VERSION 5.8 ;
BUSBITCHARS "[]" ;
DIVIDERCHAR "/" ;
UNITS
    DATABASE MICRONS 1000 ;
END UNITS

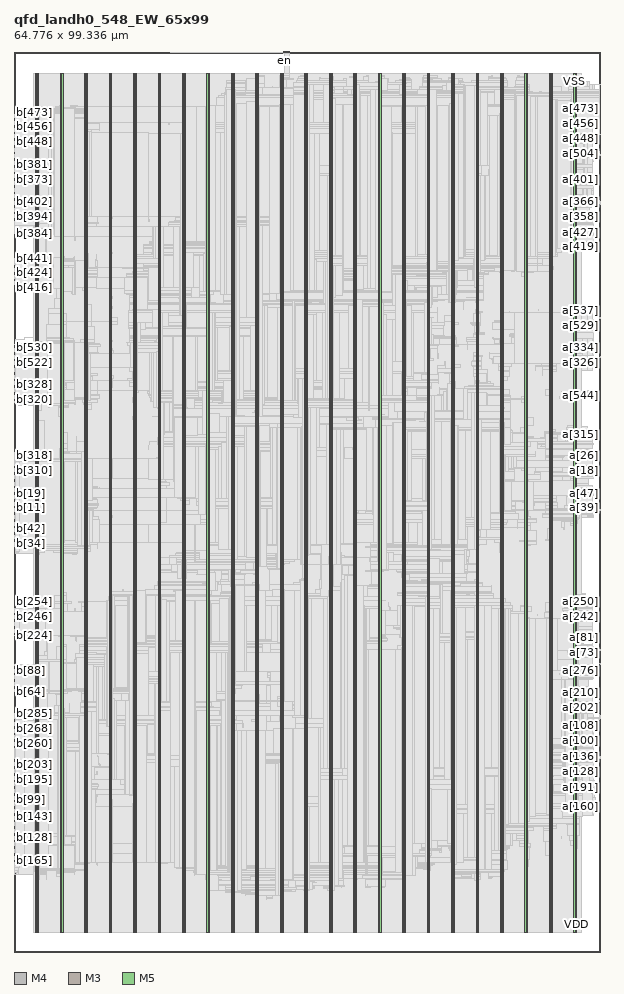
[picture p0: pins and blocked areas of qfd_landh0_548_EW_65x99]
MACRO qfd_landh0_548_EW_65x99
  FOREIGN qfd_landh0_548_EW_65x99 0 0 ;
  CLASS BLOCK ;
  SIZE 64.776 BY 99.336 ;
  PIN a[0]
    DIRECTION INPUT ;
    USE SIGNAL ;
    PORT
      LAYER M4 ;
        RECT  64.692 51.408 64.776 51.432 ;
    END
  END a[0]
  PIN a[100]
    DIRECTION INPUT ;
    USE SIGNAL ;
    PORT
      LAYER M4 ;
        RECT  64.692 23.376 64.776 23.4 ;
    END
  END a[100]
  PIN a[101]
    DIRECTION INPUT ;
    USE SIGNAL ;
    PORT
      LAYER M4 ;
        RECT  64.692 23.472 64.776 23.496 ;
    END
  END a[101]
  PIN a[102]
    DIRECTION INPUT ;
    USE SIGNAL ;
    PORT
      LAYER M4 ;
        RECT  64.692 23.568 64.776 23.592 ;
    END
  END a[102]
  PIN a[103]
    DIRECTION INPUT ;
    USE SIGNAL ;
    PORT
      LAYER M4 ;
        RECT  64.692 23.664 64.776 23.688 ;
    END
  END a[103]
  PIN a[104]
    DIRECTION INPUT ;
    USE SIGNAL ;
    PORT
      LAYER M4 ;
        RECT  64.692 23.76 64.776 23.784 ;
    END
  END a[104]
  PIN a[105]
    DIRECTION INPUT ;
    USE SIGNAL ;
    PORT
      LAYER M4 ;
        RECT  64.692 23.856 64.776 23.88 ;
    END
  END a[105]
  PIN a[106]
    DIRECTION INPUT ;
    USE SIGNAL ;
    PORT
      LAYER M4 ;
        RECT  64.692 23.952 64.776 23.976 ;
    END
  END a[106]
  PIN a[107]
    DIRECTION INPUT ;
    USE SIGNAL ;
    PORT
      LAYER M4 ;
        RECT  64.692 24.048 64.776 24.072 ;
    END
  END a[107]
  PIN a[108]
    DIRECTION INPUT ;
    USE SIGNAL ;
    PORT
      LAYER M4 ;
        RECT  64.692 24.144 64.776 24.168 ;
    END
  END a[108]
  PIN a[109]
    DIRECTION INPUT ;
    USE SIGNAL ;
    PORT
      LAYER M4 ;
        RECT  64.692 24.24 64.776 24.264 ;
    END
  END a[109]
  PIN a[10]
    DIRECTION INPUT ;
    USE SIGNAL ;
    PORT
      LAYER M4 ;
        RECT  64.692 52.368 64.776 52.392 ;
    END
  END a[10]
  PIN a[110]
    DIRECTION INPUT ;
    USE SIGNAL ;
    PORT
      LAYER M4 ;
        RECT  64.692 24.336 64.776 24.36 ;
    END
  END a[110]
  PIN a[111]
    DIRECTION INPUT ;
    USE SIGNAL ;
    PORT
      LAYER M4 ;
        RECT  64.692 24.432 64.776 24.456 ;
    END
  END a[111]
  PIN a[112]
    DIRECTION INPUT ;
    USE SIGNAL ;
    PORT
      LAYER M4 ;
        RECT  64.692 24.528 64.776 24.552 ;
    END
  END a[112]
  PIN a[113]
    DIRECTION INPUT ;
    USE SIGNAL ;
    PORT
      LAYER M4 ;
        RECT  64.692 24.624 64.776 24.648 ;
    END
  END a[113]
  PIN a[114]
    DIRECTION INPUT ;
    USE SIGNAL ;
    PORT
      LAYER M4 ;
        RECT  64.692 24.72 64.776 24.744 ;
    END
  END a[114]
  PIN a[115]
    DIRECTION INPUT ;
    USE SIGNAL ;
    PORT
      LAYER M4 ;
        RECT  64.692 24.816 64.776 24.84 ;
    END
  END a[115]
  PIN a[116]
    DIRECTION INPUT ;
    USE SIGNAL ;
    PORT
      LAYER M4 ;
        RECT  64.692 24.912 64.776 24.936 ;
    END
  END a[116]
  PIN a[117]
    DIRECTION INPUT ;
    USE SIGNAL ;
    PORT
      LAYER M4 ;
        RECT  64.692 25.008 64.776 25.032 ;
    END
  END a[117]
  PIN a[118]
    DIRECTION INPUT ;
    USE SIGNAL ;
    PORT
      LAYER M4 ;
        RECT  64.692 25.104 64.776 25.128 ;
    END
  END a[118]
  PIN a[119]
    DIRECTION INPUT ;
    USE SIGNAL ;
    PORT
      LAYER M4 ;
        RECT  64.692 25.2 64.776 25.224 ;
    END
  END a[119]
  PIN a[11]
    DIRECTION INPUT ;
    USE SIGNAL ;
    PORT
      LAYER M4 ;
        RECT  64.692 52.464 64.776 52.488 ;
    END
  END a[11]
  PIN a[120]
    DIRECTION INPUT ;
    USE SIGNAL ;
    PORT
      LAYER M4 ;
        RECT  64.692 25.296 64.776 25.32 ;
    END
  END a[120]
  PIN a[121]
    DIRECTION INPUT ;
    USE SIGNAL ;
    PORT
      LAYER M4 ;
        RECT  64.692 25.392 64.776 25.416 ;
    END
  END a[121]
  PIN a[122]
    DIRECTION INPUT ;
    USE SIGNAL ;
    PORT
      LAYER M4 ;
        RECT  64.692 25.488 64.776 25.512 ;
    END
  END a[122]
  PIN a[123]
    DIRECTION INPUT ;
    USE SIGNAL ;
    PORT
      LAYER M4 ;
        RECT  64.692 25.584 64.776 25.608 ;
    END
  END a[123]
  PIN a[124]
    DIRECTION INPUT ;
    USE SIGNAL ;
    PORT
      LAYER M4 ;
        RECT  64.692 25.68 64.776 25.704 ;
    END
  END a[124]
  PIN a[125]
    DIRECTION INPUT ;
    USE SIGNAL ;
    PORT
      LAYER M4 ;
        RECT  64.692 25.776 64.776 25.8 ;
    END
  END a[125]
  PIN a[126]
    DIRECTION INPUT ;
    USE SIGNAL ;
    PORT
      LAYER M4 ;
        RECT  64.692 25.872 64.776 25.896 ;
    END
  END a[126]
  PIN a[127]
    DIRECTION INPUT ;
    USE SIGNAL ;
    PORT
      LAYER M4 ;
        RECT  64.692 25.968 64.776 25.992 ;
    END
  END a[127]
  PIN a[128]
    DIRECTION INPUT ;
    USE SIGNAL ;
    PORT
      LAYER M4 ;
        RECT  64.692 19.92 64.776 19.944 ;
    END
  END a[128]
  PIN a[129]
    DIRECTION INPUT ;
    USE SIGNAL ;
    PORT
      LAYER M4 ;
        RECT  64.692 20.016 64.776 20.04 ;
    END
  END a[129]
  PIN a[12]
    DIRECTION INPUT ;
    USE SIGNAL ;
    PORT
      LAYER M4 ;
        RECT  64.692 52.56 64.776 52.584 ;
    END
  END a[12]
  PIN a[130]
    DIRECTION INPUT ;
    USE SIGNAL ;
    PORT
      LAYER M4 ;
        RECT  64.692 20.112 64.776 20.136 ;
    END
  END a[130]
  PIN a[131]
    DIRECTION INPUT ;
    USE SIGNAL ;
    PORT
      LAYER M4 ;
        RECT  64.692 20.208 64.776 20.232 ;
    END
  END a[131]
  PIN a[132]
    DIRECTION INPUT ;
    USE SIGNAL ;
    PORT
      LAYER M4 ;
        RECT  64.692 20.304 64.776 20.328 ;
    END
  END a[132]
  PIN a[133]
    DIRECTION INPUT ;
    USE SIGNAL ;
    PORT
      LAYER M4 ;
        RECT  64.692 20.4 64.776 20.424 ;
    END
  END a[133]
  PIN a[134]
    DIRECTION INPUT ;
    USE SIGNAL ;
    PORT
      LAYER M4 ;
        RECT  64.692 20.496 64.776 20.52 ;
    END
  END a[134]
  PIN a[135]
    DIRECTION INPUT ;
    USE SIGNAL ;
    PORT
      LAYER M4 ;
        RECT  64.692 20.592 64.776 20.616 ;
    END
  END a[135]
  PIN a[136]
    DIRECTION INPUT ;
    USE SIGNAL ;
    PORT
      LAYER M4 ;
        RECT  64.692 20.688 64.776 20.712 ;
    END
  END a[136]
  PIN a[137]
    DIRECTION INPUT ;
    USE SIGNAL ;
    PORT
      LAYER M4 ;
        RECT  64.692 20.784 64.776 20.808 ;
    END
  END a[137]
  PIN a[138]
    DIRECTION INPUT ;
    USE SIGNAL ;
    PORT
      LAYER M4 ;
        RECT  64.692 20.88 64.776 20.904 ;
    END
  END a[138]
  PIN a[139]
    DIRECTION INPUT ;
    USE SIGNAL ;
    PORT
      LAYER M4 ;
        RECT  64.692 20.976 64.776 21 ;
    END
  END a[139]
  PIN a[13]
    DIRECTION INPUT ;
    USE SIGNAL ;
    PORT
      LAYER M4 ;
        RECT  64.692 52.656 64.776 52.68 ;
    END
  END a[13]
  PIN a[140]
    DIRECTION INPUT ;
    USE SIGNAL ;
    PORT
      LAYER M4 ;
        RECT  64.692 21.072 64.776 21.096 ;
    END
  END a[140]
  PIN a[141]
    DIRECTION INPUT ;
    USE SIGNAL ;
    PORT
      LAYER M4 ;
        RECT  64.692 21.168 64.776 21.192 ;
    END
  END a[141]
  PIN a[142]
    DIRECTION INPUT ;
    USE SIGNAL ;
    PORT
      LAYER M4 ;
        RECT  64.692 21.264 64.776 21.288 ;
    END
  END a[142]
  PIN a[143]
    DIRECTION INPUT ;
    USE SIGNAL ;
    PORT
      LAYER M4 ;
        RECT  64.692 21.36 64.776 21.384 ;
    END
  END a[143]
  PIN a[144]
    DIRECTION INPUT ;
    USE SIGNAL ;
    PORT
      LAYER M4 ;
        RECT  64.692 21.456 64.776 21.48 ;
    END
  END a[144]
  PIN a[145]
    DIRECTION INPUT ;
    USE SIGNAL ;
    PORT
      LAYER M4 ;
        RECT  64.692 21.552 64.776 21.576 ;
    END
  END a[145]
  PIN a[146]
    DIRECTION INPUT ;
    USE SIGNAL ;
    PORT
      LAYER M4 ;
        RECT  64.692 21.648 64.776 21.672 ;
    END
  END a[146]
  PIN a[147]
    DIRECTION INPUT ;
    USE SIGNAL ;
    PORT
      LAYER M4 ;
        RECT  64.692 21.744 64.776 21.768 ;
    END
  END a[147]
  PIN a[148]
    DIRECTION INPUT ;
    USE SIGNAL ;
    PORT
      LAYER M4 ;
        RECT  64.692 21.84 64.776 21.864 ;
    END
  END a[148]
  PIN a[149]
    DIRECTION INPUT ;
    USE SIGNAL ;
    PORT
      LAYER M4 ;
        RECT  64.692 21.936 64.776 21.96 ;
    END
  END a[149]
  PIN a[14]
    DIRECTION INPUT ;
    USE SIGNAL ;
    PORT
      LAYER M4 ;
        RECT  64.692 52.752 64.776 52.776 ;
    END
  END a[14]
  PIN a[150]
    DIRECTION INPUT ;
    USE SIGNAL ;
    PORT
      LAYER M4 ;
        RECT  64.692 22.032 64.776 22.056 ;
    END
  END a[150]
  PIN a[151]
    DIRECTION INPUT ;
    USE SIGNAL ;
    PORT
      LAYER M4 ;
        RECT  64.692 22.128 64.776 22.152 ;
    END
  END a[151]
  PIN a[152]
    DIRECTION INPUT ;
    USE SIGNAL ;
    PORT
      LAYER M4 ;
        RECT  64.692 22.224 64.776 22.248 ;
    END
  END a[152]
  PIN a[153]
    DIRECTION INPUT ;
    USE SIGNAL ;
    PORT
      LAYER M4 ;
        RECT  64.692 22.32 64.776 22.344 ;
    END
  END a[153]
  PIN a[154]
    DIRECTION INPUT ;
    USE SIGNAL ;
    PORT
      LAYER M4 ;
        RECT  64.692 22.416 64.776 22.44 ;
    END
  END a[154]
  PIN a[155]
    DIRECTION INPUT ;
    USE SIGNAL ;
    PORT
      LAYER M4 ;
        RECT  64.692 22.512 64.776 22.536 ;
    END
  END a[155]
  PIN a[156]
    DIRECTION INPUT ;
    USE SIGNAL ;
    PORT
      LAYER M4 ;
        RECT  64.692 22.608 64.776 22.632 ;
    END
  END a[156]
  PIN a[157]
    DIRECTION INPUT ;
    USE SIGNAL ;
    PORT
      LAYER M4 ;
        RECT  64.692 22.704 64.776 22.728 ;
    END
  END a[157]
  PIN a[158]
    DIRECTION INPUT ;
    USE SIGNAL ;
    PORT
      LAYER M4 ;
        RECT  64.692 22.8 64.776 22.824 ;
    END
  END a[158]
  PIN a[159]
    DIRECTION INPUT ;
    USE SIGNAL ;
    PORT
      LAYER M4 ;
        RECT  64.692 22.896 64.776 22.92 ;
    END
  END a[159]
  PIN a[15]
    DIRECTION INPUT ;
    USE SIGNAL ;
    PORT
      LAYER M4 ;
        RECT  64.692 52.848 64.776 52.872 ;
    END
  END a[15]
  PIN a[160]
    DIRECTION INPUT ;
    USE SIGNAL ;
    PORT
      LAYER M4 ;
        RECT  64.692 16.08 64.776 16.104 ;
    END
  END a[160]
  PIN a[161]
    DIRECTION INPUT ;
    USE SIGNAL ;
    PORT
      LAYER M4 ;
        RECT  64.692 16.176 64.776 16.2 ;
    END
  END a[161]
  PIN a[162]
    DIRECTION INPUT ;
    USE SIGNAL ;
    PORT
      LAYER M4 ;
        RECT  64.692 16.272 64.776 16.296 ;
    END
  END a[162]
  PIN a[163]
    DIRECTION INPUT ;
    USE SIGNAL ;
    PORT
      LAYER M4 ;
        RECT  64.692 16.368 64.776 16.392 ;
    END
  END a[163]
  PIN a[164]
    DIRECTION INPUT ;
    USE SIGNAL ;
    PORT
      LAYER M4 ;
        RECT  64.692 16.464 64.776 16.488 ;
    END
  END a[164]
  PIN a[165]
    DIRECTION INPUT ;
    USE SIGNAL ;
    PORT
      LAYER M4 ;
        RECT  64.692 16.56 64.776 16.584 ;
    END
  END a[165]
  PIN a[166]
    DIRECTION INPUT ;
    USE SIGNAL ;
    PORT
      LAYER M4 ;
        RECT  64.692 16.656 64.776 16.68 ;
    END
  END a[166]
  PIN a[167]
    DIRECTION INPUT ;
    USE SIGNAL ;
    PORT
      LAYER M4 ;
        RECT  64.692 16.752 64.776 16.776 ;
    END
  END a[167]
  PIN a[168]
    DIRECTION INPUT ;
    USE SIGNAL ;
    PORT
      LAYER M4 ;
        RECT  64.692 16.848 64.776 16.872 ;
    END
  END a[168]
  PIN a[169]
    DIRECTION INPUT ;
    USE SIGNAL ;
    PORT
      LAYER M4 ;
        RECT  64.692 16.944 64.776 16.968 ;
    END
  END a[169]
  PIN a[16]
    DIRECTION INPUT ;
    USE SIGNAL ;
    PORT
      LAYER M4 ;
        RECT  64.692 52.944 64.776 52.968 ;
    END
  END a[16]
  PIN a[170]
    DIRECTION INPUT ;
    USE SIGNAL ;
    PORT
      LAYER M4 ;
        RECT  64.692 17.04 64.776 17.064 ;
    END
  END a[170]
  PIN a[171]
    DIRECTION INPUT ;
    USE SIGNAL ;
    PORT
      LAYER M4 ;
        RECT  64.692 17.136 64.776 17.16 ;
    END
  END a[171]
  PIN a[172]
    DIRECTION INPUT ;
    USE SIGNAL ;
    PORT
      LAYER M4 ;
        RECT  64.692 17.232 64.776 17.256 ;
    END
  END a[172]
  PIN a[173]
    DIRECTION INPUT ;
    USE SIGNAL ;
    PORT
      LAYER M4 ;
        RECT  64.692 17.328 64.776 17.352 ;
    END
  END a[173]
  PIN a[174]
    DIRECTION INPUT ;
    USE SIGNAL ;
    PORT
      LAYER M4 ;
        RECT  64.692 17.424 64.776 17.448 ;
    END
  END a[174]
  PIN a[175]
    DIRECTION INPUT ;
    USE SIGNAL ;
    PORT
      LAYER M4 ;
        RECT  64.692 17.52 64.776 17.544 ;
    END
  END a[175]
  PIN a[176]
    DIRECTION INPUT ;
    USE SIGNAL ;
    PORT
      LAYER M4 ;
        RECT  64.692 17.616 64.776 17.64 ;
    END
  END a[176]
  PIN a[177]
    DIRECTION INPUT ;
    USE SIGNAL ;
    PORT
      LAYER M4 ;
        RECT  64.692 17.712 64.776 17.736 ;
    END
  END a[177]
  PIN a[178]
    DIRECTION INPUT ;
    USE SIGNAL ;
    PORT
      LAYER M4 ;
        RECT  64.692 17.808 64.776 17.832 ;
    END
  END a[178]
  PIN a[179]
    DIRECTION INPUT ;
    USE SIGNAL ;
    PORT
      LAYER M4 ;
        RECT  64.692 17.904 64.776 17.928 ;
    END
  END a[179]
  PIN a[17]
    DIRECTION INPUT ;
    USE SIGNAL ;
    PORT
      LAYER M4 ;
        RECT  64.692 53.04 64.776 53.064 ;
    END
  END a[17]
  PIN a[180]
    DIRECTION INPUT ;
    USE SIGNAL ;
    PORT
      LAYER M4 ;
        RECT  64.692 18 64.776 18.024 ;
    END
  END a[180]
  PIN a[181]
    DIRECTION INPUT ;
    USE SIGNAL ;
    PORT
      LAYER M4 ;
        RECT  64.692 18.096 64.776 18.12 ;
    END
  END a[181]
  PIN a[182]
    DIRECTION INPUT ;
    USE SIGNAL ;
    PORT
      LAYER M4 ;
        RECT  64.692 18.192 64.776 18.216 ;
    END
  END a[182]
  PIN a[183]
    DIRECTION INPUT ;
    USE SIGNAL ;
    PORT
      LAYER M4 ;
        RECT  64.692 18.288 64.776 18.312 ;
    END
  END a[183]
  PIN a[184]
    DIRECTION INPUT ;
    USE SIGNAL ;
    PORT
      LAYER M4 ;
        RECT  64.692 18.384 64.776 18.408 ;
    END
  END a[184]
  PIN a[185]
    DIRECTION INPUT ;
    USE SIGNAL ;
    PORT
      LAYER M4 ;
        RECT  64.692 18.48 64.776 18.504 ;
    END
  END a[185]
  PIN a[186]
    DIRECTION INPUT ;
    USE SIGNAL ;
    PORT
      LAYER M4 ;
        RECT  64.692 18.576 64.776 18.6 ;
    END
  END a[186]
  PIN a[187]
    DIRECTION INPUT ;
    USE SIGNAL ;
    PORT
      LAYER M4 ;
        RECT  64.692 18.672 64.776 18.696 ;
    END
  END a[187]
  PIN a[188]
    DIRECTION INPUT ;
    USE SIGNAL ;
    PORT
      LAYER M4 ;
        RECT  64.692 18.768 64.776 18.792 ;
    END
  END a[188]
  PIN a[189]
    DIRECTION INPUT ;
    USE SIGNAL ;
    PORT
      LAYER M4 ;
        RECT  64.692 18.864 64.776 18.888 ;
    END
  END a[189]
  PIN a[18]
    DIRECTION INPUT ;
    USE SIGNAL ;
    PORT
      LAYER M4 ;
        RECT  64.692 53.136 64.776 53.16 ;
    END
  END a[18]
  PIN a[190]
    DIRECTION INPUT ;
    USE SIGNAL ;
    PORT
      LAYER M4 ;
        RECT  64.692 18.96 64.776 18.984 ;
    END
  END a[190]
  PIN a[191]
    DIRECTION INPUT ;
    USE SIGNAL ;
    PORT
      LAYER M4 ;
        RECT  64.692 19.056 64.776 19.08 ;
    END
  END a[191]
  PIN a[192]
    DIRECTION INPUT ;
    USE SIGNAL ;
    PORT
      LAYER M4 ;
        RECT  64.692 26.064 64.776 26.088 ;
    END
  END a[192]
  PIN a[193]
    DIRECTION INPUT ;
    USE SIGNAL ;
    PORT
      LAYER M4 ;
        RECT  64.692 26.16 64.776 26.184 ;
    END
  END a[193]
  PIN a[194]
    DIRECTION INPUT ;
    USE SIGNAL ;
    PORT
      LAYER M4 ;
        RECT  64.692 26.256 64.776 26.28 ;
    END
  END a[194]
  PIN a[195]
    DIRECTION INPUT ;
    USE SIGNAL ;
    PORT
      LAYER M4 ;
        RECT  64.692 26.352 64.776 26.376 ;
    END
  END a[195]
  PIN a[196]
    DIRECTION INPUT ;
    USE SIGNAL ;
    PORT
      LAYER M4 ;
        RECT  64.692 26.448 64.776 26.472 ;
    END
  END a[196]
  PIN a[197]
    DIRECTION INPUT ;
    USE SIGNAL ;
    PORT
      LAYER M4 ;
        RECT  64.692 26.544 64.776 26.568 ;
    END
  END a[197]
  PIN a[198]
    DIRECTION INPUT ;
    USE SIGNAL ;
    PORT
      LAYER M4 ;
        RECT  64.692 26.64 64.776 26.664 ;
    END
  END a[198]
  PIN a[199]
    DIRECTION INPUT ;
    USE SIGNAL ;
    PORT
      LAYER M4 ;
        RECT  64.692 26.736 64.776 26.76 ;
    END
  END a[199]
  PIN a[19]
    DIRECTION INPUT ;
    USE SIGNAL ;
    PORT
      LAYER M4 ;
        RECT  64.692 53.232 64.776 53.256 ;
    END
  END a[19]
  PIN a[1]
    DIRECTION INPUT ;
    USE SIGNAL ;
    PORT
      LAYER M4 ;
        RECT  64.692 51.504 64.776 51.528 ;
    END
  END a[1]
  PIN a[200]
    DIRECTION INPUT ;
    USE SIGNAL ;
    PORT
      LAYER M4 ;
        RECT  64.692 26.832 64.776 26.856 ;
    END
  END a[200]
  PIN a[201]
    DIRECTION INPUT ;
    USE SIGNAL ;
    PORT
      LAYER M4 ;
        RECT  64.692 26.928 64.776 26.952 ;
    END
  END a[201]
  PIN a[202]
    DIRECTION INPUT ;
    USE SIGNAL ;
    PORT
      LAYER M4 ;
        RECT  64.692 27.024 64.776 27.048 ;
    END
  END a[202]
  PIN a[203]
    DIRECTION INPUT ;
    USE SIGNAL ;
    PORT
      LAYER M4 ;
        RECT  64.692 27.12 64.776 27.144 ;
    END
  END a[203]
  PIN a[204]
    DIRECTION INPUT ;
    USE SIGNAL ;
    PORT
      LAYER M4 ;
        RECT  64.692 27.216 64.776 27.24 ;
    END
  END a[204]
  PIN a[205]
    DIRECTION INPUT ;
    USE SIGNAL ;
    PORT
      LAYER M4 ;
        RECT  64.692 27.312 64.776 27.336 ;
    END
  END a[205]
  PIN a[206]
    DIRECTION INPUT ;
    USE SIGNAL ;
    PORT
      LAYER M4 ;
        RECT  64.692 27.408 64.776 27.432 ;
    END
  END a[206]
  PIN a[207]
    DIRECTION INPUT ;
    USE SIGNAL ;
    PORT
      LAYER M4 ;
        RECT  64.692 27.504 64.776 27.528 ;
    END
  END a[207]
  PIN a[208]
    DIRECTION INPUT ;
    USE SIGNAL ;
    PORT
      LAYER M4 ;
        RECT  64.692 27.6 64.776 27.624 ;
    END
  END a[208]
  PIN a[209]
    DIRECTION INPUT ;
    USE SIGNAL ;
    PORT
      LAYER M4 ;
        RECT  64.692 27.696 64.776 27.72 ;
    END
  END a[209]
  PIN a[20]
    DIRECTION INPUT ;
    USE SIGNAL ;
    PORT
      LAYER M4 ;
        RECT  64.692 53.328 64.776 53.352 ;
    END
  END a[20]
  PIN a[210]
    DIRECTION INPUT ;
    USE SIGNAL ;
    PORT
      LAYER M4 ;
        RECT  64.692 27.792 64.776 27.816 ;
    END
  END a[210]
  PIN a[211]
    DIRECTION INPUT ;
    USE SIGNAL ;
    PORT
      LAYER M4 ;
        RECT  64.692 27.888 64.776 27.912 ;
    END
  END a[211]
  PIN a[212]
    DIRECTION INPUT ;
    USE SIGNAL ;
    PORT
      LAYER M4 ;
        RECT  64.692 27.984 64.776 28.008 ;
    END
  END a[212]
  PIN a[213]
    DIRECTION INPUT ;
    USE SIGNAL ;
    PORT
      LAYER M4 ;
        RECT  64.692 28.08 64.776 28.104 ;
    END
  END a[213]
  PIN a[214]
    DIRECTION INPUT ;
    USE SIGNAL ;
    PORT
      LAYER M4 ;
        RECT  64.692 28.176 64.776 28.2 ;
    END
  END a[214]
  PIN a[215]
    DIRECTION INPUT ;
    USE SIGNAL ;
    PORT
      LAYER M4 ;
        RECT  64.692 28.272 64.776 28.296 ;
    END
  END a[215]
  PIN a[216]
    DIRECTION INPUT ;
    USE SIGNAL ;
    PORT
      LAYER M4 ;
        RECT  64.692 28.368 64.776 28.392 ;
    END
  END a[216]
  PIN a[217]
    DIRECTION INPUT ;
    USE SIGNAL ;
    PORT
      LAYER M4 ;
        RECT  64.692 28.464 64.776 28.488 ;
    END
  END a[217]
  PIN a[218]
    DIRECTION INPUT ;
    USE SIGNAL ;
    PORT
      LAYER M4 ;
        RECT  64.692 28.56 64.776 28.584 ;
    END
  END a[218]
  PIN a[219]
    DIRECTION INPUT ;
    USE SIGNAL ;
    PORT
      LAYER M4 ;
        RECT  64.692 28.656 64.776 28.68 ;
    END
  END a[219]
  PIN a[21]
    DIRECTION INPUT ;
    USE SIGNAL ;
    PORT
      LAYER M4 ;
        RECT  64.692 53.424 64.776 53.448 ;
    END
  END a[21]
  PIN a[220]
    DIRECTION INPUT ;
    USE SIGNAL ;
    PORT
      LAYER M4 ;
        RECT  64.692 28.752 64.776 28.776 ;
    END
  END a[220]
  PIN a[221]
    DIRECTION INPUT ;
    USE SIGNAL ;
    PORT
      LAYER M4 ;
        RECT  64.692 28.848 64.776 28.872 ;
    END
  END a[221]
  PIN a[222]
    DIRECTION INPUT ;
    USE SIGNAL ;
    PORT
      LAYER M4 ;
        RECT  64.692 28.944 64.776 28.968 ;
    END
  END a[222]
  PIN a[223]
    DIRECTION INPUT ;
    USE SIGNAL ;
    PORT
      LAYER M4 ;
        RECT  64.692 29.04 64.776 29.064 ;
    END
  END a[223]
  PIN a[224]
    DIRECTION INPUT ;
    USE SIGNAL ;
    PORT
      LAYER M4 ;
        RECT  64.692 35.28 64.776 35.304 ;
    END
  END a[224]
  PIN a[225]
    DIRECTION INPUT ;
    USE SIGNAL ;
    PORT
      LAYER M4 ;
        RECT  64.692 35.376 64.776 35.4 ;
    END
  END a[225]
  PIN a[226]
    DIRECTION INPUT ;
    USE SIGNAL ;
    PORT
      LAYER M4 ;
        RECT  64.692 35.472 64.776 35.496 ;
    END
  END a[226]
  PIN a[227]
    DIRECTION INPUT ;
    USE SIGNAL ;
    PORT
      LAYER M4 ;
        RECT  64.692 35.568 64.776 35.592 ;
    END
  END a[227]
  PIN a[228]
    DIRECTION INPUT ;
    USE SIGNAL ;
    PORT
      LAYER M4 ;
        RECT  64.692 35.664 64.776 35.688 ;
    END
  END a[228]
  PIN a[229]
    DIRECTION INPUT ;
    USE SIGNAL ;
    PORT
      LAYER M4 ;
        RECT  64.692 35.76 64.776 35.784 ;
    END
  END a[229]
  PIN a[22]
    DIRECTION INPUT ;
    USE SIGNAL ;
    PORT
      LAYER M4 ;
        RECT  64.692 53.52 64.776 53.544 ;
    END
  END a[22]
  PIN a[230]
    DIRECTION INPUT ;
    USE SIGNAL ;
    PORT
      LAYER M4 ;
        RECT  64.692 35.856 64.776 35.88 ;
    END
  END a[230]
  PIN a[231]
    DIRECTION INPUT ;
    USE SIGNAL ;
    PORT
      LAYER M4 ;
        RECT  64.692 35.952 64.776 35.976 ;
    END
  END a[231]
  PIN a[232]
    DIRECTION INPUT ;
    USE SIGNAL ;
    PORT
      LAYER M4 ;
        RECT  64.692 36.048 64.776 36.072 ;
    END
  END a[232]
  PIN a[233]
    DIRECTION INPUT ;
    USE SIGNAL ;
    PORT
      LAYER M4 ;
        RECT  64.692 36.144 64.776 36.168 ;
    END
  END a[233]
  PIN a[234]
    DIRECTION INPUT ;
    USE SIGNAL ;
    PORT
      LAYER M4 ;
        RECT  64.692 36.24 64.776 36.264 ;
    END
  END a[234]
  PIN a[235]
    DIRECTION INPUT ;
    USE SIGNAL ;
    PORT
      LAYER M4 ;
        RECT  64.692 36.336 64.776 36.36 ;
    END
  END a[235]
  PIN a[236]
    DIRECTION INPUT ;
    USE SIGNAL ;
    PORT
      LAYER M4 ;
        RECT  64.692 36.432 64.776 36.456 ;
    END
  END a[236]
  PIN a[237]
    DIRECTION INPUT ;
    USE SIGNAL ;
    PORT
      LAYER M4 ;
        RECT  64.692 36.528 64.776 36.552 ;
    END
  END a[237]
  PIN a[238]
    DIRECTION INPUT ;
    USE SIGNAL ;
    PORT
      LAYER M4 ;
        RECT  64.692 36.624 64.776 36.648 ;
    END
  END a[238]
  PIN a[239]
    DIRECTION INPUT ;
    USE SIGNAL ;
    PORT
      LAYER M4 ;
        RECT  64.692 36.72 64.776 36.744 ;
    END
  END a[239]
  PIN a[23]
    DIRECTION INPUT ;
    USE SIGNAL ;
    PORT
      LAYER M4 ;
        RECT  64.692 53.616 64.776 53.64 ;
    END
  END a[23]
  PIN a[240]
    DIRECTION INPUT ;
    USE SIGNAL ;
    PORT
      LAYER M4 ;
        RECT  64.692 36.816 64.776 36.84 ;
    END
  END a[240]
  PIN a[241]
    DIRECTION INPUT ;
    USE SIGNAL ;
    PORT
      LAYER M4 ;
        RECT  64.692 36.912 64.776 36.936 ;
    END
  END a[241]
  PIN a[242]
    DIRECTION INPUT ;
    USE SIGNAL ;
    PORT
      LAYER M4 ;
        RECT  64.692 37.008 64.776 37.032 ;
    END
  END a[242]
  PIN a[243]
    DIRECTION INPUT ;
    USE SIGNAL ;
    PORT
      LAYER M4 ;
        RECT  64.692 37.104 64.776 37.128 ;
    END
  END a[243]
  PIN a[244]
    DIRECTION INPUT ;
    USE SIGNAL ;
    PORT
      LAYER M4 ;
        RECT  64.692 37.2 64.776 37.224 ;
    END
  END a[244]
  PIN a[245]
    DIRECTION INPUT ;
    USE SIGNAL ;
    PORT
      LAYER M4 ;
        RECT  64.692 37.296 64.776 37.32 ;
    END
  END a[245]
  PIN a[246]
    DIRECTION INPUT ;
    USE SIGNAL ;
    PORT
      LAYER M4 ;
        RECT  64.692 37.392 64.776 37.416 ;
    END
  END a[246]
  PIN a[247]
    DIRECTION INPUT ;
    USE SIGNAL ;
    PORT
      LAYER M4 ;
        RECT  64.692 37.488 64.776 37.512 ;
    END
  END a[247]
  PIN a[248]
    DIRECTION INPUT ;
    USE SIGNAL ;
    PORT
      LAYER M4 ;
        RECT  64.692 37.584 64.776 37.608 ;
    END
  END a[248]
  PIN a[249]
    DIRECTION INPUT ;
    USE SIGNAL ;
    PORT
      LAYER M4 ;
        RECT  64.692 37.68 64.776 37.704 ;
    END
  END a[249]
  PIN a[24]
    DIRECTION INPUT ;
    USE SIGNAL ;
    PORT
      LAYER M4 ;
        RECT  64.692 53.712 64.776 53.736 ;
    END
  END a[24]
  PIN a[250]
    DIRECTION INPUT ;
    USE SIGNAL ;
    PORT
      LAYER M4 ;
        RECT  64.692 37.776 64.776 37.8 ;
    END
  END a[250]
  PIN a[251]
    DIRECTION INPUT ;
    USE SIGNAL ;
    PORT
      LAYER M4 ;
        RECT  64.692 37.872 64.776 37.896 ;
    END
  END a[251]
  PIN a[252]
    DIRECTION INPUT ;
    USE SIGNAL ;
    PORT
      LAYER M4 ;
        RECT  64.692 37.968 64.776 37.992 ;
    END
  END a[252]
  PIN a[253]
    DIRECTION INPUT ;
    USE SIGNAL ;
    PORT
      LAYER M4 ;
        RECT  64.692 38.064 64.776 38.088 ;
    END
  END a[253]
  PIN a[254]
    DIRECTION INPUT ;
    USE SIGNAL ;
    PORT
      LAYER M4 ;
        RECT  64.692 38.16 64.776 38.184 ;
    END
  END a[254]
  PIN a[255]
    DIRECTION INPUT ;
    USE SIGNAL ;
    PORT
      LAYER M4 ;
        RECT  64.692 38.256 64.776 38.28 ;
    END
  END a[255]
  PIN a[256]
    DIRECTION INPUT ;
    USE SIGNAL ;
    PORT
      LAYER M4 ;
        RECT  64.692 29.136 64.776 29.16 ;
    END
  END a[256]
  PIN a[257]
    DIRECTION INPUT ;
    USE SIGNAL ;
    PORT
      LAYER M4 ;
        RECT  64.692 29.232 64.776 29.256 ;
    END
  END a[257]
  PIN a[258]
    DIRECTION INPUT ;
    USE SIGNAL ;
    PORT
      LAYER M4 ;
        RECT  64.692 29.328 64.776 29.352 ;
    END
  END a[258]
  PIN a[259]
    DIRECTION INPUT ;
    USE SIGNAL ;
    PORT
      LAYER M4 ;
        RECT  64.692 29.424 64.776 29.448 ;
    END
  END a[259]
  PIN a[25]
    DIRECTION INPUT ;
    USE SIGNAL ;
    PORT
      LAYER M4 ;
        RECT  64.692 53.808 64.776 53.832 ;
    END
  END a[25]
  PIN a[260]
    DIRECTION INPUT ;
    USE SIGNAL ;
    PORT
      LAYER M4 ;
        RECT  64.692 29.52 64.776 29.544 ;
    END
  END a[260]
  PIN a[261]
    DIRECTION INPUT ;
    USE SIGNAL ;
    PORT
      LAYER M4 ;
        RECT  64.692 29.616 64.776 29.64 ;
    END
  END a[261]
  PIN a[262]
    DIRECTION INPUT ;
    USE SIGNAL ;
    PORT
      LAYER M4 ;
        RECT  64.692 29.712 64.776 29.736 ;
    END
  END a[262]
  PIN a[263]
    DIRECTION INPUT ;
    USE SIGNAL ;
    PORT
      LAYER M4 ;
        RECT  64.692 29.808 64.776 29.832 ;
    END
  END a[263]
  PIN a[264]
    DIRECTION INPUT ;
    USE SIGNAL ;
    PORT
      LAYER M4 ;
        RECT  64.692 29.904 64.776 29.928 ;
    END
  END a[264]
  PIN a[265]
    DIRECTION INPUT ;
    USE SIGNAL ;
    PORT
      LAYER M4 ;
        RECT  64.692 30 64.776 30.024 ;
    END
  END a[265]
  PIN a[266]
    DIRECTION INPUT ;
    USE SIGNAL ;
    PORT
      LAYER M4 ;
        RECT  64.692 30.096 64.776 30.12 ;
    END
  END a[266]
  PIN a[267]
    DIRECTION INPUT ;
    USE SIGNAL ;
    PORT
      LAYER M4 ;
        RECT  64.692 30.192 64.776 30.216 ;
    END
  END a[267]
  PIN a[268]
    DIRECTION INPUT ;
    USE SIGNAL ;
    PORT
      LAYER M4 ;
        RECT  64.692 30.288 64.776 30.312 ;
    END
  END a[268]
  PIN a[269]
    DIRECTION INPUT ;
    USE SIGNAL ;
    PORT
      LAYER M4 ;
        RECT  64.692 30.384 64.776 30.408 ;
    END
  END a[269]
  PIN a[26]
    DIRECTION INPUT ;
    USE SIGNAL ;
    PORT
      LAYER M4 ;
        RECT  64.692 53.904 64.776 53.928 ;
    END
  END a[26]
  PIN a[270]
    DIRECTION INPUT ;
    USE SIGNAL ;
    PORT
      LAYER M4 ;
        RECT  64.692 30.48 64.776 30.504 ;
    END
  END a[270]
  PIN a[271]
    DIRECTION INPUT ;
    USE SIGNAL ;
    PORT
      LAYER M4 ;
        RECT  64.692 30.576 64.776 30.6 ;
    END
  END a[271]
  PIN a[272]
    DIRECTION INPUT ;
    USE SIGNAL ;
    PORT
      LAYER M4 ;
        RECT  64.692 30.672 64.776 30.696 ;
    END
  END a[272]
  PIN a[273]
    DIRECTION INPUT ;
    USE SIGNAL ;
    PORT
      LAYER M4 ;
        RECT  64.692 30.768 64.776 30.792 ;
    END
  END a[273]
  PIN a[274]
    DIRECTION INPUT ;
    USE SIGNAL ;
    PORT
      LAYER M4 ;
        RECT  64.692 30.864 64.776 30.888 ;
    END
  END a[274]
  PIN a[275]
    DIRECTION INPUT ;
    USE SIGNAL ;
    PORT
      LAYER M4 ;
        RECT  64.692 30.96 64.776 30.984 ;
    END
  END a[275]
  PIN a[276]
    DIRECTION INPUT ;
    USE SIGNAL ;
    PORT
      LAYER M4 ;
        RECT  64.692 31.056 64.776 31.08 ;
    END
  END a[276]
  PIN a[277]
    DIRECTION INPUT ;
    USE SIGNAL ;
    PORT
      LAYER M4 ;
        RECT  64.692 31.152 64.776 31.176 ;
    END
  END a[277]
  PIN a[278]
    DIRECTION INPUT ;
    USE SIGNAL ;
    PORT
      LAYER M4 ;
        RECT  64.692 31.248 64.776 31.272 ;
    END
  END a[278]
  PIN a[279]
    DIRECTION INPUT ;
    USE SIGNAL ;
    PORT
      LAYER M4 ;
        RECT  64.692 31.344 64.776 31.368 ;
    END
  END a[279]
  PIN a[27]
    DIRECTION INPUT ;
    USE SIGNAL ;
    PORT
      LAYER M4 ;
        RECT  64.692 54 64.776 54.024 ;
    END
  END a[27]
  PIN a[280]
    DIRECTION INPUT ;
    USE SIGNAL ;
    PORT
      LAYER M4 ;
        RECT  64.692 31.44 64.776 31.464 ;
    END
  END a[280]
  PIN a[281]
    DIRECTION INPUT ;
    USE SIGNAL ;
    PORT
      LAYER M4 ;
        RECT  64.692 31.536 64.776 31.56 ;
    END
  END a[281]
  PIN a[282]
    DIRECTION INPUT ;
    USE SIGNAL ;
    PORT
      LAYER M4 ;
        RECT  64.692 31.632 64.776 31.656 ;
    END
  END a[282]
  PIN a[283]
    DIRECTION INPUT ;
    USE SIGNAL ;
    PORT
      LAYER M4 ;
        RECT  64.692 31.728 64.776 31.752 ;
    END
  END a[283]
  PIN a[284]
    DIRECTION INPUT ;
    USE SIGNAL ;
    PORT
      LAYER M4 ;
        RECT  64.692 31.824 64.776 31.848 ;
    END
  END a[284]
  PIN a[285]
    DIRECTION INPUT ;
    USE SIGNAL ;
    PORT
      LAYER M4 ;
        RECT  64.692 31.92 64.776 31.944 ;
    END
  END a[285]
  PIN a[286]
    DIRECTION INPUT ;
    USE SIGNAL ;
    PORT
      LAYER M4 ;
        RECT  64.692 32.016 64.776 32.04 ;
    END
  END a[286]
  PIN a[287]
    DIRECTION INPUT ;
    USE SIGNAL ;
    PORT
      LAYER M4 ;
        RECT  64.692 32.112 64.776 32.136 ;
    END
  END a[287]
  PIN a[288]
    DIRECTION INPUT ;
    USE SIGNAL ;
    PORT
      LAYER M4 ;
        RECT  64.692 54.48 64.776 54.504 ;
    END
  END a[288]
  PIN a[289]
    DIRECTION INPUT ;
    USE SIGNAL ;
    PORT
      LAYER M4 ;
        RECT  64.692 54.576 64.776 54.6 ;
    END
  END a[289]
  PIN a[28]
    DIRECTION INPUT ;
    USE SIGNAL ;
    PORT
      LAYER M4 ;
        RECT  64.692 54.096 64.776 54.12 ;
    END
  END a[28]
  PIN a[290]
    DIRECTION INPUT ;
    USE SIGNAL ;
    PORT
      LAYER M4 ;
        RECT  64.692 54.672 64.776 54.696 ;
    END
  END a[290]
  PIN a[291]
    DIRECTION INPUT ;
    USE SIGNAL ;
    PORT
      LAYER M4 ;
        RECT  64.692 54.768 64.776 54.792 ;
    END
  END a[291]
  PIN a[292]
    DIRECTION INPUT ;
    USE SIGNAL ;
    PORT
      LAYER M4 ;
        RECT  64.692 54.864 64.776 54.888 ;
    END
  END a[292]
  PIN a[293]
    DIRECTION INPUT ;
    USE SIGNAL ;
    PORT
      LAYER M4 ;
        RECT  64.692 54.96 64.776 54.984 ;
    END
  END a[293]
  PIN a[294]
    DIRECTION INPUT ;
    USE SIGNAL ;
    PORT
      LAYER M4 ;
        RECT  64.692 55.056 64.776 55.08 ;
    END
  END a[294]
  PIN a[295]
    DIRECTION INPUT ;
    USE SIGNAL ;
    PORT
      LAYER M4 ;
        RECT  64.692 55.152 64.776 55.176 ;
    END
  END a[295]
  PIN a[296]
    DIRECTION INPUT ;
    USE SIGNAL ;
    PORT
      LAYER M4 ;
        RECT  64.692 55.248 64.776 55.272 ;
    END
  END a[296]
  PIN a[297]
    DIRECTION INPUT ;
    USE SIGNAL ;
    PORT
      LAYER M4 ;
        RECT  64.692 55.344 64.776 55.368 ;
    END
  END a[297]
  PIN a[298]
    DIRECTION INPUT ;
    USE SIGNAL ;
    PORT
      LAYER M4 ;
        RECT  64.692 55.44 64.776 55.464 ;
    END
  END a[298]
  PIN a[299]
    DIRECTION INPUT ;
    USE SIGNAL ;
    PORT
      LAYER M4 ;
        RECT  64.692 55.536 64.776 55.56 ;
    END
  END a[299]
  PIN a[29]
    DIRECTION INPUT ;
    USE SIGNAL ;
    PORT
      LAYER M4 ;
        RECT  64.692 54.192 64.776 54.216 ;
    END
  END a[29]
  PIN a[2]
    DIRECTION INPUT ;
    USE SIGNAL ;
    PORT
      LAYER M4 ;
        RECT  64.692 51.6 64.776 51.624 ;
    END
  END a[2]
  PIN a[300]
    DIRECTION INPUT ;
    USE SIGNAL ;
    PORT
      LAYER M4 ;
        RECT  64.692 55.632 64.776 55.656 ;
    END
  END a[300]
  PIN a[301]
    DIRECTION INPUT ;
    USE SIGNAL ;
    PORT
      LAYER M4 ;
        RECT  64.692 55.728 64.776 55.752 ;
    END
  END a[301]
  PIN a[302]
    DIRECTION INPUT ;
    USE SIGNAL ;
    PORT
      LAYER M4 ;
        RECT  64.692 55.824 64.776 55.848 ;
    END
  END a[302]
  PIN a[303]
    DIRECTION INPUT ;
    USE SIGNAL ;
    PORT
      LAYER M4 ;
        RECT  64.692 55.92 64.776 55.944 ;
    END
  END a[303]
  PIN a[304]
    DIRECTION INPUT ;
    USE SIGNAL ;
    PORT
      LAYER M4 ;
        RECT  64.692 56.016 64.776 56.04 ;
    END
  END a[304]
  PIN a[305]
    DIRECTION INPUT ;
    USE SIGNAL ;
    PORT
      LAYER M4 ;
        RECT  64.692 56.112 64.776 56.136 ;
    END
  END a[305]
  PIN a[306]
    DIRECTION INPUT ;
    USE SIGNAL ;
    PORT
      LAYER M4 ;
        RECT  64.692 56.208 64.776 56.232 ;
    END
  END a[306]
  PIN a[307]
    DIRECTION INPUT ;
    USE SIGNAL ;
    PORT
      LAYER M4 ;
        RECT  64.692 56.304 64.776 56.328 ;
    END
  END a[307]
  PIN a[308]
    DIRECTION INPUT ;
    USE SIGNAL ;
    PORT
      LAYER M4 ;
        RECT  64.692 56.4 64.776 56.424 ;
    END
  END a[308]
  PIN a[309]
    DIRECTION INPUT ;
    USE SIGNAL ;
    PORT
      LAYER M4 ;
        RECT  64.692 56.496 64.776 56.52 ;
    END
  END a[309]
  PIN a[30]
    DIRECTION INPUT ;
    USE SIGNAL ;
    PORT
      LAYER M4 ;
        RECT  64.692 54.288 64.776 54.312 ;
    END
  END a[30]
  PIN a[310]
    DIRECTION INPUT ;
    USE SIGNAL ;
    PORT
      LAYER M4 ;
        RECT  64.692 56.592 64.776 56.616 ;
    END
  END a[310]
  PIN a[311]
    DIRECTION INPUT ;
    USE SIGNAL ;
    PORT
      LAYER M4 ;
        RECT  64.692 56.688 64.776 56.712 ;
    END
  END a[311]
  PIN a[312]
    DIRECTION INPUT ;
    USE SIGNAL ;
    PORT
      LAYER M4 ;
        RECT  64.692 56.784 64.776 56.808 ;
    END
  END a[312]
  PIN a[313]
    DIRECTION INPUT ;
    USE SIGNAL ;
    PORT
      LAYER M4 ;
        RECT  64.692 56.88 64.776 56.904 ;
    END
  END a[313]
  PIN a[314]
    DIRECTION INPUT ;
    USE SIGNAL ;
    PORT
      LAYER M4 ;
        RECT  64.692 56.976 64.776 57 ;
    END
  END a[314]
  PIN a[315]
    DIRECTION INPUT ;
    USE SIGNAL ;
    PORT
      LAYER M4 ;
        RECT  64.692 57.072 64.776 57.096 ;
    END
  END a[315]
  PIN a[316]
    DIRECTION INPUT ;
    USE SIGNAL ;
    PORT
      LAYER M4 ;
        RECT  64.692 57.168 64.776 57.192 ;
    END
  END a[316]
  PIN a[317]
    DIRECTION INPUT ;
    USE SIGNAL ;
    PORT
      LAYER M4 ;
        RECT  64.692 57.264 64.776 57.288 ;
    END
  END a[317]
  PIN a[318]
    DIRECTION INPUT ;
    USE SIGNAL ;
    PORT
      LAYER M4 ;
        RECT  64.692 57.36 64.776 57.384 ;
    END
  END a[318]
  PIN a[319]
    DIRECTION INPUT ;
    USE SIGNAL ;
    PORT
      LAYER M4 ;
        RECT  64.692 57.456 64.776 57.48 ;
    END
  END a[319]
  PIN a[31]
    DIRECTION INPUT ;
    USE SIGNAL ;
    PORT
      LAYER M4 ;
        RECT  64.692 54.384 64.776 54.408 ;
    END
  END a[31]
  PIN a[320]
    DIRECTION INPUT ;
    USE SIGNAL ;
    PORT
      LAYER M4 ;
        RECT  64.692 64.464 64.776 64.488 ;
    END
  END a[320]
  PIN a[321]
    DIRECTION INPUT ;
    USE SIGNAL ;
    PORT
      LAYER M4 ;
        RECT  64.692 64.56 64.776 64.584 ;
    END
  END a[321]
  PIN a[322]
    DIRECTION INPUT ;
    USE SIGNAL ;
    PORT
      LAYER M4 ;
        RECT  64.692 64.656 64.776 64.68 ;
    END
  END a[322]
  PIN a[323]
    DIRECTION INPUT ;
    USE SIGNAL ;
    PORT
      LAYER M4 ;
        RECT  64.692 64.752 64.776 64.776 ;
    END
  END a[323]
  PIN a[324]
    DIRECTION INPUT ;
    USE SIGNAL ;
    PORT
      LAYER M4 ;
        RECT  64.692 64.848 64.776 64.872 ;
    END
  END a[324]
  PIN a[325]
    DIRECTION INPUT ;
    USE SIGNAL ;
    PORT
      LAYER M4 ;
        RECT  64.692 64.944 64.776 64.968 ;
    END
  END a[325]
  PIN a[326]
    DIRECTION INPUT ;
    USE SIGNAL ;
    PORT
      LAYER M4 ;
        RECT  64.692 65.04 64.776 65.064 ;
    END
  END a[326]
  PIN a[327]
    DIRECTION INPUT ;
    USE SIGNAL ;
    PORT
      LAYER M4 ;
        RECT  64.692 65.136 64.776 65.16 ;
    END
  END a[327]
  PIN a[328]
    DIRECTION INPUT ;
    USE SIGNAL ;
    PORT
      LAYER M4 ;
        RECT  64.692 65.232 64.776 65.256 ;
    END
  END a[328]
  PIN a[329]
    DIRECTION INPUT ;
    USE SIGNAL ;
    PORT
      LAYER M4 ;
        RECT  64.692 65.328 64.776 65.352 ;
    END
  END a[329]
  PIN a[32]
    DIRECTION INPUT ;
    USE SIGNAL ;
    PORT
      LAYER M4 ;
        RECT  64.692 48.336 64.776 48.36 ;
    END
  END a[32]
  PIN a[330]
    DIRECTION INPUT ;
    USE SIGNAL ;
    PORT
      LAYER M4 ;
        RECT  64.692 65.424 64.776 65.448 ;
    END
  END a[330]
  PIN a[331]
    DIRECTION INPUT ;
    USE SIGNAL ;
    PORT
      LAYER M4 ;
        RECT  64.692 65.52 64.776 65.544 ;
    END
  END a[331]
  PIN a[332]
    DIRECTION INPUT ;
    USE SIGNAL ;
    PORT
      LAYER M4 ;
        RECT  64.692 65.616 64.776 65.64 ;
    END
  END a[332]
  PIN a[333]
    DIRECTION INPUT ;
    USE SIGNAL ;
    PORT
      LAYER M4 ;
        RECT  64.692 65.712 64.776 65.736 ;
    END
  END a[333]
  PIN a[334]
    DIRECTION INPUT ;
    USE SIGNAL ;
    PORT
      LAYER M4 ;
        RECT  64.692 65.808 64.776 65.832 ;
    END
  END a[334]
  PIN a[335]
    DIRECTION INPUT ;
    USE SIGNAL ;
    PORT
      LAYER M4 ;
        RECT  64.692 65.904 64.776 65.928 ;
    END
  END a[335]
  PIN a[336]
    DIRECTION INPUT ;
    USE SIGNAL ;
    PORT
      LAYER M4 ;
        RECT  64.692 66 64.776 66.024 ;
    END
  END a[336]
  PIN a[337]
    DIRECTION INPUT ;
    USE SIGNAL ;
    PORT
      LAYER M4 ;
        RECT  64.692 66.096 64.776 66.12 ;
    END
  END a[337]
  PIN a[338]
    DIRECTION INPUT ;
    USE SIGNAL ;
    PORT
      LAYER M4 ;
        RECT  64.692 66.192 64.776 66.216 ;
    END
  END a[338]
  PIN a[339]
    DIRECTION INPUT ;
    USE SIGNAL ;
    PORT
      LAYER M4 ;
        RECT  64.692 66.288 64.776 66.312 ;
    END
  END a[339]
  PIN a[33]
    DIRECTION INPUT ;
    USE SIGNAL ;
    PORT
      LAYER M4 ;
        RECT  64.692 48.432 64.776 48.456 ;
    END
  END a[33]
  PIN a[340]
    DIRECTION INPUT ;
    USE SIGNAL ;
    PORT
      LAYER M4 ;
        RECT  64.692 66.384 64.776 66.408 ;
    END
  END a[340]
  PIN a[341]
    DIRECTION INPUT ;
    USE SIGNAL ;
    PORT
      LAYER M4 ;
        RECT  64.692 66.48 64.776 66.504 ;
    END
  END a[341]
  PIN a[342]
    DIRECTION INPUT ;
    USE SIGNAL ;
    PORT
      LAYER M4 ;
        RECT  64.692 66.576 64.776 66.6 ;
    END
  END a[342]
  PIN a[343]
    DIRECTION INPUT ;
    USE SIGNAL ;
    PORT
      LAYER M4 ;
        RECT  64.692 66.672 64.776 66.696 ;
    END
  END a[343]
  PIN a[344]
    DIRECTION INPUT ;
    USE SIGNAL ;
    PORT
      LAYER M4 ;
        RECT  64.692 66.768 64.776 66.792 ;
    END
  END a[344]
  PIN a[345]
    DIRECTION INPUT ;
    USE SIGNAL ;
    PORT
      LAYER M4 ;
        RECT  64.692 66.864 64.776 66.888 ;
    END
  END a[345]
  PIN a[346]
    DIRECTION INPUT ;
    USE SIGNAL ;
    PORT
      LAYER M4 ;
        RECT  64.692 66.96 64.776 66.984 ;
    END
  END a[346]
  PIN a[347]
    DIRECTION INPUT ;
    USE SIGNAL ;
    PORT
      LAYER M4 ;
        RECT  64.692 67.056 64.776 67.08 ;
    END
  END a[347]
  PIN a[348]
    DIRECTION INPUT ;
    USE SIGNAL ;
    PORT
      LAYER M4 ;
        RECT  64.692 67.152 64.776 67.176 ;
    END
  END a[348]
  PIN a[349]
    DIRECTION INPUT ;
    USE SIGNAL ;
    PORT
      LAYER M4 ;
        RECT  64.692 67.248 64.776 67.272 ;
    END
  END a[349]
  PIN a[34]
    DIRECTION INPUT ;
    USE SIGNAL ;
    PORT
      LAYER M4 ;
        RECT  64.692 48.528 64.776 48.552 ;
    END
  END a[34]
  PIN a[350]
    DIRECTION INPUT ;
    USE SIGNAL ;
    PORT
      LAYER M4 ;
        RECT  64.692 67.344 64.776 67.368 ;
    END
  END a[350]
  PIN a[351]
    DIRECTION INPUT ;
    USE SIGNAL ;
    PORT
      LAYER M4 ;
        RECT  64.692 67.44 64.776 67.464 ;
    END
  END a[351]
  PIN a[352]
    DIRECTION INPUT ;
    USE SIGNAL ;
    PORT
      LAYER M4 ;
        RECT  64.692 80.592 64.776 80.616 ;
    END
  END a[352]
  PIN a[353]
    DIRECTION INPUT ;
    USE SIGNAL ;
    PORT
      LAYER M4 ;
        RECT  64.692 80.688 64.776 80.712 ;
    END
  END a[353]
  PIN a[354]
    DIRECTION INPUT ;
    USE SIGNAL ;
    PORT
      LAYER M4 ;
        RECT  64.692 80.784 64.776 80.808 ;
    END
  END a[354]
  PIN a[355]
    DIRECTION INPUT ;
    USE SIGNAL ;
    PORT
      LAYER M4 ;
        RECT  64.692 80.88 64.776 80.904 ;
    END
  END a[355]
  PIN a[356]
    DIRECTION INPUT ;
    USE SIGNAL ;
    PORT
      LAYER M4 ;
        RECT  64.692 80.976 64.776 81 ;
    END
  END a[356]
  PIN a[357]
    DIRECTION INPUT ;
    USE SIGNAL ;
    PORT
      LAYER M4 ;
        RECT  64.692 81.072 64.776 81.096 ;
    END
  END a[357]
  PIN a[358]
    DIRECTION INPUT ;
    USE SIGNAL ;
    PORT
      LAYER M4 ;
        RECT  64.692 81.168 64.776 81.192 ;
    END
  END a[358]
  PIN a[359]
    DIRECTION INPUT ;
    USE SIGNAL ;
    PORT
      LAYER M4 ;
        RECT  64.692 81.264 64.776 81.288 ;
    END
  END a[359]
  PIN a[35]
    DIRECTION INPUT ;
    USE SIGNAL ;
    PORT
      LAYER M4 ;
        RECT  64.692 48.624 64.776 48.648 ;
    END
  END a[35]
  PIN a[360]
    DIRECTION INPUT ;
    USE SIGNAL ;
    PORT
      LAYER M4 ;
        RECT  64.692 81.36 64.776 81.384 ;
    END
  END a[360]
  PIN a[361]
    DIRECTION INPUT ;
    USE SIGNAL ;
    PORT
      LAYER M4 ;
        RECT  64.692 81.456 64.776 81.48 ;
    END
  END a[361]
  PIN a[362]
    DIRECTION INPUT ;
    USE SIGNAL ;
    PORT
      LAYER M4 ;
        RECT  64.692 81.552 64.776 81.576 ;
    END
  END a[362]
  PIN a[363]
    DIRECTION INPUT ;
    USE SIGNAL ;
    PORT
      LAYER M4 ;
        RECT  64.692 81.648 64.776 81.672 ;
    END
  END a[363]
  PIN a[364]
    DIRECTION INPUT ;
    USE SIGNAL ;
    PORT
      LAYER M4 ;
        RECT  64.692 81.744 64.776 81.768 ;
    END
  END a[364]
  PIN a[365]
    DIRECTION INPUT ;
    USE SIGNAL ;
    PORT
      LAYER M4 ;
        RECT  64.692 81.84 64.776 81.864 ;
    END
  END a[365]
  PIN a[366]
    DIRECTION INPUT ;
    USE SIGNAL ;
    PORT
      LAYER M4 ;
        RECT  64.692 81.936 64.776 81.96 ;
    END
  END a[366]
  PIN a[367]
    DIRECTION INPUT ;
    USE SIGNAL ;
    PORT
      LAYER M4 ;
        RECT  64.692 82.032 64.776 82.056 ;
    END
  END a[367]
  PIN a[368]
    DIRECTION INPUT ;
    USE SIGNAL ;
    PORT
      LAYER M4 ;
        RECT  64.692 82.128 64.776 82.152 ;
    END
  END a[368]
  PIN a[369]
    DIRECTION INPUT ;
    USE SIGNAL ;
    PORT
      LAYER M4 ;
        RECT  64.692 82.224 64.776 82.248 ;
    END
  END a[369]
  PIN a[36]
    DIRECTION INPUT ;
    USE SIGNAL ;
    PORT
      LAYER M4 ;
        RECT  64.692 48.72 64.776 48.744 ;
    END
  END a[36]
  PIN a[370]
    DIRECTION INPUT ;
    USE SIGNAL ;
    PORT
      LAYER M4 ;
        RECT  64.692 82.32 64.776 82.344 ;
    END
  END a[370]
  PIN a[371]
    DIRECTION INPUT ;
    USE SIGNAL ;
    PORT
      LAYER M4 ;
        RECT  64.692 82.416 64.776 82.44 ;
    END
  END a[371]
  PIN a[372]
    DIRECTION INPUT ;
    USE SIGNAL ;
    PORT
      LAYER M4 ;
        RECT  64.692 82.512 64.776 82.536 ;
    END
  END a[372]
  PIN a[373]
    DIRECTION INPUT ;
    USE SIGNAL ;
    PORT
      LAYER M4 ;
        RECT  64.692 82.608 64.776 82.632 ;
    END
  END a[373]
  PIN a[374]
    DIRECTION INPUT ;
    USE SIGNAL ;
    PORT
      LAYER M4 ;
        RECT  64.692 82.704 64.776 82.728 ;
    END
  END a[374]
  PIN a[375]
    DIRECTION INPUT ;
    USE SIGNAL ;
    PORT
      LAYER M4 ;
        RECT  64.692 82.8 64.776 82.824 ;
    END
  END a[375]
  PIN a[376]
    DIRECTION INPUT ;
    USE SIGNAL ;
    PORT
      LAYER M4 ;
        RECT  64.692 82.896 64.776 82.92 ;
    END
  END a[376]
  PIN a[377]
    DIRECTION INPUT ;
    USE SIGNAL ;
    PORT
      LAYER M4 ;
        RECT  64.692 82.992 64.776 83.016 ;
    END
  END a[377]
  PIN a[378]
    DIRECTION INPUT ;
    USE SIGNAL ;
    PORT
      LAYER M4 ;
        RECT  64.692 83.088 64.776 83.112 ;
    END
  END a[378]
  PIN a[379]
    DIRECTION INPUT ;
    USE SIGNAL ;
    PORT
      LAYER M4 ;
        RECT  64.692 83.184 64.776 83.208 ;
    END
  END a[379]
  PIN a[37]
    DIRECTION INPUT ;
    USE SIGNAL ;
    PORT
      LAYER M4 ;
        RECT  64.692 48.816 64.776 48.84 ;
    END
  END a[37]
  PIN a[380]
    DIRECTION INPUT ;
    USE SIGNAL ;
    PORT
      LAYER M4 ;
        RECT  64.692 83.28 64.776 83.304 ;
    END
  END a[380]
  PIN a[381]
    DIRECTION INPUT ;
    USE SIGNAL ;
    PORT
      LAYER M4 ;
        RECT  64.692 83.376 64.776 83.4 ;
    END
  END a[381]
  PIN a[382]
    DIRECTION INPUT ;
    USE SIGNAL ;
    PORT
      LAYER M4 ;
        RECT  64.692 83.472 64.776 83.496 ;
    END
  END a[382]
  PIN a[383]
    DIRECTION INPUT ;
    USE SIGNAL ;
    PORT
      LAYER M4 ;
        RECT  64.692 83.568 64.776 83.592 ;
    END
  END a[383]
  PIN a[384]
    DIRECTION INPUT ;
    USE SIGNAL ;
    PORT
      LAYER M4 ;
        RECT  64.692 83.664 64.776 83.688 ;
    END
  END a[384]
  PIN a[385]
    DIRECTION INPUT ;
    USE SIGNAL ;
    PORT
      LAYER M4 ;
        RECT  64.692 83.76 64.776 83.784 ;
    END
  END a[385]
  PIN a[386]
    DIRECTION INPUT ;
    USE SIGNAL ;
    PORT
      LAYER M4 ;
        RECT  64.692 83.856 64.776 83.88 ;
    END
  END a[386]
  PIN a[387]
    DIRECTION INPUT ;
    USE SIGNAL ;
    PORT
      LAYER M4 ;
        RECT  64.692 83.952 64.776 83.976 ;
    END
  END a[387]
  PIN a[388]
    DIRECTION INPUT ;
    USE SIGNAL ;
    PORT
      LAYER M4 ;
        RECT  64.692 84.048 64.776 84.072 ;
    END
  END a[388]
  PIN a[389]
    DIRECTION INPUT ;
    USE SIGNAL ;
    PORT
      LAYER M4 ;
        RECT  64.692 84.144 64.776 84.168 ;
    END
  END a[389]
  PIN a[38]
    DIRECTION INPUT ;
    USE SIGNAL ;
    PORT
      LAYER M4 ;
        RECT  64.692 48.912 64.776 48.936 ;
    END
  END a[38]
  PIN a[390]
    DIRECTION INPUT ;
    USE SIGNAL ;
    PORT
      LAYER M4 ;
        RECT  64.692 84.24 64.776 84.264 ;
    END
  END a[390]
  PIN a[391]
    DIRECTION INPUT ;
    USE SIGNAL ;
    PORT
      LAYER M4 ;
        RECT  64.692 84.336 64.776 84.36 ;
    END
  END a[391]
  PIN a[392]
    DIRECTION INPUT ;
    USE SIGNAL ;
    PORT
      LAYER M4 ;
        RECT  64.692 84.432 64.776 84.456 ;
    END
  END a[392]
  PIN a[393]
    DIRECTION INPUT ;
    USE SIGNAL ;
    PORT
      LAYER M4 ;
        RECT  64.692 84.528 64.776 84.552 ;
    END
  END a[393]
  PIN a[394]
    DIRECTION INPUT ;
    USE SIGNAL ;
    PORT
      LAYER M4 ;
        RECT  64.692 84.624 64.776 84.648 ;
    END
  END a[394]
  PIN a[395]
    DIRECTION INPUT ;
    USE SIGNAL ;
    PORT
      LAYER M4 ;
        RECT  64.692 84.72 64.776 84.744 ;
    END
  END a[395]
  PIN a[396]
    DIRECTION INPUT ;
    USE SIGNAL ;
    PORT
      LAYER M4 ;
        RECT  64.692 84.816 64.776 84.84 ;
    END
  END a[396]
  PIN a[397]
    DIRECTION INPUT ;
    USE SIGNAL ;
    PORT
      LAYER M4 ;
        RECT  64.692 84.912 64.776 84.936 ;
    END
  END a[397]
  PIN a[398]
    DIRECTION INPUT ;
    USE SIGNAL ;
    PORT
      LAYER M4 ;
        RECT  64.692 85.008 64.776 85.032 ;
    END
  END a[398]
  PIN a[399]
    DIRECTION INPUT ;
    USE SIGNAL ;
    PORT
      LAYER M4 ;
        RECT  64.692 85.104 64.776 85.128 ;
    END
  END a[399]
  PIN a[39]
    DIRECTION INPUT ;
    USE SIGNAL ;
    PORT
      LAYER M4 ;
        RECT  64.692 49.008 64.776 49.032 ;
    END
  END a[39]
  PIN a[3]
    DIRECTION INPUT ;
    USE SIGNAL ;
    PORT
      LAYER M4 ;
        RECT  64.692 51.696 64.776 51.72 ;
    END
  END a[3]
  PIN a[400]
    DIRECTION INPUT ;
    USE SIGNAL ;
    PORT
      LAYER M4 ;
        RECT  64.692 85.2 64.776 85.224 ;
    END
  END a[400]
  PIN a[401]
    DIRECTION INPUT ;
    USE SIGNAL ;
    PORT
      LAYER M4 ;
        RECT  64.692 85.296 64.776 85.32 ;
    END
  END a[401]
  PIN a[402]
    DIRECTION INPUT ;
    USE SIGNAL ;
    PORT
      LAYER M4 ;
        RECT  64.692 85.392 64.776 85.416 ;
    END
  END a[402]
  PIN a[403]
    DIRECTION INPUT ;
    USE SIGNAL ;
    PORT
      LAYER M4 ;
        RECT  64.692 85.488 64.776 85.512 ;
    END
  END a[403]
  PIN a[404]
    DIRECTION INPUT ;
    USE SIGNAL ;
    PORT
      LAYER M4 ;
        RECT  64.692 85.584 64.776 85.608 ;
    END
  END a[404]
  PIN a[405]
    DIRECTION INPUT ;
    USE SIGNAL ;
    PORT
      LAYER M4 ;
        RECT  64.692 85.68 64.776 85.704 ;
    END
  END a[405]
  PIN a[406]
    DIRECTION INPUT ;
    USE SIGNAL ;
    PORT
      LAYER M4 ;
        RECT  64.692 85.776 64.776 85.8 ;
    END
  END a[406]
  PIN a[407]
    DIRECTION INPUT ;
    USE SIGNAL ;
    PORT
      LAYER M4 ;
        RECT  64.692 85.872 64.776 85.896 ;
    END
  END a[407]
  PIN a[408]
    DIRECTION INPUT ;
    USE SIGNAL ;
    PORT
      LAYER M4 ;
        RECT  64.692 85.968 64.776 85.992 ;
    END
  END a[408]
  PIN a[409]
    DIRECTION INPUT ;
    USE SIGNAL ;
    PORT
      LAYER M4 ;
        RECT  64.692 86.064 64.776 86.088 ;
    END
  END a[409]
  PIN a[40]
    DIRECTION INPUT ;
    USE SIGNAL ;
    PORT
      LAYER M4 ;
        RECT  64.692 49.104 64.776 49.128 ;
    END
  END a[40]
  PIN a[410]
    DIRECTION INPUT ;
    USE SIGNAL ;
    PORT
      LAYER M4 ;
        RECT  64.692 86.16 64.776 86.184 ;
    END
  END a[410]
  PIN a[411]
    DIRECTION INPUT ;
    USE SIGNAL ;
    PORT
      LAYER M4 ;
        RECT  64.692 86.256 64.776 86.28 ;
    END
  END a[411]
  PIN a[412]
    DIRECTION INPUT ;
    USE SIGNAL ;
    PORT
      LAYER M4 ;
        RECT  64.692 86.352 64.776 86.376 ;
    END
  END a[412]
  PIN a[413]
    DIRECTION INPUT ;
    USE SIGNAL ;
    PORT
      LAYER M4 ;
        RECT  64.692 86.448 64.776 86.472 ;
    END
  END a[413]
  PIN a[414]
    DIRECTION INPUT ;
    USE SIGNAL ;
    PORT
      LAYER M4 ;
        RECT  64.692 86.544 64.776 86.568 ;
    END
  END a[414]
  PIN a[415]
    DIRECTION INPUT ;
    USE SIGNAL ;
    PORT
      LAYER M4 ;
        RECT  64.692 86.64 64.776 86.664 ;
    END
  END a[415]
  PIN a[416]
    DIRECTION INPUT ;
    USE SIGNAL ;
    PORT
      LAYER M4 ;
        RECT  64.692 77.52 64.776 77.544 ;
    END
  END a[416]
  PIN a[417]
    DIRECTION INPUT ;
    USE SIGNAL ;
    PORT
      LAYER M4 ;
        RECT  64.692 77.616 64.776 77.64 ;
    END
  END a[417]
  PIN a[418]
    DIRECTION INPUT ;
    USE SIGNAL ;
    PORT
      LAYER M4 ;
        RECT  64.692 77.712 64.776 77.736 ;
    END
  END a[418]
  PIN a[419]
    DIRECTION INPUT ;
    USE SIGNAL ;
    PORT
      LAYER M4 ;
        RECT  64.692 77.808 64.776 77.832 ;
    END
  END a[419]
  PIN a[41]
    DIRECTION INPUT ;
    USE SIGNAL ;
    PORT
      LAYER M4 ;
        RECT  64.692 49.2 64.776 49.224 ;
    END
  END a[41]
  PIN a[420]
    DIRECTION INPUT ;
    USE SIGNAL ;
    PORT
      LAYER M4 ;
        RECT  64.692 77.904 64.776 77.928 ;
    END
  END a[420]
  PIN a[421]
    DIRECTION INPUT ;
    USE SIGNAL ;
    PORT
      LAYER M4 ;
        RECT  64.692 78 64.776 78.024 ;
    END
  END a[421]
  PIN a[422]
    DIRECTION INPUT ;
    USE SIGNAL ;
    PORT
      LAYER M4 ;
        RECT  64.692 78.096 64.776 78.12 ;
    END
  END a[422]
  PIN a[423]
    DIRECTION INPUT ;
    USE SIGNAL ;
    PORT
      LAYER M4 ;
        RECT  64.692 78.192 64.776 78.216 ;
    END
  END a[423]
  PIN a[424]
    DIRECTION INPUT ;
    USE SIGNAL ;
    PORT
      LAYER M4 ;
        RECT  64.692 78.288 64.776 78.312 ;
    END
  END a[424]
  PIN a[425]
    DIRECTION INPUT ;
    USE SIGNAL ;
    PORT
      LAYER M4 ;
        RECT  64.692 78.384 64.776 78.408 ;
    END
  END a[425]
  PIN a[426]
    DIRECTION INPUT ;
    USE SIGNAL ;
    PORT
      LAYER M4 ;
        RECT  64.692 78.48 64.776 78.504 ;
    END
  END a[426]
  PIN a[427]
    DIRECTION INPUT ;
    USE SIGNAL ;
    PORT
      LAYER M4 ;
        RECT  64.692 78.576 64.776 78.6 ;
    END
  END a[427]
  PIN a[428]
    DIRECTION INPUT ;
    USE SIGNAL ;
    PORT
      LAYER M4 ;
        RECT  64.692 78.672 64.776 78.696 ;
    END
  END a[428]
  PIN a[429]
    DIRECTION INPUT ;
    USE SIGNAL ;
    PORT
      LAYER M4 ;
        RECT  64.692 78.768 64.776 78.792 ;
    END
  END a[429]
  PIN a[42]
    DIRECTION INPUT ;
    USE SIGNAL ;
    PORT
      LAYER M4 ;
        RECT  64.692 49.296 64.776 49.32 ;
    END
  END a[42]
  PIN a[430]
    DIRECTION INPUT ;
    USE SIGNAL ;
    PORT
      LAYER M4 ;
        RECT  64.692 78.864 64.776 78.888 ;
    END
  END a[430]
  PIN a[431]
    DIRECTION INPUT ;
    USE SIGNAL ;
    PORT
      LAYER M4 ;
        RECT  64.692 78.96 64.776 78.984 ;
    END
  END a[431]
  PIN a[432]
    DIRECTION INPUT ;
    USE SIGNAL ;
    PORT
      LAYER M4 ;
        RECT  64.692 79.056 64.776 79.08 ;
    END
  END a[432]
  PIN a[433]
    DIRECTION INPUT ;
    USE SIGNAL ;
    PORT
      LAYER M4 ;
        RECT  64.692 79.152 64.776 79.176 ;
    END
  END a[433]
  PIN a[434]
    DIRECTION INPUT ;
    USE SIGNAL ;
    PORT
      LAYER M4 ;
        RECT  64.692 79.248 64.776 79.272 ;
    END
  END a[434]
  PIN a[435]
    DIRECTION INPUT ;
    USE SIGNAL ;
    PORT
      LAYER M4 ;
        RECT  64.692 79.344 64.776 79.368 ;
    END
  END a[435]
  PIN a[436]
    DIRECTION INPUT ;
    USE SIGNAL ;
    PORT
      LAYER M4 ;
        RECT  64.692 79.44 64.776 79.464 ;
    END
  END a[436]
  PIN a[437]
    DIRECTION INPUT ;
    USE SIGNAL ;
    PORT
      LAYER M4 ;
        RECT  64.692 79.536 64.776 79.56 ;
    END
  END a[437]
  PIN a[438]
    DIRECTION INPUT ;
    USE SIGNAL ;
    PORT
      LAYER M4 ;
        RECT  64.692 79.632 64.776 79.656 ;
    END
  END a[438]
  PIN a[439]
    DIRECTION INPUT ;
    USE SIGNAL ;
    PORT
      LAYER M4 ;
        RECT  64.692 79.728 64.776 79.752 ;
    END
  END a[439]
  PIN a[43]
    DIRECTION INPUT ;
    USE SIGNAL ;
    PORT
      LAYER M4 ;
        RECT  64.692 49.392 64.776 49.416 ;
    END
  END a[43]
  PIN a[440]
    DIRECTION INPUT ;
    USE SIGNAL ;
    PORT
      LAYER M4 ;
        RECT  64.692 79.824 64.776 79.848 ;
    END
  END a[440]
  PIN a[441]
    DIRECTION INPUT ;
    USE SIGNAL ;
    PORT
      LAYER M4 ;
        RECT  64.692 79.92 64.776 79.944 ;
    END
  END a[441]
  PIN a[442]
    DIRECTION INPUT ;
    USE SIGNAL ;
    PORT
      LAYER M4 ;
        RECT  64.692 80.016 64.776 80.04 ;
    END
  END a[442]
  PIN a[443]
    DIRECTION INPUT ;
    USE SIGNAL ;
    PORT
      LAYER M4 ;
        RECT  64.692 80.112 64.776 80.136 ;
    END
  END a[443]
  PIN a[444]
    DIRECTION INPUT ;
    USE SIGNAL ;
    PORT
      LAYER M4 ;
        RECT  64.692 80.208 64.776 80.232 ;
    END
  END a[444]
  PIN a[445]
    DIRECTION INPUT ;
    USE SIGNAL ;
    PORT
      LAYER M4 ;
        RECT  64.692 80.304 64.776 80.328 ;
    END
  END a[445]
  PIN a[446]
    DIRECTION INPUT ;
    USE SIGNAL ;
    PORT
      LAYER M4 ;
        RECT  64.692 80.4 64.776 80.424 ;
    END
  END a[446]
  PIN a[447]
    DIRECTION INPUT ;
    USE SIGNAL ;
    PORT
      LAYER M4 ;
        RECT  64.692 80.496 64.776 80.52 ;
    END
  END a[447]
  PIN a[448]
    DIRECTION INPUT ;
    USE SIGNAL ;
    PORT
      LAYER M4 ;
        RECT  64.692 89.808 64.776 89.832 ;
    END
  END a[448]
  PIN a[449]
    DIRECTION INPUT ;
    USE SIGNAL ;
    PORT
      LAYER M4 ;
        RECT  64.692 89.904 64.776 89.928 ;
    END
  END a[449]
  PIN a[44]
    DIRECTION INPUT ;
    USE SIGNAL ;
    PORT
      LAYER M4 ;
        RECT  64.692 49.488 64.776 49.512 ;
    END
  END a[44]
  PIN a[450]
    DIRECTION INPUT ;
    USE SIGNAL ;
    PORT
      LAYER M4 ;
        RECT  64.692 90 64.776 90.024 ;
    END
  END a[450]
  PIN a[451]
    DIRECTION INPUT ;
    USE SIGNAL ;
    PORT
      LAYER M4 ;
        RECT  64.692 90.096 64.776 90.12 ;
    END
  END a[451]
  PIN a[452]
    DIRECTION INPUT ;
    USE SIGNAL ;
    PORT
      LAYER M4 ;
        RECT  64.692 90.192 64.776 90.216 ;
    END
  END a[452]
  PIN a[453]
    DIRECTION INPUT ;
    USE SIGNAL ;
    PORT
      LAYER M4 ;
        RECT  64.692 90.288 64.776 90.312 ;
    END
  END a[453]
  PIN a[454]
    DIRECTION INPUT ;
    USE SIGNAL ;
    PORT
      LAYER M4 ;
        RECT  64.692 90.384 64.776 90.408 ;
    END
  END a[454]
  PIN a[455]
    DIRECTION INPUT ;
    USE SIGNAL ;
    PORT
      LAYER M4 ;
        RECT  64.692 90.48 64.776 90.504 ;
    END
  END a[455]
  PIN a[456]
    DIRECTION INPUT ;
    USE SIGNAL ;
    PORT
      LAYER M4 ;
        RECT  64.692 90.576 64.776 90.6 ;
    END
  END a[456]
  PIN a[457]
    DIRECTION INPUT ;
    USE SIGNAL ;
    PORT
      LAYER M4 ;
        RECT  64.692 90.672 64.776 90.696 ;
    END
  END a[457]
  PIN a[458]
    DIRECTION INPUT ;
    USE SIGNAL ;
    PORT
      LAYER M4 ;
        RECT  64.692 90.768 64.776 90.792 ;
    END
  END a[458]
  PIN a[459]
    DIRECTION INPUT ;
    USE SIGNAL ;
    PORT
      LAYER M4 ;
        RECT  64.692 90.864 64.776 90.888 ;
    END
  END a[459]
  PIN a[45]
    DIRECTION INPUT ;
    USE SIGNAL ;
    PORT
      LAYER M4 ;
        RECT  64.692 49.584 64.776 49.608 ;
    END
  END a[45]
  PIN a[460]
    DIRECTION INPUT ;
    USE SIGNAL ;
    PORT
      LAYER M4 ;
        RECT  64.692 90.96 64.776 90.984 ;
    END
  END a[460]
  PIN a[461]
    DIRECTION INPUT ;
    USE SIGNAL ;
    PORT
      LAYER M4 ;
        RECT  64.692 91.056 64.776 91.08 ;
    END
  END a[461]
  PIN a[462]
    DIRECTION INPUT ;
    USE SIGNAL ;
    PORT
      LAYER M4 ;
        RECT  64.692 91.152 64.776 91.176 ;
    END
  END a[462]
  PIN a[463]
    DIRECTION INPUT ;
    USE SIGNAL ;
    PORT
      LAYER M4 ;
        RECT  64.692 91.248 64.776 91.272 ;
    END
  END a[463]
  PIN a[464]
    DIRECTION INPUT ;
    USE SIGNAL ;
    PORT
      LAYER M4 ;
        RECT  64.692 91.344 64.776 91.368 ;
    END
  END a[464]
  PIN a[465]
    DIRECTION INPUT ;
    USE SIGNAL ;
    PORT
      LAYER M4 ;
        RECT  64.692 91.44 64.776 91.464 ;
    END
  END a[465]
  PIN a[466]
    DIRECTION INPUT ;
    USE SIGNAL ;
    PORT
      LAYER M4 ;
        RECT  64.692 91.536 64.776 91.56 ;
    END
  END a[466]
  PIN a[467]
    DIRECTION INPUT ;
    USE SIGNAL ;
    PORT
      LAYER M4 ;
        RECT  64.692 91.632 64.776 91.656 ;
    END
  END a[467]
  PIN a[468]
    DIRECTION INPUT ;
    USE SIGNAL ;
    PORT
      LAYER M4 ;
        RECT  64.692 91.728 64.776 91.752 ;
    END
  END a[468]
  PIN a[469]
    DIRECTION INPUT ;
    USE SIGNAL ;
    PORT
      LAYER M4 ;
        RECT  64.692 91.824 64.776 91.848 ;
    END
  END a[469]
  PIN a[46]
    DIRECTION INPUT ;
    USE SIGNAL ;
    PORT
      LAYER M4 ;
        RECT  64.692 49.68 64.776 49.704 ;
    END
  END a[46]
  PIN a[470]
    DIRECTION INPUT ;
    USE SIGNAL ;
    PORT
      LAYER M4 ;
        RECT  64.692 91.92 64.776 91.944 ;
    END
  END a[470]
  PIN a[471]
    DIRECTION INPUT ;
    USE SIGNAL ;
    PORT
      LAYER M4 ;
        RECT  64.692 92.016 64.776 92.04 ;
    END
  END a[471]
  PIN a[472]
    DIRECTION INPUT ;
    USE SIGNAL ;
    PORT
      LAYER M4 ;
        RECT  64.692 92.112 64.776 92.136 ;
    END
  END a[472]
  PIN a[473]
    DIRECTION INPUT ;
    USE SIGNAL ;
    PORT
      LAYER M4 ;
        RECT  64.692 92.208 64.776 92.232 ;
    END
  END a[473]
  PIN a[474]
    DIRECTION INPUT ;
    USE SIGNAL ;
    PORT
      LAYER M4 ;
        RECT  64.692 92.304 64.776 92.328 ;
    END
  END a[474]
  PIN a[475]
    DIRECTION INPUT ;
    USE SIGNAL ;
    PORT
      LAYER M4 ;
        RECT  64.692 92.4 64.776 92.424 ;
    END
  END a[475]
  PIN a[476]
    DIRECTION INPUT ;
    USE SIGNAL ;
    PORT
      LAYER M4 ;
        RECT  64.692 92.496 64.776 92.52 ;
    END
  END a[476]
  PIN a[477]
    DIRECTION INPUT ;
    USE SIGNAL ;
    PORT
      LAYER M4 ;
        RECT  64.692 92.592 64.776 92.616 ;
    END
  END a[477]
  PIN a[478]
    DIRECTION INPUT ;
    USE SIGNAL ;
    PORT
      LAYER M4 ;
        RECT  64.692 92.688 64.776 92.712 ;
    END
  END a[478]
  PIN a[479]
    DIRECTION INPUT ;
    USE SIGNAL ;
    PORT
      LAYER M4 ;
        RECT  64.692 92.784 64.776 92.808 ;
    END
  END a[479]
  PIN a[47]
    DIRECTION INPUT ;
    USE SIGNAL ;
    PORT
      LAYER M4 ;
        RECT  64.692 49.776 64.776 49.8 ;
    END
  END a[47]
  PIN a[480]
    DIRECTION INPUT ;
    USE SIGNAL ;
    PORT
      LAYER M4 ;
        RECT  64.692 86.736 64.776 86.76 ;
    END
  END a[480]
  PIN a[481]
    DIRECTION INPUT ;
    USE SIGNAL ;
    PORT
      LAYER M4 ;
        RECT  64.692 86.832 64.776 86.856 ;
    END
  END a[481]
  PIN a[482]
    DIRECTION INPUT ;
    USE SIGNAL ;
    PORT
      LAYER M4 ;
        RECT  64.692 86.928 64.776 86.952 ;
    END
  END a[482]
  PIN a[483]
    DIRECTION INPUT ;
    USE SIGNAL ;
    PORT
      LAYER M4 ;
        RECT  64.692 87.024 64.776 87.048 ;
    END
  END a[483]
  PIN a[484]
    DIRECTION INPUT ;
    USE SIGNAL ;
    PORT
      LAYER M4 ;
        RECT  64.692 87.12 64.776 87.144 ;
    END
  END a[484]
  PIN a[485]
    DIRECTION INPUT ;
    USE SIGNAL ;
    PORT
      LAYER M4 ;
        RECT  64.692 87.216 64.776 87.24 ;
    END
  END a[485]
  PIN a[486]
    DIRECTION INPUT ;
    USE SIGNAL ;
    PORT
      LAYER M4 ;
        RECT  64.692 87.312 64.776 87.336 ;
    END
  END a[486]
  PIN a[487]
    DIRECTION INPUT ;
    USE SIGNAL ;
    PORT
      LAYER M4 ;
        RECT  64.692 87.408 64.776 87.432 ;
    END
  END a[487]
  PIN a[488]
    DIRECTION INPUT ;
    USE SIGNAL ;
    PORT
      LAYER M4 ;
        RECT  64.692 87.504 64.776 87.528 ;
    END
  END a[488]
  PIN a[489]
    DIRECTION INPUT ;
    USE SIGNAL ;
    PORT
      LAYER M4 ;
        RECT  64.692 87.6 64.776 87.624 ;
    END
  END a[489]
  PIN a[48]
    DIRECTION INPUT ;
    USE SIGNAL ;
    PORT
      LAYER M4 ;
        RECT  64.692 49.872 64.776 49.896 ;
    END
  END a[48]
  PIN a[490]
    DIRECTION INPUT ;
    USE SIGNAL ;
    PORT
      LAYER M4 ;
        RECT  64.692 87.696 64.776 87.72 ;
    END
  END a[490]
  PIN a[491]
    DIRECTION INPUT ;
    USE SIGNAL ;
    PORT
      LAYER M4 ;
        RECT  64.692 87.792 64.776 87.816 ;
    END
  END a[491]
  PIN a[492]
    DIRECTION INPUT ;
    USE SIGNAL ;
    PORT
      LAYER M4 ;
        RECT  64.692 87.888 64.776 87.912 ;
    END
  END a[492]
  PIN a[493]
    DIRECTION INPUT ;
    USE SIGNAL ;
    PORT
      LAYER M4 ;
        RECT  64.692 87.984 64.776 88.008 ;
    END
  END a[493]
  PIN a[494]
    DIRECTION INPUT ;
    USE SIGNAL ;
    PORT
      LAYER M4 ;
        RECT  64.692 88.08 64.776 88.104 ;
    END
  END a[494]
  PIN a[495]
    DIRECTION INPUT ;
    USE SIGNAL ;
    PORT
      LAYER M4 ;
        RECT  64.692 88.176 64.776 88.2 ;
    END
  END a[495]
  PIN a[496]
    DIRECTION INPUT ;
    USE SIGNAL ;
    PORT
      LAYER M4 ;
        RECT  64.692 88.272 64.776 88.296 ;
    END
  END a[496]
  PIN a[497]
    DIRECTION INPUT ;
    USE SIGNAL ;
    PORT
      LAYER M4 ;
        RECT  64.692 88.368 64.776 88.392 ;
    END
  END a[497]
  PIN a[498]
    DIRECTION INPUT ;
    USE SIGNAL ;
    PORT
      LAYER M4 ;
        RECT  64.692 88.464 64.776 88.488 ;
    END
  END a[498]
  PIN a[499]
    DIRECTION INPUT ;
    USE SIGNAL ;
    PORT
      LAYER M4 ;
        RECT  64.692 88.56 64.776 88.584 ;
    END
  END a[499]
  PIN a[49]
    DIRECTION INPUT ;
    USE SIGNAL ;
    PORT
      LAYER M4 ;
        RECT  64.692 49.968 64.776 49.992 ;
    END
  END a[49]
  PIN a[4]
    DIRECTION INPUT ;
    USE SIGNAL ;
    PORT
      LAYER M4 ;
        RECT  64.692 51.792 64.776 51.816 ;
    END
  END a[4]
  PIN a[500]
    DIRECTION INPUT ;
    USE SIGNAL ;
    PORT
      LAYER M4 ;
        RECT  64.692 88.656 64.776 88.68 ;
    END
  END a[500]
  PIN a[501]
    DIRECTION INPUT ;
    USE SIGNAL ;
    PORT
      LAYER M4 ;
        RECT  64.692 88.752 64.776 88.776 ;
    END
  END a[501]
  PIN a[502]
    DIRECTION INPUT ;
    USE SIGNAL ;
    PORT
      LAYER M4 ;
        RECT  64.692 88.848 64.776 88.872 ;
    END
  END a[502]
  PIN a[503]
    DIRECTION INPUT ;
    USE SIGNAL ;
    PORT
      LAYER M4 ;
        RECT  64.692 88.944 64.776 88.968 ;
    END
  END a[503]
  PIN a[504]
    DIRECTION INPUT ;
    USE SIGNAL ;
    PORT
      LAYER M4 ;
        RECT  64.692 89.04 64.776 89.064 ;
    END
  END a[504]
  PIN a[505]
    DIRECTION INPUT ;
    USE SIGNAL ;
    PORT
      LAYER M4 ;
        RECT  64.692 89.136 64.776 89.16 ;
    END
  END a[505]
  PIN a[506]
    DIRECTION INPUT ;
    USE SIGNAL ;
    PORT
      LAYER M4 ;
        RECT  64.692 89.232 64.776 89.256 ;
    END
  END a[506]
  PIN a[507]
    DIRECTION INPUT ;
    USE SIGNAL ;
    PORT
      LAYER M4 ;
        RECT  64.692 89.328 64.776 89.352 ;
    END
  END a[507]
  PIN a[508]
    DIRECTION INPUT ;
    USE SIGNAL ;
    PORT
      LAYER M4 ;
        RECT  64.692 89.424 64.776 89.448 ;
    END
  END a[508]
  PIN a[509]
    DIRECTION INPUT ;
    USE SIGNAL ;
    PORT
      LAYER M4 ;
        RECT  64.692 89.52 64.776 89.544 ;
    END
  END a[509]
  PIN a[50]
    DIRECTION INPUT ;
    USE SIGNAL ;
    PORT
      LAYER M4 ;
        RECT  64.692 50.064 64.776 50.088 ;
    END
  END a[50]
  PIN a[510]
    DIRECTION INPUT ;
    USE SIGNAL ;
    PORT
      LAYER M4 ;
        RECT  64.692 89.616 64.776 89.64 ;
    END
  END a[510]
  PIN a[511]
    DIRECTION INPUT ;
    USE SIGNAL ;
    PORT
      LAYER M4 ;
        RECT  64.692 89.712 64.776 89.736 ;
    END
  END a[511]
  PIN a[512]
    DIRECTION INPUT ;
    USE SIGNAL ;
    PORT
      LAYER M4 ;
        RECT  64.692 67.536 64.776 67.56 ;
    END
  END a[512]
  PIN a[513]
    DIRECTION INPUT ;
    USE SIGNAL ;
    PORT
      LAYER M4 ;
        RECT  64.692 67.632 64.776 67.656 ;
    END
  END a[513]
  PIN a[514]
    DIRECTION INPUT ;
    USE SIGNAL ;
    PORT
      LAYER M4 ;
        RECT  64.692 67.728 64.776 67.752 ;
    END
  END a[514]
  PIN a[515]
    DIRECTION INPUT ;
    USE SIGNAL ;
    PORT
      LAYER M4 ;
        RECT  64.692 67.824 64.776 67.848 ;
    END
  END a[515]
  PIN a[516]
    DIRECTION INPUT ;
    USE SIGNAL ;
    PORT
      LAYER M4 ;
        RECT  64.692 67.92 64.776 67.944 ;
    END
  END a[516]
  PIN a[517]
    DIRECTION INPUT ;
    USE SIGNAL ;
    PORT
      LAYER M4 ;
        RECT  64.692 68.016 64.776 68.04 ;
    END
  END a[517]
  PIN a[518]
    DIRECTION INPUT ;
    USE SIGNAL ;
    PORT
      LAYER M4 ;
        RECT  64.692 68.112 64.776 68.136 ;
    END
  END a[518]
  PIN a[519]
    DIRECTION INPUT ;
    USE SIGNAL ;
    PORT
      LAYER M4 ;
        RECT  64.692 68.208 64.776 68.232 ;
    END
  END a[519]
  PIN a[51]
    DIRECTION INPUT ;
    USE SIGNAL ;
    PORT
      LAYER M4 ;
        RECT  64.692 50.16 64.776 50.184 ;
    END
  END a[51]
  PIN a[520]
    DIRECTION INPUT ;
    USE SIGNAL ;
    PORT
      LAYER M4 ;
        RECT  64.692 68.304 64.776 68.328 ;
    END
  END a[520]
  PIN a[521]
    DIRECTION INPUT ;
    USE SIGNAL ;
    PORT
      LAYER M4 ;
        RECT  64.692 68.4 64.776 68.424 ;
    END
  END a[521]
  PIN a[522]
    DIRECTION INPUT ;
    USE SIGNAL ;
    PORT
      LAYER M4 ;
        RECT  64.692 68.496 64.776 68.52 ;
    END
  END a[522]
  PIN a[523]
    DIRECTION INPUT ;
    USE SIGNAL ;
    PORT
      LAYER M4 ;
        RECT  64.692 68.592 64.776 68.616 ;
    END
  END a[523]
  PIN a[524]
    DIRECTION INPUT ;
    USE SIGNAL ;
    PORT
      LAYER M4 ;
        RECT  64.692 68.688 64.776 68.712 ;
    END
  END a[524]
  PIN a[525]
    DIRECTION INPUT ;
    USE SIGNAL ;
    PORT
      LAYER M4 ;
        RECT  64.692 68.784 64.776 68.808 ;
    END
  END a[525]
  PIN a[526]
    DIRECTION INPUT ;
    USE SIGNAL ;
    PORT
      LAYER M4 ;
        RECT  64.692 68.88 64.776 68.904 ;
    END
  END a[526]
  PIN a[527]
    DIRECTION INPUT ;
    USE SIGNAL ;
    PORT
      LAYER M4 ;
        RECT  64.692 68.976 64.776 69 ;
    END
  END a[527]
  PIN a[528]
    DIRECTION INPUT ;
    USE SIGNAL ;
    PORT
      LAYER M4 ;
        RECT  64.692 69.072 64.776 69.096 ;
    END
  END a[528]
  PIN a[529]
    DIRECTION INPUT ;
    USE SIGNAL ;
    PORT
      LAYER M4 ;
        RECT  64.692 69.168 64.776 69.192 ;
    END
  END a[529]
  PIN a[52]
    DIRECTION INPUT ;
    USE SIGNAL ;
    PORT
      LAYER M4 ;
        RECT  64.692 50.256 64.776 50.28 ;
    END
  END a[52]
  PIN a[530]
    DIRECTION INPUT ;
    USE SIGNAL ;
    PORT
      LAYER M4 ;
        RECT  64.692 69.264 64.776 69.288 ;
    END
  END a[530]
  PIN a[531]
    DIRECTION INPUT ;
    USE SIGNAL ;
    PORT
      LAYER M4 ;
        RECT  64.692 69.36 64.776 69.384 ;
    END
  END a[531]
  PIN a[532]
    DIRECTION INPUT ;
    USE SIGNAL ;
    PORT
      LAYER M4 ;
        RECT  64.692 69.456 64.776 69.48 ;
    END
  END a[532]
  PIN a[533]
    DIRECTION INPUT ;
    USE SIGNAL ;
    PORT
      LAYER M4 ;
        RECT  64.692 69.552 64.776 69.576 ;
    END
  END a[533]
  PIN a[534]
    DIRECTION INPUT ;
    USE SIGNAL ;
    PORT
      LAYER M4 ;
        RECT  64.692 69.648 64.776 69.672 ;
    END
  END a[534]
  PIN a[535]
    DIRECTION INPUT ;
    USE SIGNAL ;
    PORT
      LAYER M4 ;
        RECT  64.692 69.744 64.776 69.768 ;
    END
  END a[535]
  PIN a[536]
    DIRECTION INPUT ;
    USE SIGNAL ;
    PORT
      LAYER M4 ;
        RECT  64.692 69.84 64.776 69.864 ;
    END
  END a[536]
  PIN a[537]
    DIRECTION INPUT ;
    USE SIGNAL ;
    PORT
      LAYER M4 ;
        RECT  64.692 69.936 64.776 69.96 ;
    END
  END a[537]
  PIN a[538]
    DIRECTION INPUT ;
    USE SIGNAL ;
    PORT
      LAYER M4 ;
        RECT  64.692 70.032 64.776 70.056 ;
    END
  END a[538]
  PIN a[539]
    DIRECTION INPUT ;
    USE SIGNAL ;
    PORT
      LAYER M4 ;
        RECT  64.692 70.128 64.776 70.152 ;
    END
  END a[539]
  PIN a[53]
    DIRECTION INPUT ;
    USE SIGNAL ;
    PORT
      LAYER M4 ;
        RECT  64.692 50.352 64.776 50.376 ;
    END
  END a[53]
  PIN a[540]
    DIRECTION INPUT ;
    USE SIGNAL ;
    PORT
      LAYER M4 ;
        RECT  64.692 70.224 64.776 70.248 ;
    END
  END a[540]
  PIN a[541]
    DIRECTION INPUT ;
    USE SIGNAL ;
    PORT
      LAYER M4 ;
        RECT  64.692 70.32 64.776 70.344 ;
    END
  END a[541]
  PIN a[542]
    DIRECTION INPUT ;
    USE SIGNAL ;
    PORT
      LAYER M4 ;
        RECT  64.692 70.416 64.776 70.44 ;
    END
  END a[542]
  PIN a[543]
    DIRECTION INPUT ;
    USE SIGNAL ;
    PORT
      LAYER M4 ;
        RECT  64.692 70.512 64.776 70.536 ;
    END
  END a[543]
  PIN a[544]
    DIRECTION INPUT ;
    USE SIGNAL ;
    PORT
      LAYER M4 ;
        RECT  64.692 61.392 64.776 61.416 ;
    END
  END a[544]
  PIN a[545]
    DIRECTION INPUT ;
    USE SIGNAL ;
    PORT
      LAYER M4 ;
        RECT  64.692 61.488 64.776 61.512 ;
    END
  END a[545]
  PIN a[546]
    DIRECTION INPUT ;
    USE SIGNAL ;
    PORT
      LAYER M4 ;
        RECT  64.692 61.584 64.776 61.608 ;
    END
  END a[546]
  PIN a[547]
    DIRECTION INPUT ;
    USE SIGNAL ;
    PORT
      LAYER M4 ;
        RECT  64.692 61.68 64.776 61.704 ;
    END
  END a[547]
  PIN a[54]
    DIRECTION INPUT ;
    USE SIGNAL ;
    PORT
      LAYER M4 ;
        RECT  64.692 50.448 64.776 50.472 ;
    END
  END a[54]
  PIN a[55]
    DIRECTION INPUT ;
    USE SIGNAL ;
    PORT
      LAYER M4 ;
        RECT  64.692 50.544 64.776 50.568 ;
    END
  END a[55]
  PIN a[56]
    DIRECTION INPUT ;
    USE SIGNAL ;
    PORT
      LAYER M4 ;
        RECT  64.692 50.64 64.776 50.664 ;
    END
  END a[56]
  PIN a[57]
    DIRECTION INPUT ;
    USE SIGNAL ;
    PORT
      LAYER M4 ;
        RECT  64.692 50.736 64.776 50.76 ;
    END
  END a[57]
  PIN a[58]
    DIRECTION INPUT ;
    USE SIGNAL ;
    PORT
      LAYER M4 ;
        RECT  64.692 50.832 64.776 50.856 ;
    END
  END a[58]
  PIN a[59]
    DIRECTION INPUT ;
    USE SIGNAL ;
    PORT
      LAYER M4 ;
        RECT  64.692 50.928 64.776 50.952 ;
    END
  END a[59]
  PIN a[5]
    DIRECTION INPUT ;
    USE SIGNAL ;
    PORT
      LAYER M4 ;
        RECT  64.692 51.888 64.776 51.912 ;
    END
  END a[5]
  PIN a[60]
    DIRECTION INPUT ;
    USE SIGNAL ;
    PORT
      LAYER M4 ;
        RECT  64.692 51.024 64.776 51.048 ;
    END
  END a[60]
  PIN a[61]
    DIRECTION INPUT ;
    USE SIGNAL ;
    PORT
      LAYER M4 ;
        RECT  64.692 51.12 64.776 51.144 ;
    END
  END a[61]
  PIN a[62]
    DIRECTION INPUT ;
    USE SIGNAL ;
    PORT
      LAYER M4 ;
        RECT  64.692 51.216 64.776 51.24 ;
    END
  END a[62]
  PIN a[63]
    DIRECTION INPUT ;
    USE SIGNAL ;
    PORT
      LAYER M4 ;
        RECT  64.692 51.312 64.776 51.336 ;
    END
  END a[63]
  PIN a[64]
    DIRECTION INPUT ;
    USE SIGNAL ;
    PORT
      LAYER M4 ;
        RECT  64.692 32.208 64.776 32.232 ;
    END
  END a[64]
  PIN a[65]
    DIRECTION INPUT ;
    USE SIGNAL ;
    PORT
      LAYER M4 ;
        RECT  64.692 32.304 64.776 32.328 ;
    END
  END a[65]
  PIN a[66]
    DIRECTION INPUT ;
    USE SIGNAL ;
    PORT
      LAYER M4 ;
        RECT  64.692 32.4 64.776 32.424 ;
    END
  END a[66]
  PIN a[67]
    DIRECTION INPUT ;
    USE SIGNAL ;
    PORT
      LAYER M4 ;
        RECT  64.692 32.496 64.776 32.52 ;
    END
  END a[67]
  PIN a[68]
    DIRECTION INPUT ;
    USE SIGNAL ;
    PORT
      LAYER M4 ;
        RECT  64.692 32.592 64.776 32.616 ;
    END
  END a[68]
  PIN a[69]
    DIRECTION INPUT ;
    USE SIGNAL ;
    PORT
      LAYER M4 ;
        RECT  64.692 32.688 64.776 32.712 ;
    END
  END a[69]
  PIN a[6]
    DIRECTION INPUT ;
    USE SIGNAL ;
    PORT
      LAYER M4 ;
        RECT  64.692 51.984 64.776 52.008 ;
    END
  END a[6]
  PIN a[70]
    DIRECTION INPUT ;
    USE SIGNAL ;
    PORT
      LAYER M4 ;
        RECT  64.692 32.784 64.776 32.808 ;
    END
  END a[70]
  PIN a[71]
    DIRECTION INPUT ;
    USE SIGNAL ;
    PORT
      LAYER M4 ;
        RECT  64.692 32.88 64.776 32.904 ;
    END
  END a[71]
  PIN a[72]
    DIRECTION INPUT ;
    USE SIGNAL ;
    PORT
      LAYER M4 ;
        RECT  64.692 32.976 64.776 33 ;
    END
  END a[72]
  PIN a[73]
    DIRECTION INPUT ;
    USE SIGNAL ;
    PORT
      LAYER M4 ;
        RECT  64.692 33.072 64.776 33.096 ;
    END
  END a[73]
  PIN a[74]
    DIRECTION INPUT ;
    USE SIGNAL ;
    PORT
      LAYER M4 ;
        RECT  64.692 33.168 64.776 33.192 ;
    END
  END a[74]
  PIN a[75]
    DIRECTION INPUT ;
    USE SIGNAL ;
    PORT
      LAYER M4 ;
        RECT  64.692 33.264 64.776 33.288 ;
    END
  END a[75]
  PIN a[76]
    DIRECTION INPUT ;
    USE SIGNAL ;
    PORT
      LAYER M4 ;
        RECT  64.692 33.36 64.776 33.384 ;
    END
  END a[76]
  PIN a[77]
    DIRECTION INPUT ;
    USE SIGNAL ;
    PORT
      LAYER M4 ;
        RECT  64.692 33.456 64.776 33.48 ;
    END
  END a[77]
  PIN a[78]
    DIRECTION INPUT ;
    USE SIGNAL ;
    PORT
      LAYER M4 ;
        RECT  64.692 33.552 64.776 33.576 ;
    END
  END a[78]
  PIN a[79]
    DIRECTION INPUT ;
    USE SIGNAL ;
    PORT
      LAYER M4 ;
        RECT  64.692 33.648 64.776 33.672 ;
    END
  END a[79]
  PIN a[7]
    DIRECTION INPUT ;
    USE SIGNAL ;
    PORT
      LAYER M4 ;
        RECT  64.692 52.08 64.776 52.104 ;
    END
  END a[7]
  PIN a[80]
    DIRECTION INPUT ;
    USE SIGNAL ;
    PORT
      LAYER M4 ;
        RECT  64.692 33.744 64.776 33.768 ;
    END
  END a[80]
  PIN a[81]
    DIRECTION INPUT ;
    USE SIGNAL ;
    PORT
      LAYER M4 ;
        RECT  64.692 33.84 64.776 33.864 ;
    END
  END a[81]
  PIN a[82]
    DIRECTION INPUT ;
    USE SIGNAL ;
    PORT
      LAYER M4 ;
        RECT  64.692 33.936 64.776 33.96 ;
    END
  END a[82]
  PIN a[83]
    DIRECTION INPUT ;
    USE SIGNAL ;
    PORT
      LAYER M4 ;
        RECT  64.692 34.032 64.776 34.056 ;
    END
  END a[83]
  PIN a[84]
    DIRECTION INPUT ;
    USE SIGNAL ;
    PORT
      LAYER M4 ;
        RECT  64.692 34.128 64.776 34.152 ;
    END
  END a[84]
  PIN a[85]
    DIRECTION INPUT ;
    USE SIGNAL ;
    PORT
      LAYER M4 ;
        RECT  64.692 34.224 64.776 34.248 ;
    END
  END a[85]
  PIN a[86]
    DIRECTION INPUT ;
    USE SIGNAL ;
    PORT
      LAYER M4 ;
        RECT  64.692 34.32 64.776 34.344 ;
    END
  END a[86]
  PIN a[87]
    DIRECTION INPUT ;
    USE SIGNAL ;
    PORT
      LAYER M4 ;
        RECT  64.692 34.416 64.776 34.44 ;
    END
  END a[87]
  PIN a[88]
    DIRECTION INPUT ;
    USE SIGNAL ;
    PORT
      LAYER M4 ;
        RECT  64.692 34.512 64.776 34.536 ;
    END
  END a[88]
  PIN a[89]
    DIRECTION INPUT ;
    USE SIGNAL ;
    PORT
      LAYER M4 ;
        RECT  64.692 34.608 64.776 34.632 ;
    END
  END a[89]
  PIN a[8]
    DIRECTION INPUT ;
    USE SIGNAL ;
    PORT
      LAYER M4 ;
        RECT  64.692 52.176 64.776 52.2 ;
    END
  END a[8]
  PIN a[90]
    DIRECTION INPUT ;
    USE SIGNAL ;
    PORT
      LAYER M4 ;
        RECT  64.692 34.704 64.776 34.728 ;
    END
  END a[90]
  PIN a[91]
    DIRECTION INPUT ;
    USE SIGNAL ;
    PORT
      LAYER M4 ;
        RECT  64.692 34.8 64.776 34.824 ;
    END
  END a[91]
  PIN a[92]
    DIRECTION INPUT ;
    USE SIGNAL ;
    PORT
      LAYER M4 ;
        RECT  64.692 34.896 64.776 34.92 ;
    END
  END a[92]
  PIN a[93]
    DIRECTION INPUT ;
    USE SIGNAL ;
    PORT
      LAYER M4 ;
        RECT  64.692 34.992 64.776 35.016 ;
    END
  END a[93]
  PIN a[94]
    DIRECTION INPUT ;
    USE SIGNAL ;
    PORT
      LAYER M4 ;
        RECT  64.692 35.088 64.776 35.112 ;
    END
  END a[94]
  PIN a[95]
    DIRECTION INPUT ;
    USE SIGNAL ;
    PORT
      LAYER M4 ;
        RECT  64.692 35.184 64.776 35.208 ;
    END
  END a[95]
  PIN a[96]
    DIRECTION INPUT ;
    USE SIGNAL ;
    PORT
      LAYER M4 ;
        RECT  64.692 22.992 64.776 23.016 ;
    END
  END a[96]
  PIN a[97]
    DIRECTION INPUT ;
    USE SIGNAL ;
    PORT
      LAYER M4 ;
        RECT  64.692 23.088 64.776 23.112 ;
    END
  END a[97]
  PIN a[98]
    DIRECTION INPUT ;
    USE SIGNAL ;
    PORT
      LAYER M4 ;
        RECT  64.692 23.184 64.776 23.208 ;
    END
  END a[98]
  PIN a[99]
    DIRECTION INPUT ;
    USE SIGNAL ;
    PORT
      LAYER M4 ;
        RECT  64.692 23.28 64.776 23.304 ;
    END
  END a[99]
  PIN a[9]
    DIRECTION INPUT ;
    USE SIGNAL ;
    PORT
      LAYER M4 ;
        RECT  64.692 52.272 64.776 52.296 ;
    END
  END a[9]
  PIN b[0]
    DIRECTION OUTPUT ;
    USE SIGNAL ;
    PORT
      LAYER M4 ;
        RECT  0 47.952 0.084 47.976 ;
    END
  END b[0]
  PIN b[100]
    DIRECTION OUTPUT ;
    USE SIGNAL ;
    PORT
      LAYER M4 ;
        RECT  0 16.08 0.084 16.104 ;
    END
  END b[100]
  PIN b[101]
    DIRECTION OUTPUT ;
    USE SIGNAL ;
    PORT
      LAYER M4 ;
        RECT  0 16.176 0.084 16.2 ;
    END
  END b[101]
  PIN b[102]
    DIRECTION OUTPUT ;
    USE SIGNAL ;
    PORT
      LAYER M4 ;
        RECT  0 16.272 0.084 16.296 ;
    END
  END b[102]
  PIN b[103]
    DIRECTION OUTPUT ;
    USE SIGNAL ;
    PORT
      LAYER M4 ;
        RECT  0 16.368 0.084 16.392 ;
    END
  END b[103]
  PIN b[104]
    DIRECTION OUTPUT ;
    USE SIGNAL ;
    PORT
      LAYER M4 ;
        RECT  0 16.464 0.084 16.488 ;
    END
  END b[104]
  PIN b[105]
    DIRECTION OUTPUT ;
    USE SIGNAL ;
    PORT
      LAYER M4 ;
        RECT  0 16.56 0.084 16.584 ;
    END
  END b[105]
  PIN b[106]
    DIRECTION OUTPUT ;
    USE SIGNAL ;
    PORT
      LAYER M4 ;
        RECT  0 16.656 0.084 16.68 ;
    END
  END b[106]
  PIN b[107]
    DIRECTION OUTPUT ;
    USE SIGNAL ;
    PORT
      LAYER M4 ;
        RECT  0 16.752 0.084 16.776 ;
    END
  END b[107]
  PIN b[108]
    DIRECTION OUTPUT ;
    USE SIGNAL ;
    PORT
      LAYER M4 ;
        RECT  0 16.848 0.084 16.872 ;
    END
  END b[108]
  PIN b[109]
    DIRECTION OUTPUT ;
    USE SIGNAL ;
    PORT
      LAYER M4 ;
        RECT  0 16.944 0.084 16.968 ;
    END
  END b[109]
  PIN b[10]
    DIRECTION OUTPUT ;
    USE SIGNAL ;
    PORT
      LAYER M4 ;
        RECT  0 48.912 0.084 48.936 ;
    END
  END b[10]
  PIN b[110]
    DIRECTION OUTPUT ;
    USE SIGNAL ;
    PORT
      LAYER M4 ;
        RECT  0 17.04 0.084 17.064 ;
    END
  END b[110]
  PIN b[111]
    DIRECTION OUTPUT ;
    USE SIGNAL ;
    PORT
      LAYER M4 ;
        RECT  0 17.136 0.084 17.16 ;
    END
  END b[111]
  PIN b[112]
    DIRECTION OUTPUT ;
    USE SIGNAL ;
    PORT
      LAYER M4 ;
        RECT  0 17.232 0.084 17.256 ;
    END
  END b[112]
  PIN b[113]
    DIRECTION OUTPUT ;
    USE SIGNAL ;
    PORT
      LAYER M4 ;
        RECT  0 17.328 0.084 17.352 ;
    END
  END b[113]
  PIN b[114]
    DIRECTION OUTPUT ;
    USE SIGNAL ;
    PORT
      LAYER M4 ;
        RECT  0 17.424 0.084 17.448 ;
    END
  END b[114]
  PIN b[115]
    DIRECTION OUTPUT ;
    USE SIGNAL ;
    PORT
      LAYER M4 ;
        RECT  0 17.52 0.084 17.544 ;
    END
  END b[115]
  PIN b[116]
    DIRECTION OUTPUT ;
    USE SIGNAL ;
    PORT
      LAYER M4 ;
        RECT  0 17.616 0.084 17.64 ;
    END
  END b[116]
  PIN b[117]
    DIRECTION OUTPUT ;
    USE SIGNAL ;
    PORT
      LAYER M4 ;
        RECT  0 17.712 0.084 17.736 ;
    END
  END b[117]
  PIN b[118]
    DIRECTION OUTPUT ;
    USE SIGNAL ;
    PORT
      LAYER M4 ;
        RECT  0 17.808 0.084 17.832 ;
    END
  END b[118]
  PIN b[119]
    DIRECTION OUTPUT ;
    USE SIGNAL ;
    PORT
      LAYER M4 ;
        RECT  0 17.904 0.084 17.928 ;
    END
  END b[119]
  PIN b[11]
    DIRECTION OUTPUT ;
    USE SIGNAL ;
    PORT
      LAYER M4 ;
        RECT  0 49.008 0.084 49.032 ;
    END
  END b[11]
  PIN b[120]
    DIRECTION OUTPUT ;
    USE SIGNAL ;
    PORT
      LAYER M4 ;
        RECT  0 18 0.084 18.024 ;
    END
  END b[120]
  PIN b[121]
    DIRECTION OUTPUT ;
    USE SIGNAL ;
    PORT
      LAYER M4 ;
        RECT  0 18.096 0.084 18.12 ;
    END
  END b[121]
  PIN b[122]
    DIRECTION OUTPUT ;
    USE SIGNAL ;
    PORT
      LAYER M4 ;
        RECT  0 18.192 0.084 18.216 ;
    END
  END b[122]
  PIN b[123]
    DIRECTION OUTPUT ;
    USE SIGNAL ;
    PORT
      LAYER M4 ;
        RECT  0 18.288 0.084 18.312 ;
    END
  END b[123]
  PIN b[124]
    DIRECTION OUTPUT ;
    USE SIGNAL ;
    PORT
      LAYER M4 ;
        RECT  0 18.384 0.084 18.408 ;
    END
  END b[124]
  PIN b[125]
    DIRECTION OUTPUT ;
    USE SIGNAL ;
    PORT
      LAYER M4 ;
        RECT  0 18.48 0.084 18.504 ;
    END
  END b[125]
  PIN b[126]
    DIRECTION OUTPUT ;
    USE SIGNAL ;
    PORT
      LAYER M4 ;
        RECT  0 18.576 0.084 18.6 ;
    END
  END b[126]
  PIN b[127]
    DIRECTION OUTPUT ;
    USE SIGNAL ;
    PORT
      LAYER M4 ;
        RECT  0 18.672 0.084 18.696 ;
    END
  END b[127]
  PIN b[128]
    DIRECTION OUTPUT ;
    USE SIGNAL ;
    PORT
      LAYER M4 ;
        RECT  0 12.624 0.084 12.648 ;
    END
  END b[128]
  PIN b[129]
    DIRECTION OUTPUT ;
    USE SIGNAL ;
    PORT
      LAYER M4 ;
        RECT  0 12.72 0.084 12.744 ;
    END
  END b[129]
  PIN b[12]
    DIRECTION OUTPUT ;
    USE SIGNAL ;
    PORT
      LAYER M4 ;
        RECT  0 49.104 0.084 49.128 ;
    END
  END b[12]
  PIN b[130]
    DIRECTION OUTPUT ;
    USE SIGNAL ;
    PORT
      LAYER M4 ;
        RECT  0 12.816 0.084 12.84 ;
    END
  END b[130]
  PIN b[131]
    DIRECTION OUTPUT ;
    USE SIGNAL ;
    PORT
      LAYER M4 ;
        RECT  0 12.912 0.084 12.936 ;
    END
  END b[131]
  PIN b[132]
    DIRECTION OUTPUT ;
    USE SIGNAL ;
    PORT
      LAYER M4 ;
        RECT  0 13.008 0.084 13.032 ;
    END
  END b[132]
  PIN b[133]
    DIRECTION OUTPUT ;
    USE SIGNAL ;
    PORT
      LAYER M4 ;
        RECT  0 13.104 0.084 13.128 ;
    END
  END b[133]
  PIN b[134]
    DIRECTION OUTPUT ;
    USE SIGNAL ;
    PORT
      LAYER M4 ;
        RECT  0 13.2 0.084 13.224 ;
    END
  END b[134]
  PIN b[135]
    DIRECTION OUTPUT ;
    USE SIGNAL ;
    PORT
      LAYER M4 ;
        RECT  0 13.296 0.084 13.32 ;
    END
  END b[135]
  PIN b[136]
    DIRECTION OUTPUT ;
    USE SIGNAL ;
    PORT
      LAYER M4 ;
        RECT  0 13.392 0.084 13.416 ;
    END
  END b[136]
  PIN b[137]
    DIRECTION OUTPUT ;
    USE SIGNAL ;
    PORT
      LAYER M4 ;
        RECT  0 13.488 0.084 13.512 ;
    END
  END b[137]
  PIN b[138]
    DIRECTION OUTPUT ;
    USE SIGNAL ;
    PORT
      LAYER M4 ;
        RECT  0 13.584 0.084 13.608 ;
    END
  END b[138]
  PIN b[139]
    DIRECTION OUTPUT ;
    USE SIGNAL ;
    PORT
      LAYER M4 ;
        RECT  0 13.68 0.084 13.704 ;
    END
  END b[139]
  PIN b[13]
    DIRECTION OUTPUT ;
    USE SIGNAL ;
    PORT
      LAYER M4 ;
        RECT  0 49.2 0.084 49.224 ;
    END
  END b[13]
  PIN b[140]
    DIRECTION OUTPUT ;
    USE SIGNAL ;
    PORT
      LAYER M4 ;
        RECT  0 13.776 0.084 13.8 ;
    END
  END b[140]
  PIN b[141]
    DIRECTION OUTPUT ;
    USE SIGNAL ;
    PORT
      LAYER M4 ;
        RECT  0 13.872 0.084 13.896 ;
    END
  END b[141]
  PIN b[142]
    DIRECTION OUTPUT ;
    USE SIGNAL ;
    PORT
      LAYER M4 ;
        RECT  0 13.968 0.084 13.992 ;
    END
  END b[142]
  PIN b[143]
    DIRECTION OUTPUT ;
    USE SIGNAL ;
    PORT
      LAYER M4 ;
        RECT  0 14.064 0.084 14.088 ;
    END
  END b[143]
  PIN b[144]
    DIRECTION OUTPUT ;
    USE SIGNAL ;
    PORT
      LAYER M4 ;
        RECT  0 14.16 0.084 14.184 ;
    END
  END b[144]
  PIN b[145]
    DIRECTION OUTPUT ;
    USE SIGNAL ;
    PORT
      LAYER M4 ;
        RECT  0 14.256 0.084 14.28 ;
    END
  END b[145]
  PIN b[146]
    DIRECTION OUTPUT ;
    USE SIGNAL ;
    PORT
      LAYER M4 ;
        RECT  0 14.352 0.084 14.376 ;
    END
  END b[146]
  PIN b[147]
    DIRECTION OUTPUT ;
    USE SIGNAL ;
    PORT
      LAYER M4 ;
        RECT  0 14.448 0.084 14.472 ;
    END
  END b[147]
  PIN b[148]
    DIRECTION OUTPUT ;
    USE SIGNAL ;
    PORT
      LAYER M4 ;
        RECT  0 14.544 0.084 14.568 ;
    END
  END b[148]
  PIN b[149]
    DIRECTION OUTPUT ;
    USE SIGNAL ;
    PORT
      LAYER M4 ;
        RECT  0 14.64 0.084 14.664 ;
    END
  END b[149]
  PIN b[14]
    DIRECTION OUTPUT ;
    USE SIGNAL ;
    PORT
      LAYER M4 ;
        RECT  0 49.296 0.084 49.32 ;
    END
  END b[14]
  PIN b[150]
    DIRECTION OUTPUT ;
    USE SIGNAL ;
    PORT
      LAYER M4 ;
        RECT  0 14.736 0.084 14.76 ;
    END
  END b[150]
  PIN b[151]
    DIRECTION OUTPUT ;
    USE SIGNAL ;
    PORT
      LAYER M4 ;
        RECT  0 14.832 0.084 14.856 ;
    END
  END b[151]
  PIN b[152]
    DIRECTION OUTPUT ;
    USE SIGNAL ;
    PORT
      LAYER M4 ;
        RECT  0 14.928 0.084 14.952 ;
    END
  END b[152]
  PIN b[153]
    DIRECTION OUTPUT ;
    USE SIGNAL ;
    PORT
      LAYER M4 ;
        RECT  0 15.024 0.084 15.048 ;
    END
  END b[153]
  PIN b[154]
    DIRECTION OUTPUT ;
    USE SIGNAL ;
    PORT
      LAYER M4 ;
        RECT  0 15.12 0.084 15.144 ;
    END
  END b[154]
  PIN b[155]
    DIRECTION OUTPUT ;
    USE SIGNAL ;
    PORT
      LAYER M4 ;
        RECT  0 15.216 0.084 15.24 ;
    END
  END b[155]
  PIN b[156]
    DIRECTION OUTPUT ;
    USE SIGNAL ;
    PORT
      LAYER M4 ;
        RECT  0 15.312 0.084 15.336 ;
    END
  END b[156]
  PIN b[157]
    DIRECTION OUTPUT ;
    USE SIGNAL ;
    PORT
      LAYER M4 ;
        RECT  0 15.408 0.084 15.432 ;
    END
  END b[157]
  PIN b[158]
    DIRECTION OUTPUT ;
    USE SIGNAL ;
    PORT
      LAYER M4 ;
        RECT  0 15.504 0.084 15.528 ;
    END
  END b[158]
  PIN b[159]
    DIRECTION OUTPUT ;
    USE SIGNAL ;
    PORT
      LAYER M4 ;
        RECT  0 15.6 0.084 15.624 ;
    END
  END b[159]
  PIN b[15]
    DIRECTION OUTPUT ;
    USE SIGNAL ;
    PORT
      LAYER M4 ;
        RECT  0 49.392 0.084 49.416 ;
    END
  END b[15]
  PIN b[160]
    DIRECTION OUTPUT ;
    USE SIGNAL ;
    PORT
      LAYER M4 ;
        RECT  0 9.552 0.084 9.576 ;
    END
  END b[160]
  PIN b[161]
    DIRECTION OUTPUT ;
    USE SIGNAL ;
    PORT
      LAYER M4 ;
        RECT  0 9.648 0.084 9.672 ;
    END
  END b[161]
  PIN b[162]
    DIRECTION OUTPUT ;
    USE SIGNAL ;
    PORT
      LAYER M4 ;
        RECT  0 9.744 0.084 9.768 ;
    END
  END b[162]
  PIN b[163]
    DIRECTION OUTPUT ;
    USE SIGNAL ;
    PORT
      LAYER M4 ;
        RECT  0 9.84 0.084 9.864 ;
    END
  END b[163]
  PIN b[164]
    DIRECTION OUTPUT ;
    USE SIGNAL ;
    PORT
      LAYER M4 ;
        RECT  0 9.936 0.084 9.96 ;
    END
  END b[164]
  PIN b[165]
    DIRECTION OUTPUT ;
    USE SIGNAL ;
    PORT
      LAYER M4 ;
        RECT  0 10.032 0.084 10.056 ;
    END
  END b[165]
  PIN b[166]
    DIRECTION OUTPUT ;
    USE SIGNAL ;
    PORT
      LAYER M4 ;
        RECT  0 10.128 0.084 10.152 ;
    END
  END b[166]
  PIN b[167]
    DIRECTION OUTPUT ;
    USE SIGNAL ;
    PORT
      LAYER M4 ;
        RECT  0 10.224 0.084 10.248 ;
    END
  END b[167]
  PIN b[168]
    DIRECTION OUTPUT ;
    USE SIGNAL ;
    PORT
      LAYER M4 ;
        RECT  0 10.32 0.084 10.344 ;
    END
  END b[168]
  PIN b[169]
    DIRECTION OUTPUT ;
    USE SIGNAL ;
    PORT
      LAYER M4 ;
        RECT  0 10.416 0.084 10.44 ;
    END
  END b[169]
  PIN b[16]
    DIRECTION OUTPUT ;
    USE SIGNAL ;
    PORT
      LAYER M4 ;
        RECT  0 49.488 0.084 49.512 ;
    END
  END b[16]
  PIN b[170]
    DIRECTION OUTPUT ;
    USE SIGNAL ;
    PORT
      LAYER M4 ;
        RECT  0 10.512 0.084 10.536 ;
    END
  END b[170]
  PIN b[171]
    DIRECTION OUTPUT ;
    USE SIGNAL ;
    PORT
      LAYER M4 ;
        RECT  0 10.608 0.084 10.632 ;
    END
  END b[171]
  PIN b[172]
    DIRECTION OUTPUT ;
    USE SIGNAL ;
    PORT
      LAYER M4 ;
        RECT  0 10.704 0.084 10.728 ;
    END
  END b[172]
  PIN b[173]
    DIRECTION OUTPUT ;
    USE SIGNAL ;
    PORT
      LAYER M4 ;
        RECT  0 10.8 0.084 10.824 ;
    END
  END b[173]
  PIN b[174]
    DIRECTION OUTPUT ;
    USE SIGNAL ;
    PORT
      LAYER M4 ;
        RECT  0 10.896 0.084 10.92 ;
    END
  END b[174]
  PIN b[175]
    DIRECTION OUTPUT ;
    USE SIGNAL ;
    PORT
      LAYER M4 ;
        RECT  0 10.992 0.084 11.016 ;
    END
  END b[175]
  PIN b[176]
    DIRECTION OUTPUT ;
    USE SIGNAL ;
    PORT
      LAYER M4 ;
        RECT  0 11.088 0.084 11.112 ;
    END
  END b[176]
  PIN b[177]
    DIRECTION OUTPUT ;
    USE SIGNAL ;
    PORT
      LAYER M4 ;
        RECT  0 11.184 0.084 11.208 ;
    END
  END b[177]
  PIN b[178]
    DIRECTION OUTPUT ;
    USE SIGNAL ;
    PORT
      LAYER M4 ;
        RECT  0 11.28 0.084 11.304 ;
    END
  END b[178]
  PIN b[179]
    DIRECTION OUTPUT ;
    USE SIGNAL ;
    PORT
      LAYER M4 ;
        RECT  0 11.376 0.084 11.4 ;
    END
  END b[179]
  PIN b[17]
    DIRECTION OUTPUT ;
    USE SIGNAL ;
    PORT
      LAYER M4 ;
        RECT  0 49.584 0.084 49.608 ;
    END
  END b[17]
  PIN b[180]
    DIRECTION OUTPUT ;
    USE SIGNAL ;
    PORT
      LAYER M4 ;
        RECT  0 11.472 0.084 11.496 ;
    END
  END b[180]
  PIN b[181]
    DIRECTION OUTPUT ;
    USE SIGNAL ;
    PORT
      LAYER M4 ;
        RECT  0 11.568 0.084 11.592 ;
    END
  END b[181]
  PIN b[182]
    DIRECTION OUTPUT ;
    USE SIGNAL ;
    PORT
      LAYER M4 ;
        RECT  0 11.664 0.084 11.688 ;
    END
  END b[182]
  PIN b[183]
    DIRECTION OUTPUT ;
    USE SIGNAL ;
    PORT
      LAYER M4 ;
        RECT  0 11.76 0.084 11.784 ;
    END
  END b[183]
  PIN b[184]
    DIRECTION OUTPUT ;
    USE SIGNAL ;
    PORT
      LAYER M4 ;
        RECT  0 11.856 0.084 11.88 ;
    END
  END b[184]
  PIN b[185]
    DIRECTION OUTPUT ;
    USE SIGNAL ;
    PORT
      LAYER M4 ;
        RECT  0 11.952 0.084 11.976 ;
    END
  END b[185]
  PIN b[186]
    DIRECTION OUTPUT ;
    USE SIGNAL ;
    PORT
      LAYER M4 ;
        RECT  0 12.048 0.084 12.072 ;
    END
  END b[186]
  PIN b[187]
    DIRECTION OUTPUT ;
    USE SIGNAL ;
    PORT
      LAYER M4 ;
        RECT  0 12.144 0.084 12.168 ;
    END
  END b[187]
  PIN b[188]
    DIRECTION OUTPUT ;
    USE SIGNAL ;
    PORT
      LAYER M4 ;
        RECT  0 12.24 0.084 12.264 ;
    END
  END b[188]
  PIN b[189]
    DIRECTION OUTPUT ;
    USE SIGNAL ;
    PORT
      LAYER M4 ;
        RECT  0 12.336 0.084 12.36 ;
    END
  END b[189]
  PIN b[18]
    DIRECTION OUTPUT ;
    USE SIGNAL ;
    PORT
      LAYER M4 ;
        RECT  0 49.68 0.084 49.704 ;
    END
  END b[18]
  PIN b[190]
    DIRECTION OUTPUT ;
    USE SIGNAL ;
    PORT
      LAYER M4 ;
        RECT  0 12.432 0.084 12.456 ;
    END
  END b[190]
  PIN b[191]
    DIRECTION OUTPUT ;
    USE SIGNAL ;
    PORT
      LAYER M4 ;
        RECT  0 12.528 0.084 12.552 ;
    END
  END b[191]
  PIN b[192]
    DIRECTION OUTPUT ;
    USE SIGNAL ;
    PORT
      LAYER M4 ;
        RECT  0 18.768 0.084 18.792 ;
    END
  END b[192]
  PIN b[193]
    DIRECTION OUTPUT ;
    USE SIGNAL ;
    PORT
      LAYER M4 ;
        RECT  0 18.864 0.084 18.888 ;
    END
  END b[193]
  PIN b[194]
    DIRECTION OUTPUT ;
    USE SIGNAL ;
    PORT
      LAYER M4 ;
        RECT  0 18.96 0.084 18.984 ;
    END
  END b[194]
  PIN b[195]
    DIRECTION OUTPUT ;
    USE SIGNAL ;
    PORT
      LAYER M4 ;
        RECT  0 19.056 0.084 19.08 ;
    END
  END b[195]
  PIN b[196]
    DIRECTION OUTPUT ;
    USE SIGNAL ;
    PORT
      LAYER M4 ;
        RECT  0 19.152 0.084 19.176 ;
    END
  END b[196]
  PIN b[197]
    DIRECTION OUTPUT ;
    USE SIGNAL ;
    PORT
      LAYER M4 ;
        RECT  0 19.248 0.084 19.272 ;
    END
  END b[197]
  PIN b[198]
    DIRECTION OUTPUT ;
    USE SIGNAL ;
    PORT
      LAYER M4 ;
        RECT  0 19.344 0.084 19.368 ;
    END
  END b[198]
  PIN b[199]
    DIRECTION OUTPUT ;
    USE SIGNAL ;
    PORT
      LAYER M4 ;
        RECT  0 19.44 0.084 19.464 ;
    END
  END b[199]
  PIN b[19]
    DIRECTION OUTPUT ;
    USE SIGNAL ;
    PORT
      LAYER M4 ;
        RECT  0 49.776 0.084 49.8 ;
    END
  END b[19]
  PIN b[1]
    DIRECTION OUTPUT ;
    USE SIGNAL ;
    PORT
      LAYER M4 ;
        RECT  0 48.048 0.084 48.072 ;
    END
  END b[1]
  PIN b[200]
    DIRECTION OUTPUT ;
    USE SIGNAL ;
    PORT
      LAYER M4 ;
        RECT  0 19.536 0.084 19.56 ;
    END
  END b[200]
  PIN b[201]
    DIRECTION OUTPUT ;
    USE SIGNAL ;
    PORT
      LAYER M4 ;
        RECT  0 19.632 0.084 19.656 ;
    END
  END b[201]
  PIN b[202]
    DIRECTION OUTPUT ;
    USE SIGNAL ;
    PORT
      LAYER M4 ;
        RECT  0 19.728 0.084 19.752 ;
    END
  END b[202]
  PIN b[203]
    DIRECTION OUTPUT ;
    USE SIGNAL ;
    PORT
      LAYER M4 ;
        RECT  0 19.824 0.084 19.848 ;
    END
  END b[203]
  PIN b[204]
    DIRECTION OUTPUT ;
    USE SIGNAL ;
    PORT
      LAYER M4 ;
        RECT  0 19.92 0.084 19.944 ;
    END
  END b[204]
  PIN b[205]
    DIRECTION OUTPUT ;
    USE SIGNAL ;
    PORT
      LAYER M4 ;
        RECT  0 20.016 0.084 20.04 ;
    END
  END b[205]
  PIN b[206]
    DIRECTION OUTPUT ;
    USE SIGNAL ;
    PORT
      LAYER M4 ;
        RECT  0 20.112 0.084 20.136 ;
    END
  END b[206]
  PIN b[207]
    DIRECTION OUTPUT ;
    USE SIGNAL ;
    PORT
      LAYER M4 ;
        RECT  0 20.208 0.084 20.232 ;
    END
  END b[207]
  PIN b[208]
    DIRECTION OUTPUT ;
    USE SIGNAL ;
    PORT
      LAYER M4 ;
        RECT  0 20.304 0.084 20.328 ;
    END
  END b[208]
  PIN b[209]
    DIRECTION OUTPUT ;
    USE SIGNAL ;
    PORT
      LAYER M4 ;
        RECT  0 20.4 0.084 20.424 ;
    END
  END b[209]
  PIN b[20]
    DIRECTION OUTPUT ;
    USE SIGNAL ;
    PORT
      LAYER M4 ;
        RECT  0 49.872 0.084 49.896 ;
    END
  END b[20]
  PIN b[210]
    DIRECTION OUTPUT ;
    USE SIGNAL ;
    PORT
      LAYER M4 ;
        RECT  0 20.496 0.084 20.52 ;
    END
  END b[210]
  PIN b[211]
    DIRECTION OUTPUT ;
    USE SIGNAL ;
    PORT
      LAYER M4 ;
        RECT  0 20.592 0.084 20.616 ;
    END
  END b[211]
  PIN b[212]
    DIRECTION OUTPUT ;
    USE SIGNAL ;
    PORT
      LAYER M4 ;
        RECT  0 20.688 0.084 20.712 ;
    END
  END b[212]
  PIN b[213]
    DIRECTION OUTPUT ;
    USE SIGNAL ;
    PORT
      LAYER M4 ;
        RECT  0 20.784 0.084 20.808 ;
    END
  END b[213]
  PIN b[214]
    DIRECTION OUTPUT ;
    USE SIGNAL ;
    PORT
      LAYER M4 ;
        RECT  0 20.88 0.084 20.904 ;
    END
  END b[214]
  PIN b[215]
    DIRECTION OUTPUT ;
    USE SIGNAL ;
    PORT
      LAYER M4 ;
        RECT  0 20.976 0.084 21 ;
    END
  END b[215]
  PIN b[216]
    DIRECTION OUTPUT ;
    USE SIGNAL ;
    PORT
      LAYER M4 ;
        RECT  0 21.072 0.084 21.096 ;
    END
  END b[216]
  PIN b[217]
    DIRECTION OUTPUT ;
    USE SIGNAL ;
    PORT
      LAYER M4 ;
        RECT  0 21.168 0.084 21.192 ;
    END
  END b[217]
  PIN b[218]
    DIRECTION OUTPUT ;
    USE SIGNAL ;
    PORT
      LAYER M4 ;
        RECT  0 21.264 0.084 21.288 ;
    END
  END b[218]
  PIN b[219]
    DIRECTION OUTPUT ;
    USE SIGNAL ;
    PORT
      LAYER M4 ;
        RECT  0 21.36 0.084 21.384 ;
    END
  END b[219]
  PIN b[21]
    DIRECTION OUTPUT ;
    USE SIGNAL ;
    PORT
      LAYER M4 ;
        RECT  0 49.968 0.084 49.992 ;
    END
  END b[21]
  PIN b[220]
    DIRECTION OUTPUT ;
    USE SIGNAL ;
    PORT
      LAYER M4 ;
        RECT  0 21.456 0.084 21.48 ;
    END
  END b[220]
  PIN b[221]
    DIRECTION OUTPUT ;
    USE SIGNAL ;
    PORT
      LAYER M4 ;
        RECT  0 21.552 0.084 21.576 ;
    END
  END b[221]
  PIN b[222]
    DIRECTION OUTPUT ;
    USE SIGNAL ;
    PORT
      LAYER M4 ;
        RECT  0 21.648 0.084 21.672 ;
    END
  END b[222]
  PIN b[223]
    DIRECTION OUTPUT ;
    USE SIGNAL ;
    PORT
      LAYER M4 ;
        RECT  0 21.744 0.084 21.768 ;
    END
  END b[223]
  PIN b[224]
    DIRECTION OUTPUT ;
    USE SIGNAL ;
    PORT
      LAYER M4 ;
        RECT  0 34.896 0.084 34.92 ;
    END
  END b[224]
  PIN b[225]
    DIRECTION OUTPUT ;
    USE SIGNAL ;
    PORT
      LAYER M4 ;
        RECT  0 34.992 0.084 35.016 ;
    END
  END b[225]
  PIN b[226]
    DIRECTION OUTPUT ;
    USE SIGNAL ;
    PORT
      LAYER M4 ;
        RECT  0 35.088 0.084 35.112 ;
    END
  END b[226]
  PIN b[227]
    DIRECTION OUTPUT ;
    USE SIGNAL ;
    PORT
      LAYER M4 ;
        RECT  0 35.184 0.084 35.208 ;
    END
  END b[227]
  PIN b[228]
    DIRECTION OUTPUT ;
    USE SIGNAL ;
    PORT
      LAYER M4 ;
        RECT  0 35.28 0.084 35.304 ;
    END
  END b[228]
  PIN b[229]
    DIRECTION OUTPUT ;
    USE SIGNAL ;
    PORT
      LAYER M4 ;
        RECT  0 35.376 0.084 35.4 ;
    END
  END b[229]
  PIN b[22]
    DIRECTION OUTPUT ;
    USE SIGNAL ;
    PORT
      LAYER M4 ;
        RECT  0 50.064 0.084 50.088 ;
    END
  END b[22]
  PIN b[230]
    DIRECTION OUTPUT ;
    USE SIGNAL ;
    PORT
      LAYER M4 ;
        RECT  0 35.472 0.084 35.496 ;
    END
  END b[230]
  PIN b[231]
    DIRECTION OUTPUT ;
    USE SIGNAL ;
    PORT
      LAYER M4 ;
        RECT  0 35.568 0.084 35.592 ;
    END
  END b[231]
  PIN b[232]
    DIRECTION OUTPUT ;
    USE SIGNAL ;
    PORT
      LAYER M4 ;
        RECT  0 35.664 0.084 35.688 ;
    END
  END b[232]
  PIN b[233]
    DIRECTION OUTPUT ;
    USE SIGNAL ;
    PORT
      LAYER M4 ;
        RECT  0 35.76 0.084 35.784 ;
    END
  END b[233]
  PIN b[234]
    DIRECTION OUTPUT ;
    USE SIGNAL ;
    PORT
      LAYER M4 ;
        RECT  0 35.856 0.084 35.88 ;
    END
  END b[234]
  PIN b[235]
    DIRECTION OUTPUT ;
    USE SIGNAL ;
    PORT
      LAYER M4 ;
        RECT  0 35.952 0.084 35.976 ;
    END
  END b[235]
  PIN b[236]
    DIRECTION OUTPUT ;
    USE SIGNAL ;
    PORT
      LAYER M4 ;
        RECT  0 36.048 0.084 36.072 ;
    END
  END b[236]
  PIN b[237]
    DIRECTION OUTPUT ;
    USE SIGNAL ;
    PORT
      LAYER M4 ;
        RECT  0 36.144 0.084 36.168 ;
    END
  END b[237]
  PIN b[238]
    DIRECTION OUTPUT ;
    USE SIGNAL ;
    PORT
      LAYER M4 ;
        RECT  0 36.24 0.084 36.264 ;
    END
  END b[238]
  PIN b[239]
    DIRECTION OUTPUT ;
    USE SIGNAL ;
    PORT
      LAYER M4 ;
        RECT  0 36.336 0.084 36.36 ;
    END
  END b[239]
  PIN b[23]
    DIRECTION OUTPUT ;
    USE SIGNAL ;
    PORT
      LAYER M4 ;
        RECT  0 50.16 0.084 50.184 ;
    END
  END b[23]
  PIN b[240]
    DIRECTION OUTPUT ;
    USE SIGNAL ;
    PORT
      LAYER M4 ;
        RECT  0 36.432 0.084 36.456 ;
    END
  END b[240]
  PIN b[241]
    DIRECTION OUTPUT ;
    USE SIGNAL ;
    PORT
      LAYER M4 ;
        RECT  0 36.528 0.084 36.552 ;
    END
  END b[241]
  PIN b[242]
    DIRECTION OUTPUT ;
    USE SIGNAL ;
    PORT
      LAYER M4 ;
        RECT  0 36.624 0.084 36.648 ;
    END
  END b[242]
  PIN b[243]
    DIRECTION OUTPUT ;
    USE SIGNAL ;
    PORT
      LAYER M4 ;
        RECT  0 36.72 0.084 36.744 ;
    END
  END b[243]
  PIN b[244]
    DIRECTION OUTPUT ;
    USE SIGNAL ;
    PORT
      LAYER M4 ;
        RECT  0 36.816 0.084 36.84 ;
    END
  END b[244]
  PIN b[245]
    DIRECTION OUTPUT ;
    USE SIGNAL ;
    PORT
      LAYER M4 ;
        RECT  0 36.912 0.084 36.936 ;
    END
  END b[245]
  PIN b[246]
    DIRECTION OUTPUT ;
    USE SIGNAL ;
    PORT
      LAYER M4 ;
        RECT  0 37.008 0.084 37.032 ;
    END
  END b[246]
  PIN b[247]
    DIRECTION OUTPUT ;
    USE SIGNAL ;
    PORT
      LAYER M4 ;
        RECT  0 37.104 0.084 37.128 ;
    END
  END b[247]
  PIN b[248]
    DIRECTION OUTPUT ;
    USE SIGNAL ;
    PORT
      LAYER M4 ;
        RECT  0 37.2 0.084 37.224 ;
    END
  END b[248]
  PIN b[249]
    DIRECTION OUTPUT ;
    USE SIGNAL ;
    PORT
      LAYER M4 ;
        RECT  0 37.296 0.084 37.32 ;
    END
  END b[249]
  PIN b[24]
    DIRECTION OUTPUT ;
    USE SIGNAL ;
    PORT
      LAYER M4 ;
        RECT  0 50.256 0.084 50.28 ;
    END
  END b[24]
  PIN b[250]
    DIRECTION OUTPUT ;
    USE SIGNAL ;
    PORT
      LAYER M4 ;
        RECT  0 37.392 0.084 37.416 ;
    END
  END b[250]
  PIN b[251]
    DIRECTION OUTPUT ;
    USE SIGNAL ;
    PORT
      LAYER M4 ;
        RECT  0 37.488 0.084 37.512 ;
    END
  END b[251]
  PIN b[252]
    DIRECTION OUTPUT ;
    USE SIGNAL ;
    PORT
      LAYER M4 ;
        RECT  0 37.584 0.084 37.608 ;
    END
  END b[252]
  PIN b[253]
    DIRECTION OUTPUT ;
    USE SIGNAL ;
    PORT
      LAYER M4 ;
        RECT  0 37.68 0.084 37.704 ;
    END
  END b[253]
  PIN b[254]
    DIRECTION OUTPUT ;
    USE SIGNAL ;
    PORT
      LAYER M4 ;
        RECT  0 37.776 0.084 37.8 ;
    END
  END b[254]
  PIN b[255]
    DIRECTION OUTPUT ;
    USE SIGNAL ;
    PORT
      LAYER M4 ;
        RECT  0 37.872 0.084 37.896 ;
    END
  END b[255]
  PIN b[256]
    DIRECTION OUTPUT ;
    USE SIGNAL ;
    PORT
      LAYER M4 ;
        RECT  0 22.608 0.084 22.632 ;
    END
  END b[256]
  PIN b[257]
    DIRECTION OUTPUT ;
    USE SIGNAL ;
    PORT
      LAYER M4 ;
        RECT  0 22.704 0.084 22.728 ;
    END
  END b[257]
  PIN b[258]
    DIRECTION OUTPUT ;
    USE SIGNAL ;
    PORT
      LAYER M4 ;
        RECT  0 22.8 0.084 22.824 ;
    END
  END b[258]
  PIN b[259]
    DIRECTION OUTPUT ;
    USE SIGNAL ;
    PORT
      LAYER M4 ;
        RECT  0 22.896 0.084 22.92 ;
    END
  END b[259]
  PIN b[25]
    DIRECTION OUTPUT ;
    USE SIGNAL ;
    PORT
      LAYER M4 ;
        RECT  0 50.352 0.084 50.376 ;
    END
  END b[25]
  PIN b[260]
    DIRECTION OUTPUT ;
    USE SIGNAL ;
    PORT
      LAYER M4 ;
        RECT  0 22.992 0.084 23.016 ;
    END
  END b[260]
  PIN b[261]
    DIRECTION OUTPUT ;
    USE SIGNAL ;
    PORT
      LAYER M4 ;
        RECT  0 23.088 0.084 23.112 ;
    END
  END b[261]
  PIN b[262]
    DIRECTION OUTPUT ;
    USE SIGNAL ;
    PORT
      LAYER M4 ;
        RECT  0 23.184 0.084 23.208 ;
    END
  END b[262]
  PIN b[263]
    DIRECTION OUTPUT ;
    USE SIGNAL ;
    PORT
      LAYER M4 ;
        RECT  0 23.28 0.084 23.304 ;
    END
  END b[263]
  PIN b[264]
    DIRECTION OUTPUT ;
    USE SIGNAL ;
    PORT
      LAYER M4 ;
        RECT  0 23.376 0.084 23.4 ;
    END
  END b[264]
  PIN b[265]
    DIRECTION OUTPUT ;
    USE SIGNAL ;
    PORT
      LAYER M4 ;
        RECT  0 23.472 0.084 23.496 ;
    END
  END b[265]
  PIN b[266]
    DIRECTION OUTPUT ;
    USE SIGNAL ;
    PORT
      LAYER M4 ;
        RECT  0 23.568 0.084 23.592 ;
    END
  END b[266]
  PIN b[267]
    DIRECTION OUTPUT ;
    USE SIGNAL ;
    PORT
      LAYER M4 ;
        RECT  0 23.664 0.084 23.688 ;
    END
  END b[267]
  PIN b[268]
    DIRECTION OUTPUT ;
    USE SIGNAL ;
    PORT
      LAYER M4 ;
        RECT  0 23.76 0.084 23.784 ;
    END
  END b[268]
  PIN b[269]
    DIRECTION OUTPUT ;
    USE SIGNAL ;
    PORT
      LAYER M4 ;
        RECT  0 23.856 0.084 23.88 ;
    END
  END b[269]
  PIN b[26]
    DIRECTION OUTPUT ;
    USE SIGNAL ;
    PORT
      LAYER M4 ;
        RECT  0 50.448 0.084 50.472 ;
    END
  END b[26]
  PIN b[270]
    DIRECTION OUTPUT ;
    USE SIGNAL ;
    PORT
      LAYER M4 ;
        RECT  0 23.952 0.084 23.976 ;
    END
  END b[270]
  PIN b[271]
    DIRECTION OUTPUT ;
    USE SIGNAL ;
    PORT
      LAYER M4 ;
        RECT  0 24.048 0.084 24.072 ;
    END
  END b[271]
  PIN b[272]
    DIRECTION OUTPUT ;
    USE SIGNAL ;
    PORT
      LAYER M4 ;
        RECT  0 24.144 0.084 24.168 ;
    END
  END b[272]
  PIN b[273]
    DIRECTION OUTPUT ;
    USE SIGNAL ;
    PORT
      LAYER M4 ;
        RECT  0 24.24 0.084 24.264 ;
    END
  END b[273]
  PIN b[274]
    DIRECTION OUTPUT ;
    USE SIGNAL ;
    PORT
      LAYER M4 ;
        RECT  0 24.336 0.084 24.36 ;
    END
  END b[274]
  PIN b[275]
    DIRECTION OUTPUT ;
    USE SIGNAL ;
    PORT
      LAYER M4 ;
        RECT  0 24.432 0.084 24.456 ;
    END
  END b[275]
  PIN b[276]
    DIRECTION OUTPUT ;
    USE SIGNAL ;
    PORT
      LAYER M4 ;
        RECT  0 24.528 0.084 24.552 ;
    END
  END b[276]
  PIN b[277]
    DIRECTION OUTPUT ;
    USE SIGNAL ;
    PORT
      LAYER M4 ;
        RECT  0 24.624 0.084 24.648 ;
    END
  END b[277]
  PIN b[278]
    DIRECTION OUTPUT ;
    USE SIGNAL ;
    PORT
      LAYER M4 ;
        RECT  0 24.72 0.084 24.744 ;
    END
  END b[278]
  PIN b[279]
    DIRECTION OUTPUT ;
    USE SIGNAL ;
    PORT
      LAYER M4 ;
        RECT  0 24.816 0.084 24.84 ;
    END
  END b[279]
  PIN b[27]
    DIRECTION OUTPUT ;
    USE SIGNAL ;
    PORT
      LAYER M4 ;
        RECT  0 50.544 0.084 50.568 ;
    END
  END b[27]
  PIN b[280]
    DIRECTION OUTPUT ;
    USE SIGNAL ;
    PORT
      LAYER M4 ;
        RECT  0 24.912 0.084 24.936 ;
    END
  END b[280]
  PIN b[281]
    DIRECTION OUTPUT ;
    USE SIGNAL ;
    PORT
      LAYER M4 ;
        RECT  0 25.008 0.084 25.032 ;
    END
  END b[281]
  PIN b[282]
    DIRECTION OUTPUT ;
    USE SIGNAL ;
    PORT
      LAYER M4 ;
        RECT  0 25.104 0.084 25.128 ;
    END
  END b[282]
  PIN b[283]
    DIRECTION OUTPUT ;
    USE SIGNAL ;
    PORT
      LAYER M4 ;
        RECT  0 25.2 0.084 25.224 ;
    END
  END b[283]
  PIN b[284]
    DIRECTION OUTPUT ;
    USE SIGNAL ;
    PORT
      LAYER M4 ;
        RECT  0 25.296 0.084 25.32 ;
    END
  END b[284]
  PIN b[285]
    DIRECTION OUTPUT ;
    USE SIGNAL ;
    PORT
      LAYER M4 ;
        RECT  0 25.392 0.084 25.416 ;
    END
  END b[285]
  PIN b[286]
    DIRECTION OUTPUT ;
    USE SIGNAL ;
    PORT
      LAYER M4 ;
        RECT  0 25.488 0.084 25.512 ;
    END
  END b[286]
  PIN b[287]
    DIRECTION OUTPUT ;
    USE SIGNAL ;
    PORT
      LAYER M4 ;
        RECT  0 25.584 0.084 25.608 ;
    END
  END b[287]
  PIN b[288]
    DIRECTION OUTPUT ;
    USE SIGNAL ;
    PORT
      LAYER M4 ;
        RECT  0 51.024 0.084 51.048 ;
    END
  END b[288]
  PIN b[289]
    DIRECTION OUTPUT ;
    USE SIGNAL ;
    PORT
      LAYER M4 ;
        RECT  0 51.12 0.084 51.144 ;
    END
  END b[289]
  PIN b[28]
    DIRECTION OUTPUT ;
    USE SIGNAL ;
    PORT
      LAYER M4 ;
        RECT  0 50.64 0.084 50.664 ;
    END
  END b[28]
  PIN b[290]
    DIRECTION OUTPUT ;
    USE SIGNAL ;
    PORT
      LAYER M4 ;
        RECT  0 51.216 0.084 51.24 ;
    END
  END b[290]
  PIN b[291]
    DIRECTION OUTPUT ;
    USE SIGNAL ;
    PORT
      LAYER M4 ;
        RECT  0 51.312 0.084 51.336 ;
    END
  END b[291]
  PIN b[292]
    DIRECTION OUTPUT ;
    USE SIGNAL ;
    PORT
      LAYER M4 ;
        RECT  0 51.408 0.084 51.432 ;
    END
  END b[292]
  PIN b[293]
    DIRECTION OUTPUT ;
    USE SIGNAL ;
    PORT
      LAYER M4 ;
        RECT  0 51.504 0.084 51.528 ;
    END
  END b[293]
  PIN b[294]
    DIRECTION OUTPUT ;
    USE SIGNAL ;
    PORT
      LAYER M4 ;
        RECT  0 51.6 0.084 51.624 ;
    END
  END b[294]
  PIN b[295]
    DIRECTION OUTPUT ;
    USE SIGNAL ;
    PORT
      LAYER M4 ;
        RECT  0 51.696 0.084 51.72 ;
    END
  END b[295]
  PIN b[296]
    DIRECTION OUTPUT ;
    USE SIGNAL ;
    PORT
      LAYER M4 ;
        RECT  0 51.792 0.084 51.816 ;
    END
  END b[296]
  PIN b[297]
    DIRECTION OUTPUT ;
    USE SIGNAL ;
    PORT
      LAYER M4 ;
        RECT  0 51.888 0.084 51.912 ;
    END
  END b[297]
  PIN b[298]
    DIRECTION OUTPUT ;
    USE SIGNAL ;
    PORT
      LAYER M4 ;
        RECT  0 51.984 0.084 52.008 ;
    END
  END b[298]
  PIN b[299]
    DIRECTION OUTPUT ;
    USE SIGNAL ;
    PORT
      LAYER M4 ;
        RECT  0 52.08 0.084 52.104 ;
    END
  END b[299]
  PIN b[29]
    DIRECTION OUTPUT ;
    USE SIGNAL ;
    PORT
      LAYER M4 ;
        RECT  0 50.736 0.084 50.76 ;
    END
  END b[29]
  PIN b[2]
    DIRECTION OUTPUT ;
    USE SIGNAL ;
    PORT
      LAYER M4 ;
        RECT  0 48.144 0.084 48.168 ;
    END
  END b[2]
  PIN b[300]
    DIRECTION OUTPUT ;
    USE SIGNAL ;
    PORT
      LAYER M4 ;
        RECT  0 52.176 0.084 52.2 ;
    END
  END b[300]
  PIN b[301]
    DIRECTION OUTPUT ;
    USE SIGNAL ;
    PORT
      LAYER M4 ;
        RECT  0 52.272 0.084 52.296 ;
    END
  END b[301]
  PIN b[302]
    DIRECTION OUTPUT ;
    USE SIGNAL ;
    PORT
      LAYER M4 ;
        RECT  0 52.368 0.084 52.392 ;
    END
  END b[302]
  PIN b[303]
    DIRECTION OUTPUT ;
    USE SIGNAL ;
    PORT
      LAYER M4 ;
        RECT  0 52.464 0.084 52.488 ;
    END
  END b[303]
  PIN b[304]
    DIRECTION OUTPUT ;
    USE SIGNAL ;
    PORT
      LAYER M4 ;
        RECT  0 52.56 0.084 52.584 ;
    END
  END b[304]
  PIN b[305]
    DIRECTION OUTPUT ;
    USE SIGNAL ;
    PORT
      LAYER M4 ;
        RECT  0 52.656 0.084 52.68 ;
    END
  END b[305]
  PIN b[306]
    DIRECTION OUTPUT ;
    USE SIGNAL ;
    PORT
      LAYER M4 ;
        RECT  0 52.752 0.084 52.776 ;
    END
  END b[306]
  PIN b[307]
    DIRECTION OUTPUT ;
    USE SIGNAL ;
    PORT
      LAYER M4 ;
        RECT  0 52.848 0.084 52.872 ;
    END
  END b[307]
  PIN b[308]
    DIRECTION OUTPUT ;
    USE SIGNAL ;
    PORT
      LAYER M4 ;
        RECT  0 52.944 0.084 52.968 ;
    END
  END b[308]
  PIN b[309]
    DIRECTION OUTPUT ;
    USE SIGNAL ;
    PORT
      LAYER M4 ;
        RECT  0 53.04 0.084 53.064 ;
    END
  END b[309]
  PIN b[30]
    DIRECTION OUTPUT ;
    USE SIGNAL ;
    PORT
      LAYER M4 ;
        RECT  0 50.832 0.084 50.856 ;
    END
  END b[30]
  PIN b[310]
    DIRECTION OUTPUT ;
    USE SIGNAL ;
    PORT
      LAYER M4 ;
        RECT  0 53.136 0.084 53.16 ;
    END
  END b[310]
  PIN b[311]
    DIRECTION OUTPUT ;
    USE SIGNAL ;
    PORT
      LAYER M4 ;
        RECT  0 53.232 0.084 53.256 ;
    END
  END b[311]
  PIN b[312]
    DIRECTION OUTPUT ;
    USE SIGNAL ;
    PORT
      LAYER M4 ;
        RECT  0 53.328 0.084 53.352 ;
    END
  END b[312]
  PIN b[313]
    DIRECTION OUTPUT ;
    USE SIGNAL ;
    PORT
      LAYER M4 ;
        RECT  0 53.424 0.084 53.448 ;
    END
  END b[313]
  PIN b[314]
    DIRECTION OUTPUT ;
    USE SIGNAL ;
    PORT
      LAYER M4 ;
        RECT  0 53.52 0.084 53.544 ;
    END
  END b[314]
  PIN b[315]
    DIRECTION OUTPUT ;
    USE SIGNAL ;
    PORT
      LAYER M4 ;
        RECT  0 53.616 0.084 53.64 ;
    END
  END b[315]
  PIN b[316]
    DIRECTION OUTPUT ;
    USE SIGNAL ;
    PORT
      LAYER M4 ;
        RECT  0 53.712 0.084 53.736 ;
    END
  END b[316]
  PIN b[317]
    DIRECTION OUTPUT ;
    USE SIGNAL ;
    PORT
      LAYER M4 ;
        RECT  0 53.808 0.084 53.832 ;
    END
  END b[317]
  PIN b[318]
    DIRECTION OUTPUT ;
    USE SIGNAL ;
    PORT
      LAYER M4 ;
        RECT  0 53.904 0.084 53.928 ;
    END
  END b[318]
  PIN b[319]
    DIRECTION OUTPUT ;
    USE SIGNAL ;
    PORT
      LAYER M4 ;
        RECT  0 54 0.084 54.024 ;
    END
  END b[319]
  PIN b[31]
    DIRECTION OUTPUT ;
    USE SIGNAL ;
    PORT
      LAYER M4 ;
        RECT  0 50.928 0.084 50.952 ;
    END
  END b[31]
  PIN b[320]
    DIRECTION OUTPUT ;
    USE SIGNAL ;
    PORT
      LAYER M4 ;
        RECT  0 61.008 0.084 61.032 ;
    END
  END b[320]
  PIN b[321]
    DIRECTION OUTPUT ;
    USE SIGNAL ;
    PORT
      LAYER M4 ;
        RECT  0 61.104 0.084 61.128 ;
    END
  END b[321]
  PIN b[322]
    DIRECTION OUTPUT ;
    USE SIGNAL ;
    PORT
      LAYER M4 ;
        RECT  0 61.2 0.084 61.224 ;
    END
  END b[322]
  PIN b[323]
    DIRECTION OUTPUT ;
    USE SIGNAL ;
    PORT
      LAYER M4 ;
        RECT  0 61.296 0.084 61.32 ;
    END
  END b[323]
  PIN b[324]
    DIRECTION OUTPUT ;
    USE SIGNAL ;
    PORT
      LAYER M4 ;
        RECT  0 61.392 0.084 61.416 ;
    END
  END b[324]
  PIN b[325]
    DIRECTION OUTPUT ;
    USE SIGNAL ;
    PORT
      LAYER M4 ;
        RECT  0 61.488 0.084 61.512 ;
    END
  END b[325]
  PIN b[326]
    DIRECTION OUTPUT ;
    USE SIGNAL ;
    PORT
      LAYER M4 ;
        RECT  0 61.584 0.084 61.608 ;
    END
  END b[326]
  PIN b[327]
    DIRECTION OUTPUT ;
    USE SIGNAL ;
    PORT
      LAYER M4 ;
        RECT  0 61.68 0.084 61.704 ;
    END
  END b[327]
  PIN b[328]
    DIRECTION OUTPUT ;
    USE SIGNAL ;
    PORT
      LAYER M4 ;
        RECT  0 61.776 0.084 61.8 ;
    END
  END b[328]
  PIN b[329]
    DIRECTION OUTPUT ;
    USE SIGNAL ;
    PORT
      LAYER M4 ;
        RECT  0 61.872 0.084 61.896 ;
    END
  END b[329]
  PIN b[32]
    DIRECTION OUTPUT ;
    USE SIGNAL ;
    PORT
      LAYER M4 ;
        RECT  0 44.88 0.084 44.904 ;
    END
  END b[32]
  PIN b[330]
    DIRECTION OUTPUT ;
    USE SIGNAL ;
    PORT
      LAYER M4 ;
        RECT  0 61.968 0.084 61.992 ;
    END
  END b[330]
  PIN b[331]
    DIRECTION OUTPUT ;
    USE SIGNAL ;
    PORT
      LAYER M4 ;
        RECT  0 62.064 0.084 62.088 ;
    END
  END b[331]
  PIN b[332]
    DIRECTION OUTPUT ;
    USE SIGNAL ;
    PORT
      LAYER M4 ;
        RECT  0 62.16 0.084 62.184 ;
    END
  END b[332]
  PIN b[333]
    DIRECTION OUTPUT ;
    USE SIGNAL ;
    PORT
      LAYER M4 ;
        RECT  0 62.256 0.084 62.28 ;
    END
  END b[333]
  PIN b[334]
    DIRECTION OUTPUT ;
    USE SIGNAL ;
    PORT
      LAYER M4 ;
        RECT  0 62.352 0.084 62.376 ;
    END
  END b[334]
  PIN b[335]
    DIRECTION OUTPUT ;
    USE SIGNAL ;
    PORT
      LAYER M4 ;
        RECT  0 62.448 0.084 62.472 ;
    END
  END b[335]
  PIN b[336]
    DIRECTION OUTPUT ;
    USE SIGNAL ;
    PORT
      LAYER M4 ;
        RECT  0 62.544 0.084 62.568 ;
    END
  END b[336]
  PIN b[337]
    DIRECTION OUTPUT ;
    USE SIGNAL ;
    PORT
      LAYER M4 ;
        RECT  0 62.64 0.084 62.664 ;
    END
  END b[337]
  PIN b[338]
    DIRECTION OUTPUT ;
    USE SIGNAL ;
    PORT
      LAYER M4 ;
        RECT  0 62.736 0.084 62.76 ;
    END
  END b[338]
  PIN b[339]
    DIRECTION OUTPUT ;
    USE SIGNAL ;
    PORT
      LAYER M4 ;
        RECT  0 62.832 0.084 62.856 ;
    END
  END b[339]
  PIN b[33]
    DIRECTION OUTPUT ;
    USE SIGNAL ;
    PORT
      LAYER M4 ;
        RECT  0 44.976 0.084 45 ;
    END
  END b[33]
  PIN b[340]
    DIRECTION OUTPUT ;
    USE SIGNAL ;
    PORT
      LAYER M4 ;
        RECT  0 62.928 0.084 62.952 ;
    END
  END b[340]
  PIN b[341]
    DIRECTION OUTPUT ;
    USE SIGNAL ;
    PORT
      LAYER M4 ;
        RECT  0 63.024 0.084 63.048 ;
    END
  END b[341]
  PIN b[342]
    DIRECTION OUTPUT ;
    USE SIGNAL ;
    PORT
      LAYER M4 ;
        RECT  0 63.12 0.084 63.144 ;
    END
  END b[342]
  PIN b[343]
    DIRECTION OUTPUT ;
    USE SIGNAL ;
    PORT
      LAYER M4 ;
        RECT  0 63.216 0.084 63.24 ;
    END
  END b[343]
  PIN b[344]
    DIRECTION OUTPUT ;
    USE SIGNAL ;
    PORT
      LAYER M4 ;
        RECT  0 63.312 0.084 63.336 ;
    END
  END b[344]
  PIN b[345]
    DIRECTION OUTPUT ;
    USE SIGNAL ;
    PORT
      LAYER M4 ;
        RECT  0 63.408 0.084 63.432 ;
    END
  END b[345]
  PIN b[346]
    DIRECTION OUTPUT ;
    USE SIGNAL ;
    PORT
      LAYER M4 ;
        RECT  0 63.504 0.084 63.528 ;
    END
  END b[346]
  PIN b[347]
    DIRECTION OUTPUT ;
    USE SIGNAL ;
    PORT
      LAYER M4 ;
        RECT  0 63.6 0.084 63.624 ;
    END
  END b[347]
  PIN b[348]
    DIRECTION OUTPUT ;
    USE SIGNAL ;
    PORT
      LAYER M4 ;
        RECT  0 63.696 0.084 63.72 ;
    END
  END b[348]
  PIN b[349]
    DIRECTION OUTPUT ;
    USE SIGNAL ;
    PORT
      LAYER M4 ;
        RECT  0 63.792 0.084 63.816 ;
    END
  END b[349]
  PIN b[34]
    DIRECTION OUTPUT ;
    USE SIGNAL ;
    PORT
      LAYER M4 ;
        RECT  0 45.072 0.084 45.096 ;
    END
  END b[34]
  PIN b[350]
    DIRECTION OUTPUT ;
    USE SIGNAL ;
    PORT
      LAYER M4 ;
        RECT  0 63.888 0.084 63.912 ;
    END
  END b[350]
  PIN b[351]
    DIRECTION OUTPUT ;
    USE SIGNAL ;
    PORT
      LAYER M4 ;
        RECT  0 63.984 0.084 64.008 ;
    END
  END b[351]
  PIN b[352]
    DIRECTION OUTPUT ;
    USE SIGNAL ;
    PORT
      LAYER M4 ;
        RECT  0 83.28 0.084 83.304 ;
    END
  END b[352]
  PIN b[353]
    DIRECTION OUTPUT ;
    USE SIGNAL ;
    PORT
      LAYER M4 ;
        RECT  0 83.376 0.084 83.4 ;
    END
  END b[353]
  PIN b[354]
    DIRECTION OUTPUT ;
    USE SIGNAL ;
    PORT
      LAYER M4 ;
        RECT  0 83.472 0.084 83.496 ;
    END
  END b[354]
  PIN b[355]
    DIRECTION OUTPUT ;
    USE SIGNAL ;
    PORT
      LAYER M4 ;
        RECT  0 83.568 0.084 83.592 ;
    END
  END b[355]
  PIN b[356]
    DIRECTION OUTPUT ;
    USE SIGNAL ;
    PORT
      LAYER M4 ;
        RECT  0 83.664 0.084 83.688 ;
    END
  END b[356]
  PIN b[357]
    DIRECTION OUTPUT ;
    USE SIGNAL ;
    PORT
      LAYER M4 ;
        RECT  0 83.76 0.084 83.784 ;
    END
  END b[357]
  PIN b[358]
    DIRECTION OUTPUT ;
    USE SIGNAL ;
    PORT
      LAYER M4 ;
        RECT  0 83.856 0.084 83.88 ;
    END
  END b[358]
  PIN b[359]
    DIRECTION OUTPUT ;
    USE SIGNAL ;
    PORT
      LAYER M4 ;
        RECT  0 83.952 0.084 83.976 ;
    END
  END b[359]
  PIN b[35]
    DIRECTION OUTPUT ;
    USE SIGNAL ;
    PORT
      LAYER M4 ;
        RECT  0 45.168 0.084 45.192 ;
    END
  END b[35]
  PIN b[360]
    DIRECTION OUTPUT ;
    USE SIGNAL ;
    PORT
      LAYER M4 ;
        RECT  0 84.048 0.084 84.072 ;
    END
  END b[360]
  PIN b[361]
    DIRECTION OUTPUT ;
    USE SIGNAL ;
    PORT
      LAYER M4 ;
        RECT  0 84.144 0.084 84.168 ;
    END
  END b[361]
  PIN b[362]
    DIRECTION OUTPUT ;
    USE SIGNAL ;
    PORT
      LAYER M4 ;
        RECT  0 84.24 0.084 84.264 ;
    END
  END b[362]
  PIN b[363]
    DIRECTION OUTPUT ;
    USE SIGNAL ;
    PORT
      LAYER M4 ;
        RECT  0 84.336 0.084 84.36 ;
    END
  END b[363]
  PIN b[364]
    DIRECTION OUTPUT ;
    USE SIGNAL ;
    PORT
      LAYER M4 ;
        RECT  0 84.432 0.084 84.456 ;
    END
  END b[364]
  PIN b[365]
    DIRECTION OUTPUT ;
    USE SIGNAL ;
    PORT
      LAYER M4 ;
        RECT  0 84.528 0.084 84.552 ;
    END
  END b[365]
  PIN b[366]
    DIRECTION OUTPUT ;
    USE SIGNAL ;
    PORT
      LAYER M4 ;
        RECT  0 84.624 0.084 84.648 ;
    END
  END b[366]
  PIN b[367]
    DIRECTION OUTPUT ;
    USE SIGNAL ;
    PORT
      LAYER M4 ;
        RECT  0 84.72 0.084 84.744 ;
    END
  END b[367]
  PIN b[368]
    DIRECTION OUTPUT ;
    USE SIGNAL ;
    PORT
      LAYER M4 ;
        RECT  0 84.816 0.084 84.84 ;
    END
  END b[368]
  PIN b[369]
    DIRECTION OUTPUT ;
    USE SIGNAL ;
    PORT
      LAYER M4 ;
        RECT  0 84.912 0.084 84.936 ;
    END
  END b[369]
  PIN b[36]
    DIRECTION OUTPUT ;
    USE SIGNAL ;
    PORT
      LAYER M4 ;
        RECT  0 45.264 0.084 45.288 ;
    END
  END b[36]
  PIN b[370]
    DIRECTION OUTPUT ;
    USE SIGNAL ;
    PORT
      LAYER M4 ;
        RECT  0 85.008 0.084 85.032 ;
    END
  END b[370]
  PIN b[371]
    DIRECTION OUTPUT ;
    USE SIGNAL ;
    PORT
      LAYER M4 ;
        RECT  0 85.104 0.084 85.128 ;
    END
  END b[371]
  PIN b[372]
    DIRECTION OUTPUT ;
    USE SIGNAL ;
    PORT
      LAYER M4 ;
        RECT  0 85.2 0.084 85.224 ;
    END
  END b[372]
  PIN b[373]
    DIRECTION OUTPUT ;
    USE SIGNAL ;
    PORT
      LAYER M4 ;
        RECT  0 85.296 0.084 85.32 ;
    END
  END b[373]
  PIN b[374]
    DIRECTION OUTPUT ;
    USE SIGNAL ;
    PORT
      LAYER M4 ;
        RECT  0 85.392 0.084 85.416 ;
    END
  END b[374]
  PIN b[375]
    DIRECTION OUTPUT ;
    USE SIGNAL ;
    PORT
      LAYER M4 ;
        RECT  0 85.488 0.084 85.512 ;
    END
  END b[375]
  PIN b[376]
    DIRECTION OUTPUT ;
    USE SIGNAL ;
    PORT
      LAYER M4 ;
        RECT  0 85.584 0.084 85.608 ;
    END
  END b[376]
  PIN b[377]
    DIRECTION OUTPUT ;
    USE SIGNAL ;
    PORT
      LAYER M4 ;
        RECT  0 85.68 0.084 85.704 ;
    END
  END b[377]
  PIN b[378]
    DIRECTION OUTPUT ;
    USE SIGNAL ;
    PORT
      LAYER M4 ;
        RECT  0 85.776 0.084 85.8 ;
    END
  END b[378]
  PIN b[379]
    DIRECTION OUTPUT ;
    USE SIGNAL ;
    PORT
      LAYER M4 ;
        RECT  0 85.872 0.084 85.896 ;
    END
  END b[379]
  PIN b[37]
    DIRECTION OUTPUT ;
    USE SIGNAL ;
    PORT
      LAYER M4 ;
        RECT  0 45.36 0.084 45.384 ;
    END
  END b[37]
  PIN b[380]
    DIRECTION OUTPUT ;
    USE SIGNAL ;
    PORT
      LAYER M4 ;
        RECT  0 85.968 0.084 85.992 ;
    END
  END b[380]
  PIN b[381]
    DIRECTION OUTPUT ;
    USE SIGNAL ;
    PORT
      LAYER M4 ;
        RECT  0 86.064 0.084 86.088 ;
    END
  END b[381]
  PIN b[382]
    DIRECTION OUTPUT ;
    USE SIGNAL ;
    PORT
      LAYER M4 ;
        RECT  0 86.16 0.084 86.184 ;
    END
  END b[382]
  PIN b[383]
    DIRECTION OUTPUT ;
    USE SIGNAL ;
    PORT
      LAYER M4 ;
        RECT  0 86.256 0.084 86.28 ;
    END
  END b[383]
  PIN b[384]
    DIRECTION OUTPUT ;
    USE SIGNAL ;
    PORT
      LAYER M4 ;
        RECT  0 80.208 0.084 80.232 ;
    END
  END b[384]
  PIN b[385]
    DIRECTION OUTPUT ;
    USE SIGNAL ;
    PORT
      LAYER M4 ;
        RECT  0 80.304 0.084 80.328 ;
    END
  END b[385]
  PIN b[386]
    DIRECTION OUTPUT ;
    USE SIGNAL ;
    PORT
      LAYER M4 ;
        RECT  0 80.4 0.084 80.424 ;
    END
  END b[386]
  PIN b[387]
    DIRECTION OUTPUT ;
    USE SIGNAL ;
    PORT
      LAYER M4 ;
        RECT  0 80.496 0.084 80.52 ;
    END
  END b[387]
  PIN b[388]
    DIRECTION OUTPUT ;
    USE SIGNAL ;
    PORT
      LAYER M4 ;
        RECT  0 80.592 0.084 80.616 ;
    END
  END b[388]
  PIN b[389]
    DIRECTION OUTPUT ;
    USE SIGNAL ;
    PORT
      LAYER M4 ;
        RECT  0 80.688 0.084 80.712 ;
    END
  END b[389]
  PIN b[38]
    DIRECTION OUTPUT ;
    USE SIGNAL ;
    PORT
      LAYER M4 ;
        RECT  0 45.456 0.084 45.48 ;
    END
  END b[38]
  PIN b[390]
    DIRECTION OUTPUT ;
    USE SIGNAL ;
    PORT
      LAYER M4 ;
        RECT  0 80.784 0.084 80.808 ;
    END
  END b[390]
  PIN b[391]
    DIRECTION OUTPUT ;
    USE SIGNAL ;
    PORT
      LAYER M4 ;
        RECT  0 80.88 0.084 80.904 ;
    END
  END b[391]
  PIN b[392]
    DIRECTION OUTPUT ;
    USE SIGNAL ;
    PORT
      LAYER M4 ;
        RECT  0 80.976 0.084 81 ;
    END
  END b[392]
  PIN b[393]
    DIRECTION OUTPUT ;
    USE SIGNAL ;
    PORT
      LAYER M4 ;
        RECT  0 81.072 0.084 81.096 ;
    END
  END b[393]
  PIN b[394]
    DIRECTION OUTPUT ;
    USE SIGNAL ;
    PORT
      LAYER M4 ;
        RECT  0 81.168 0.084 81.192 ;
    END
  END b[394]
  PIN b[395]
    DIRECTION OUTPUT ;
    USE SIGNAL ;
    PORT
      LAYER M4 ;
        RECT  0 81.264 0.084 81.288 ;
    END
  END b[395]
  PIN b[396]
    DIRECTION OUTPUT ;
    USE SIGNAL ;
    PORT
      LAYER M4 ;
        RECT  0 81.36 0.084 81.384 ;
    END
  END b[396]
  PIN b[397]
    DIRECTION OUTPUT ;
    USE SIGNAL ;
    PORT
      LAYER M4 ;
        RECT  0 81.456 0.084 81.48 ;
    END
  END b[397]
  PIN b[398]
    DIRECTION OUTPUT ;
    USE SIGNAL ;
    PORT
      LAYER M4 ;
        RECT  0 81.552 0.084 81.576 ;
    END
  END b[398]
  PIN b[399]
    DIRECTION OUTPUT ;
    USE SIGNAL ;
    PORT
      LAYER M4 ;
        RECT  0 81.648 0.084 81.672 ;
    END
  END b[399]
  PIN b[39]
    DIRECTION OUTPUT ;
    USE SIGNAL ;
    PORT
      LAYER M4 ;
        RECT  0 45.552 0.084 45.576 ;
    END
  END b[39]
  PIN b[3]
    DIRECTION OUTPUT ;
    USE SIGNAL ;
    PORT
      LAYER M4 ;
        RECT  0 48.24 0.084 48.264 ;
    END
  END b[3]
  PIN b[400]
    DIRECTION OUTPUT ;
    USE SIGNAL ;
    PORT
      LAYER M4 ;
        RECT  0 81.744 0.084 81.768 ;
    END
  END b[400]
  PIN b[401]
    DIRECTION OUTPUT ;
    USE SIGNAL ;
    PORT
      LAYER M4 ;
        RECT  0 81.84 0.084 81.864 ;
    END
  END b[401]
  PIN b[402]
    DIRECTION OUTPUT ;
    USE SIGNAL ;
    PORT
      LAYER M4 ;
        RECT  0 81.936 0.084 81.96 ;
    END
  END b[402]
  PIN b[403]
    DIRECTION OUTPUT ;
    USE SIGNAL ;
    PORT
      LAYER M4 ;
        RECT  0 82.032 0.084 82.056 ;
    END
  END b[403]
  PIN b[404]
    DIRECTION OUTPUT ;
    USE SIGNAL ;
    PORT
      LAYER M4 ;
        RECT  0 82.128 0.084 82.152 ;
    END
  END b[404]
  PIN b[405]
    DIRECTION OUTPUT ;
    USE SIGNAL ;
    PORT
      LAYER M4 ;
        RECT  0 82.224 0.084 82.248 ;
    END
  END b[405]
  PIN b[406]
    DIRECTION OUTPUT ;
    USE SIGNAL ;
    PORT
      LAYER M4 ;
        RECT  0 82.32 0.084 82.344 ;
    END
  END b[406]
  PIN b[407]
    DIRECTION OUTPUT ;
    USE SIGNAL ;
    PORT
      LAYER M4 ;
        RECT  0 82.416 0.084 82.44 ;
    END
  END b[407]
  PIN b[408]
    DIRECTION OUTPUT ;
    USE SIGNAL ;
    PORT
      LAYER M4 ;
        RECT  0 82.512 0.084 82.536 ;
    END
  END b[408]
  PIN b[409]
    DIRECTION OUTPUT ;
    USE SIGNAL ;
    PORT
      LAYER M4 ;
        RECT  0 82.608 0.084 82.632 ;
    END
  END b[409]
  PIN b[40]
    DIRECTION OUTPUT ;
    USE SIGNAL ;
    PORT
      LAYER M4 ;
        RECT  0 45.648 0.084 45.672 ;
    END
  END b[40]
  PIN b[410]
    DIRECTION OUTPUT ;
    USE SIGNAL ;
    PORT
      LAYER M4 ;
        RECT  0 82.704 0.084 82.728 ;
    END
  END b[410]
  PIN b[411]
    DIRECTION OUTPUT ;
    USE SIGNAL ;
    PORT
      LAYER M4 ;
        RECT  0 82.8 0.084 82.824 ;
    END
  END b[411]
  PIN b[412]
    DIRECTION OUTPUT ;
    USE SIGNAL ;
    PORT
      LAYER M4 ;
        RECT  0 82.896 0.084 82.92 ;
    END
  END b[412]
  PIN b[413]
    DIRECTION OUTPUT ;
    USE SIGNAL ;
    PORT
      LAYER M4 ;
        RECT  0 82.992 0.084 83.016 ;
    END
  END b[413]
  PIN b[414]
    DIRECTION OUTPUT ;
    USE SIGNAL ;
    PORT
      LAYER M4 ;
        RECT  0 83.088 0.084 83.112 ;
    END
  END b[414]
  PIN b[415]
    DIRECTION OUTPUT ;
    USE SIGNAL ;
    PORT
      LAYER M4 ;
        RECT  0 83.184 0.084 83.208 ;
    END
  END b[415]
  PIN b[416]
    DIRECTION OUTPUT ;
    USE SIGNAL ;
    PORT
      LAYER M4 ;
        RECT  0 73.296 0.084 73.32 ;
    END
  END b[416]
  PIN b[417]
    DIRECTION OUTPUT ;
    USE SIGNAL ;
    PORT
      LAYER M4 ;
        RECT  0 73.392 0.084 73.416 ;
    END
  END b[417]
  PIN b[418]
    DIRECTION OUTPUT ;
    USE SIGNAL ;
    PORT
      LAYER M4 ;
        RECT  0 73.488 0.084 73.512 ;
    END
  END b[418]
  PIN b[419]
    DIRECTION OUTPUT ;
    USE SIGNAL ;
    PORT
      LAYER M4 ;
        RECT  0 73.584 0.084 73.608 ;
    END
  END b[419]
  PIN b[41]
    DIRECTION OUTPUT ;
    USE SIGNAL ;
    PORT
      LAYER M4 ;
        RECT  0 45.744 0.084 45.768 ;
    END
  END b[41]
  PIN b[420]
    DIRECTION OUTPUT ;
    USE SIGNAL ;
    PORT
      LAYER M4 ;
        RECT  0 73.68 0.084 73.704 ;
    END
  END b[420]
  PIN b[421]
    DIRECTION OUTPUT ;
    USE SIGNAL ;
    PORT
      LAYER M4 ;
        RECT  0 73.776 0.084 73.8 ;
    END
  END b[421]
  PIN b[422]
    DIRECTION OUTPUT ;
    USE SIGNAL ;
    PORT
      LAYER M4 ;
        RECT  0 73.872 0.084 73.896 ;
    END
  END b[422]
  PIN b[423]
    DIRECTION OUTPUT ;
    USE SIGNAL ;
    PORT
      LAYER M4 ;
        RECT  0 73.968 0.084 73.992 ;
    END
  END b[423]
  PIN b[424]
    DIRECTION OUTPUT ;
    USE SIGNAL ;
    PORT
      LAYER M4 ;
        RECT  0 74.064 0.084 74.088 ;
    END
  END b[424]
  PIN b[425]
    DIRECTION OUTPUT ;
    USE SIGNAL ;
    PORT
      LAYER M4 ;
        RECT  0 74.16 0.084 74.184 ;
    END
  END b[425]
  PIN b[426]
    DIRECTION OUTPUT ;
    USE SIGNAL ;
    PORT
      LAYER M4 ;
        RECT  0 74.256 0.084 74.28 ;
    END
  END b[426]
  PIN b[427]
    DIRECTION OUTPUT ;
    USE SIGNAL ;
    PORT
      LAYER M4 ;
        RECT  0 74.352 0.084 74.376 ;
    END
  END b[427]
  PIN b[428]
    DIRECTION OUTPUT ;
    USE SIGNAL ;
    PORT
      LAYER M4 ;
        RECT  0 74.448 0.084 74.472 ;
    END
  END b[428]
  PIN b[429]
    DIRECTION OUTPUT ;
    USE SIGNAL ;
    PORT
      LAYER M4 ;
        RECT  0 74.544 0.084 74.568 ;
    END
  END b[429]
  PIN b[42]
    DIRECTION OUTPUT ;
    USE SIGNAL ;
    PORT
      LAYER M4 ;
        RECT  0 45.84 0.084 45.864 ;
    END
  END b[42]
  PIN b[430]
    DIRECTION OUTPUT ;
    USE SIGNAL ;
    PORT
      LAYER M4 ;
        RECT  0 74.64 0.084 74.664 ;
    END
  END b[430]
  PIN b[431]
    DIRECTION OUTPUT ;
    USE SIGNAL ;
    PORT
      LAYER M4 ;
        RECT  0 74.736 0.084 74.76 ;
    END
  END b[431]
  PIN b[432]
    DIRECTION OUTPUT ;
    USE SIGNAL ;
    PORT
      LAYER M4 ;
        RECT  0 74.832 0.084 74.856 ;
    END
  END b[432]
  PIN b[433]
    DIRECTION OUTPUT ;
    USE SIGNAL ;
    PORT
      LAYER M4 ;
        RECT  0 74.928 0.084 74.952 ;
    END
  END b[433]
  PIN b[434]
    DIRECTION OUTPUT ;
    USE SIGNAL ;
    PORT
      LAYER M4 ;
        RECT  0 75.024 0.084 75.048 ;
    END
  END b[434]
  PIN b[435]
    DIRECTION OUTPUT ;
    USE SIGNAL ;
    PORT
      LAYER M4 ;
        RECT  0 75.12 0.084 75.144 ;
    END
  END b[435]
  PIN b[436]
    DIRECTION OUTPUT ;
    USE SIGNAL ;
    PORT
      LAYER M4 ;
        RECT  0 75.216 0.084 75.24 ;
    END
  END b[436]
  PIN b[437]
    DIRECTION OUTPUT ;
    USE SIGNAL ;
    PORT
      LAYER M4 ;
        RECT  0 75.312 0.084 75.336 ;
    END
  END b[437]
  PIN b[438]
    DIRECTION OUTPUT ;
    USE SIGNAL ;
    PORT
      LAYER M4 ;
        RECT  0 75.408 0.084 75.432 ;
    END
  END b[438]
  PIN b[439]
    DIRECTION OUTPUT ;
    USE SIGNAL ;
    PORT
      LAYER M4 ;
        RECT  0 75.504 0.084 75.528 ;
    END
  END b[439]
  PIN b[43]
    DIRECTION OUTPUT ;
    USE SIGNAL ;
    PORT
      LAYER M4 ;
        RECT  0 45.936 0.084 45.96 ;
    END
  END b[43]
  PIN b[440]
    DIRECTION OUTPUT ;
    USE SIGNAL ;
    PORT
      LAYER M4 ;
        RECT  0 75.6 0.084 75.624 ;
    END
  END b[440]
  PIN b[441]
    DIRECTION OUTPUT ;
    USE SIGNAL ;
    PORT
      LAYER M4 ;
        RECT  0 75.696 0.084 75.72 ;
    END
  END b[441]
  PIN b[442]
    DIRECTION OUTPUT ;
    USE SIGNAL ;
    PORT
      LAYER M4 ;
        RECT  0 75.792 0.084 75.816 ;
    END
  END b[442]
  PIN b[443]
    DIRECTION OUTPUT ;
    USE SIGNAL ;
    PORT
      LAYER M4 ;
        RECT  0 75.888 0.084 75.912 ;
    END
  END b[443]
  PIN b[444]
    DIRECTION OUTPUT ;
    USE SIGNAL ;
    PORT
      LAYER M4 ;
        RECT  0 75.984 0.084 76.008 ;
    END
  END b[444]
  PIN b[445]
    DIRECTION OUTPUT ;
    USE SIGNAL ;
    PORT
      LAYER M4 ;
        RECT  0 76.08 0.084 76.104 ;
    END
  END b[445]
  PIN b[446]
    DIRECTION OUTPUT ;
    USE SIGNAL ;
    PORT
      LAYER M4 ;
        RECT  0 76.176 0.084 76.2 ;
    END
  END b[446]
  PIN b[447]
    DIRECTION OUTPUT ;
    USE SIGNAL ;
    PORT
      LAYER M4 ;
        RECT  0 76.272 0.084 76.296 ;
    END
  END b[447]
  PIN b[448]
    DIRECTION OUTPUT ;
    USE SIGNAL ;
    PORT
      LAYER M4 ;
        RECT  0 89.424 0.084 89.448 ;
    END
  END b[448]
  PIN b[449]
    DIRECTION OUTPUT ;
    USE SIGNAL ;
    PORT
      LAYER M4 ;
        RECT  0 89.52 0.084 89.544 ;
    END
  END b[449]
  PIN b[44]
    DIRECTION OUTPUT ;
    USE SIGNAL ;
    PORT
      LAYER M4 ;
        RECT  0 46.032 0.084 46.056 ;
    END
  END b[44]
  PIN b[450]
    DIRECTION OUTPUT ;
    USE SIGNAL ;
    PORT
      LAYER M4 ;
        RECT  0 89.616 0.084 89.64 ;
    END
  END b[450]
  PIN b[451]
    DIRECTION OUTPUT ;
    USE SIGNAL ;
    PORT
      LAYER M4 ;
        RECT  0 89.712 0.084 89.736 ;
    END
  END b[451]
  PIN b[452]
    DIRECTION OUTPUT ;
    USE SIGNAL ;
    PORT
      LAYER M4 ;
        RECT  0 89.808 0.084 89.832 ;
    END
  END b[452]
  PIN b[453]
    DIRECTION OUTPUT ;
    USE SIGNAL ;
    PORT
      LAYER M4 ;
        RECT  0 89.904 0.084 89.928 ;
    END
  END b[453]
  PIN b[454]
    DIRECTION OUTPUT ;
    USE SIGNAL ;
    PORT
      LAYER M4 ;
        RECT  0 90 0.084 90.024 ;
    END
  END b[454]
  PIN b[455]
    DIRECTION OUTPUT ;
    USE SIGNAL ;
    PORT
      LAYER M4 ;
        RECT  0 90.096 0.084 90.12 ;
    END
  END b[455]
  PIN b[456]
    DIRECTION OUTPUT ;
    USE SIGNAL ;
    PORT
      LAYER M4 ;
        RECT  0 90.192 0.084 90.216 ;
    END
  END b[456]
  PIN b[457]
    DIRECTION OUTPUT ;
    USE SIGNAL ;
    PORT
      LAYER M4 ;
        RECT  0 90.288 0.084 90.312 ;
    END
  END b[457]
  PIN b[458]
    DIRECTION OUTPUT ;
    USE SIGNAL ;
    PORT
      LAYER M4 ;
        RECT  0 90.384 0.084 90.408 ;
    END
  END b[458]
  PIN b[459]
    DIRECTION OUTPUT ;
    USE SIGNAL ;
    PORT
      LAYER M4 ;
        RECT  0 90.48 0.084 90.504 ;
    END
  END b[459]
  PIN b[45]
    DIRECTION OUTPUT ;
    USE SIGNAL ;
    PORT
      LAYER M4 ;
        RECT  0 46.128 0.084 46.152 ;
    END
  END b[45]
  PIN b[460]
    DIRECTION OUTPUT ;
    USE SIGNAL ;
    PORT
      LAYER M4 ;
        RECT  0 90.576 0.084 90.6 ;
    END
  END b[460]
  PIN b[461]
    DIRECTION OUTPUT ;
    USE SIGNAL ;
    PORT
      LAYER M4 ;
        RECT  0 90.672 0.084 90.696 ;
    END
  END b[461]
  PIN b[462]
    DIRECTION OUTPUT ;
    USE SIGNAL ;
    PORT
      LAYER M4 ;
        RECT  0 90.768 0.084 90.792 ;
    END
  END b[462]
  PIN b[463]
    DIRECTION OUTPUT ;
    USE SIGNAL ;
    PORT
      LAYER M4 ;
        RECT  0 90.864 0.084 90.888 ;
    END
  END b[463]
  PIN b[464]
    DIRECTION OUTPUT ;
    USE SIGNAL ;
    PORT
      LAYER M4 ;
        RECT  0 90.96 0.084 90.984 ;
    END
  END b[464]
  PIN b[465]
    DIRECTION OUTPUT ;
    USE SIGNAL ;
    PORT
      LAYER M4 ;
        RECT  0 91.056 0.084 91.08 ;
    END
  END b[465]
  PIN b[466]
    DIRECTION OUTPUT ;
    USE SIGNAL ;
    PORT
      LAYER M4 ;
        RECT  0 91.152 0.084 91.176 ;
    END
  END b[466]
  PIN b[467]
    DIRECTION OUTPUT ;
    USE SIGNAL ;
    PORT
      LAYER M4 ;
        RECT  0 91.248 0.084 91.272 ;
    END
  END b[467]
  PIN b[468]
    DIRECTION OUTPUT ;
    USE SIGNAL ;
    PORT
      LAYER M4 ;
        RECT  0 91.344 0.084 91.368 ;
    END
  END b[468]
  PIN b[469]
    DIRECTION OUTPUT ;
    USE SIGNAL ;
    PORT
      LAYER M4 ;
        RECT  0 91.44 0.084 91.464 ;
    END
  END b[469]
  PIN b[46]
    DIRECTION OUTPUT ;
    USE SIGNAL ;
    PORT
      LAYER M4 ;
        RECT  0 46.224 0.084 46.248 ;
    END
  END b[46]
  PIN b[470]
    DIRECTION OUTPUT ;
    USE SIGNAL ;
    PORT
      LAYER M4 ;
        RECT  0 91.536 0.084 91.56 ;
    END
  END b[470]
  PIN b[471]
    DIRECTION OUTPUT ;
    USE SIGNAL ;
    PORT
      LAYER M4 ;
        RECT  0 91.632 0.084 91.656 ;
    END
  END b[471]
  PIN b[472]
    DIRECTION OUTPUT ;
    USE SIGNAL ;
    PORT
      LAYER M4 ;
        RECT  0 91.728 0.084 91.752 ;
    END
  END b[472]
  PIN b[473]
    DIRECTION OUTPUT ;
    USE SIGNAL ;
    PORT
      LAYER M4 ;
        RECT  0 91.824 0.084 91.848 ;
    END
  END b[473]
  PIN b[474]
    DIRECTION OUTPUT ;
    USE SIGNAL ;
    PORT
      LAYER M4 ;
        RECT  0 91.92 0.084 91.944 ;
    END
  END b[474]
  PIN b[475]
    DIRECTION OUTPUT ;
    USE SIGNAL ;
    PORT
      LAYER M4 ;
        RECT  0 92.016 0.084 92.04 ;
    END
  END b[475]
  PIN b[476]
    DIRECTION OUTPUT ;
    USE SIGNAL ;
    PORT
      LAYER M4 ;
        RECT  0 92.112 0.084 92.136 ;
    END
  END b[476]
  PIN b[477]
    DIRECTION OUTPUT ;
    USE SIGNAL ;
    PORT
      LAYER M4 ;
        RECT  0 92.208 0.084 92.232 ;
    END
  END b[477]
  PIN b[478]
    DIRECTION OUTPUT ;
    USE SIGNAL ;
    PORT
      LAYER M4 ;
        RECT  0 92.304 0.084 92.328 ;
    END
  END b[478]
  PIN b[479]
    DIRECTION OUTPUT ;
    USE SIGNAL ;
    PORT
      LAYER M4 ;
        RECT  0 92.4 0.084 92.424 ;
    END
  END b[479]
  PIN b[47]
    DIRECTION OUTPUT ;
    USE SIGNAL ;
    PORT
      LAYER M4 ;
        RECT  0 46.32 0.084 46.344 ;
    END
  END b[47]
  PIN b[480]
    DIRECTION OUTPUT ;
    USE SIGNAL ;
    PORT
      LAYER M4 ;
        RECT  0 86.352 0.084 86.376 ;
    END
  END b[480]
  PIN b[481]
    DIRECTION OUTPUT ;
    USE SIGNAL ;
    PORT
      LAYER M4 ;
        RECT  0 86.448 0.084 86.472 ;
    END
  END b[481]
  PIN b[482]
    DIRECTION OUTPUT ;
    USE SIGNAL ;
    PORT
      LAYER M4 ;
        RECT  0 86.544 0.084 86.568 ;
    END
  END b[482]
  PIN b[483]
    DIRECTION OUTPUT ;
    USE SIGNAL ;
    PORT
      LAYER M4 ;
        RECT  0 86.64 0.084 86.664 ;
    END
  END b[483]
  PIN b[484]
    DIRECTION OUTPUT ;
    USE SIGNAL ;
    PORT
      LAYER M4 ;
        RECT  0 86.736 0.084 86.76 ;
    END
  END b[484]
  PIN b[485]
    DIRECTION OUTPUT ;
    USE SIGNAL ;
    PORT
      LAYER M4 ;
        RECT  0 86.832 0.084 86.856 ;
    END
  END b[485]
  PIN b[486]
    DIRECTION OUTPUT ;
    USE SIGNAL ;
    PORT
      LAYER M4 ;
        RECT  0 86.928 0.084 86.952 ;
    END
  END b[486]
  PIN b[487]
    DIRECTION OUTPUT ;
    USE SIGNAL ;
    PORT
      LAYER M4 ;
        RECT  0 87.024 0.084 87.048 ;
    END
  END b[487]
  PIN b[488]
    DIRECTION OUTPUT ;
    USE SIGNAL ;
    PORT
      LAYER M4 ;
        RECT  0 87.12 0.084 87.144 ;
    END
  END b[488]
  PIN b[489]
    DIRECTION OUTPUT ;
    USE SIGNAL ;
    PORT
      LAYER M4 ;
        RECT  0 87.216 0.084 87.24 ;
    END
  END b[489]
  PIN b[48]
    DIRECTION OUTPUT ;
    USE SIGNAL ;
    PORT
      LAYER M4 ;
        RECT  0 46.416 0.084 46.44 ;
    END
  END b[48]
  PIN b[490]
    DIRECTION OUTPUT ;
    USE SIGNAL ;
    PORT
      LAYER M4 ;
        RECT  0 87.312 0.084 87.336 ;
    END
  END b[490]
  PIN b[491]
    DIRECTION OUTPUT ;
    USE SIGNAL ;
    PORT
      LAYER M4 ;
        RECT  0 87.408 0.084 87.432 ;
    END
  END b[491]
  PIN b[492]
    DIRECTION OUTPUT ;
    USE SIGNAL ;
    PORT
      LAYER M4 ;
        RECT  0 87.504 0.084 87.528 ;
    END
  END b[492]
  PIN b[493]
    DIRECTION OUTPUT ;
    USE SIGNAL ;
    PORT
      LAYER M4 ;
        RECT  0 87.6 0.084 87.624 ;
    END
  END b[493]
  PIN b[494]
    DIRECTION OUTPUT ;
    USE SIGNAL ;
    PORT
      LAYER M4 ;
        RECT  0 87.696 0.084 87.72 ;
    END
  END b[494]
  PIN b[495]
    DIRECTION OUTPUT ;
    USE SIGNAL ;
    PORT
      LAYER M4 ;
        RECT  0 87.792 0.084 87.816 ;
    END
  END b[495]
  PIN b[496]
    DIRECTION OUTPUT ;
    USE SIGNAL ;
    PORT
      LAYER M4 ;
        RECT  0 87.888 0.084 87.912 ;
    END
  END b[496]
  PIN b[497]
    DIRECTION OUTPUT ;
    USE SIGNAL ;
    PORT
      LAYER M4 ;
        RECT  0 87.984 0.084 88.008 ;
    END
  END b[497]
  PIN b[498]
    DIRECTION OUTPUT ;
    USE SIGNAL ;
    PORT
      LAYER M4 ;
        RECT  0 88.08 0.084 88.104 ;
    END
  END b[498]
  PIN b[499]
    DIRECTION OUTPUT ;
    USE SIGNAL ;
    PORT
      LAYER M4 ;
        RECT  0 88.176 0.084 88.2 ;
    END
  END b[499]
  PIN b[49]
    DIRECTION OUTPUT ;
    USE SIGNAL ;
    PORT
      LAYER M4 ;
        RECT  0 46.512 0.084 46.536 ;
    END
  END b[49]
  PIN b[4]
    DIRECTION OUTPUT ;
    USE SIGNAL ;
    PORT
      LAYER M4 ;
        RECT  0 48.336 0.084 48.36 ;
    END
  END b[4]
  PIN b[500]
    DIRECTION OUTPUT ;
    USE SIGNAL ;
    PORT
      LAYER M4 ;
        RECT  0 88.272 0.084 88.296 ;
    END
  END b[500]
  PIN b[501]
    DIRECTION OUTPUT ;
    USE SIGNAL ;
    PORT
      LAYER M4 ;
        RECT  0 88.368 0.084 88.392 ;
    END
  END b[501]
  PIN b[502]
    DIRECTION OUTPUT ;
    USE SIGNAL ;
    PORT
      LAYER M4 ;
        RECT  0 88.464 0.084 88.488 ;
    END
  END b[502]
  PIN b[503]
    DIRECTION OUTPUT ;
    USE SIGNAL ;
    PORT
      LAYER M4 ;
        RECT  0 88.56 0.084 88.584 ;
    END
  END b[503]
  PIN b[504]
    DIRECTION OUTPUT ;
    USE SIGNAL ;
    PORT
      LAYER M4 ;
        RECT  0 88.656 0.084 88.68 ;
    END
  END b[504]
  PIN b[505]
    DIRECTION OUTPUT ;
    USE SIGNAL ;
    PORT
      LAYER M4 ;
        RECT  0 88.752 0.084 88.776 ;
    END
  END b[505]
  PIN b[506]
    DIRECTION OUTPUT ;
    USE SIGNAL ;
    PORT
      LAYER M4 ;
        RECT  0 88.848 0.084 88.872 ;
    END
  END b[506]
  PIN b[507]
    DIRECTION OUTPUT ;
    USE SIGNAL ;
    PORT
      LAYER M4 ;
        RECT  0 88.944 0.084 88.968 ;
    END
  END b[507]
  PIN b[508]
    DIRECTION OUTPUT ;
    USE SIGNAL ;
    PORT
      LAYER M4 ;
        RECT  0 89.04 0.084 89.064 ;
    END
  END b[508]
  PIN b[509]
    DIRECTION OUTPUT ;
    USE SIGNAL ;
    PORT
      LAYER M4 ;
        RECT  0 89.136 0.084 89.16 ;
    END
  END b[509]
  PIN b[50]
    DIRECTION OUTPUT ;
    USE SIGNAL ;
    PORT
      LAYER M4 ;
        RECT  0 46.608 0.084 46.632 ;
    END
  END b[50]
  PIN b[510]
    DIRECTION OUTPUT ;
    USE SIGNAL ;
    PORT
      LAYER M4 ;
        RECT  0 89.232 0.084 89.256 ;
    END
  END b[510]
  PIN b[511]
    DIRECTION OUTPUT ;
    USE SIGNAL ;
    PORT
      LAYER M4 ;
        RECT  0 89.328 0.084 89.352 ;
    END
  END b[511]
  PIN b[512]
    DIRECTION OUTPUT ;
    USE SIGNAL ;
    PORT
      LAYER M4 ;
        RECT  0 64.08 0.084 64.104 ;
    END
  END b[512]
  PIN b[513]
    DIRECTION OUTPUT ;
    USE SIGNAL ;
    PORT
      LAYER M4 ;
        RECT  0 64.176 0.084 64.2 ;
    END
  END b[513]
  PIN b[514]
    DIRECTION OUTPUT ;
    USE SIGNAL ;
    PORT
      LAYER M4 ;
        RECT  0 64.272 0.084 64.296 ;
    END
  END b[514]
  PIN b[515]
    DIRECTION OUTPUT ;
    USE SIGNAL ;
    PORT
      LAYER M4 ;
        RECT  0 64.368 0.084 64.392 ;
    END
  END b[515]
  PIN b[516]
    DIRECTION OUTPUT ;
    USE SIGNAL ;
    PORT
      LAYER M4 ;
        RECT  0 64.464 0.084 64.488 ;
    END
  END b[516]
  PIN b[517]
    DIRECTION OUTPUT ;
    USE SIGNAL ;
    PORT
      LAYER M4 ;
        RECT  0 64.56 0.084 64.584 ;
    END
  END b[517]
  PIN b[518]
    DIRECTION OUTPUT ;
    USE SIGNAL ;
    PORT
      LAYER M4 ;
        RECT  0 64.656 0.084 64.68 ;
    END
  END b[518]
  PIN b[519]
    DIRECTION OUTPUT ;
    USE SIGNAL ;
    PORT
      LAYER M4 ;
        RECT  0 64.752 0.084 64.776 ;
    END
  END b[519]
  PIN b[51]
    DIRECTION OUTPUT ;
    USE SIGNAL ;
    PORT
      LAYER M4 ;
        RECT  0 46.704 0.084 46.728 ;
    END
  END b[51]
  PIN b[520]
    DIRECTION OUTPUT ;
    USE SIGNAL ;
    PORT
      LAYER M4 ;
        RECT  0 64.848 0.084 64.872 ;
    END
  END b[520]
  PIN b[521]
    DIRECTION OUTPUT ;
    USE SIGNAL ;
    PORT
      LAYER M4 ;
        RECT  0 64.944 0.084 64.968 ;
    END
  END b[521]
  PIN b[522]
    DIRECTION OUTPUT ;
    USE SIGNAL ;
    PORT
      LAYER M4 ;
        RECT  0 65.04 0.084 65.064 ;
    END
  END b[522]
  PIN b[523]
    DIRECTION OUTPUT ;
    USE SIGNAL ;
    PORT
      LAYER M4 ;
        RECT  0 65.136 0.084 65.16 ;
    END
  END b[523]
  PIN b[524]
    DIRECTION OUTPUT ;
    USE SIGNAL ;
    PORT
      LAYER M4 ;
        RECT  0 65.232 0.084 65.256 ;
    END
  END b[524]
  PIN b[525]
    DIRECTION OUTPUT ;
    USE SIGNAL ;
    PORT
      LAYER M4 ;
        RECT  0 65.328 0.084 65.352 ;
    END
  END b[525]
  PIN b[526]
    DIRECTION OUTPUT ;
    USE SIGNAL ;
    PORT
      LAYER M4 ;
        RECT  0 65.424 0.084 65.448 ;
    END
  END b[526]
  PIN b[527]
    DIRECTION OUTPUT ;
    USE SIGNAL ;
    PORT
      LAYER M4 ;
        RECT  0 65.52 0.084 65.544 ;
    END
  END b[527]
  PIN b[528]
    DIRECTION OUTPUT ;
    USE SIGNAL ;
    PORT
      LAYER M4 ;
        RECT  0 65.616 0.084 65.64 ;
    END
  END b[528]
  PIN b[529]
    DIRECTION OUTPUT ;
    USE SIGNAL ;
    PORT
      LAYER M4 ;
        RECT  0 65.712 0.084 65.736 ;
    END
  END b[529]
  PIN b[52]
    DIRECTION OUTPUT ;
    USE SIGNAL ;
    PORT
      LAYER M4 ;
        RECT  0 46.8 0.084 46.824 ;
    END
  END b[52]
  PIN b[530]
    DIRECTION OUTPUT ;
    USE SIGNAL ;
    PORT
      LAYER M4 ;
        RECT  0 65.808 0.084 65.832 ;
    END
  END b[530]
  PIN b[531]
    DIRECTION OUTPUT ;
    USE SIGNAL ;
    PORT
      LAYER M4 ;
        RECT  0 65.904 0.084 65.928 ;
    END
  END b[531]
  PIN b[532]
    DIRECTION OUTPUT ;
    USE SIGNAL ;
    PORT
      LAYER M4 ;
        RECT  0 66 0.084 66.024 ;
    END
  END b[532]
  PIN b[533]
    DIRECTION OUTPUT ;
    USE SIGNAL ;
    PORT
      LAYER M4 ;
        RECT  0 66.096 0.084 66.12 ;
    END
  END b[533]
  PIN b[534]
    DIRECTION OUTPUT ;
    USE SIGNAL ;
    PORT
      LAYER M4 ;
        RECT  0 66.192 0.084 66.216 ;
    END
  END b[534]
  PIN b[535]
    DIRECTION OUTPUT ;
    USE SIGNAL ;
    PORT
      LAYER M4 ;
        RECT  0 66.288 0.084 66.312 ;
    END
  END b[535]
  PIN b[536]
    DIRECTION OUTPUT ;
    USE SIGNAL ;
    PORT
      LAYER M4 ;
        RECT  0 66.384 0.084 66.408 ;
    END
  END b[536]
  PIN b[537]
    DIRECTION OUTPUT ;
    USE SIGNAL ;
    PORT
      LAYER M4 ;
        RECT  0 66.48 0.084 66.504 ;
    END
  END b[537]
  PIN b[538]
    DIRECTION OUTPUT ;
    USE SIGNAL ;
    PORT
      LAYER M4 ;
        RECT  0 66.576 0.084 66.6 ;
    END
  END b[538]
  PIN b[539]
    DIRECTION OUTPUT ;
    USE SIGNAL ;
    PORT
      LAYER M4 ;
        RECT  0 66.672 0.084 66.696 ;
    END
  END b[539]
  PIN b[53]
    DIRECTION OUTPUT ;
    USE SIGNAL ;
    PORT
      LAYER M4 ;
        RECT  0 46.896 0.084 46.92 ;
    END
  END b[53]
  PIN b[540]
    DIRECTION OUTPUT ;
    USE SIGNAL ;
    PORT
      LAYER M4 ;
        RECT  0 66.768 0.084 66.792 ;
    END
  END b[540]
  PIN b[541]
    DIRECTION OUTPUT ;
    USE SIGNAL ;
    PORT
      LAYER M4 ;
        RECT  0 66.864 0.084 66.888 ;
    END
  END b[541]
  PIN b[542]
    DIRECTION OUTPUT ;
    USE SIGNAL ;
    PORT
      LAYER M4 ;
        RECT  0 66.96 0.084 66.984 ;
    END
  END b[542]
  PIN b[543]
    DIRECTION OUTPUT ;
    USE SIGNAL ;
    PORT
      LAYER M4 ;
        RECT  0 67.056 0.084 67.08 ;
    END
  END b[543]
  PIN b[544]
    DIRECTION OUTPUT ;
    USE SIGNAL ;
    PORT
      LAYER M4 ;
        RECT  0 60.624 0.084 60.648 ;
    END
  END b[544]
  PIN b[545]
    DIRECTION OUTPUT ;
    USE SIGNAL ;
    PORT
      LAYER M4 ;
        RECT  0 60.72 0.084 60.744 ;
    END
  END b[545]
  PIN b[546]
    DIRECTION OUTPUT ;
    USE SIGNAL ;
    PORT
      LAYER M4 ;
        RECT  0 60.816 0.084 60.84 ;
    END
  END b[546]
  PIN b[547]
    DIRECTION OUTPUT ;
    USE SIGNAL ;
    PORT
      LAYER M4 ;
        RECT  0 60.912 0.084 60.936 ;
    END
  END b[547]
  PIN b[54]
    DIRECTION OUTPUT ;
    USE SIGNAL ;
    PORT
      LAYER M4 ;
        RECT  0 46.992 0.084 47.016 ;
    END
  END b[54]
  PIN b[55]
    DIRECTION OUTPUT ;
    USE SIGNAL ;
    PORT
      LAYER M4 ;
        RECT  0 47.088 0.084 47.112 ;
    END
  END b[55]
  PIN b[56]
    DIRECTION OUTPUT ;
    USE SIGNAL ;
    PORT
      LAYER M4 ;
        RECT  0 47.184 0.084 47.208 ;
    END
  END b[56]
  PIN b[57]
    DIRECTION OUTPUT ;
    USE SIGNAL ;
    PORT
      LAYER M4 ;
        RECT  0 47.28 0.084 47.304 ;
    END
  END b[57]
  PIN b[58]
    DIRECTION OUTPUT ;
    USE SIGNAL ;
    PORT
      LAYER M4 ;
        RECT  0 47.376 0.084 47.4 ;
    END
  END b[58]
  PIN b[59]
    DIRECTION OUTPUT ;
    USE SIGNAL ;
    PORT
      LAYER M4 ;
        RECT  0 47.472 0.084 47.496 ;
    END
  END b[59]
  PIN b[5]
    DIRECTION OUTPUT ;
    USE SIGNAL ;
    PORT
      LAYER M4 ;
        RECT  0 48.432 0.084 48.456 ;
    END
  END b[5]
  PIN b[60]
    DIRECTION OUTPUT ;
    USE SIGNAL ;
    PORT
      LAYER M4 ;
        RECT  0 47.568 0.084 47.592 ;
    END
  END b[60]
  PIN b[61]
    DIRECTION OUTPUT ;
    USE SIGNAL ;
    PORT
      LAYER M4 ;
        RECT  0 47.664 0.084 47.688 ;
    END
  END b[61]
  PIN b[62]
    DIRECTION OUTPUT ;
    USE SIGNAL ;
    PORT
      LAYER M4 ;
        RECT  0 47.76 0.084 47.784 ;
    END
  END b[62]
  PIN b[63]
    DIRECTION OUTPUT ;
    USE SIGNAL ;
    PORT
      LAYER M4 ;
        RECT  0 47.856 0.084 47.88 ;
    END
  END b[63]
  PIN b[64]
    DIRECTION OUTPUT ;
    USE SIGNAL ;
    PORT
      LAYER M4 ;
        RECT  0 28.752 0.084 28.776 ;
    END
  END b[64]
  PIN b[65]
    DIRECTION OUTPUT ;
    USE SIGNAL ;
    PORT
      LAYER M4 ;
        RECT  0 28.848 0.084 28.872 ;
    END
  END b[65]
  PIN b[66]
    DIRECTION OUTPUT ;
    USE SIGNAL ;
    PORT
      LAYER M4 ;
        RECT  0 28.944 0.084 28.968 ;
    END
  END b[66]
  PIN b[67]
    DIRECTION OUTPUT ;
    USE SIGNAL ;
    PORT
      LAYER M4 ;
        RECT  0 29.04 0.084 29.064 ;
    END
  END b[67]
  PIN b[68]
    DIRECTION OUTPUT ;
    USE SIGNAL ;
    PORT
      LAYER M4 ;
        RECT  0 29.136 0.084 29.16 ;
    END
  END b[68]
  PIN b[69]
    DIRECTION OUTPUT ;
    USE SIGNAL ;
    PORT
      LAYER M4 ;
        RECT  0 29.232 0.084 29.256 ;
    END
  END b[69]
  PIN b[6]
    DIRECTION OUTPUT ;
    USE SIGNAL ;
    PORT
      LAYER M4 ;
        RECT  0 48.528 0.084 48.552 ;
    END
  END b[6]
  PIN b[70]
    DIRECTION OUTPUT ;
    USE SIGNAL ;
    PORT
      LAYER M4 ;
        RECT  0 29.328 0.084 29.352 ;
    END
  END b[70]
  PIN b[71]
    DIRECTION OUTPUT ;
    USE SIGNAL ;
    PORT
      LAYER M4 ;
        RECT  0 29.424 0.084 29.448 ;
    END
  END b[71]
  PIN b[72]
    DIRECTION OUTPUT ;
    USE SIGNAL ;
    PORT
      LAYER M4 ;
        RECT  0 29.52 0.084 29.544 ;
    END
  END b[72]
  PIN b[73]
    DIRECTION OUTPUT ;
    USE SIGNAL ;
    PORT
      LAYER M4 ;
        RECT  0 29.616 0.084 29.64 ;
    END
  END b[73]
  PIN b[74]
    DIRECTION OUTPUT ;
    USE SIGNAL ;
    PORT
      LAYER M4 ;
        RECT  0 29.712 0.084 29.736 ;
    END
  END b[74]
  PIN b[75]
    DIRECTION OUTPUT ;
    USE SIGNAL ;
    PORT
      LAYER M4 ;
        RECT  0 29.808 0.084 29.832 ;
    END
  END b[75]
  PIN b[76]
    DIRECTION OUTPUT ;
    USE SIGNAL ;
    PORT
      LAYER M4 ;
        RECT  0 29.904 0.084 29.928 ;
    END
  END b[76]
  PIN b[77]
    DIRECTION OUTPUT ;
    USE SIGNAL ;
    PORT
      LAYER M4 ;
        RECT  0 30 0.084 30.024 ;
    END
  END b[77]
  PIN b[78]
    DIRECTION OUTPUT ;
    USE SIGNAL ;
    PORT
      LAYER M4 ;
        RECT  0 30.096 0.084 30.12 ;
    END
  END b[78]
  PIN b[79]
    DIRECTION OUTPUT ;
    USE SIGNAL ;
    PORT
      LAYER M4 ;
        RECT  0 30.192 0.084 30.216 ;
    END
  END b[79]
  PIN b[7]
    DIRECTION OUTPUT ;
    USE SIGNAL ;
    PORT
      LAYER M4 ;
        RECT  0 48.624 0.084 48.648 ;
    END
  END b[7]
  PIN b[80]
    DIRECTION OUTPUT ;
    USE SIGNAL ;
    PORT
      LAYER M4 ;
        RECT  0 30.288 0.084 30.312 ;
    END
  END b[80]
  PIN b[81]
    DIRECTION OUTPUT ;
    USE SIGNAL ;
    PORT
      LAYER M4 ;
        RECT  0 30.384 0.084 30.408 ;
    END
  END b[81]
  PIN b[82]
    DIRECTION OUTPUT ;
    USE SIGNAL ;
    PORT
      LAYER M4 ;
        RECT  0 30.48 0.084 30.504 ;
    END
  END b[82]
  PIN b[83]
    DIRECTION OUTPUT ;
    USE SIGNAL ;
    PORT
      LAYER M4 ;
        RECT  0 30.576 0.084 30.6 ;
    END
  END b[83]
  PIN b[84]
    DIRECTION OUTPUT ;
    USE SIGNAL ;
    PORT
      LAYER M4 ;
        RECT  0 30.672 0.084 30.696 ;
    END
  END b[84]
  PIN b[85]
    DIRECTION OUTPUT ;
    USE SIGNAL ;
    PORT
      LAYER M4 ;
        RECT  0 30.768 0.084 30.792 ;
    END
  END b[85]
  PIN b[86]
    DIRECTION OUTPUT ;
    USE SIGNAL ;
    PORT
      LAYER M4 ;
        RECT  0 30.864 0.084 30.888 ;
    END
  END b[86]
  PIN b[87]
    DIRECTION OUTPUT ;
    USE SIGNAL ;
    PORT
      LAYER M4 ;
        RECT  0 30.96 0.084 30.984 ;
    END
  END b[87]
  PIN b[88]
    DIRECTION OUTPUT ;
    USE SIGNAL ;
    PORT
      LAYER M4 ;
        RECT  0 31.056 0.084 31.08 ;
    END
  END b[88]
  PIN b[89]
    DIRECTION OUTPUT ;
    USE SIGNAL ;
    PORT
      LAYER M4 ;
        RECT  0 31.152 0.084 31.176 ;
    END
  END b[89]
  PIN b[8]
    DIRECTION OUTPUT ;
    USE SIGNAL ;
    PORT
      LAYER M4 ;
        RECT  0 48.72 0.084 48.744 ;
    END
  END b[8]
  PIN b[90]
    DIRECTION OUTPUT ;
    USE SIGNAL ;
    PORT
      LAYER M4 ;
        RECT  0 31.248 0.084 31.272 ;
    END
  END b[90]
  PIN b[91]
    DIRECTION OUTPUT ;
    USE SIGNAL ;
    PORT
      LAYER M4 ;
        RECT  0 31.344 0.084 31.368 ;
    END
  END b[91]
  PIN b[92]
    DIRECTION OUTPUT ;
    USE SIGNAL ;
    PORT
      LAYER M4 ;
        RECT  0 31.44 0.084 31.464 ;
    END
  END b[92]
  PIN b[93]
    DIRECTION OUTPUT ;
    USE SIGNAL ;
    PORT
      LAYER M4 ;
        RECT  0 31.536 0.084 31.56 ;
    END
  END b[93]
  PIN b[94]
    DIRECTION OUTPUT ;
    USE SIGNAL ;
    PORT
      LAYER M4 ;
        RECT  0 31.632 0.084 31.656 ;
    END
  END b[94]
  PIN b[95]
    DIRECTION OUTPUT ;
    USE SIGNAL ;
    PORT
      LAYER M4 ;
        RECT  0 31.728 0.084 31.752 ;
    END
  END b[95]
  PIN b[96]
    DIRECTION OUTPUT ;
    USE SIGNAL ;
    PORT
      LAYER M4 ;
        RECT  0 15.696 0.084 15.72 ;
    END
  END b[96]
  PIN b[97]
    DIRECTION OUTPUT ;
    USE SIGNAL ;
    PORT
      LAYER M4 ;
        RECT  0 15.792 0.084 15.816 ;
    END
  END b[97]
  PIN b[98]
    DIRECTION OUTPUT ;
    USE SIGNAL ;
    PORT
      LAYER M4 ;
        RECT  0 15.888 0.084 15.912 ;
    END
  END b[98]
  PIN b[99]
    DIRECTION OUTPUT ;
    USE SIGNAL ;
    PORT
      LAYER M4 ;
        RECT  0 15.984 0.084 16.008 ;
    END
  END b[99]
  PIN b[9]
    DIRECTION OUTPUT ;
    USE SIGNAL ;
    PORT
      LAYER M4 ;
        RECT  0 48.816 0.084 48.84 ;
    END
  END b[9]
  PIN ck
    DIRECTION INPUT ;
    USE SIGNAL ;
    PORT
      LAYER M3 ;
        RECT  29.7 99.299 29.718 99.336 ;
    END
  END ck
  PIN ck_s
    DIRECTION INPUT ;
    USE SIGNAL ;
    PORT
      LAYER M3 ;
        RECT  29.772 99.299 29.79 99.336 ;
    END
  END ck_s
  PIN en
    DIRECTION INPUT ;
    USE SIGNAL ;
    PORT
      LAYER M3 ;
        RECT  29.844 99.299 29.862 99.336 ;
    END
  END en
  PIN fault
    DIRECTION OUTPUT ;
    USE SIGNAL ;
    PORT
      LAYER M3 ;
        RECT  29.916 99.299 29.934 99.336 ;
    END
  END fault
  PIN k0
    DIRECTION INPUT ;
    USE SIGNAL ;
    PORT
      LAYER M3 ;
        RECT  29.988 99.299 30.006 99.336 ;
    END
  END k0
  PIN k1
    DIRECTION INPUT ;
    USE SIGNAL ;
    PORT
      LAYER M3 ;
        RECT  30.06 99.299 30.078 99.336 ;
    END
  END k1
  PIN k2
    DIRECTION INPUT ;
    USE SIGNAL ;
    PORT
      LAYER M3 ;
        RECT  30.132 99.299 30.15 99.336 ;
    END
  END k2
  PIN rs
    DIRECTION INPUT ;
    USE SIGNAL ;
    PORT
      LAYER M3 ;
        RECT  30.204 99.299 30.222 99.336 ;
    END
  END rs
  PIN tie_hi
    DIRECTION OUTPUT ;
    USE SIGNAL ;
    PORT
      LAYER M3 ;
        RECT  30.276 99.299 30.294 99.336 ;
    END
  END tie_hi
  PIN tie_lo
    DIRECTION OUTPUT ;
    USE SIGNAL ;
    PORT
      LAYER M3 ;
        RECT  30.348 99.299 30.366 99.336 ;
    END
  END tie_lo
  PIN VDD
    DIRECTION INOUT ;
    USE POWER ;
    PORT
      LAYER M5 ;
        RECT  61.992 2.151 62.112 96.953 ;
        RECT  59.292 2.151 59.412 96.953 ;
        RECT  56.592 2.151 56.712 96.953 ;
        RECT  53.892 2.151 54.012 96.953 ;
        RECT  51.192 2.151 51.312 96.953 ;
        RECT  48.492 2.151 48.612 96.953 ;
        RECT  45.792 2.151 45.912 96.953 ;
        RECT  43.092 2.151 43.212 96.953 ;
        RECT  40.392 2.151 40.512 96.953 ;
        RECT  37.692 2.151 37.812 96.953 ;
        RECT  34.992 2.151 35.112 96.953 ;
        RECT  32.292 2.151 32.412 96.953 ;
        RECT  29.592 2.151 29.712 96.953 ;
        RECT  26.892 2.151 27.012 96.953 ;
        RECT  24.192 2.151 24.312 96.953 ;
        RECT  21.492 2.151 21.612 96.953 ;
        RECT  18.792 2.151 18.912 96.953 ;
        RECT  16.092 2.151 16.212 96.953 ;
        RECT  13.392 2.151 13.512 96.953 ;
        RECT  10.692 2.151 10.812 96.953 ;
        RECT  7.992 2.151 8.112 96.953 ;
        RECT  5.292 2.151 5.412 96.953 ;
        RECT  2.592 2.151 2.712 96.953 ;
    END
  END VDD
  PIN VSS
    DIRECTION INOUT ;
    USE GROUND ;
    PORT
      LAYER M5 ;
        RECT  61.8 2.137 61.92 96.939 ;
        RECT  59.1 2.137 59.22 96.939 ;
        RECT  56.4 2.137 56.52 96.939 ;
        RECT  53.7 2.137 53.82 96.939 ;
        RECT  51 2.137 51.12 96.939 ;
        RECT  48.3 2.137 48.42 96.939 ;
        RECT  45.6 2.137 45.72 96.939 ;
        RECT  42.9 2.137 43.02 96.939 ;
        RECT  40.2 2.137 40.32 96.939 ;
        RECT  37.5 2.137 37.62 96.939 ;
        RECT  34.8 2.137 34.92 96.939 ;
        RECT  32.1 2.137 32.22 96.939 ;
        RECT  29.4 2.137 29.52 96.939 ;
        RECT  26.7 2.137 26.82 96.939 ;
        RECT  24 2.137 24.12 96.939 ;
        RECT  21.3 2.137 21.42 96.939 ;
        RECT  18.6 2.137 18.72 96.939 ;
        RECT  15.9 2.137 16.02 96.939 ;
        RECT  13.2 2.137 13.32 96.939 ;
        RECT  10.5 2.137 10.62 96.939 ;
        RECT  7.8 2.137 7.92 96.939 ;
        RECT  5.1 2.137 5.22 96.939 ;
        RECT  2.4 2.137 2.52 96.939 ;
    END
  END VSS
  OBS
    LAYER RVTN ;
     RECT  2.16 2.16 62.586 2.295 ;
     RECT  2.16 2.565 62.586 2.835 ;
     RECT  2.16 3.105 62.586 3.375 ;
     RECT  2.16 3.645 62.586 3.915 ;
     RECT  2.16 4.185 62.586 4.455 ;
     RECT  2.16 4.725 62.586 4.995 ;
     RECT  2.16 5.265 62.586 5.535 ;
     RECT  2.16 5.805 62.586 6.075 ;
     RECT  2.16 6.345 62.586 6.615 ;
     RECT  2.16 6.885 62.586 7.155 ;
     RECT  2.16 7.425 62.586 7.695 ;
     RECT  2.16 7.965 62.586 8.235 ;
     RECT  2.16 8.505 62.586 8.775 ;
     RECT  2.16 9.045 62.586 9.315 ;
     RECT  2.16 9.585 62.586 9.855 ;
     RECT  2.16 10.125 62.586 10.395 ;
     RECT  2.16 10.665 62.586 10.935 ;
     RECT  2.16 11.205 62.586 11.475 ;
     RECT  2.16 11.745 62.586 12.015 ;
     RECT  2.16 12.285 62.586 12.555 ;
     RECT  2.16 12.825 62.586 13.095 ;
     RECT  2.16 13.365 62.586 13.635 ;
     RECT  2.16 13.905 62.586 14.175 ;
     RECT  2.16 14.445 62.586 14.715 ;
     RECT  2.16 14.985 62.586 15.255 ;
     RECT  2.16 15.525 62.586 15.795 ;
     RECT  2.16 16.065 62.586 16.335 ;
     RECT  2.16 16.605 62.586 16.875 ;
     RECT  2.16 17.145 62.586 17.415 ;
     RECT  2.16 17.685 62.586 17.955 ;
     RECT  2.16 18.225 62.586 18.495 ;
     RECT  2.16 18.765 62.586 19.035 ;
     RECT  2.16 19.305 62.586 19.575 ;
     RECT  2.16 19.845 62.586 20.115 ;
     RECT  2.16 20.385 62.586 20.655 ;
     RECT  2.16 20.925 62.586 21.195 ;
     RECT  2.16 21.465 62.586 21.735 ;
     RECT  2.16 22.005 62.586 22.275 ;
     RECT  2.16 22.545 62.586 22.815 ;
     RECT  2.16 23.085 62.586 23.355 ;
     RECT  2.16 23.625 62.586 23.895 ;
     RECT  2.16 24.165 62.586 24.435 ;
     RECT  2.16 24.705 62.586 24.975 ;
     RECT  2.16 25.245 62.586 25.515 ;
     RECT  2.16 25.785 62.586 26.055 ;
     RECT  2.16 26.325 62.586 26.595 ;
     RECT  2.16 26.865 62.586 27.135 ;
     RECT  2.16 27.405 62.586 27.675 ;
     RECT  2.16 27.945 62.586 28.215 ;
     RECT  2.16 28.485 62.586 28.755 ;
     RECT  2.16 29.025 62.586 29.295 ;
     RECT  2.16 29.565 62.586 29.835 ;
     RECT  2.16 30.105 62.586 30.375 ;
     RECT  2.16 30.645 62.586 30.915 ;
     RECT  2.16 31.185 62.586 31.455 ;
     RECT  2.16 31.725 62.586 31.995 ;
     RECT  2.16 32.265 62.586 32.535 ;
     RECT  2.16 32.805 62.586 33.075 ;
     RECT  2.16 33.345 62.586 33.615 ;
     RECT  2.16 33.885 62.586 34.155 ;
     RECT  2.16 34.425 62.586 34.695 ;
     RECT  2.16 34.965 62.586 35.235 ;
     RECT  2.16 35.505 62.586 35.775 ;
     RECT  2.16 36.045 62.586 36.315 ;
     RECT  2.16 36.585 62.586 36.855 ;
     RECT  2.16 37.125 62.586 37.395 ;
     RECT  2.16 37.665 62.586 37.935 ;
     RECT  2.16 38.205 62.586 38.475 ;
     RECT  2.16 38.745 62.586 39.015 ;
     RECT  2.16 39.285 62.586 39.555 ;
     RECT  2.16 39.825 62.586 40.095 ;
     RECT  2.16 40.365 62.586 40.635 ;
     RECT  2.16 40.905 62.586 41.175 ;
     RECT  2.16 41.445 62.586 41.715 ;
     RECT  2.16 41.985 62.586 42.255 ;
     RECT  2.16 42.525 62.586 42.795 ;
     RECT  2.16 43.065 62.586 43.335 ;
     RECT  2.16 43.605 62.586 43.875 ;
     RECT  2.16 44.145 62.586 44.415 ;
     RECT  2.16 44.685 62.586 44.955 ;
     RECT  2.16 45.225 62.586 45.495 ;
     RECT  2.16 45.765 62.586 46.035 ;
     RECT  2.16 46.305 62.586 46.575 ;
     RECT  2.16 46.845 62.586 47.115 ;
     RECT  2.16 47.385 62.586 47.655 ;
     RECT  2.16 47.925 62.586 48.195 ;
     RECT  2.16 48.465 62.586 48.735 ;
     RECT  2.16 49.005 62.586 49.275 ;
     RECT  2.16 49.545 62.586 49.815 ;
     RECT  2.16 50.085 62.586 50.355 ;
     RECT  2.16 50.625 62.586 50.895 ;
     RECT  2.16 51.165 62.586 51.435 ;
     RECT  2.16 51.705 62.586 51.975 ;
     RECT  2.16 52.245 62.586 52.515 ;
     RECT  2.16 52.785 62.586 53.055 ;
     RECT  2.16 53.325 62.586 53.595 ;
     RECT  2.16 53.865 62.586 54.135 ;
     RECT  2.16 54.405 62.586 54.675 ;
     RECT  2.16 54.945 62.586 55.215 ;
     RECT  2.16 55.485 62.586 55.755 ;
     RECT  2.16 56.025 62.586 56.295 ;
     RECT  2.16 56.565 62.586 56.835 ;
     RECT  2.16 57.105 62.586 57.375 ;
     RECT  2.16 57.645 62.586 57.915 ;
     RECT  2.16 58.185 62.586 58.455 ;
     RECT  2.16 58.725 62.586 58.995 ;
     RECT  2.16 59.265 62.586 59.535 ;
     RECT  2.16 59.805 62.586 60.075 ;
     RECT  2.16 60.345 62.586 60.615 ;
     RECT  2.16 60.885 62.586 61.155 ;
     RECT  2.16 61.425 62.586 61.695 ;
     RECT  2.16 61.965 62.586 62.235 ;
     RECT  2.16 62.505 62.586 62.775 ;
     RECT  2.16 63.045 62.586 63.315 ;
     RECT  2.16 63.585 62.586 63.855 ;
     RECT  2.16 64.125 62.586 64.395 ;
     RECT  2.16 64.665 62.586 64.935 ;
     RECT  2.16 65.205 62.586 65.475 ;
     RECT  2.16 65.745 62.586 66.015 ;
     RECT  2.16 66.285 62.586 66.555 ;
     RECT  2.16 66.825 62.586 67.095 ;
     RECT  2.16 67.365 62.586 67.635 ;
     RECT  2.16 67.905 62.586 68.175 ;
     RECT  2.16 68.445 62.586 68.715 ;
     RECT  2.16 68.985 62.586 69.255 ;
     RECT  2.16 69.525 62.586 69.795 ;
     RECT  2.16 70.065 62.586 70.335 ;
     RECT  2.16 70.605 62.586 70.875 ;
     RECT  2.16 71.145 62.586 71.415 ;
     RECT  2.16 71.685 62.586 71.955 ;
     RECT  2.16 72.225 62.586 72.495 ;
     RECT  2.16 72.765 62.586 73.035 ;
     RECT  2.16 73.305 62.586 73.575 ;
     RECT  2.16 73.845 62.586 74.115 ;
     RECT  2.16 74.385 62.586 74.655 ;
     RECT  2.16 74.925 62.586 75.195 ;
     RECT  2.16 75.465 62.586 75.735 ;
     RECT  2.16 76.005 62.586 76.275 ;
     RECT  2.16 76.545 62.586 76.815 ;
     RECT  2.16 77.085 62.586 77.355 ;
     RECT  2.16 77.625 62.586 77.895 ;
     RECT  2.16 78.165 62.586 78.435 ;
     RECT  2.16 78.705 62.586 78.975 ;
     RECT  2.16 79.245 62.586 79.515 ;
     RECT  2.16 79.785 62.586 80.055 ;
     RECT  2.16 80.325 62.586 80.595 ;
     RECT  2.16 80.865 62.586 81.135 ;
     RECT  2.16 81.405 62.586 81.675 ;
     RECT  2.16 81.945 62.586 82.215 ;
     RECT  2.16 82.485 62.586 82.755 ;
     RECT  2.16 83.025 62.586 83.295 ;
     RECT  2.16 83.565 62.586 83.835 ;
     RECT  2.16 84.105 62.586 84.375 ;
     RECT  2.16 84.645 62.586 84.915 ;
     RECT  2.16 85.185 62.586 85.455 ;
     RECT  2.16 85.725 62.586 85.995 ;
     RECT  2.16 86.265 62.586 86.535 ;
     RECT  2.16 86.805 62.586 87.075 ;
     RECT  2.16 87.345 62.586 87.615 ;
     RECT  2.16 87.885 62.586 88.155 ;
     RECT  2.16 88.425 62.586 88.695 ;
     RECT  2.16 88.965 62.586 89.235 ;
     RECT  2.16 89.505 62.586 89.775 ;
     RECT  2.16 90.045 62.586 90.315 ;
     RECT  2.16 90.585 62.586 90.855 ;
     RECT  2.16 91.125 62.586 91.395 ;
     RECT  2.16 91.665 62.586 91.935 ;
     RECT  2.16 92.205 62.586 92.475 ;
     RECT  2.16 92.745 62.586 93.015 ;
     RECT  2.16 93.285 62.586 93.555 ;
     RECT  2.16 93.825 62.586 94.095 ;
     RECT  2.16 94.365 62.586 94.635 ;
     RECT  2.16 94.905 62.586 95.175 ;
     RECT  2.16 95.445 62.586 95.715 ;
     RECT  2.16 95.985 62.586 96.255 ;
     RECT  2.16 96.525 62.586 96.795 ;
    LAYER RVTP ;
     RECT  2.16 2.295 62.586 2.565 ;
     RECT  2.16 2.835 62.586 3.105 ;
     RECT  2.16 3.375 62.586 3.645 ;
     RECT  2.16 3.915 62.586 4.185 ;
     RECT  2.16 4.455 62.586 4.725 ;
     RECT  2.16 4.995 62.586 5.265 ;
     RECT  2.16 5.535 62.586 5.805 ;
     RECT  2.16 6.075 62.586 6.345 ;
     RECT  2.16 6.615 62.586 6.885 ;
     RECT  2.16 7.155 62.586 7.425 ;
     RECT  2.16 7.695 62.586 7.965 ;
     RECT  2.16 8.235 62.586 8.505 ;
     RECT  2.16 8.775 62.586 9.045 ;
     RECT  2.16 9.315 62.586 9.585 ;
     RECT  2.16 9.855 62.586 10.125 ;
     RECT  2.16 10.395 62.586 10.665 ;
     RECT  2.16 10.935 62.586 11.205 ;
     RECT  2.16 11.475 62.586 11.745 ;
     RECT  2.16 12.015 62.586 12.285 ;
     RECT  2.16 12.555 62.586 12.825 ;
     RECT  2.16 13.095 62.586 13.365 ;
     RECT  2.16 13.635 62.586 13.905 ;
     RECT  2.16 14.175 62.586 14.445 ;
     RECT  2.16 14.715 62.586 14.985 ;
     RECT  2.16 15.255 62.586 15.525 ;
     RECT  2.16 15.795 62.586 16.065 ;
     RECT  2.16 16.335 62.586 16.605 ;
     RECT  2.16 16.875 62.586 17.145 ;
     RECT  2.16 17.415 62.586 17.685 ;
     RECT  2.16 17.955 62.586 18.225 ;
     RECT  2.16 18.495 62.586 18.765 ;
     RECT  2.16 19.035 62.586 19.305 ;
     RECT  2.16 19.575 62.586 19.845 ;
     RECT  2.16 20.115 62.586 20.385 ;
     RECT  2.16 20.655 62.586 20.925 ;
     RECT  2.16 21.195 62.586 21.465 ;
     RECT  2.16 21.735 62.586 22.005 ;
     RECT  2.16 22.275 62.586 22.545 ;
     RECT  2.16 22.815 62.586 23.085 ;
     RECT  2.16 23.355 62.586 23.625 ;
     RECT  2.16 23.895 62.586 24.165 ;
     RECT  2.16 24.435 62.586 24.705 ;
     RECT  2.16 24.975 62.586 25.245 ;
     RECT  2.16 25.515 62.586 25.785 ;
     RECT  2.16 26.055 62.586 26.325 ;
     RECT  2.16 26.595 62.586 26.865 ;
     RECT  2.16 27.135 62.586 27.405 ;
     RECT  2.16 27.675 62.586 27.945 ;
     RECT  2.16 28.215 62.586 28.485 ;
     RECT  2.16 28.755 62.586 29.025 ;
     RECT  2.16 29.295 62.586 29.565 ;
     RECT  2.16 29.835 62.586 30.105 ;
     RECT  2.16 30.375 62.586 30.645 ;
     RECT  2.16 30.915 62.586 31.185 ;
     RECT  2.16 31.455 62.586 31.725 ;
     RECT  2.16 31.995 62.586 32.265 ;
     RECT  2.16 32.535 62.586 32.805 ;
     RECT  2.16 33.075 62.586 33.345 ;
     RECT  2.16 33.615 62.586 33.885 ;
     RECT  2.16 34.155 62.586 34.425 ;
     RECT  2.16 34.695 62.586 34.965 ;
     RECT  2.16 35.235 62.586 35.505 ;
     RECT  2.16 35.775 62.586 36.045 ;
     RECT  2.16 36.315 62.586 36.585 ;
     RECT  2.16 36.855 62.586 37.125 ;
     RECT  2.16 37.395 62.586 37.665 ;
     RECT  2.16 37.935 62.586 38.205 ;
     RECT  2.16 38.475 62.586 38.745 ;
     RECT  2.16 39.015 62.586 39.285 ;
     RECT  2.16 39.555 62.586 39.825 ;
     RECT  2.16 40.095 62.586 40.365 ;
     RECT  2.16 40.635 62.586 40.905 ;
     RECT  2.16 41.175 62.586 41.445 ;
     RECT  2.16 41.715 62.586 41.985 ;
     RECT  2.16 42.255 62.586 42.525 ;
     RECT  2.16 42.795 62.586 43.065 ;
     RECT  2.16 43.335 62.586 43.605 ;
     RECT  2.16 43.875 62.586 44.145 ;
     RECT  2.16 44.415 62.586 44.685 ;
     RECT  2.16 44.955 62.586 45.225 ;
     RECT  2.16 45.495 62.586 45.765 ;
     RECT  2.16 46.035 62.586 46.305 ;
     RECT  2.16 46.575 62.586 46.845 ;
     RECT  2.16 47.115 62.586 47.385 ;
     RECT  2.16 47.655 62.586 47.925 ;
     RECT  2.16 48.195 62.586 48.465 ;
     RECT  2.16 48.735 62.586 49.005 ;
     RECT  2.16 49.275 62.586 49.545 ;
     RECT  2.16 49.815 62.586 50.085 ;
     RECT  2.16 50.355 62.586 50.625 ;
     RECT  2.16 50.895 62.586 51.165 ;
     RECT  2.16 51.435 62.586 51.705 ;
     RECT  2.16 51.975 62.586 52.245 ;
     RECT  2.16 52.515 62.586 52.785 ;
     RECT  2.16 53.055 62.586 53.325 ;
     RECT  2.16 53.595 62.586 53.865 ;
     RECT  2.16 54.135 62.586 54.405 ;
     RECT  2.16 54.675 62.586 54.945 ;
     RECT  2.16 55.215 62.586 55.485 ;
     RECT  2.16 55.755 62.586 56.025 ;
     RECT  2.16 56.295 62.586 56.565 ;
     RECT  2.16 56.835 62.586 57.105 ;
     RECT  2.16 57.375 62.586 57.645 ;
     RECT  2.16 57.915 62.586 58.185 ;
     RECT  2.16 58.455 62.586 58.725 ;
     RECT  2.16 58.995 62.586 59.265 ;
     RECT  2.16 59.535 62.586 59.805 ;
     RECT  2.16 60.075 62.586 60.345 ;
     RECT  2.16 60.615 62.586 60.885 ;
     RECT  2.16 61.155 62.586 61.425 ;
     RECT  2.16 61.695 62.586 61.965 ;
     RECT  2.16 62.235 62.586 62.505 ;
     RECT  2.16 62.775 62.586 63.045 ;
     RECT  2.16 63.315 62.586 63.585 ;
     RECT  2.16 63.855 62.586 64.125 ;
     RECT  2.16 64.395 62.586 64.665 ;
     RECT  2.16 64.935 62.586 65.205 ;
     RECT  2.16 65.475 62.586 65.745 ;
     RECT  2.16 66.015 62.586 66.285 ;
     RECT  2.16 66.555 62.586 66.825 ;
     RECT  2.16 67.095 62.586 67.365 ;
     RECT  2.16 67.635 62.586 67.905 ;
     RECT  2.16 68.175 62.586 68.445 ;
     RECT  2.16 68.715 62.586 68.985 ;
     RECT  2.16 69.255 62.586 69.525 ;
     RECT  2.16 69.795 62.586 70.065 ;
     RECT  2.16 70.335 62.586 70.605 ;
     RECT  2.16 70.875 62.586 71.145 ;
     RECT  2.16 71.415 62.586 71.685 ;
     RECT  2.16 71.955 62.586 72.225 ;
     RECT  2.16 72.495 62.586 72.765 ;
     RECT  2.16 73.035 62.586 73.305 ;
     RECT  2.16 73.575 62.586 73.845 ;
     RECT  2.16 74.115 62.586 74.385 ;
     RECT  2.16 74.655 62.586 74.925 ;
     RECT  2.16 75.195 62.586 75.465 ;
     RECT  2.16 75.735 62.586 76.005 ;
     RECT  2.16 76.275 62.586 76.545 ;
     RECT  2.16 76.815 62.586 77.085 ;
     RECT  2.16 77.355 62.586 77.625 ;
     RECT  2.16 77.895 62.586 78.165 ;
     RECT  2.16 78.435 62.586 78.705 ;
     RECT  2.16 78.975 62.586 79.245 ;
     RECT  2.16 79.515 62.586 79.785 ;
     RECT  2.16 80.055 62.586 80.325 ;
     RECT  2.16 80.595 62.586 80.865 ;
     RECT  2.16 81.135 62.586 81.405 ;
     RECT  2.16 81.675 62.586 81.945 ;
     RECT  2.16 82.215 62.586 82.485 ;
     RECT  2.16 82.755 62.586 83.025 ;
     RECT  2.16 83.295 62.586 83.565 ;
     RECT  2.16 83.835 62.586 84.105 ;
     RECT  2.16 84.375 62.586 84.645 ;
     RECT  2.16 84.915 62.586 85.185 ;
     RECT  2.16 85.455 62.586 85.725 ;
     RECT  2.16 85.995 62.586 86.265 ;
     RECT  2.16 86.535 62.586 86.805 ;
     RECT  2.16 87.075 62.586 87.345 ;
     RECT  2.16 87.615 62.586 87.885 ;
     RECT  2.16 88.155 62.586 88.425 ;
     RECT  2.16 88.695 62.586 88.965 ;
     RECT  2.16 89.235 62.586 89.505 ;
     RECT  2.16 89.775 62.586 90.045 ;
     RECT  2.16 90.315 62.586 90.585 ;
     RECT  2.16 90.855 62.586 91.125 ;
     RECT  2.16 91.395 62.586 91.665 ;
     RECT  2.16 91.935 62.586 92.205 ;
     RECT  2.16 92.475 62.586 92.745 ;
     RECT  2.16 93.015 62.586 93.285 ;
     RECT  2.16 93.555 62.586 93.825 ;
     RECT  2.16 94.095 62.586 94.365 ;
     RECT  2.16 94.635 62.586 94.905 ;
     RECT  2.16 95.175 62.586 95.445 ;
     RECT  2.16 95.715 62.586 95.985 ;
     RECT  2.16 96.255 62.586 96.525 ;
     RECT  2.16 96.795 62.586 96.93 ;
    LAYER M1 ;
     RECT  2.16 2.151 62.586 96.939 ;
    LAYER M2 ;
     RECT  0.031 10.296 0.103 10.314 ;
     RECT  0.031 82.656 0.103 82.674 ;
     RECT  0.103 10.134 0.139 10.314 ;
     RECT  0.103 19.62 0.139 19.638 ;
     RECT  0.103 20.898 0.139 20.916 ;
     RECT  0.103 46.701 0.139 46.719 ;
     RECT  0.103 47.736 0.139 47.754 ;
     RECT  0.103 64.566 0.139 64.584 ;
     RECT  0.103 12.528 0.175 13.014 ;
     RECT  0.139 46.116 0.175 47.754 ;
     RECT  0.103 81.954 0.175 82.782 ;
     RECT  0.103 83.736 0.175 83.754 ;
     RECT  0.103 91.404 0.175 91.926 ;
     RECT  0.139 19.62 0.203 20.916 ;
     RECT  0.103 51.246 0.203 51.264 ;
     RECT  0.139 64.566 0.203 65.034 ;
     RECT  0.103 75.978 0.203 76.572 ;
     RECT  0.103 80.676 0.203 80.694 ;
     RECT  0.175 91.404 0.203 92.304 ;
     RECT  0.175 12.528 0.211 13.554 ;
     RECT  0.203 20.196 0.239 20.916 ;
     RECT  0.203 65.016 0.239 65.034 ;
     RECT  0.031 8.586 0.247 8.604 ;
     RECT  0.211 12.528 0.247 13.932 ;
     RECT  0.103 14.796 0.247 15.282 ;
     RECT  0.175 81.954 0.247 83.754 ;
     RECT  0.203 91.908 0.275 92.304 ;
     RECT  0.247 8.586 0.283 9 ;
     RECT  0.211 43.956 0.283 43.974 ;
     RECT  0.103 44.766 0.283 44.784 ;
     RECT  0.031 79.326 0.283 79.344 ;
     RECT  0.247 80.136 0.283 80.154 ;
     RECT  0.103 61.776 0.391 61.794 ;
     RECT  0.247 81.756 0.391 83.754 ;
     RECT  0.247 12.528 0.427 15.282 ;
     RECT  0.103 60.966 0.427 60.984 ;
     RECT  0.391 61.776 0.427 62.262 ;
     RECT  0.283 8.586 0.463 9.108 ;
     RECT  0.139 10.134 0.463 10.692 ;
     RECT  0.103 29.034 0.463 29.052 ;
     RECT  0.103 49.086 0.463 49.104 ;
     RECT  0.427 60.966 0.463 62.262 ;
     RECT  0.391 81.486 0.463 83.754 ;
     RECT  0.463 48.816 0.491 49.104 ;
     RECT  0.463 28.566 0.499 29.052 ;
     RECT  0.463 60.354 0.499 62.262 ;
     RECT  0.463 81.486 0.499 84.474 ;
     RECT  0.463 8.586 0.535 11.232 ;
     RECT  0.427 12.096 0.535 15.282 ;
     RECT  0.283 43.956 0.535 44.784 ;
     RECT  0.175 46.116 0.535 47.799 ;
     RECT  0.491 48.816 0.535 48.834 ;
     RECT  0.499 60.354 0.535 63.234 ;
     RECT  0.499 73.044 0.535 73.062 ;
     RECT  0.499 85.536 0.535 85.554 ;
     RECT  0.499 81.486 0.599 84.636 ;
     RECT  0.103 16.506 1.111 17.064 ;
     RECT  0.211 67.608 1.147 67.626 ;
     RECT  1.147 67.608 1.175 67.824 ;
     RECT  0.499 28.494 1.211 29.052 ;
     RECT  0.211 93.096 1.435 93.114 ;
     RECT  0.103 55.116 1.723 55.134 ;
     RECT  1.723 54.846 1.759 55.134 ;
     RECT  0.535 30.186 1.975 30.744 ;
     RECT  0.535 52.254 1.975 52.272 ;
     RECT  0.535 74.088 2.011 74.106 ;
     RECT  1.975 35.748 2.155 35.766 ;
     RECT  0.535 8.586 2.16 15.282 ;
     RECT  1.111 16.308 2.16 17.064 ;
     RECT  0.535 18.774 2.16 18.792 ;
     RECT  0.535 22.788 2.16 22.806 ;
     RECT  0.103 26.334 2.16 26.352 ;
     RECT  1.211 28.494 2.16 29.016 ;
     RECT  1.975 30.078 2.16 30.744 ;
     RECT  0.535 34.704 2.16 34.722 ;
     RECT  2.155 35.748 2.16 35.874 ;
     RECT  0.535 36.756 2.16 36.774 ;
     RECT  2.155 37.674 2.16 37.692 ;
     RECT  0.535 43.956 2.16 44.982 ;
     RECT  0.535 46.044 2.16 47.844 ;
     RECT  0.535 48.78 2.16 48.834 ;
     RECT  0.535 49.896 2.16 49.914 ;
     RECT  1.975 52.254 2.16 52.974 ;
     RECT  1.759 54.684 2.16 55.134 ;
     RECT  0.535 60.354 2.16 63.414 ;
     RECT  2.155 64.98 2.16 64.998 ;
     RECT  1.175 67.806 2.16 67.824 ;
     RECT  0.535 73.044 2.16 73.134 ;
     RECT  2.011 74.088 2.16 74.844 ;
     RECT  0.203 76.554 2.16 76.572 ;
     RECT  0.283 79.326 2.16 80.154 ;
     RECT  0.599 81.486 2.16 84.474 ;
     RECT  0.535 85.428 2.16 86.058 ;
     RECT  0.535 88.362 2.16 88.38 ;
     RECT  1.255 91.476 2.16 91.494 ;
     RECT  1.435 92.556 2.16 93.114 ;
     RECT  29.515 99.27 29.723 99.288 ;
     RECT  2.16 2.151 62.586 96.939 ;
     RECT  62.586 14.994 62.735 24.462 ;
     RECT  62.586 25.218 62.735 38.196 ;
     RECT  62.735 25.218 62.807 38.034 ;
     RECT  62.586 77.67 62.879 96.048 ;
     RECT  62.879 85.77 62.951 96.048 ;
     RECT  62.586 39.06 63.059 39.618 ;
     RECT  62.879 77.67 63.239 85.014 ;
     RECT  62.807 25.218 63.311 27.774 ;
     RECT  62.807 28.566 63.311 33.948 ;
     RECT  63.059 39.06 63.311 39.078 ;
     RECT  62.586 48.006 63.311 57.978 ;
     RECT  62.586 64.134 63.311 70.938 ;
     RECT  63.239 77.67 63.311 80.424 ;
     RECT  62.951 85.77 63.311 92.232 ;
     RECT  63.311 28.566 63.347 33.876 ;
     RECT  62.807 34.866 63.347 38.034 ;
     RECT  63.311 48.006 63.347 48.339 ;
     RECT  63.311 49.248 63.347 55.044 ;
     RECT  63.311 56.034 63.347 57.978 ;
     RECT  62.586 61.398 63.347 62.028 ;
     RECT  63.311 65.79 63.347 70.56 ;
     RECT  63.239 81.72 63.347 85.014 ;
     RECT  63.311 86.04 63.347 92.232 ;
     RECT  62.951 93.024 63.347 96.048 ;
     RECT  63.347 29.88 63.383 33.876 ;
     RECT  63.347 49.248 63.383 55.008 ;
     RECT  63.347 56.034 63.383 57.438 ;
     RECT  63.347 81.72 63.383 81.738 ;
     RECT  63.347 90.396 63.383 92.232 ;
     RECT  63.383 30.312 63.419 33.876 ;
     RECT  63.383 49.248 63.455 53.424 ;
     RECT  63.347 93.294 63.563 96.048 ;
     RECT  63.383 92.178 63.671 92.232 ;
     RECT  63.347 36.558 63.851 38.034 ;
     RECT  63.311 77.67 63.851 80.154 ;
     RECT  63.563 93.294 63.851 95.742 ;
     RECT  62.735 15.03 63.887 24.462 ;
     RECT  63.311 25.218 63.887 26.388 ;
     RECT  63.311 27.144 63.887 27.774 ;
     RECT  63.347 28.566 63.887 28.584 ;
     RECT  63.419 30.312 63.887 31.986 ;
     RECT  63.419 32.778 63.887 33.876 ;
     RECT  63.347 34.866 63.887 35.604 ;
     RECT  63.851 36.594 63.887 38.034 ;
     RECT  63.455 49.248 63.887 51.498 ;
     RECT  63.455 52.56 63.887 53.424 ;
     RECT  63.383 54.216 63.887 55.008 ;
     RECT  63.383 56.106 63.887 57.168 ;
     RECT  63.347 62.01 63.887 62.028 ;
     RECT  63.311 64.134 63.887 65.034 ;
     RECT  63.347 65.826 63.887 70.56 ;
     RECT  63.851 77.67 63.887 78.309 ;
     RECT  63.851 79.056 63.887 79.272 ;
     RECT  63.851 80.028 63.887 80.154 ;
     RECT  63.347 82.53 63.887 85.014 ;
     RECT  63.347 86.04 63.887 89.334 ;
     RECT  63.383 90.396 63.887 91.188 ;
     RECT  63.887 15.03 63.923 16.128 ;
     RECT  63.887 18.198 63.923 19.062 ;
     RECT  63.887 20.124 63.923 20.178 ;
     RECT  63.887 22.356 63.923 24.12 ;
     RECT  63.887 25.452 63.923 26.082 ;
     RECT  63.887 30.312 63.923 30.636 ;
     RECT  63.887 31.428 63.923 31.716 ;
     RECT  63.887 32.886 63.923 33.408 ;
     RECT  63.887 36.864 63.923 37.494 ;
     RECT  63.347 48.006 63.923 48.024 ;
     RECT  63.887 50.436 63.923 50.454 ;
     RECT  63.887 52.56 63.923 52.578 ;
     RECT  63.887 56.106 63.923 56.124 ;
     RECT  63.887 64.602 63.923 64.62 ;
     RECT  63.887 65.826 63.923 65.844 ;
     RECT  63.887 67.14 63.923 67.158 ;
     RECT  63.887 68.076 63.923 68.238 ;
     RECT  63.887 69.804 63.923 69.822 ;
     RECT  63.887 78.246 63.923 78.309 ;
     RECT  63.887 79.056 63.923 79.074 ;
     RECT  63.887 80.136 63.923 80.154 ;
     RECT  63.887 82.53 63.923 83.628 ;
     RECT  63.887 84.654 63.923 84.672 ;
     RECT  63.887 88.092 63.923 88.254 ;
     RECT  63.887 89.316 63.923 89.334 ;
     RECT  63.887 90.9 63.923 90.918 ;
     RECT  63.851 93.294 63.923 94.194 ;
     RECT  63.923 15.03 63.959 15.588 ;
     RECT  63.923 18.27 63.959 18.324 ;
     RECT  63.923 22.626 63.959 23.418 ;
     RECT  63.923 25.452 63.959 25.848 ;
     RECT  63.923 30.618 63.959 30.636 ;
     RECT  63.923 31.698 63.959 31.716 ;
     RECT  63.923 32.886 63.959 32.904 ;
     RECT  63.887 34.866 63.959 35.028 ;
     RECT  63.887 51.21 63.959 51.228 ;
     RECT  63.923 78.291 63.959 78.309 ;
     RECT  63.923 83.61 63.959 83.628 ;
     RECT  63.887 87.282 63.959 87.3 ;
     RECT  63.671 92.178 63.959 92.196 ;
     RECT  63.959 15.264 63.995 15.588 ;
     RECT  63.923 20.124 63.995 20.142 ;
     RECT  63.959 35.01 63.995 35.028 ;
     RECT  63.923 93.636 63.995 94.194 ;
     RECT  63.959 18.27 64.031 18.288 ;
     RECT  63.995 94.176 64.031 94.194 ;
     RECT  63.995 15.3 64.067 15.588 ;
     RECT  63.887 20.934 64.067 21.528 ;
     RECT  63.851 95.148 64.067 95.742 ;
     RECT  64.067 15.3 64.139 15.318 ;
     RECT  63.959 25.722 64.651 25.848 ;
     RECT  63.923 88.092 64.651 88.11 ;
     RECT  64.067 95.724 64.679 95.742 ;
     RECT  64.067 21.402 64.751 21.528 ;
     RECT  64.651 25.722 64.751 26.154 ;
     RECT  64.651 27.72 64.751 27.738 ;
     RECT  64.651 31.806 64.751 31.824 ;
     RECT  64.651 33.318 64.751 33.336 ;
     RECT  64.651 48.78 64.751 48.798 ;
     RECT  64.651 65.646 64.751 65.664 ;
     RECT  64.651 69.966 64.751 69.984 ;
     RECT  64.651 82.611 64.751 82.944 ;
     RECT  64.651 87.966 64.751 88.254 ;
     RECT  64.651 90.216 64.751 90.234 ;
    LAYER M3 ;
     RECT  2.415 2.143 2.505 2.413 ;
     RECT  5.115 2.143 5.205 2.413 ;
     RECT  7.815 2.143 7.905 2.413 ;
     RECT  10.515 2.143 10.605 2.413 ;
     RECT  13.215 2.143 13.305 2.413 ;
     RECT  15.915 2.143 16.005 2.413 ;
     RECT  18.615 2.143 18.705 2.413 ;
     RECT  21.315 2.143 21.405 2.413 ;
     RECT  24.015 2.143 24.105 2.413 ;
     RECT  26.715 2.143 26.805 2.413 ;
     RECT  29.415 2.143 29.505 2.413 ;
     RECT  32.115 2.143 32.205 2.413 ;
     RECT  34.815 2.143 34.905 2.413 ;
     RECT  37.515 2.143 37.605 2.413 ;
     RECT  40.215 2.143 40.305 2.413 ;
     RECT  42.915 2.143 43.005 2.413 ;
     RECT  45.615 2.143 45.705 2.413 ;
     RECT  48.315 2.143 48.405 2.413 ;
     RECT  51.015 2.143 51.105 2.413 ;
     RECT  53.715 2.143 53.805 2.413 ;
     RECT  56.415 2.143 56.505 2.413 ;
     RECT  59.115 2.143 59.205 2.413 ;
     RECT  61.815 2.143 61.905 2.413 ;
     RECT  27.9 5.845 27.918 5.881 ;
     RECT  27.9 5.881 28.494 6.007 ;
     RECT  25.524 6.277 25.542 6.385 ;
     RECT  26.715 2.413 26.997 6.385 ;
     RECT  25.524 6.385 26.997 6.511 ;
     RECT  27.864 6.007 28.494 6.511 ;
     RECT  24.015 2.413 24.297 6.547 ;
     RECT  25.092 6.511 28.494 6.547 ;
     RECT  29.415 2.413 29.697 6.655 ;
     RECT  23.364 6.547 28.494 6.691 ;
     RECT  29.415 6.655 30.186 6.691 ;
     RECT  32.115 2.413 32.397 6.781 ;
     RECT  34.815 2.413 35.097 6.781 ;
     RECT  23.328 6.691 31.122 6.907 ;
     RECT  32.115 6.781 32.562 6.907 ;
     RECT  32.115 6.907 32.922 6.961 ;
     RECT  34.56 6.781 35.154 6.961 ;
     RECT  32.115 6.961 33.174 7.087 ;
     RECT  34.164 6.961 35.154 7.087 ;
     RECT  40.215 2.413 40.497 7.087 ;
     RECT  23.328 6.907 31.23 7.115 ;
     RECT  38.772 7.087 38.79 7.123 ;
     RECT  31.104 7.115 31.23 7.195 ;
     RECT  32.04 7.087 33.174 7.195 ;
     RECT  34.164 7.087 35.334 7.195 ;
     RECT  36.108 7.087 36.126 7.195 ;
     RECT  38.772 7.123 39.366 7.195 ;
     RECT  40.215 7.087 40.842 7.195 ;
     RECT  22.572 6.811 22.59 7.321 ;
     RECT  23.328 7.115 30.294 7.321 ;
     RECT  31.104 7.195 33.174 7.321 ;
     RECT  34.164 7.195 36.486 7.321 ;
     RECT  31.104 7.321 36.486 7.349 ;
     RECT  22.572 7.321 30.294 7.465 ;
     RECT  22.536 7.465 30.294 7.897 ;
     RECT  31.104 7.349 36.414 7.897 ;
     RECT  51.015 2.413 51.297 7.897 ;
     RECT  42.915 2.413 43.197 7.969 ;
     RECT  21.315 2.413 21.597 8.005 ;
     RECT  38.772 7.195 41.022 8.005 ;
     RECT  42.192 7.969 43.197 8.005 ;
     RECT  2.415 2.413 2.697 8.041 ;
     RECT  21.132 8.005 21.597 8.041 ;
     RECT  37.515 2.413 37.797 8.041 ;
     RECT  50.832 7.897 51.297 8.041 ;
     RECT  37.515 8.041 37.89 8.155 ;
     RECT  38.772 8.005 43.197 8.155 ;
     RECT  52.74 8.131 52.758 8.167 ;
     RECT  22.536 7.897 36.414 8.203 ;
     RECT  52.416 8.167 52.758 8.239 ;
     RECT  53.715 2.413 53.997 8.275 ;
     RECT  5.115 2.413 5.397 8.311 ;
     RECT  49.392 8.155 49.41 8.311 ;
     RECT  50.832 8.041 51.462 8.311 ;
     RECT  52.416 8.239 52.866 8.311 ;
     RECT  53.676 8.275 53.997 8.311 ;
     RECT  37.515 8.155 43.197 8.401 ;
     RECT  22.536 8.203 36.486 8.437 ;
     RECT  22.428 8.437 36.486 8.491 ;
     RECT  37.515 8.401 43.65 8.491 ;
     RECT  19.944 8.401 19.962 8.509 ;
     RECT  21.096 8.041 21.597 8.539 ;
     RECT  22.428 8.491 44.334 8.545 ;
     RECT  2.415 8.041 2.79 8.581 ;
     RECT  3.6 8.005 3.618 8.581 ;
     RECT  19.908 8.509 19.962 8.581 ;
     RECT  20.7 8.539 21.597 8.581 ;
     RECT  22.392 8.545 44.334 8.581 ;
     RECT  48.315 2.413 48.597 8.581 ;
     RECT  49.392 8.311 51.462 8.581 ;
     RECT  2.415 8.581 3.618 8.671 ;
     RECT  4.68 8.311 5.397 8.671 ;
     RECT  48.315 8.581 51.462 8.707 ;
     RECT  4.644 8.671 5.397 8.743 ;
     RECT  0.036 8.581 0.054 8.779 ;
     RECT  4.644 8.743 5.634 8.779 ;
     RECT  6.624 8.581 6.642 8.779 ;
     RECT  2.376 8.671 3.618 8.806 ;
     RECT  19.908 8.581 44.334 8.815 ;
     RECT  48.315 8.707 51.534 8.815 ;
     RECT  52.416 8.311 53.997 8.815 ;
     RECT  2.34 8.806 3.618 8.851 ;
     RECT  4.644 8.779 6.642 8.851 ;
     RECT  48.315 8.815 53.997 8.851 ;
     RECT  4.644 8.851 6.786 8.941 ;
     RECT  45.615 2.413 45.897 8.941 ;
     RECT  2.304 8.851 3.618 8.977 ;
     RECT  18.615 2.413 18.897 8.977 ;
     RECT  19.8 8.815 44.334 8.977 ;
     RECT  2.232 8.977 3.618 9.013 ;
     RECT  4.428 8.941 7.002 9.013 ;
     RECT  7.815 2.413 8.097 9.013 ;
     RECT  0.036 8.779 0.378 9.049 ;
     RECT  2.232 9.013 8.097 9.053 ;
     RECT  48.315 8.851 54.126 9.085 ;
     RECT  45.615 8.941 45.954 9.121 ;
     RECT  18.615 8.977 44.334 9.247 ;
     RECT  45.252 9.121 45.954 9.247 ;
     RECT  0.036 9.049 0.45 9.319 ;
     RECT  17.892 9.247 45.954 9.355 ;
     RECT  17.748 9.355 45.954 9.383 ;
     RECT  44.1 9.383 45.954 9.389 ;
     RECT  56.415 2.413 56.697 9.481 ;
     RECT  44.136 9.389 45.954 9.517 ;
     RECT  17.748 9.383 43.29 9.545 ;
     RECT  44.136 9.517 46.206 9.617 ;
     RECT  2.304 9.053 8.097 9.625 ;
     RECT  44.352 9.617 46.206 9.625 ;
     RECT  9.216 9.553 9.234 9.661 ;
     RECT  9.144 9.661 9.234 9.689 ;
     RECT  2.304 9.625 8.154 9.751 ;
     RECT  44.352 9.625 46.458 9.779 ;
     RECT  15.915 2.413 16.197 9.823 ;
     RECT  2.304 9.751 8.37 9.931 ;
     RECT  9.144 9.689 9.198 9.931 ;
     RECT  0.036 9.319 0.558 9.965 ;
     RECT  2.304 9.931 9.198 10.049 ;
     RECT  48.315 9.085 54.522 10.121 ;
     RECT  15.915 9.823 16.902 10.129 ;
     RECT  56.415 9.481 56.754 10.165 ;
     RECT  48.315 10.121 54.414 10.193 ;
     RECT  17.892 9.545 43.29 10.201 ;
     RECT  2.304 10.049 8.874 10.253 ;
     RECT  0.036 9.965 0.522 10.319 ;
     RECT  0.108 10.319 0.522 10.349 ;
     RECT  15.915 10.129 17.118 10.471 ;
     RECT  17.892 10.201 43.614 10.471 ;
     RECT  15.915 10.471 43.614 10.597 ;
     RECT  44.352 9.779 45.99 10.597 ;
     RECT  59.115 2.413 59.397 10.597 ;
     RECT  15.915 10.597 45.99 10.705 ;
     RECT  58.788 10.597 59.397 10.705 ;
     RECT  15.915 10.705 46.026 10.859 ;
     RECT  2.34 10.253 8.874 10.867 ;
     RECT  10.515 2.413 10.797 10.891 ;
     RECT  48.315 10.193 54.378 10.891 ;
     RECT  2.34 10.867 8.946 10.925 ;
     RECT  2.34 10.925 8.874 10.931 ;
     RECT  47.124 10.975 47.142 11.011 ;
     RECT  10.515 10.891 10.818 11.021 ;
     RECT  44.712 10.859 46.026 11.165 ;
     RECT  44.748 11.165 46.026 11.245 ;
     RECT  47.016 11.011 47.142 11.245 ;
     RECT  48.204 10.891 54.378 11.245 ;
     RECT  2.34 10.931 8.586 11.281 ;
     RECT  48.024 11.245 54.378 11.281 ;
     RECT  44.748 11.245 47.142 11.309 ;
     RECT  44.928 11.309 47.142 11.399 ;
     RECT  48.024 11.281 54.45 11.443 ;
     RECT  61.815 2.413 62.097 11.443 ;
     RECT  44.928 11.399 46.026 11.501 ;
     RECT  61.815 11.443 62.154 11.515 ;
     RECT  15.915 10.859 36.486 11.551 ;
     RECT  47.988 11.443 54.666 11.551 ;
     RECT  56.415 10.165 56.934 11.551 ;
     RECT  46.764 11.399 47.142 11.641 ;
     RECT  47.988 11.551 54.738 11.641 ;
     RECT  15.408 11.551 36.486 11.677 ;
     RECT  37.515 10.859 43.974 11.677 ;
     RECT  56.415 11.551 57.042 11.677 ;
     RECT  13.215 2.413 13.497 11.707 ;
     RECT  2.304 11.281 8.586 11.749 ;
     RECT  46.764 11.641 54.738 11.749 ;
     RECT  46.764 11.749 54.918 11.755 ;
     RECT  15.408 11.677 43.974 11.777 ;
     RECT  61.776 11.515 62.154 11.785 ;
     RECT  0.108 10.349 0.486 11.821 ;
     RECT  2.304 11.749 9.27 11.849 ;
     RECT  55.836 11.677 57.042 11.939 ;
     RECT  55.836 11.939 56.898 11.947 ;
     RECT  55.764 11.947 56.898 11.975 ;
     RECT  6.336 11.849 9.27 12.055 ;
     RECT  44.928 11.501 45.897 12.055 ;
     RECT  6.336 12.055 9.306 12.209 ;
     RECT  58.716 10.705 59.397 12.217 ;
     RECT  37.515 11.777 43.974 12.253 ;
     RECT  44.82 12.055 45.897 12.253 ;
     RECT  46.764 11.755 54.99 12.289 ;
     RECT  55.764 11.975 56.754 12.289 ;
     RECT  0.108 11.821 0.558 12.325 ;
     RECT  61.452 11.785 62.154 12.325 ;
     RECT  9.288 12.209 9.306 12.353 ;
     RECT  37.515 12.253 45.897 12.451 ;
     RECT  37.515 12.451 45.99 12.487 ;
     RECT  46.764 12.289 56.754 12.487 ;
     RECT  15.408 11.777 36.342 12.523 ;
     RECT  13.104 11.707 13.497 12.551 ;
     RECT  15.048 12.523 36.342 12.571 ;
     RECT  37.515 12.487 56.754 12.571 ;
     RECT  10.515 11.021 10.797 12.631 ;
     RECT  60.444 12.487 60.462 12.749 ;
     RECT  2.304 11.849 5.598 12.757 ;
     RECT  6.336 12.209 8.55 12.757 ;
     RECT  13.215 12.551 13.497 12.829 ;
     RECT  14.256 11.821 14.274 12.829 ;
     RECT  13.215 12.829 14.274 12.865 ;
     RECT  15.048 12.571 56.754 12.865 ;
     RECT  61.308 12.325 62.154 12.865 ;
     RECT  10.515 12.631 10.926 12.929 ;
     RECT  0.108 12.325 0.594 13.147 ;
     RECT  2.304 12.757 8.55 13.171 ;
     RECT  0.108 13.147 0.63 13.199 ;
     RECT  2.088 13.171 8.55 13.244 ;
     RECT  2.304 13.244 8.55 13.331 ;
     RECT  6.264 13.331 8.55 13.369 ;
     RECT  13.215 12.865 56.754 13.369 ;
     RECT  58.464 12.217 59.397 13.405 ;
     RECT  58.464 13.405 59.454 13.639 ;
     RECT  13.215 13.369 57.294 13.711 ;
     RECT  13.176 13.711 57.294 13.837 ;
     RECT  58.464 13.639 59.886 13.837 ;
     RECT  0.108 13.199 0.558 13.901 ;
     RECT  6.264 13.369 9.234 13.973 ;
     RECT  13.176 13.837 59.886 13.981 ;
     RECT  2.304 13.331 5.49 14.009 ;
     RECT  2.376 14.009 5.49 14.071 ;
     RECT  6.264 13.973 8.91 14.071 ;
     RECT  61.056 12.865 62.37 14.107 ;
     RECT  13.104 13.981 59.886 14.215 ;
     RECT  60.984 14.107 62.37 14.215 ;
     RECT  2.376 14.071 8.91 14.243 ;
     RECT  2.376 14.243 8.838 14.288 ;
     RECT  2.376 14.288 8.694 14.369 ;
     RECT  9.648 14.155 9.666 14.369 ;
     RECT  2.376 14.369 2.934 14.429 ;
     RECT  10.515 12.929 10.797 14.449 ;
     RECT  10.515 14.449 10.998 14.549 ;
     RECT  0.108 13.901 0.342 14.635 ;
     RECT  2.415 14.429 2.934 14.639 ;
     RECT  0.108 14.635 0.378 14.683 ;
     RECT  13.104 14.215 62.37 14.747 ;
     RECT  10.515 14.549 10.926 14.819 ;
     RECT  0.108 14.683 0.558 14.861 ;
     RECT  60.552 14.747 62.37 14.953 ;
     RECT  60.552 14.953 62.406 14.989 ;
     RECT  13.104 14.747 59.454 15.017 ;
     RECT  63.936 15.025 63.954 15.259 ;
     RECT  0.108 14.861 0.162 15.293 ;
     RECT  63.936 15.259 63.99 15.295 ;
     RECT  2.415 14.639 2.862 15.307 ;
     RECT  3.708 14.369 8.694 15.359 ;
     RECT  6.84 15.359 8.694 15.421 ;
     RECT  0.108 15.293 0.126 15.437 ;
     RECT  60.552 14.989 62.73 15.493 ;
     RECT  6.84 15.421 9.126 15.557 ;
     RECT  10.515 14.819 10.854 15.565 ;
     RECT  2.304 15.307 2.862 15.601 ;
     RECT  3.708 15.359 5.922 15.601 ;
     RECT  6.84 15.557 9.054 15.755 ;
     RECT  13.104 15.017 43.938 15.763 ;
     RECT  44.712 15.017 59.454 15.763 ;
     RECT  6.84 15.755 8.982 15.791 ;
     RECT  10.515 15.565 10.998 15.791 ;
     RECT  13.104 15.763 59.454 15.799 ;
     RECT  60.444 15.493 62.73 15.799 ;
     RECT  2.304 15.601 5.922 16.069 ;
     RECT  2.268 16.069 5.922 16.105 ;
     RECT  63.936 15.295 64.134 16.105 ;
     RECT  2.268 16.105 6.102 16.141 ;
     RECT  6.84 15.791 8.694 16.141 ;
     RECT  63.9 16.105 64.134 16.171 ;
     RECT  2.268 16.141 8.694 16.205 ;
     RECT  13.104 15.799 62.73 16.339 ;
     RECT  13.104 16.339 62.766 16.403 ;
     RECT  2.304 16.205 8.694 16.439 ;
     RECT  2.304 16.439 5.778 16.493 ;
     RECT  6.588 16.439 8.694 16.537 ;
     RECT  0.108 16.501 0.126 16.603 ;
     RECT  0.108 16.603 0.198 16.609 ;
     RECT  1.116 16.303 1.134 16.609 ;
     RECT  10.515 15.791 10.854 16.609 ;
     RECT  0.108 16.609 1.134 16.685 ;
     RECT  10.515 16.609 10.926 16.709 ;
     RECT  10.515 16.709 10.854 16.799 ;
     RECT  2.415 16.493 5.778 16.871 ;
     RECT  4.176 16.871 5.778 16.973 ;
     RECT  4.392 16.973 5.778 17.069 ;
     RECT  63.864 16.171 64.134 17.069 ;
     RECT  6.588 16.537 9.126 17.113 ;
     RECT  0.108 16.685 0.558 17.165 ;
     RECT  6.588 17.113 9.162 17.185 ;
     RECT  0.108 17.165 0.198 17.261 ;
     RECT  4.5 17.069 5.778 17.311 ;
     RECT  6.588 17.185 9.234 17.311 ;
     RECT  13.215 16.403 62.766 17.311 ;
     RECT  2.415 16.871 3.402 17.323 ;
     RECT  12.744 17.311 62.766 17.467 ;
     RECT  63.864 17.069 64.098 17.515 ;
     RECT  0.144 17.261 0.198 17.549 ;
     RECT  12.312 17.467 62.766 17.609 ;
     RECT  12.744 17.609 62.766 17.741 ;
     RECT  2.304 17.323 3.402 17.761 ;
     RECT  60.444 17.741 62.766 17.761 ;
     RECT  63.756 17.515 64.098 17.761 ;
     RECT  4.5 17.311 9.234 18.059 ;
     RECT  2.304 17.761 3.618 18.121 ;
     RECT  4.5 18.059 5.886 18.121 ;
     RECT  60.444 17.761 64.098 18.125 ;
     RECT  0.144 17.549 0.162 18.221 ;
     RECT  6.732 18.059 9.234 18.301 ;
     RECT  2.304 18.121 5.886 18.427 ;
     RECT  6.732 18.301 9.342 18.455 ;
     RECT  12.744 17.741 59.526 18.463 ;
     RECT  6.732 18.455 9.27 18.491 ;
     RECT  12.456 18.463 59.526 18.499 ;
     RECT  60.444 18.125 64.026 18.509 ;
     RECT  12.024 18.499 59.526 18.535 ;
     RECT  60.444 18.509 62.73 18.535 ;
     RECT  6.84 18.491 9.27 18.599 ;
     RECT  1.98 18.427 5.886 18.605 ;
     RECT  0.54 18.769 0.558 18.893 ;
     RECT  63.468 18.509 64.026 18.893 ;
     RECT  2.304 18.605 5.886 19.003 ;
     RECT  11.808 18.535 62.73 19.003 ;
     RECT  11.736 19.003 62.73 19.075 ;
     RECT  11.592 19.075 62.73 19.085 ;
     RECT  6.84 18.599 8.478 19.339 ;
     RECT  2.304 19.003 5.922 19.345 ;
     RECT  63.468 18.893 63.954 19.373 ;
     RECT  6.84 19.339 8.73 19.471 ;
     RECT  11.592 19.085 62.37 19.499 ;
     RECT  6.84 19.471 8.91 19.579 ;
     RECT  0.144 19.435 0.198 19.612 ;
     RECT  6.84 19.579 9.162 19.643 ;
     RECT  9.144 19.643 9.162 19.651 ;
     RECT  2.304 19.345 5.958 19.661 ;
     RECT  4.248 19.661 5.958 19.741 ;
     RECT  0.108 19.612 0.198 19.757 ;
     RECT  2.304 19.661 3.474 19.769 ;
     RECT  10.515 16.799 10.797 19.777 ;
     RECT  11.592 19.499 36.27 19.777 ;
     RECT  4.248 19.741 5.994 19.819 ;
     RECT  6.84 19.643 8.19 19.819 ;
     RECT  4.248 19.819 8.19 19.949 ;
     RECT  9.144 19.651 9.234 19.949 ;
     RECT  0.144 19.757 0.198 20.011 ;
     RECT  63.864 19.373 63.954 20.119 ;
     RECT  10.515 19.777 36.27 20.281 ;
     RECT  37.08 19.499 62.37 20.281 ;
     RECT  10.515 20.281 62.37 20.309 ;
     RECT  63.864 20.119 63.99 20.353 ;
     RECT  10.515 20.309 26.997 20.381 ;
     RECT  6.768 19.949 8.19 20.389 ;
     RECT  4.248 19.949 5.994 20.395 ;
     RECT  6.768 20.389 8.658 20.489 ;
     RECT  27.72 20.309 62.37 20.587 ;
     RECT  63.288 20.353 63.99 20.587 ;
     RECT  9.432 20.551 9.522 20.687 ;
     RECT  2.304 19.769 3.402 20.695 ;
     RECT  4.14 20.395 5.994 20.695 ;
     RECT  6.768 20.489 8.586 20.695 ;
     RECT  9.432 20.687 9.45 20.731 ;
     RECT  9.36 20.731 9.45 20.759 ;
     RECT  0.144 20.011 0.342 20.875 ;
     RECT  0.108 20.875 0.342 20.909 ;
     RECT  0.108 20.909 0.234 20.921 ;
     RECT  27.72 20.587 63.99 20.929 ;
     RECT  27.72 20.929 64.062 20.993 ;
     RECT  2.304 20.695 5.994 21.001 ;
     RECT  6.732 20.695 8.586 21.001 ;
     RECT  2.304 21.001 8.586 21.119 ;
     RECT  25.092 20.381 26.997 21.163 ;
     RECT  27.72 20.993 62.442 21.163 ;
     RECT  10.515 20.381 24.354 21.199 ;
     RECT  25.092 21.163 62.442 21.199 ;
     RECT  63.288 20.993 64.062 21.355 ;
     RECT  63.288 21.355 64.674 21.397 ;
     RECT  1.26 21.259 1.278 21.403 ;
     RECT  9.36 20.759 9.378 21.433 ;
     RECT  1.152 21.403 1.278 21.437 ;
     RECT  1.152 21.437 1.17 21.533 ;
     RECT  9.324 21.433 9.378 21.533 ;
     RECT  63.288 21.397 64.746 21.533 ;
     RECT  9.324 21.533 9.342 21.541 ;
     RECT  9.252 21.541 9.342 21.569 ;
     RECT  63.288 21.533 64.674 21.581 ;
     RECT  0.144 20.921 0.234 21.643 ;
     RECT  9.252 21.569 9.27 21.659 ;
     RECT  0.144 21.643 0.342 21.739 ;
     RECT  10.515 21.199 62.442 21.739 ;
     RECT  63.288 21.581 64.062 21.739 ;
     RECT  0.108 21.739 0.342 21.773 ;
     RECT  10.515 21.739 64.062 21.775 ;
     RECT  0.108 21.773 0.126 21.965 ;
     RECT  10.332 21.775 64.062 21.965 ;
     RECT  2.304 21.119 8.514 22.109 ;
     RECT  4.14 22.109 8.514 22.199 ;
     RECT  10.332 21.965 63.954 22.513 ;
     RECT  9.756 22.513 63.954 22.613 ;
     RECT  2.304 22.109 3.258 22.621 ;
     RECT  4.248 22.199 8.514 22.621 ;
     RECT  9.756 22.613 62.694 22.711 ;
     RECT  9.72 22.711 62.694 22.739 ;
     RECT  30.564 22.739 62.694 22.919 ;
     RECT  0.54 22.783 0.558 22.925 ;
     RECT  2.268 22.621 3.258 23.035 ;
     RECT  4.248 22.621 8.838 23.035 ;
     RECT  9.72 22.739 29.697 23.117 ;
     RECT  1.98 23.035 8.838 23.213 ;
     RECT  9.72 23.117 27.09 23.315 ;
     RECT  2.304 23.213 8.838 23.431 ;
     RECT  9.72 23.315 26.997 23.431 ;
     RECT  52.416 22.919 62.694 23.563 ;
     RECT  63.828 22.613 63.954 23.563 ;
     RECT  52.416 23.563 63.954 23.621 ;
     RECT  30.564 22.919 51.678 23.665 ;
     RECT  52.416 23.621 62.442 23.665 ;
     RECT  63.288 23.621 63.954 23.693 ;
     RECT  2.304 23.431 26.997 23.729 ;
     RECT  30.564 23.665 62.442 23.819 ;
     RECT  63.864 23.693 63.954 23.885 ;
     RECT  25.344 23.729 26.997 23.927 ;
     RECT  2.304 23.729 24.57 24.125 ;
     RECT  25.344 23.927 25.866 24.125 ;
     RECT  30.924 23.819 62.442 24.197 ;
     RECT  0.144 23.611 0.162 24.235 ;
     RECT  30.924 24.197 49.122 24.269 ;
     RECT  49.86 24.197 62.442 24.269 ;
     RECT  0.144 24.235 0.234 24.331 ;
     RECT  63.864 23.885 63.918 24.365 ;
     RECT  0.108 24.331 0.234 24.413 ;
     RECT  63.864 24.365 63.882 24.427 ;
     RECT  25.344 24.125 25.614 24.467 ;
     RECT  30.924 24.269 48.942 24.629 ;
     RECT  60.732 24.269 62.442 24.629 ;
     RECT  1.26 24.811 1.278 24.907 ;
     RECT  1.152 24.907 1.278 24.941 ;
     RECT  49.86 24.269 59.994 25.051 ;
     RECT  60.732 24.629 62.406 25.051 ;
     RECT  63.288 24.427 63.882 25.099 ;
     RECT  25.272 24.745 25.29 25.169 ;
     RECT  2.304 24.125 24.534 25.177 ;
     RECT  31.068 24.629 48.942 25.249 ;
     RECT  49.86 25.051 62.406 25.277 ;
     RECT  0.108 24.413 0.162 25.387 ;
     RECT  26.715 23.927 26.997 25.411 ;
     RECT  61.164 25.277 62.406 25.447 ;
     RECT  63.288 25.099 63.918 25.447 ;
     RECT  27.864 23.117 29.697 25.475 ;
     RECT  61.164 25.447 63.954 25.483 ;
     RECT  2.304 25.177 25.182 25.511 ;
     RECT  0.108 25.387 0.342 25.517 ;
     RECT  2.304 25.511 25.146 25.547 ;
     RECT  61.164 25.483 63.99 25.583 ;
     RECT  2.34 25.547 24.57 25.619 ;
     RECT  0.108 25.517 0.162 25.661 ;
     RECT  1.152 24.941 1.17 25.661 ;
     RECT  63.288 25.583 63.99 25.675 ;
     RECT  26.208 25.411 26.997 25.709 ;
     RECT  63.288 25.675 64.674 25.717 ;
     RECT  31.068 25.249 49.086 25.861 ;
     RECT  63.288 25.717 64.746 25.901 ;
     RECT  29.34 25.475 29.697 26.015 ;
     RECT  30.78 25.861 49.086 26.051 ;
     RECT  49.86 25.277 59.814 26.059 ;
     RECT  61.164 25.583 62.37 26.095 ;
     RECT  2.415 25.619 24.57 26.123 ;
     RECT  41.796 26.051 49.086 26.131 ;
     RECT  49.86 26.059 59.85 26.131 ;
     RECT  64.656 25.901 64.746 26.159 ;
     RECT  64.656 26.159 64.674 26.189 ;
     RECT  30.78 26.051 41.058 26.248 ;
     RECT  60.84 26.095 62.37 26.249 ;
     RECT  4.5 26.123 24.57 26.285 ;
     RECT  30.708 26.248 41.058 26.285 ;
     RECT  6.912 26.285 24.57 26.321 ;
     RECT  60.948 26.249 62.37 26.347 ;
     RECT  63.288 25.901 63.918 26.347 ;
     RECT  0.108 25.661 0.126 26.357 ;
     RECT  26.715 25.709 26.997 26.365 ;
     RECT  27.864 25.475 28.314 26.365 ;
     RECT  7.38 26.321 24.57 26.393 ;
     RECT  41.796 26.131 59.85 26.393 ;
     RECT  4.5 26.285 6.138 26.429 ;
     RECT  7.38 26.393 24.534 26.429 ;
     RECT  60.948 26.347 63.918 26.477 ;
     RECT  60.948 26.477 63.882 26.627 ;
     RECT  30.78 26.285 41.058 26.869 ;
     RECT  41.796 26.393 59.706 26.869 ;
     RECT  7.38 26.429 24.297 26.933 ;
     RECT  7.38 26.933 22.05 27.059 ;
     RECT  22.788 26.933 24.297 27.059 ;
     RECT  26.715 26.365 28.314 27.139 ;
     RECT  29.415 26.015 29.697 27.139 ;
     RECT  30.78 26.869 59.706 27.203 ;
     RECT  4.5 26.429 5.397 27.239 ;
     RECT  30.78 27.203 59.454 27.329 ;
     RECT  26.712 27.139 28.314 27.401 ;
     RECT  60.984 26.627 63.882 27.445 ;
     RECT  6.12 26.429 6.138 27.473 ;
     RECT  7.38 27.059 21.834 27.509 ;
     RECT  60.804 27.445 63.882 27.571 ;
     RECT  60.3 27.571 63.882 27.671 ;
     RECT  64.656 27.691 64.674 27.715 ;
     RECT  7.416 27.509 21.834 27.743 ;
     RECT  64.656 27.715 64.746 27.743 ;
     RECT  64.728 27.743 64.746 27.773 ;
     RECT  12.672 27.743 21.834 27.913 ;
     RECT  22.932 27.059 24.297 27.913 ;
     RECT  26.712 27.401 27.054 27.949 ;
     RECT  29.088 27.139 29.697 27.985 ;
     RECT  30.78 27.329 59.397 27.985 ;
     RECT  29.088 27.985 59.397 28.175 ;
     RECT  26.676 27.949 27.054 28.291 ;
     RECT  4.716 27.239 5.397 28.381 ;
     RECT  29.415 28.175 59.397 28.381 ;
     RECT  26.676 28.291 27.126 28.445 ;
     RECT  60.948 27.671 63.882 28.481 ;
     RECT  2.415 26.123 3.654 28.489 ;
     RECT  4.536 28.381 5.397 28.489 ;
     RECT  7.416 27.743 11.898 28.489 ;
     RECT  12.672 27.913 24.297 28.489 ;
     RECT  2.415 28.489 5.397 28.525 ;
     RECT  0.504 28.489 0.522 28.561 ;
     RECT  7.416 28.489 24.297 28.561 ;
     RECT  7.416 28.561 24.426 28.723 ;
     RECT  2.415 28.525 5.922 28.747 ;
     RECT  2.304 28.747 5.922 28.759 ;
     RECT  61.524 28.481 63.882 28.781 ;
     RECT  2.304 28.759 6.354 28.831 ;
     RECT  7.164 28.723 24.426 28.831 ;
     RECT  0.468 28.561 0.522 28.921 ;
     RECT  2.304 28.831 24.426 28.993 ;
     RECT  0.468 28.921 1.206 29.029 ;
     RECT  0.108 29.029 1.206 29.057 ;
     RECT  2.232 28.993 24.426 29.065 ;
     RECT  29.415 28.381 59.85 29.065 ;
     RECT  2.232 29.065 25.11 29.069 ;
     RECT  2.232 29.069 6.282 29.129 ;
     RECT  0.108 29.057 0.558 29.165 ;
     RECT  29.415 29.065 59.994 29.255 ;
     RECT  0.468 29.165 0.558 29.261 ;
     RECT  61.524 28.781 63.378 29.335 ;
     RECT  27.864 27.401 28.314 29.363 ;
     RECT  0.468 29.261 0.522 29.453 ;
     RECT  7.092 29.069 25.11 29.461 ;
     RECT  7.092 29.461 25.218 29.489 ;
     RECT  25.092 29.489 25.218 29.525 ;
     RECT  25.2 29.525 25.218 29.597 ;
     RECT  0.468 29.453 0.486 29.741 ;
     RECT  25.38 29.605 25.398 29.759 ;
     RECT  29.415 29.255 40.77 29.759 ;
     RECT  41.58 29.255 59.994 29.759 ;
     RECT  39.708 29.759 40.77 29.789 ;
     RECT  29.415 29.759 38.97 29.795 ;
     RECT  39.816 29.789 40.77 29.795 ;
     RECT  2.304 29.129 6.282 29.911 ;
     RECT  7.092 29.489 24.297 29.911 ;
     RECT  40.215 29.795 40.77 30.037 ;
     RECT  41.58 29.759 59.397 30.037 ;
     RECT  2.304 29.911 24.297 30.073 ;
     RECT  61.344 29.335 63.378 30.073 ;
     RECT  61.2 30.073 63.378 30.091 ;
     RECT  40.215 30.037 59.397 30.137 ;
     RECT  41.508 30.137 59.397 30.173 ;
     RECT  61.2 30.091 63.882 30.187 ;
     RECT  61.2 30.187 63.918 30.209 ;
     RECT  1.98 30.073 24.297 30.221 ;
     RECT  61.236 30.209 63.918 30.283 ;
     RECT  60.444 29.911 60.462 30.299 ;
     RECT  28.188 29.363 28.314 30.343 ;
     RECT  2.304 30.221 24.297 30.415 ;
     RECT  61.236 30.283 63.954 30.509 ;
     RECT  27.972 30.343 28.314 30.569 ;
     RECT  41.508 30.173 41.634 30.569 ;
     RECT  63.252 30.509 63.954 30.641 ;
     RECT  29.415 29.795 38.358 30.685 ;
     RECT  42.732 30.173 59.397 30.701 ;
     RECT  61.236 30.509 62.262 30.713 ;
     RECT  41.508 30.569 41.526 30.749 ;
     RECT  60.228 30.613 60.246 30.749 ;
     RECT  0.54 30.181 0.558 30.797 ;
     RECT  28.008 30.569 28.314 30.839 ;
     RECT  40.215 30.137 40.497 30.919 ;
     RECT  29.415 30.685 38.502 30.991 ;
     RECT  42.732 30.701 57.438 30.991 ;
     RECT  42.264 30.991 57.438 31.019 ;
     RECT  29.415 30.991 39.186 31.081 ;
     RECT  61.56 30.713 62.262 31.109 ;
     RECT  2.304 30.415 24.498 31.117 ;
     RECT  29.415 31.081 39.222 31.133 ;
     RECT  42.264 31.019 54.918 31.145 ;
     RECT  58.176 30.701 59.397 31.145 ;
     RECT  55.872 31.019 57.438 31.181 ;
     RECT  30.456 31.133 39.222 31.195 ;
     RECT  40.215 30.919 40.554 31.195 ;
     RECT  2.304 31.117 25.182 31.217 ;
     RECT  30.456 31.195 40.554 31.217 ;
     RECT  42.444 31.145 54.918 31.253 ;
     RECT  42.768 31.253 54.918 31.277 ;
     RECT  2.415 31.217 25.182 31.351 ;
     RECT  60.444 31.153 60.498 31.387 ;
     RECT  61.815 31.109 62.262 31.423 ;
     RECT  63.252 30.641 63.918 31.435 ;
     RECT  2.415 31.351 25.326 31.451 ;
     RECT  42.768 31.277 54.738 31.451 ;
     RECT  61.815 31.423 62.334 31.483 ;
     RECT  25.02 31.451 25.326 31.487 ;
     RECT  60.444 31.387 60.534 31.487 ;
     RECT  0.144 31.339 0.162 31.517 ;
     RECT  42.768 31.451 54.702 31.517 ;
     RECT  61.815 31.483 62.406 31.522 ;
     RECT  28.188 30.839 28.314 31.531 ;
     RECT  61.815 31.522 62.442 31.531 ;
     RECT  63.252 31.435 63.954 31.531 ;
     RECT  25.02 31.487 25.218 31.559 ;
     RECT  25.02 31.559 25.182 31.649 ;
     RECT  60.444 31.487 60.498 31.649 ;
     RECT  58.284 31.145 59.397 31.657 ;
     RECT  25.02 31.649 25.11 31.685 ;
     RECT  25.092 31.685 25.11 31.721 ;
     RECT  61.815 31.531 63.954 31.721 ;
     RECT  39.672 31.217 40.554 31.723 ;
     RECT  28.188 31.531 28.35 31.729 ;
     RECT  2.415 31.451 24.297 31.757 ;
     RECT  39.672 31.723 40.662 31.801 ;
     RECT  64.728 31.771 64.746 31.801 ;
     RECT  58.284 31.657 59.85 31.829 ;
     RECT  64.656 31.801 64.746 31.829 ;
     RECT  64.656 31.829 64.674 31.853 ;
     RECT  2.415 31.757 13.497 31.919 ;
     RECT  56.088 31.181 57.438 31.919 ;
     RECT  30.456 31.217 38.61 31.963 ;
     RECT  39.672 31.801 40.77 31.963 ;
     RECT  56.415 31.919 57.438 31.963 ;
     RECT  58.284 31.829 59.397 31.963 ;
     RECT  30.42 31.963 38.61 32.011 ;
     RECT  39.672 31.963 41.13 32.011 ;
     RECT  28.188 31.729 28.458 32.035 ;
     RECT  29.415 31.133 29.697 32.155 ;
     RECT  30.42 32.011 41.13 32.155 ;
     RECT  55.62 32.035 55.638 32.189 ;
     RECT  29.415 32.155 41.13 32.225 ;
     RECT  6.732 31.919 13.497 32.261 ;
     RECT  28.188 32.035 28.494 32.299 ;
     RECT  29.415 32.225 41.094 32.299 ;
     RECT  2.415 31.919 5.814 32.333 ;
     RECT  42.915 31.517 54.702 32.341 ;
     RECT  55.476 32.305 55.494 32.459 ;
     RECT  61.815 31.721 63.882 32.477 ;
     RECT  6.84 32.261 13.497 32.539 ;
     RECT  14.22 31.757 24.297 32.539 ;
     RECT  42.372 32.341 54.702 32.539 ;
     RECT  56.415 31.963 59.397 32.567 ;
     RECT  26.715 28.445 26.997 32.575 ;
     RECT  42.372 32.539 55.098 32.611 ;
     RECT  42.264 32.611 55.098 32.728 ;
     RECT  2.415 32.333 3.654 32.729 ;
     RECT  42.192 32.728 55.098 32.729 ;
     RECT  42.192 32.729 54.954 32.765 ;
     RECT  28.188 32.299 41.094 32.779 ;
     RECT  27.936 32.779 41.094 32.837 ;
     RECT  61.815 32.477 62.262 32.845 ;
     RECT  25.668 32.731 25.686 32.881 ;
     RECT  26.676 32.575 27.054 32.881 ;
     RECT  61.164 32.845 62.262 32.881 ;
     RECT  63.288 32.477 63.882 32.881 ;
     RECT  6.84 32.539 24.297 32.909 ;
     RECT  28.26 32.837 41.094 32.999 ;
     RECT  25.668 32.881 27.054 33.019 ;
     RECT  3.42 32.729 3.654 33.179 ;
     RECT  57.78 32.567 59.397 33.241 ;
     RECT  42.336 32.765 54.954 33.293 ;
     RECT  7.2 32.909 24.297 33.313 ;
     RECT  63.288 32.881 63.954 33.313 ;
     RECT  64.728 33.304 64.746 33.313 ;
     RECT  57.78 33.241 59.994 33.341 ;
     RECT  63.288 33.313 64.746 33.341 ;
     RECT  61.056 32.881 62.262 33.349 ;
     RECT  56.415 32.567 56.934 33.385 ;
     RECT  57.78 33.341 59.397 33.385 ;
     RECT  63.288 33.341 64.674 33.389 ;
     RECT  28.26 32.999 41.058 33.413 ;
     RECT  61.056 33.349 62.37 33.451 ;
     RECT  63.288 33.389 63.954 33.451 ;
     RECT  25.668 33.019 27.378 33.643 ;
     RECT  7.2 33.313 24.57 33.691 ;
     RECT  25.524 33.643 27.378 33.691 ;
     RECT  61.056 33.451 63.954 33.691 ;
     RECT  4.716 32.333 5.814 33.719 ;
     RECT  60.984 33.691 63.954 33.773 ;
     RECT  42.336 33.293 54.738 33.809 ;
     RECT  56.415 33.385 59.397 33.809 ;
     RECT  60.156 33.655 60.174 33.809 ;
     RECT  60.984 33.773 63.882 33.845 ;
     RECT  42.732 33.809 54.738 33.881 ;
     RECT  5.115 33.719 5.814 33.917 ;
     RECT  61.128 33.845 63.882 33.953 ;
     RECT  7.2 33.691 27.378 33.989 ;
     RECT  7.815 33.989 27.378 34.051 ;
     RECT  28.26 33.413 40.497 34.051 ;
     RECT  61.128 33.953 62.802 34.079 ;
     RECT  7.815 34.051 40.497 34.231 ;
     RECT  57.78 33.809 59.397 34.231 ;
     RECT  7.815 34.231 41.094 34.357 ;
     RECT  6.912 34.321 6.93 34.429 ;
     RECT  42.768 33.881 54.738 34.429 ;
     RECT  3.636 33.179 3.654 34.501 ;
     RECT  2.415 32.729 2.697 34.591 ;
     RECT  63.864 33.953 63.882 34.603 ;
     RECT  3.6 34.501 3.654 34.619 ;
     RECT  2.376 34.591 2.697 34.627 ;
     RECT  56.415 33.809 57.042 34.627 ;
     RECT  57.78 34.231 59.85 34.627 ;
     RECT  7.815 34.357 41.202 34.655 ;
     RECT  56.415 34.627 59.85 34.699 ;
     RECT  63.864 34.603 63.954 34.699 ;
     RECT  42.768 34.429 54.918 34.735 ;
     RECT  7.815 34.655 41.13 34.763 ;
     RECT  2.376 34.627 2.826 34.771 ;
     RECT  5.115 33.917 5.397 34.771 ;
     RECT  42.516 34.735 54.918 34.781 ;
     RECT  61.488 34.079 62.802 34.795 ;
     RECT  63.864 34.699 63.99 34.795 ;
     RECT  6.84 34.429 6.93 34.861 ;
     RECT  7.815 34.763 40.986 34.861 ;
     RECT  56.415 34.699 59.886 34.889 ;
     RECT  0.54 34.699 0.558 34.925 ;
     RECT  58.716 34.889 59.886 34.925 ;
     RECT  4.932 34.771 5.397 34.933 ;
     RECT  4.572 34.933 5.397 34.969 ;
     RECT  6.192 34.861 40.986 34.969 ;
     RECT  4.572 34.969 40.986 34.987 ;
     RECT  61.488 34.795 63.99 35.033 ;
     RECT  2.376 34.771 3.402 35.041 ;
     RECT  56.415 34.889 57.798 35.159 ;
     RECT  61.488 35.033 63.882 35.167 ;
     RECT  0.144 34.939 0.162 35.213 ;
     RECT  42.732 34.781 54.918 35.275 ;
     RECT  58.716 34.925 59.85 35.303 ;
     RECT  4.284 34.987 40.986 35.339 ;
     RECT  2.304 35.041 3.402 35.401 ;
     RECT  4.284 35.339 5.778 35.401 ;
     RECT  58.716 35.303 59.562 35.453 ;
     RECT  6.696 35.339 40.986 35.465 ;
     RECT  42.732 35.275 55.566 35.465 ;
     RECT  58.716 35.453 59.454 35.465 ;
     RECT  61.092 35.167 63.882 35.545 ;
     RECT  42.732 35.465 54.918 35.581 ;
     RECT  6.768 35.465 40.986 35.609 ;
     RECT  42.264 35.581 54.918 35.609 ;
     RECT  2.304 35.401 5.778 35.659 ;
     RECT  6.768 35.609 25.758 35.699 ;
     RECT  2.16 35.659 5.778 35.743 ;
     RECT  42.264 35.609 54.846 35.743 ;
     RECT  58.716 35.465 59.397 35.743 ;
     RECT  56.415 35.159 57.33 35.771 ;
     RECT  26.532 35.609 40.986 35.779 ;
     RECT  41.904 35.743 54.846 35.807 ;
     RECT  1.98 35.743 5.778 35.885 ;
     RECT  60.948 35.545 63.882 35.969 ;
     RECT  41.904 35.807 54.27 36.04 ;
     RECT  41.76 36.04 54.27 36.077 ;
     RECT  26.532 35.779 41.022 36.121 ;
     RECT  2.304 35.885 5.778 36.211 ;
     RECT  6.768 35.699 25.722 36.211 ;
     RECT  56.415 35.771 56.697 36.247 ;
     RECT  2.304 36.211 25.722 36.419 ;
     RECT  56.232 36.247 56.697 36.419 ;
     RECT  60.984 35.969 63.882 36.427 ;
     RECT  6.516 36.419 25.722 36.509 ;
     RECT  60.984 36.427 63.918 36.509 ;
     RECT  58.68 35.743 59.397 36.517 ;
     RECT  6.552 36.509 25.722 36.523 ;
     RECT  26.532 36.121 41.202 36.523 ;
     RECT  56.415 36.419 56.697 36.553 ;
     RECT  0.144 36.571 0.162 36.751 ;
     RECT  55.116 36.619 55.134 36.811 ;
     RECT  6.552 36.523 41.202 36.859 ;
     RECT  42.228 36.077 54.27 36.859 ;
     RECT  55.116 36.811 55.242 36.859 ;
     RECT  56.415 36.553 56.934 36.887 ;
     RECT  42.228 36.859 55.314 36.895 ;
     RECT  58.536 36.517 59.397 36.923 ;
     RECT  42.084 36.895 55.314 36.931 ;
     RECT  42.084 36.931 55.494 36.941 ;
     RECT  0.144 36.751 0.558 37.037 ;
     RECT  6.552 36.859 41.346 37.049 ;
     RECT  0.54 37.037 0.558 37.133 ;
     RECT  56.415 36.887 56.697 37.201 ;
     RECT  57.78 37.093 57.798 37.229 ;
     RECT  2.304 36.419 5.742 37.291 ;
     RECT  42.156 36.941 55.494 37.291 ;
     RECT  56.376 37.201 56.697 37.291 ;
     RECT  2.268 37.291 5.742 37.319 ;
     RECT  61.056 36.509 63.918 37.327 ;
     RECT  41.328 37.049 41.346 37.355 ;
     RECT  58.608 36.923 59.397 37.463 ;
     RECT  4.464 37.319 5.742 37.471 ;
     RECT  6.552 37.049 40.554 37.471 ;
     RECT  60.624 37.327 63.918 37.499 ;
     RECT  2.268 37.319 3.726 37.579 ;
     RECT  2.16 37.579 3.726 37.589 ;
     RECT  4.464 37.471 40.554 37.589 ;
     RECT  42.156 37.291 56.697 37.589 ;
     RECT  6.66 37.589 40.554 37.613 ;
     RECT  6.696 37.613 40.554 37.625 ;
     RECT  42.156 37.589 54.99 37.625 ;
     RECT  58.68 37.463 59.397 37.625 ;
     RECT  55.872 37.589 56.697 37.633 ;
     RECT  2.16 37.589 3.474 37.697 ;
     RECT  42.444 37.625 54.99 37.733 ;
     RECT  60.624 37.499 63.882 37.741 ;
     RECT  2.304 37.697 3.474 37.769 ;
     RECT  2.304 37.769 2.934 37.805 ;
     RECT  2.415 37.805 2.934 37.859 ;
     RECT  42.48 37.733 54.99 37.859 ;
     RECT  60.516 37.741 63.882 37.895 ;
     RECT  6.696 37.625 6.75 37.931 ;
     RECT  41.472 37.669 41.562 38.039 ;
     RECT  60.768 37.895 63.882 38.039 ;
     RECT  60.768 38.039 63.846 38.093 ;
     RECT  7.488 37.625 40.554 38.129 ;
     RECT  41.472 38.039 41.49 38.129 ;
     RECT  55.872 37.633 57.078 38.129 ;
     RECT  7.488 38.129 9.234 38.165 ;
     RECT  60.768 38.093 63.306 38.165 ;
     RECT  7.488 38.165 9.126 38.189 ;
     RECT  9.972 38.129 40.554 38.189 ;
     RECT  55.872 38.129 56.697 38.201 ;
     RECT  42.915 37.859 54.99 38.273 ;
     RECT  60.768 38.165 60.786 38.309 ;
     RECT  4.464 37.589 5.922 38.479 ;
     RECT  7.488 38.189 8.097 38.551 ;
     RECT  9.108 38.189 9.126 38.579 ;
     RECT  41.328 38.173 41.346 38.579 ;
     RECT  42.915 38.273 54.81 38.579 ;
     RECT  58.716 37.625 59.397 38.579 ;
     RECT  4.464 38.479 6.318 38.669 ;
     RECT  7.092 38.551 8.097 38.669 ;
     RECT  10.224 38.189 40.554 38.749 ;
     RECT  10.224 38.749 41.058 38.765 ;
     RECT  10.296 38.765 41.058 38.777 ;
     RECT  10.404 38.777 41.058 38.849 ;
     RECT  61.56 38.165 63.306 38.939 ;
     RECT  42.915 38.579 54.198 38.975 ;
     RECT  61.815 38.939 63.306 39.083 ;
     RECT  10.404 38.849 40.497 39.209 ;
     RECT  10.515 39.209 40.497 39.245 ;
     RECT  10.515 39.245 33.858 39.317 ;
     RECT  42.915 38.975 52.974 39.325 ;
     RECT  4.464 38.669 5.742 39.389 ;
     RECT  42.3 39.325 52.974 39.389 ;
     RECT  10.515 39.317 21.798 39.479 ;
     RECT  61.815 39.083 63.054 39.479 ;
     RECT  22.824 39.317 33.858 39.515 ;
     RECT  42.3 39.389 52.938 39.515 ;
     RECT  63.036 39.479 63.054 39.623 ;
     RECT  5.115 39.389 5.742 39.659 ;
     RECT  22.824 39.515 32.397 39.659 ;
     RECT  42.3 39.515 52.758 39.659 ;
     RECT  22.86 39.659 27.198 39.749 ;
     RECT  42.915 39.659 52.758 39.749 ;
     RECT  10.515 39.479 13.662 39.785 ;
     RECT  28.008 39.659 32.397 39.857 ;
     RECT  13.215 39.785 13.662 39.917 ;
     RECT  34.668 39.245 40.497 39.929 ;
     RECT  11.952 39.785 12.114 40.019 ;
     RECT  14.472 39.479 21.798 40.019 ;
     RECT  33.264 39.515 33.858 40.019 ;
     RECT  11.952 40.019 11.97 40.055 ;
     RECT  33.732 40.019 33.858 40.135 ;
     RECT  34.815 39.929 40.497 40.289 ;
     RECT  42.915 39.749 52.722 40.289 ;
     RECT  34.815 40.289 35.37 40.325 ;
     RECT  42.915 40.289 51.966 40.361 ;
     RECT  52.704 40.289 52.722 40.433 ;
     RECT  15.48 40.019 21.798 40.445 ;
     RECT  38.556 40.289 40.497 40.445 ;
     RECT  15.804 40.445 21.798 40.555 ;
     RECT  22.86 39.749 27.09 40.555 ;
     RECT  15.804 40.555 27.09 40.559 ;
     RECT  36.108 40.289 37.818 40.559 ;
     RECT  15.804 40.559 26.997 40.595 ;
     RECT  28.188 39.857 32.397 40.595 ;
     RECT  39.24 40.445 40.497 40.595 ;
     RECT  42.915 40.361 51.714 40.703 ;
     RECT  15.804 40.595 21.798 40.829 ;
     RECT  26.28 40.595 26.997 40.829 ;
     RECT  30.816 40.595 32.397 40.829 ;
     RECT  42.915 40.703 51.678 40.829 ;
     RECT  15.804 40.829 21.762 40.865 ;
     RECT  42.915 40.829 51.297 40.901 ;
     RECT  36.108 40.559 37.797 41.069 ;
     RECT  22.824 40.595 25.434 41.099 ;
     RECT  31.536 40.829 32.397 41.099 ;
     RECT  33.732 40.135 33.894 41.099 ;
     RECT  50.796 40.901 51.297 41.135 ;
     RECT  31.752 41.099 32.397 41.171 ;
     RECT  42.915 40.901 49.95 41.377 ;
     RECT  22.86 41.099 25.434 41.647 ;
     RECT  26.604 40.829 26.997 41.647 ;
     RECT  36.18 41.069 37.797 41.675 ;
     RECT  22.86 41.647 25.506 41.755 ;
     RECT  26.424 41.647 26.997 41.755 ;
     RECT  42.732 41.377 49.95 41.791 ;
     RECT  42.732 41.791 50.094 41.881 ;
     RECT  51.015 41.135 51.297 41.881 ;
     RECT  53.715 38.975 53.997 41.881 ;
     RECT  15.915 40.865 21.762 41.899 ;
     RECT  42.732 41.881 51.297 41.917 ;
     RECT  42.372 41.917 51.297 41.953 ;
     RECT  42.192 41.953 51.297 41.981 ;
     RECT  39.42 40.595 40.497 41.989 ;
     RECT  38.772 41.989 40.497 42.025 ;
     RECT  15.915 41.899 22.086 42.061 ;
     RECT  22.86 41.755 26.997 42.061 ;
     RECT  38.772 42.025 40.77 42.089 ;
     RECT  39.348 42.089 40.77 42.151 ;
     RECT  39.348 42.151 41.31 42.187 ;
     RECT  42.192 41.981 50.094 42.187 ;
     RECT  15.915 42.061 26.997 42.215 ;
     RECT  28.188 40.595 29.697 42.259 ;
     RECT  28.116 42.259 29.697 42.295 ;
     RECT  27.972 42.295 29.697 42.565 ;
     RECT  36.18 41.675 36.234 42.691 ;
     RECT  36.972 41.675 37.797 42.691 ;
     RECT  34.815 40.325 35.298 42.727 ;
     RECT  36.18 42.691 37.797 42.727 ;
     RECT  15.915 42.215 25.506 42.749 ;
     RECT  39.348 42.187 50.094 42.763 ;
     RECT  27.792 42.565 29.697 42.799 ;
     RECT  27.792 42.799 29.826 42.835 ;
     RECT  17.964 42.749 25.506 43.033 ;
     RECT  26.424 42.215 26.997 43.033 ;
     RECT  27.792 42.835 30.366 43.069 ;
     RECT  17.964 43.033 26.997 43.141 ;
     RECT  27.756 43.069 30.69 43.141 ;
     RECT  39.348 42.763 50.13 43.141 ;
     RECT  39.24 43.141 50.13 43.181 ;
     RECT  17.964 43.141 30.942 43.267 ;
     RECT  31.824 41.171 32.397 43.267 ;
     RECT  39.276 43.181 50.13 43.331 ;
     RECT  17.964 43.267 32.397 43.367 ;
     RECT  15.915 42.749 17.19 43.537 ;
     RECT  17.964 43.367 20.43 43.537 ;
     RECT  15.915 43.537 20.43 43.565 ;
     RECT  34.815 42.727 37.797 43.627 ;
     RECT  39.348 43.331 50.13 43.645 ;
     RECT  34.704 43.627 37.797 43.673 ;
     RECT  17.172 43.565 20.43 43.799 ;
     RECT  21.315 43.367 32.397 43.807 ;
     RECT  2.415 37.859 2.697 43.879 ;
     RECT  6.876 43.843 6.894 43.879 ;
     RECT  33.804 41.099 33.894 43.915 ;
     RECT  5.115 39.659 5.397 43.951 ;
     RECT  6.408 43.879 6.894 43.951 ;
     RECT  21.315 43.807 32.454 43.951 ;
     RECT  33.444 43.915 33.894 43.951 ;
     RECT  17.784 43.799 20.43 43.979 ;
     RECT  0.216 43.951 0.234 44.041 ;
     RECT  2.415 43.879 2.862 44.041 ;
     RECT  5.115 43.951 7.002 44.041 ;
     RECT  17.964 43.979 20.43 44.069 ;
     RECT  0.216 44.041 0.414 44.077 ;
     RECT  17.964 44.069 20.034 44.105 ;
     RECT  4.824 44.041 7.002 44.113 ;
     RECT  53.715 41.881 54.054 44.149 ;
     RECT  0.216 44.077 0.522 44.221 ;
     RECT  7.815 38.669 8.097 44.221 ;
     RECT  2.415 44.041 3.402 44.311 ;
     RECT  18.615 44.105 20.034 44.339 ;
     RECT  2.415 44.311 3.51 44.347 ;
     RECT  4.392 44.113 7.002 44.347 ;
     RECT  39.348 43.645 50.274 44.347 ;
     RECT  18.615 44.339 19.962 44.375 ;
     RECT  18.615 44.375 19.494 44.381 ;
     RECT  2.415 44.347 7.002 44.491 ;
     RECT  7.776 44.221 8.406 44.491 ;
     RECT  2.415 44.491 8.406 44.581 ;
     RECT  39.312 44.347 50.274 44.653 ;
     RECT  2.304 44.581 8.406 44.753 ;
     RECT  0.216 44.221 0.558 44.761 ;
     RECT  9.252 44.581 9.27 44.761 ;
     RECT  38.772 44.653 50.274 44.761 ;
     RECT  51.015 41.981 51.297 44.761 ;
     RECT  9.18 44.761 9.27 44.789 ;
     RECT  38.772 44.761 51.297 44.789 ;
     RECT  21.315 43.951 33.894 44.851 ;
     RECT  39.312 44.789 51.297 44.875 ;
     RECT  53.568 44.149 54.054 44.879 ;
     RECT  56.415 38.201 56.697 44.887 ;
     RECT  39.312 44.875 51.354 44.923 ;
     RECT  21.315 44.851 33.966 44.959 ;
     RECT  34.815 43.673 37.797 44.959 ;
     RECT  56.415 44.887 57.042 44.995 ;
     RECT  2.415 44.753 8.406 45.031 ;
     RECT  9.18 44.789 9.198 45.031 ;
     RECT  21.315 44.959 37.797 45.031 ;
     RECT  39.312 44.923 51.678 45.031 ;
     RECT  53.568 44.879 53.997 45.157 ;
     RECT  56.415 44.995 57.618 45.301 ;
     RECT  55.836 45.301 57.618 45.419 ;
     RECT  59.115 38.579 59.397 45.427 ;
     RECT  18.615 44.381 18.918 45.491 ;
     RECT  39.312 45.031 52.11 45.499 ;
     RECT  53.028 45.157 53.997 45.499 ;
     RECT  58.68 45.427 59.397 45.527 ;
     RECT  2.415 45.031 9.198 45.599 ;
     RECT  39.312 45.499 53.997 45.725 ;
     RECT  21.096 45.031 37.797 45.769 ;
     RECT  39.312 45.725 51.462 45.805 ;
     RECT  20.952 45.769 37.797 45.841 ;
     RECT  2.415 45.599 8.478 45.931 ;
     RECT  2.304 45.931 8.478 45.959 ;
     RECT  20.412 45.841 37.797 46.013 ;
     RECT  4.5 45.959 8.478 46.061 ;
     RECT  2.304 45.959 3.474 46.067 ;
     RECT  9.324 45.841 9.342 46.139 ;
     RECT  18.615 45.491 18.897 46.273 ;
     RECT  2.304 46.067 3.438 46.445 ;
     RECT  38.808 45.805 51.462 46.471 ;
     RECT  18.615 46.273 19.998 46.499 ;
     RECT  56.415 45.419 57.618 46.499 ;
     RECT  38.664 46.471 51.462 46.651 ;
     RECT  52.2 45.725 53.997 46.651 ;
     RECT  18.615 46.499 19.638 46.733 ;
     RECT  4.5 46.061 8.334 46.741 ;
     RECT  58.896 45.527 59.397 46.769 ;
     RECT  20.772 46.013 37.797 46.813 ;
     RECT  20.628 46.813 37.797 46.885 ;
     RECT  38.664 46.651 53.997 46.885 ;
     RECT  60.696 46.615 60.714 46.885 ;
     RECT  4.248 46.741 8.334 46.921 ;
     RECT  18.615 46.733 18.918 46.949 ;
     RECT  13.215 39.917 13.497 47.083 ;
     RECT  56.415 46.499 57.042 47.083 ;
     RECT  61.815 39.479 62.097 47.119 ;
     RECT  20.628 46.885 53.997 47.155 ;
     RECT  4.248 46.921 8.622 47.191 ;
     RECT  13.215 47.083 13.59 47.213 ;
     RECT  14.832 47.083 14.85 47.213 ;
     RECT  61.452 47.119 62.097 47.281 ;
     RECT  4.212 47.191 8.622 47.309 ;
     RECT  7.815 47.309 8.622 47.389 ;
     RECT  15.915 43.565 16.197 47.389 ;
     RECT  20.628 47.155 54.414 47.389 ;
     RECT  56.376 47.083 57.042 47.389 ;
     RECT  7.815 47.389 9.126 47.425 ;
     RECT  55.548 46.795 55.566 47.425 ;
     RECT  56.376 47.389 57.69 47.425 ;
     RECT  2.415 46.445 3.438 47.461 ;
     RECT  4.212 47.309 7.038 47.461 ;
     RECT  7.815 47.425 9.198 47.461 ;
     RECT  60.444 46.885 60.714 47.551 ;
     RECT  61.452 47.281 62.226 47.551 ;
     RECT  2.415 47.461 7.038 47.579 ;
     RECT  60.444 47.551 62.226 47.623 ;
     RECT  59.115 46.769 59.397 47.659 ;
     RECT  60.336 47.623 62.226 47.659 ;
     RECT  59.115 47.659 62.226 47.695 ;
     RECT  7.815 47.461 9.27 47.707 ;
     RECT  55.548 47.425 57.69 47.723 ;
     RECT  20.628 47.389 54.45 47.731 ;
     RECT  55.548 47.723 55.674 47.731 ;
     RECT  7.815 47.707 9.378 47.759 ;
     RECT  59.115 47.695 62.262 47.821 ;
     RECT  6.804 47.579 7.038 47.849 ;
     RECT  56.415 47.723 57.69 47.849 ;
     RECT  0.108 44.761 0.558 47.981 ;
     RECT  10.515 39.785 10.797 48.001 ;
     RECT  58.32 47.929 58.338 48.001 ;
     RECT  59.115 47.821 62.442 48.001 ;
     RECT  7.815 47.759 9.342 48.029 ;
     RECT  56.415 47.849 57.042 48.119 ;
     RECT  6.912 47.849 7.038 48.199 ;
     RECT  18.615 46.949 18.897 48.199 ;
     RECT  63.9 48.001 63.918 48.199 ;
     RECT  10.515 48.001 10.926 48.227 ;
     RECT  58.32 48.001 62.442 48.235 ;
     RECT  63.288 48.199 63.918 48.235 ;
     RECT  20.628 47.731 55.674 48.389 ;
     RECT  58.32 48.235 63.918 48.389 ;
     RECT  38.844 48.389 55.566 48.425 ;
     RECT  20.628 48.389 38.07 48.475 ;
     RECT  2.415 47.579 5.994 48.523 ;
     RECT  6.912 48.199 7.074 48.541 ;
     RECT  7.815 48.029 8.802 48.541 ;
     RECT  38.844 48.425 55.386 48.659 ;
     RECT  6.912 48.541 8.802 48.715 ;
     RECT  64.728 48.763 64.746 48.775 ;
     RECT  2.304 48.523 5.994 48.803 ;
     RECT  64.656 48.775 64.746 48.803 ;
     RECT  4.32 48.803 5.994 48.811 ;
     RECT  6.84 48.715 8.802 48.811 ;
     RECT  64.656 48.803 64.674 48.845 ;
     RECT  58.716 48.389 63.918 48.929 ;
     RECT  4.32 48.811 8.802 48.973 ;
     RECT  2.304 48.803 3.51 48.989 ;
     RECT  4.32 48.973 9.09 49.009 ;
     RECT  0.144 47.981 0.558 49.081 ;
     RECT  56.415 48.119 56.754 49.081 ;
     RECT  0.108 49.081 0.558 49.133 ;
     RECT  20.34 48.475 38.07 49.171 ;
     RECT  38.844 48.659 55.314 49.171 ;
     RECT  0.18 49.133 0.558 49.181 ;
     RECT  60.768 48.929 63.918 49.229 ;
     RECT  4.32 49.009 9.234 49.243 ;
     RECT  20.34 49.171 55.314 49.243 ;
     RECT  56.415 49.081 57.042 49.243 ;
     RECT  60.768 49.229 63.882 49.307 ;
     RECT  58.716 48.929 59.994 49.315 ;
     RECT  4.32 49.243 9.342 49.379 ;
     RECT  18.615 48.199 18.954 49.441 ;
     RECT  6.804 49.379 9.342 49.505 ;
     RECT  58.68 49.315 59.994 49.577 ;
     RECT  56.415 49.243 57.402 49.585 ;
     RECT  56.124 49.585 57.402 49.621 ;
     RECT  58.68 49.577 59.886 49.621 ;
     RECT  56.124 49.621 59.886 49.711 ;
     RECT  20.16 49.243 55.314 49.747 ;
     RECT  56.052 49.711 59.886 49.747 ;
     RECT  18.615 49.441 19.422 49.783 ;
     RECT  6.804 49.505 9.162 49.919 ;
     RECT  6.804 49.919 9.09 50.009 ;
     RECT  18.324 49.783 19.422 50.017 ;
     RECT  20.16 49.747 59.886 50.017 ;
     RECT  18.324 50.017 59.886 50.089 ;
     RECT  18 50.089 59.886 50.093 ;
     RECT  18 50.093 19.422 50.153 ;
     RECT  2.304 48.989 3.474 50.161 ;
     RECT  4.32 49.379 6.03 50.161 ;
     RECT  15.915 47.389 16.83 50.161 ;
     RECT  0.324 49.181 0.558 50.189 ;
     RECT  2.304 50.161 6.03 50.251 ;
     RECT  6.804 50.009 8.514 50.251 ;
     RECT  10.515 48.227 10.797 50.287 ;
     RECT  60.984 49.307 63.882 50.287 ;
     RECT  10.515 50.287 10.818 50.387 ;
     RECT  60.948 50.287 63.882 50.431 ;
     RECT  0.216 50.395 0.234 50.443 ;
     RECT  20.556 50.093 59.886 50.621 ;
     RECT  15.915 50.161 17.118 50.629 ;
     RECT  2.304 50.251 8.514 50.728 ;
     RECT  15.915 50.629 17.19 50.729 ;
     RECT  20.628 50.621 54.99 50.729 ;
     RECT  55.728 50.621 59.886 50.729 ;
     RECT  60.768 50.431 63.918 50.731 ;
     RECT  2.268 50.728 8.514 50.819 ;
     RECT  0.144 50.443 0.234 50.923 ;
     RECT  20.628 50.729 54.918 50.999 ;
     RECT  0.144 50.923 0.414 51.101 ;
     RECT  60.768 50.731 63.954 51.133 ;
     RECT  2.304 50.819 8.514 51.163 ;
     RECT  9.432 50.899 9.45 51.233 ;
     RECT  55.728 50.729 59.742 51.233 ;
     RECT  60.516 51.133 63.954 51.233 ;
     RECT  0.144 51.101 0.342 51.241 ;
     RECT  2.304 51.163 8.586 51.241 ;
     RECT  0.108 51.241 0.342 51.245 ;
     RECT  57.708 51.233 59.742 51.269 ;
     RECT  2.304 51.241 9.162 51.359 ;
     RECT  57.708 51.269 58.158 51.359 ;
     RECT  0.108 51.245 0.198 51.389 ;
     RECT  20.628 50.999 54.882 51.403 ;
     RECT  20.556 51.403 54.882 51.475 ;
     RECT  55.728 51.233 56.79 51.475 ;
     RECT  2.304 51.359 8.622 51.485 ;
     RECT  60.516 51.233 63.882 51.503 ;
     RECT  15.915 50.729 16.83 51.511 ;
     RECT  60.516 51.503 63.45 51.539 ;
     RECT  55.62 51.475 56.79 51.629 ;
     RECT  60.516 51.539 60.606 51.629 ;
     RECT  20.268 51.475 54.882 51.637 ;
     RECT  20.052 51.637 54.882 51.673 ;
     RECT  61.344 51.539 63.45 51.701 ;
     RECT  59.115 51.269 59.742 51.709 ;
     RECT  60.516 51.629 60.534 51.709 ;
     RECT  19.944 51.673 54.882 51.739 ;
     RECT  15.915 51.511 17.19 51.773 ;
     RECT  19.944 51.739 55.278 51.773 ;
     RECT  2.304 51.485 8.586 51.787 ;
     RECT  58.14 51.359 58.158 51.809 ;
     RECT  18 50.153 18.897 51.871 ;
     RECT  19.944 51.773 21.69 51.871 ;
     RECT  15.915 51.773 16.83 51.899 ;
     RECT  18 51.871 21.69 51.907 ;
     RECT  1.764 51.787 8.586 51.979 ;
     RECT  22.464 51.773 55.278 52.007 ;
     RECT  1.728 51.979 8.586 52.169 ;
     RECT  56.415 51.629 56.79 52.177 ;
     RECT  38.628 52.007 55.278 52.205 ;
     RECT  10.515 50.387 10.797 52.219 ;
     RECT  0.108 51.389 0.126 52.249 ;
     RECT  14.832 52.171 14.85 52.249 ;
     RECT  61.416 51.701 63.45 52.267 ;
     RECT  13.215 47.213 13.497 52.312 ;
     RECT  10.515 52.219 10.818 52.349 ;
     RECT  13.104 52.312 13.497 52.349 ;
     RECT  14.832 52.249 14.886 52.349 ;
     RECT  59.115 51.709 60.534 52.447 ;
     RECT  61.416 52.267 63.918 52.447 ;
     RECT  0.108 52.249 0.558 52.493 ;
     RECT  59.115 52.447 63.918 52.583 ;
     RECT  17.64 51.907 21.69 52.591 ;
     RECT  22.464 52.007 37.89 52.591 ;
     RECT  14.868 52.349 14.886 52.619 ;
     RECT  15.915 51.899 16.758 52.651 ;
     RECT  17.568 52.591 37.89 52.651 ;
     RECT  56.415 52.177 58.122 52.709 ;
     RECT  0.108 52.493 0.342 52.781 ;
     RECT  15.915 52.651 37.89 52.877 ;
     RECT  57.42 52.709 58.122 52.951 ;
     RECT  59.115 52.583 63.882 52.979 ;
     RECT  38.772 52.205 55.278 52.987 ;
     RECT  57.42 52.951 58.158 53.015 ;
     RECT  36.864 52.877 37.89 53.035 ;
     RECT  57.564 53.015 58.158 53.059 ;
     RECT  59.115 52.979 60.534 53.059 ;
     RECT  56.415 52.709 56.697 53.095 ;
     RECT  36.864 53.035 37.998 53.221 ;
     RECT  38.736 52.987 55.278 53.221 ;
     RECT  9.36 53.131 9.378 53.249 ;
     RECT  1.728 52.169 8.334 53.365 ;
     RECT  36.864 53.221 55.278 53.365 ;
     RECT  56.052 53.095 56.697 53.365 ;
     RECT  13.215 52.349 13.497 53.659 ;
     RECT  61.452 52.979 63.882 53.663 ;
     RECT  1.728 53.365 8.37 53.761 ;
     RECT  57.564 53.059 60.534 53.789 ;
     RECT  15.915 52.877 36.09 53.797 ;
     RECT  36.864 53.365 56.697 53.797 ;
     RECT  15.915 53.797 56.697 53.825 ;
     RECT  13.215 53.659 13.59 53.837 ;
     RECT  14.724 53.563 14.85 53.885 ;
     RECT  14.832 53.885 14.85 53.905 ;
     RECT  14.832 53.905 14.922 53.933 ;
     RECT  57.564 53.789 57.582 53.969 ;
     RECT  0.108 52.781 0.162 54.125 ;
     RECT  1.728 53.761 8.478 54.125 ;
     RECT  14.904 53.933 14.922 54.131 ;
     RECT  15.915 53.825 41.13 54.139 ;
     RECT  58.644 53.789 60.534 54.211 ;
     RECT  1.728 54.125 8.442 54.329 ;
     RECT  1.728 54.329 8.097 54.473 ;
     RECT  15.768 54.139 41.13 54.509 ;
     RECT  58.644 54.211 60.57 54.571 ;
     RECT  1.728 54.473 4.086 54.599 ;
     RECT  15.768 54.509 36.486 54.599 ;
     RECT  58.644 54.571 60.678 54.635 ;
     RECT  1.728 54.599 4.05 54.707 ;
     RECT  37.44 54.509 41.13 54.715 ;
     RECT  41.904 53.825 56.697 54.715 ;
     RECT  57.528 54.679 57.546 54.715 ;
     RECT  58.716 54.635 60.678 54.715 ;
     RECT  58.716 54.715 60.75 54.841 ;
     RECT  61.56 53.663 63.882 54.841 ;
     RECT  1.728 54.707 3.402 54.869 ;
     RECT  37.44 54.715 57.546 54.869 ;
     RECT  5.004 54.473 8.097 55.049 ;
     RECT  0.108 54.125 0.126 55.139 ;
     RECT  5.004 55.049 6.066 55.181 ;
     RECT  57.528 54.869 57.546 55.283 ;
     RECT  15.915 54.599 36.486 55.381 ;
     RECT  37.44 54.869 56.697 55.417 ;
     RECT  37.404 55.417 56.697 55.445 ;
     RECT  58.716 54.841 63.882 55.453 ;
     RECT  58.68 55.453 63.882 55.525 ;
     RECT  5.004 55.181 5.958 55.553 ;
     RECT  15.915 55.381 36.522 55.687 ;
     RECT  37.404 55.445 37.797 55.687 ;
     RECT  38.556 55.445 56.697 55.831 ;
     RECT  14.868 55.489 14.886 55.859 ;
     RECT  57.78 55.525 63.882 56.011 ;
     RECT  15.915 55.687 37.797 56.065 ;
     RECT  5.115 55.553 5.958 56.129 ;
     RECT  15.876 56.065 37.797 56.129 ;
     RECT  57.78 56.011 63.918 56.129 ;
     RECT  15.876 56.129 36.09 56.347 ;
     RECT  57.78 56.129 63.882 56.363 ;
     RECT  38.556 55.831 57.006 56.371 ;
     RECT  57.78 56.363 59.958 56.371 ;
     RECT  14.94 56.065 14.958 56.381 ;
     RECT  6.876 55.049 8.097 56.399 ;
     RECT  38.556 56.371 59.958 56.641 ;
     RECT  38.52 56.641 59.958 56.669 ;
     RECT  36.972 56.129 37.797 56.725 ;
     RECT  38.52 56.669 57.33 56.725 ;
     RECT  15.804 56.347 36.09 56.759 ;
     RECT  15.804 56.759 30.006 56.795 ;
     RECT  36.972 56.725 57.33 56.795 ;
     RECT  58.068 56.669 59.958 56.831 ;
     RECT  36.972 56.795 57.294 56.867 ;
     RECT  6.876 56.399 6.894 56.939 ;
     RECT  58.536 56.831 59.958 57.145 ;
     RECT  60.84 56.363 61.074 57.145 ;
     RECT  61.815 56.363 63.882 57.173 ;
     RECT  58.536 57.145 61.074 57.181 ;
     RECT  61.815 57.173 63.378 57.181 ;
     RECT  5.115 56.129 5.85 57.299 ;
     RECT  36.972 56.867 56.697 57.299 ;
     RECT  58.536 57.181 63.378 57.335 ;
     RECT  15.915 56.795 29.862 57.371 ;
     RECT  58.536 57.335 59.814 57.371 ;
     RECT  28.908 57.371 29.862 57.443 ;
     RECT  58.608 57.371 59.814 57.443 ;
     RECT  60.984 57.335 63.378 57.443 ;
     RECT  36.972 57.299 54.99 57.569 ;
     RECT  36.972 57.569 38.97 57.581 ;
     RECT  39.78 57.569 54.918 57.641 ;
     RECT  59.115 57.443 59.814 57.641 ;
     RECT  29.088 57.443 29.862 57.643 ;
     RECT  30.78 56.759 36.09 57.643 ;
     RECT  39.78 57.641 54.81 57.677 ;
     RECT  60.984 57.443 63.342 57.713 ;
     RECT  29.088 57.643 36.09 57.811 ;
     RECT  36.972 57.581 38.79 57.811 ;
     RECT  29.088 57.811 38.79 57.839 ;
     RECT  29.088 57.839 38.646 57.875 ;
     RECT  39.852 57.677 54.81 57.875 ;
     RECT  55.872 57.299 56.697 57.875 ;
     RECT  60.984 57.713 62.097 57.911 ;
     RECT  63.324 57.713 63.342 57.983 ;
     RECT  56.415 57.875 56.697 58.081 ;
     RECT  15.915 57.371 28.134 58.123 ;
     RECT  61.128 57.911 62.097 58.145 ;
     RECT  15.915 58.123 28.206 58.387 ;
     RECT  29.088 57.875 38.61 58.387 ;
     RECT  2.415 54.869 3.402 58.649 ;
     RECT  39.852 57.875 54.774 58.765 ;
     RECT  13.215 53.837 13.497 58.801 ;
     RECT  39.528 58.765 54.774 58.829 ;
     RECT  39.528 58.829 41.346 58.955 ;
     RECT  56.415 58.081 57.366 58.955 ;
     RECT  5.115 57.299 5.397 59.071 ;
     RECT  15.915 58.387 38.61 59.071 ;
     RECT  39.528 58.955 41.31 59.071 ;
     RECT  13.104 58.801 13.497 59.099 ;
     RECT  15.336 59.071 41.31 59.117 ;
     RECT  42.3 58.829 54.774 59.611 ;
     RECT  2.415 58.649 2.697 59.809 ;
     RECT  7.815 56.399 8.097 59.881 ;
     RECT  15.915 59.117 41.31 59.971 ;
     RECT  15.876 59.971 41.31 60.035 ;
     RECT  15.876 60.035 19.134 60.071 ;
     RECT  4.896 59.071 5.397 60.115 ;
     RECT  15.876 60.071 19.062 60.128 ;
     RECT  4.896 60.115 5.994 60.241 ;
     RECT  15.552 60.128 19.062 60.277 ;
     RECT  19.872 60.035 41.31 60.305 ;
     RECT  3.852 60.151 3.87 60.349 ;
     RECT  4.86 60.241 5.994 60.349 ;
     RECT  0.468 60.349 0.486 60.385 ;
     RECT  7.815 59.881 8.586 60.421 ;
     RECT  15.516 60.277 19.062 60.421 ;
     RECT  3.852 60.349 5.994 60.511 ;
     RECT  6.732 60.385 6.75 60.511 ;
     RECT  15.444 60.421 19.062 60.511 ;
     RECT  2.415 59.809 3.078 60.56 ;
     RECT  3.852 60.511 6.75 60.56 ;
     RECT  2.415 60.56 6.75 60.619 ;
     RECT  7.632 60.421 8.586 60.619 ;
     RECT  13.215 59.099 13.497 60.619 ;
     RECT  19.908 60.305 41.31 60.655 ;
     RECT  42.048 59.611 54.774 60.655 ;
     RECT  7.632 60.619 9.162 60.691 ;
     RECT  56.415 58.955 56.697 60.691 ;
     RECT  15.372 60.511 19.062 60.715 ;
     RECT  15.192 60.715 19.062 60.781 ;
     RECT  19.908 60.655 54.774 60.851 ;
     RECT  19.908 60.851 43.65 60.953 ;
     RECT  0.468 60.385 0.558 60.961 ;
     RECT  2.304 60.619 6.75 60.961 ;
     RECT  7.56 60.691 9.162 60.961 ;
     RECT  44.46 60.851 54.774 60.961 ;
     RECT  55.98 60.691 56.697 60.961 ;
     RECT  44.46 60.961 56.697 61.079 ;
     RECT  15.084 60.781 19.062 61.087 ;
     RECT  19.908 60.953 43.47 61.087 ;
     RECT  15.012 61.087 43.47 61.115 ;
     RECT  2.304 60.961 9.162 61.123 ;
     RECT  13.104 60.619 13.497 61.223 ;
     RECT  15.012 61.115 28.278 61.231 ;
     RECT  44.46 61.079 54.774 61.349 ;
     RECT  55.98 61.079 56.697 61.349 ;
     RECT  60.156 61.087 60.174 61.349 ;
     RECT  46.764 61.349 54.774 61.385 ;
     RECT  2.304 61.123 9.414 61.393 ;
     RECT  14.976 61.231 28.278 61.393 ;
     RECT  59.115 57.641 59.397 61.393 ;
     RECT  63.288 61.387 63.306 61.393 ;
     RECT  2.304 61.393 9.486 61.421 ;
     RECT  2.415 61.421 9.486 61.529 ;
     RECT  46.764 61.385 54.738 61.529 ;
     RECT  14.796 61.393 28.278 61.663 ;
     RECT  63.288 61.393 63.342 61.675 ;
     RECT  13.215 61.223 13.497 61.771 ;
     RECT  14.688 61.663 28.278 61.861 ;
     RECT  29.052 61.115 43.47 61.861 ;
     RECT  60.48 61.627 60.498 61.889 ;
     RECT  63.288 61.675 63.882 61.961 ;
     RECT  46.98 61.529 54.738 62.033 ;
     RECT  58.716 61.393 59.397 62.033 ;
     RECT  63.864 61.961 63.882 62.033 ;
     RECT  2.415 61.529 9.162 62.069 ;
     RECT  54.72 62.033 54.738 62.069 ;
     RECT  0.108 60.961 0.558 62.093 ;
     RECT  13.215 61.771 13.698 62.167 ;
     RECT  14.688 61.861 43.47 62.167 ;
     RECT  44.46 61.349 45.897 62.167 ;
     RECT  6.66 62.069 9.162 62.195 ;
     RECT  46.98 62.033 53.997 62.195 ;
     RECT  10.515 52.349 10.797 62.275 ;
     RECT  6.66 62.195 9.126 62.285 ;
     RECT  6.66 62.285 8.946 62.303 ;
     RECT  2.415 62.069 5.778 62.311 ;
     RECT  13.215 62.167 43.47 62.311 ;
     RECT  44.46 62.167 46.026 62.311 ;
     RECT  46.98 62.195 46.998 62.339 ;
     RECT  13.215 62.311 46.026 62.401 ;
     RECT  49.752 62.195 53.997 62.465 ;
     RECT  50.148 62.465 52.974 62.573 ;
     RECT  2.412 62.311 5.778 62.581 ;
     RECT  2.304 62.581 5.778 62.609 ;
     RECT  4.464 62.609 5.778 62.699 ;
     RECT  47.916 62.195 48.762 62.699 ;
     RECT  50.796 62.573 52.974 62.699 ;
     RECT  47.916 62.699 48.726 62.735 ;
     RECT  4.5 62.699 5.778 62.851 ;
     RECT  6.66 62.303 8.838 62.851 ;
     RECT  12.78 62.401 46.026 62.851 ;
     RECT  46.8 62.743 46.854 62.851 ;
     RECT  4.5 62.851 8.838 62.879 ;
     RECT  0.396 62.093 0.558 62.957 ;
     RECT  48.096 62.735 48.726 62.969 ;
     RECT  50.796 62.699 51.39 62.969 ;
     RECT  52.2 62.699 52.542 62.969 ;
     RECT  48.096 62.969 48.654 63.005 ;
     RECT  52.2 62.969 52.47 63.005 ;
     RECT  50.796 62.969 51.354 63.041 ;
     RECT  12.78 62.851 46.854 63.077 ;
     RECT  12.78 63.077 44.118 63.121 ;
     RECT  53.715 62.465 53.997 63.121 ;
     RECT  45 63.077 46.854 63.149 ;
     RECT  10.515 62.275 10.926 63.319 ;
     RECT  12.564 63.121 44.118 63.347 ;
     RECT  0.504 62.957 0.558 63.437 ;
     RECT  2.304 62.609 3.726 63.517 ;
     RECT  4.5 62.879 8.694 63.517 ;
     RECT  50.796 63.041 51.297 63.517 ;
     RECT  53.715 63.121 54.45 63.517 ;
     RECT  2.304 63.517 8.694 63.625 ;
     RECT  10.515 63.319 11.034 63.653 ;
     RECT  45 63.149 46.818 63.779 ;
     RECT  2.304 63.625 9.162 63.815 ;
     RECT  2.304 63.815 3.222 63.821 ;
     RECT  50.724 63.517 51.297 63.823 ;
     RECT  52.2 63.005 52.218 63.823 ;
     RECT  4.032 63.815 8.946 63.851 ;
     RECT  13.068 63.347 44.118 63.859 ;
     RECT  45 63.779 45.897 63.859 ;
     RECT  48.096 63.005 48.597 63.859 ;
     RECT  0.54 63.437 0.558 63.883 ;
     RECT  47.556 63.859 48.597 63.895 ;
     RECT  46.764 63.779 46.818 63.931 ;
     RECT  47.556 63.895 48.654 63.931 ;
     RECT  0.54 63.883 0.666 64.013 ;
     RECT  53.715 63.517 54.666 64.057 ;
     RECT  13.068 63.859 45.897 64.093 ;
     RECT  59.115 62.033 59.397 64.093 ;
     RECT  53.715 64.057 54.738 64.129 ;
     RECT  50.724 63.823 52.218 64.319 ;
     RECT  58.32 63.589 58.338 64.327 ;
     RECT  59.115 64.093 59.886 64.327 ;
     RECT  46.764 63.931 48.654 64.355 ;
     RECT  48.315 64.355 48.654 64.471 ;
     RECT  61.815 58.145 62.097 64.471 ;
     RECT  2.304 63.821 2.934 64.561 ;
     RECT  4.032 63.851 8.478 64.561 ;
     RECT  53.46 64.129 54.738 64.597 ;
     RECT  57.564 64.165 57.582 64.597 ;
     RECT  58.32 64.327 59.886 64.597 ;
     RECT  61.776 64.471 62.097 64.597 ;
     RECT  63.864 64.129 63.882 64.597 ;
     RECT  2.304 64.561 8.478 64.603 ;
     RECT  0.108 64.267 0.198 64.604 ;
     RECT  50.724 64.319 51.642 64.669 ;
     RECT  63.864 64.597 63.918 64.685 ;
     RECT  2.304 64.603 8.586 64.733 ;
     RECT  50.616 64.669 51.642 64.741 ;
     RECT  61.776 64.597 62.694 64.741 ;
     RECT  46.764 64.355 47.574 64.769 ;
     RECT  57.564 64.597 59.886 64.769 ;
     RECT  61.776 64.741 62.766 64.831 ;
     RECT  2.304 64.733 2.754 64.843 ;
     RECT  48.315 64.471 49.266 64.859 ;
     RECT  56.415 61.349 56.697 64.903 ;
     RECT  53.46 64.597 54.882 64.939 ;
     RECT  0.144 64.604 0.198 64.987 ;
     RECT  2.16 64.843 2.754 65.003 ;
     RECT  58.248 64.769 59.886 65.011 ;
     RECT  61.596 64.831 62.766 65.011 ;
     RECT  0.144 64.987 0.234 65.039 ;
     RECT  63.864 64.685 63.882 65.069 ;
     RECT  47.556 64.769 47.574 65.129 ;
     RECT  50.544 64.741 51.642 65.129 ;
     RECT  56.415 64.903 57.078 65.129 ;
     RECT  60.876 65.011 62.766 65.129 ;
     RECT  60.876 65.129 60.894 65.165 ;
     RECT  10.515 63.653 10.797 65.209 ;
     RECT  52.848 64.939 54.882 65.209 ;
     RECT  52.848 65.209 55.242 65.213 ;
     RECT  61.815 65.129 62.766 65.227 ;
     RECT  56.415 65.129 56.754 65.245 ;
     RECT  50.652 65.129 51.642 65.273 ;
     RECT  3.564 64.733 8.586 65.281 ;
     RECT  12.744 64.093 45.897 65.281 ;
     RECT  54.72 65.213 55.242 65.309 ;
     RECT  61.815 65.227 62.802 65.323 ;
     RECT  52.848 65.213 53.997 65.371 ;
     RECT  3.564 65.281 8.622 65.399 ;
     RECT  48.315 64.859 48.654 65.399 ;
     RECT  58.248 65.011 60.102 65.399 ;
     RECT  12.744 65.281 46.278 65.543 ;
     RECT  54.72 65.309 54.738 65.543 ;
     RECT  52.74 65.371 53.997 65.551 ;
     RECT  2.304 65.003 2.754 65.641 ;
     RECT  3.564 65.399 8.514 65.641 ;
     RECT  64.656 65.611 64.674 65.641 ;
     RECT  46.728 65.551 46.89 65.669 ;
     RECT  58.248 65.399 59.886 65.669 ;
     RECT  64.656 65.641 64.746 65.669 ;
     RECT  58.248 65.669 58.338 65.677 ;
     RECT  64.728 65.669 64.746 65.693 ;
     RECT  10.515 65.209 10.818 65.749 ;
     RECT  50.724 65.273 51.642 65.749 ;
     RECT  9.432 65.551 9.45 65.785 ;
     RECT  9.36 65.785 9.45 65.813 ;
     RECT  61.815 65.323 63.342 65.813 ;
     RECT  10.515 65.749 10.926 65.821 ;
     RECT  50.724 65.749 51.678 65.849 ;
     RECT  0.144 65.039 0.162 65.933 ;
     RECT  1.152 65.803 1.17 65.981 ;
     RECT  58.212 65.677 58.338 65.983 ;
     RECT  61.815 65.813 62.802 66.019 ;
     RECT  52.452 65.551 53.997 66.047 ;
     RECT  46.728 65.669 46.818 66.083 ;
     RECT  58.14 65.983 58.338 66.083 ;
     RECT  9.36 65.813 9.378 66.119 ;
     RECT  50.724 65.849 51.297 66.119 ;
     RECT  52.452 66.047 52.47 66.119 ;
     RECT  63.864 65.821 63.918 66.125 ;
     RECT  53.676 66.047 53.997 66.209 ;
     RECT  56.268 65.245 56.754 66.209 ;
     RECT  58.14 66.083 58.266 66.209 ;
     RECT  2.304 65.641 8.514 66.217 ;
     RECT  61.596 66.019 62.802 66.253 ;
     RECT  53.715 66.209 53.997 66.325 ;
     RECT  59.115 65.669 59.886 66.325 ;
     RECT  10.515 65.821 10.962 66.389 ;
     RECT  58.14 66.209 58.158 66.389 ;
     RECT  56.415 66.209 56.754 66.479 ;
     RECT  61.56 66.253 62.802 66.479 ;
     RECT  0.18 66.379 0.342 66.509 ;
     RECT  12.744 65.543 45.954 66.595 ;
     RECT  46.728 66.083 46.746 66.595 ;
     RECT  10.515 66.389 10.926 66.623 ;
     RECT  61.815 66.479 62.802 66.667 ;
     RECT  63.864 66.125 63.882 66.667 ;
     RECT  53.715 66.325 54.162 66.721 ;
     RECT  59.115 66.325 59.958 66.749 ;
     RECT  48.315 65.399 48.597 66.793 ;
     RECT  59.115 66.749 59.886 66.845 ;
     RECT  2.304 66.217 9.198 66.857 ;
     RECT  2.376 66.857 9.198 66.865 ;
     RECT  12.708 66.595 46.746 66.901 ;
     RECT  59.115 66.845 59.397 66.901 ;
     RECT  48.315 66.793 49.014 66.929 ;
     RECT  61.815 66.667 63.882 66.929 ;
     RECT  0.18 66.509 0.234 66.955 ;
     RECT  12.708 66.901 46.782 66.991 ;
     RECT  2.376 66.865 9.522 67.019 ;
     RECT  48.315 66.929 48.942 67.019 ;
     RECT  60.84 66.595 60.858 67.019 ;
     RECT  59.04 66.901 59.397 67.027 ;
     RECT  53.715 66.721 54.882 67.051 ;
     RECT  50.004 66.523 50.022 67.063 ;
     RECT  51.015 66.119 51.297 67.063 ;
     RECT  53.064 67.051 54.882 67.127 ;
     RECT  58.716 67.027 59.397 67.127 ;
     RECT  0.144 66.955 0.234 67.133 ;
     RECT  63.864 66.929 63.882 67.135 ;
     RECT  54.864 67.127 54.882 67.171 ;
     RECT  2.376 67.019 9.45 67.199 ;
     RECT  12.564 66.991 46.854 67.261 ;
     RECT  2.376 67.199 8.91 67.277 ;
     RECT  2.376 67.277 6.606 67.289 ;
     RECT  12.42 67.261 46.854 67.325 ;
     RECT  56.415 66.479 56.697 67.333 ;
     RECT  2.415 67.289 6.606 67.361 ;
     RECT  10.515 66.623 10.797 67.369 ;
     RECT  50.004 67.063 51.297 67.369 ;
     RECT  3.564 67.361 6.606 67.469 ;
     RECT  10.515 67.369 10.854 67.469 ;
     RECT  12.708 67.325 46.854 67.531 ;
     RECT  7.38 67.277 8.91 67.559 ;
     RECT  48.315 67.019 48.834 67.567 ;
     RECT  49.968 67.369 51.297 67.603 ;
     RECT  0.216 67.133 0.234 67.631 ;
     RECT  7.668 67.559 8.838 67.631 ;
     RECT  53.064 67.127 53.997 67.639 ;
     RECT  52.92 67.639 53.997 67.661 ;
     RECT  12.708 67.531 46.998 67.675 ;
     RECT  56.415 67.333 57.402 67.675 ;
     RECT  12.708 67.675 47.466 67.711 ;
     RECT  48.312 67.567 48.834 67.711 ;
     RECT  52.92 67.661 52.938 67.711 ;
     RECT  56.415 67.675 57.51 67.711 ;
     RECT  58.788 67.127 59.397 67.711 ;
     RECT  61.815 66.929 62.802 67.723 ;
     RECT  63.864 67.135 63.918 67.723 ;
     RECT  3.564 67.469 6.57 67.739 ;
     RECT  1.152 67.603 1.17 67.829 ;
     RECT  3.564 67.739 6.102 67.829 ;
     RECT  12.708 67.711 48.834 67.829 ;
     RECT  49.932 67.603 51.297 67.829 ;
     RECT  52.848 67.711 52.938 67.829 ;
     RECT  58.788 67.711 59.454 67.837 ;
     RECT  3.564 67.829 5.922 67.865 ;
     RECT  49.932 67.829 49.95 67.865 ;
     RECT  58.788 67.837 59.67 67.867 ;
     RECT  54.864 67.171 55.422 67.873 ;
     RECT  56.415 67.711 57.582 67.873 ;
     RECT  54.864 67.873 55.458 67.915 ;
     RECT  12.708 67.829 48.69 67.937 ;
     RECT  54.864 67.915 55.53 67.981 ;
     RECT  56.415 67.873 58.014 67.981 ;
     RECT  58.788 67.867 60.21 67.981 ;
     RECT  60.984 67.801 61.002 67.981 ;
     RECT  48.315 67.937 48.69 68.009 ;
     RECT  54.72 67.981 55.53 68.071 ;
     RECT  56.415 67.981 61.074 68.071 ;
     RECT  12.708 67.937 47.466 68.099 ;
     RECT  54.72 68.071 61.074 68.135 ;
     RECT  50.724 67.829 51.297 68.143 ;
     RECT  54.792 68.135 61.074 68.243 ;
     RECT  50.724 68.143 51.966 68.279 ;
     RECT  50.832 68.279 51.966 68.369 ;
     RECT  55.296 68.243 60.606 68.369 ;
     RECT  61.815 67.723 63.918 68.377 ;
     RECT  50.832 68.369 51.822 68.405 ;
     RECT  55.296 68.369 57.33 68.405 ;
     RECT  61.452 68.377 63.918 68.639 ;
     RECT  12.708 68.099 47.43 68.791 ;
     RECT  58.284 68.369 60.606 68.819 ;
     RECT  58.284 68.819 60.246 68.945 ;
     RECT  52.848 68.731 52.866 69.061 ;
     RECT  55.296 68.405 56.697 69.061 ;
     RECT  7.815 67.631 8.838 69.089 ;
     RECT  12.636 68.791 47.43 69.151 ;
     RECT  50.868 68.405 51.426 69.151 ;
     RECT  55.224 69.061 56.697 69.151 ;
     RECT  50.688 69.151 51.498 69.187 ;
     RECT  55.188 69.151 56.697 69.187 ;
     RECT  58.788 68.945 60.246 69.215 ;
     RECT  10.515 67.469 10.797 69.259 ;
     RECT  3.564 67.865 5.814 69.287 ;
     RECT  61.815 68.639 63.918 69.293 ;
     RECT  10.515 69.259 10.854 69.295 ;
     RECT  48.315 68.009 48.597 69.295 ;
     RECT  50.58 69.187 51.498 69.295 ;
     RECT  50.508 69.295 51.498 69.331 ;
     RECT  55.116 69.187 56.697 69.331 ;
     RECT  48.315 69.295 49.05 69.449 ;
     RECT  58.824 69.215 60.246 69.485 ;
     RECT  52.848 69.061 52.938 69.493 ;
     RECT  12.636 69.151 47.538 69.521 ;
     RECT  50.436 69.331 51.498 69.521 ;
     RECT  52.776 69.493 52.938 69.533 ;
     RECT  58.896 69.485 60.246 69.533 ;
     RECT  48.315 69.449 48.597 69.565 ;
     RECT  55.116 69.331 56.97 69.565 ;
     RECT  53.715 67.661 53.997 69.601 ;
     RECT  54.756 69.565 56.97 69.601 ;
     RECT  53.028 69.601 53.997 69.719 ;
     RECT  54.72 69.601 56.97 69.719 ;
     RECT  59.115 69.533 60.246 69.727 ;
     RECT  53.715 69.719 53.997 69.799 ;
     RECT  54.72 69.719 56.697 69.799 ;
     RECT  59.115 69.727 60.462 69.799 ;
     RECT  63.288 69.293 63.918 69.827 ;
     RECT  59.115 69.799 60.534 69.961 ;
     RECT  64.656 69.931 64.674 69.961 ;
     RECT  10.515 69.295 11.43 69.989 ;
     RECT  64.656 69.961 64.746 69.989 ;
     RECT  64.728 69.989 64.746 70.013 ;
     RECT  59.115 69.961 60.606 70.061 ;
     RECT  53.715 69.799 56.697 70.169 ;
     RECT  47.556 69.565 48.597 70.259 ;
     RECT  59.115 70.061 60.354 70.301 ;
     RECT  61.815 69.293 62.097 70.315 ;
     RECT  63.288 69.827 63.882 70.315 ;
     RECT  60.336 70.301 60.354 70.331 ;
     RECT  59.115 70.301 59.454 70.339 ;
     RECT  58.788 70.339 59.454 70.411 ;
     RECT  3.852 69.287 5.814 70.439 ;
     RECT  50.724 69.521 51.498 70.439 ;
     RECT  53.715 70.169 54.738 70.529 ;
     RECT  58.716 70.411 59.454 70.529 ;
     RECT  50.904 70.439 51.498 70.537 ;
     RECT  56.088 70.169 56.697 70.565 ;
     RECT  61.815 70.315 63.882 70.565 ;
     RECT  61.815 70.565 63.306 70.589 ;
     RECT  12.636 69.521 46.782 70.601 ;
     RECT  58.86 70.529 59.454 70.637 ;
     RECT  54.72 70.529 54.738 70.673 ;
     RECT  50.904 70.537 51.678 70.709 ;
     RECT  61.815 70.589 62.097 70.771 ;
     RECT  12.636 70.601 45.897 70.829 ;
     RECT  61.308 70.771 62.097 70.907 ;
     RECT  50.904 70.709 51.297 70.943 ;
     RECT  57.924 70.771 57.942 70.943 ;
     RECT  63.288 70.589 63.306 70.943 ;
     RECT  10.515 69.989 10.797 71.041 ;
     RECT  3.852 70.439 5.397 71.069 ;
     RECT  46.764 70.601 46.782 71.105 ;
     RECT  10.515 71.041 10.854 71.249 ;
     RECT  12.708 70.829 45.897 71.491 ;
     RECT  7.815 69.089 8.586 71.519 ;
     RECT  12.708 71.491 46.242 71.609 ;
     RECT  12.708 71.609 22.194 71.645 ;
     RECT  48.315 70.259 48.597 71.707 ;
     RECT  51.015 70.943 51.297 71.725 ;
     RECT  48.315 71.707 48.762 71.761 ;
     RECT  49.644 70.951 49.662 71.761 ;
     RECT  23.148 71.609 46.242 71.851 ;
     RECT  23.148 71.851 46.782 71.915 ;
     RECT  29.016 71.915 46.782 71.959 ;
     RECT  48.315 71.761 49.698 71.959 ;
     RECT  50.904 71.725 51.297 71.959 ;
     RECT  29.016 71.959 47.502 71.995 ;
     RECT  48.315 71.959 51.822 71.995 ;
     RECT  10.515 71.249 10.797 72.121 ;
     RECT  4.464 71.069 5.397 72.149 ;
     RECT  12.708 71.645 21.69 72.185 ;
     RECT  10.515 72.121 10.854 72.329 ;
     RECT  12.708 72.185 19.638 72.419 ;
     RECT  20.484 72.185 21.69 72.455 ;
     RECT  23.148 71.915 28.206 72.535 ;
     RECT  12.708 72.419 19.602 72.571 ;
     RECT  20.52 72.455 21.69 72.571 ;
     RECT  6.516 72.619 6.822 72.661 ;
     RECT  12.384 72.571 19.602 72.697 ;
     RECT  22.824 72.535 28.206 72.841 ;
     RECT  29.016 71.995 51.822 72.841 ;
     RECT  20.52 72.571 22.05 72.955 ;
     RECT  22.824 72.841 51.822 72.955 ;
     RECT  20.52 72.955 51.822 72.959 ;
     RECT  12.24 72.697 19.602 72.989 ;
     RECT  20.664 72.959 51.822 72.995 ;
     RECT  2.415 67.361 2.697 73.039 ;
     RECT  7.815 71.519 8.097 73.039 ;
     RECT  0.504 73.039 0.522 73.111 ;
     RECT  4.68 72.149 5.397 73.201 ;
     RECT  6.3 72.661 6.822 73.201 ;
     RECT  20.664 72.995 21.978 73.229 ;
     RECT  0.504 73.111 0.558 73.243 ;
     RECT  2.415 73.039 2.934 73.291 ;
     RECT  4.68 73.201 6.822 73.291 ;
     RECT  2.304 73.291 3.474 73.309 ;
     RECT  4.536 73.291 6.822 73.309 ;
     RECT  2.304 73.309 6.822 73.345 ;
     RECT  7.596 73.039 8.097 73.345 ;
     RECT  12.744 72.989 19.602 73.345 ;
     RECT  9.144 73.243 9.162 73.381 ;
     RECT  2.304 73.345 8.097 73.499 ;
     RECT  0.144 73.243 0.558 73.517 ;
     RECT  23.004 72.995 51.822 73.571 ;
     RECT  9.144 73.381 9.198 73.651 ;
     RECT  3.996 73.499 8.097 73.769 ;
     RECT  6.768 73.769 8.097 73.777 ;
     RECT  0.504 73.517 0.558 73.805 ;
     RECT  12.744 73.345 19.674 73.849 ;
     RECT  12.708 73.849 19.674 73.885 ;
     RECT  3.996 73.769 5.778 73.901 ;
     RECT  9.144 73.651 9.27 73.921 ;
     RECT  6.768 73.777 8.226 74.047 ;
     RECT  23.004 73.571 39.078 74.119 ;
     RECT  0.54 73.805 0.558 74.155 ;
     RECT  0.54 74.155 0.666 74.189 ;
     RECT  2.304 73.499 3.114 74.281 ;
     RECT  9.072 73.921 9.27 74.281 ;
     RECT  20.844 73.229 21.978 74.281 ;
     RECT  22.968 74.119 39.078 74.281 ;
     RECT  0.648 74.189 0.666 74.285 ;
     RECT  12.708 73.885 19.926 74.317 ;
     RECT  20.7 74.281 39.078 74.353 ;
     RECT  39.996 73.571 51.822 74.353 ;
     RECT  12.708 74.317 19.962 74.389 ;
     RECT  20.7 74.353 51.822 74.389 ;
     RECT  6.768 74.047 8.298 74.425 ;
     RECT  9.072 74.281 9.378 74.425 ;
     RECT  6.768 74.425 9.378 74.489 ;
     RECT  4.32 73.901 5.778 74.551 ;
     RECT  6.768 74.489 9.198 74.551 ;
     RECT  12.708 74.389 51.822 74.551 ;
     RECT  56.415 70.565 56.697 74.587 ;
     RECT  2.304 74.281 3.474 74.635 ;
     RECT  2.196 74.635 3.474 74.722 ;
     RECT  2.16 74.722 3.474 74.821 ;
     RECT  4.32 74.551 9.198 74.821 ;
     RECT  12.456 74.551 51.822 74.821 ;
     RECT  4.248 74.821 9.198 74.849 ;
     RECT  12.456 74.821 52.326 74.885 ;
     RECT  2.016 74.821 3.474 74.929 ;
     RECT  4.248 74.849 5.994 74.929 ;
     RECT  53.715 70.529 53.997 75.001 ;
     RECT  56.016 74.587 56.697 75.001 ;
     RECT  13.104 74.885 52.326 75.091 ;
     RECT  13.104 75.091 52.866 75.119 ;
     RECT  14.256 75.119 52.866 75.163 ;
     RECT  53.604 75.001 54.054 75.163 ;
     RECT  13.176 75.119 13.497 75.191 ;
     RECT  2.016 74.929 5.994 75.197 ;
     RECT  54.864 75.091 55.278 75.235 ;
     RECT  56.016 75.001 57.33 75.235 ;
     RECT  6.768 74.849 9.198 75.271 ;
     RECT  14.256 75.163 54.054 75.271 ;
     RECT  54.864 75.235 57.33 75.271 ;
     RECT  58.356 75.115 58.374 75.271 ;
     RECT  59.115 70.637 59.397 75.271 ;
     RECT  58.284 75.271 59.454 75.361 ;
     RECT  6.768 75.271 9.27 75.389 ;
     RECT  14.256 75.271 57.33 75.397 ;
     RECT  11.988 75.451 12.006 75.497 ;
     RECT  7.815 75.389 9.27 75.533 ;
     RECT  14.256 75.397 57.474 75.541 ;
     RECT  9 75.533 9.27 75.659 ;
     RECT  58.284 75.361 59.562 75.659 ;
     RECT  14.256 75.541 57.546 75.667 ;
     RECT  58.284 75.659 59.454 75.667 ;
     RECT  14.256 75.667 59.454 75.773 ;
     RECT  2.304 75.197 5.994 75.803 ;
     RECT  59.115 75.773 59.454 75.803 ;
     RECT  5.115 75.803 5.994 75.811 ;
     RECT  6.768 75.389 6.966 75.811 ;
     RECT  0.18 75.739 0.198 75.964 ;
     RECT  13.215 75.191 13.497 75.973 ;
     RECT  14.256 75.773 58.374 75.973 ;
     RECT  5.115 75.811 6.966 76.171 ;
     RECT  5.115 76.171 7.038 76.207 ;
     RECT  7.815 75.533 8.154 76.207 ;
     RECT  0.108 75.964 0.198 76.253 ;
     RECT  2.304 75.803 4.194 76.307 ;
     RECT  9.036 75.659 9.27 76.343 ;
     RECT  5.115 76.207 8.154 76.349 ;
     RECT  5.115 76.349 6.714 76.379 ;
     RECT  9.036 76.343 9.09 76.379 ;
     RECT  2.415 76.307 4.194 76.397 ;
     RECT  5.115 76.379 6.642 76.505 ;
     RECT  13.215 75.973 58.374 76.513 ;
     RECT  59.115 75.803 59.397 76.513 ;
     RECT  0.108 76.253 0.126 76.577 ;
     RECT  4.176 76.397 4.194 76.585 ;
     RECT  5.115 76.505 5.562 76.585 ;
     RECT  4.176 76.585 5.562 76.637 ;
     RECT  6.516 76.505 6.642 76.649 ;
     RECT  4.176 76.637 4.194 76.739 ;
     RECT  5.115 76.637 5.562 76.739 ;
     RECT  13.215 76.513 59.397 76.747 ;
     RECT  13.215 76.747 59.778 76.783 ;
     RECT  2.415 76.397 3.114 76.811 ;
     RECT  6.624 76.649 6.642 76.811 ;
     RECT  9.072 76.379 9.09 77.009 ;
     RECT  13.215 76.783 60.03 77.009 ;
     RECT  7.815 76.349 8.154 77.069 ;
     RECT  10.515 72.329 10.797 77.089 ;
     RECT  14.256 77.009 60.03 77.161 ;
     RECT  10.515 77.089 10.926 77.189 ;
     RECT  61.815 70.907 62.097 77.323 ;
     RECT  14.256 77.161 60.39 77.593 ;
     RECT  61.596 77.323 62.097 77.593 ;
     RECT  14.256 77.593 60.426 77.629 ;
     RECT  61.596 77.593 62.37 77.629 ;
     RECT  14.256 77.629 62.37 77.707 ;
     RECT  63.864 77.515 63.882 77.803 ;
     RECT  14.256 77.707 62.73 77.963 ;
     RECT  14.292 77.963 62.73 78.089 ;
     RECT  14.94 78.089 62.73 78.169 ;
     RECT  63.756 77.803 63.882 78.169 ;
     RECT  14.94 78.169 63.882 78.241 ;
     RECT  14.94 78.241 63.918 78.286 ;
     RECT  14.94 78.286 63.954 78.395 ;
     RECT  15.372 78.395 30.294 78.629 ;
     RECT  6.732 78.511 6.75 78.955 ;
     RECT  5.115 76.739 5.397 79.003 ;
     RECT  2.415 76.811 2.697 79.015 ;
     RECT  3.528 77.125 3.546 79.015 ;
     RECT  31.032 78.395 63.954 79.037 ;
     RECT  4.752 79.003 5.397 79.051 ;
     RECT  6.156 78.955 6.75 79.051 ;
     RECT  4.752 79.051 6.75 79.141 ;
     RECT  4.752 79.141 6.858 79.213 ;
     RECT  7.815 77.069 8.097 79.213 ;
     RECT  15.915 78.629 30.294 79.213 ;
     RECT  31.032 79.037 35.946 79.213 ;
     RECT  15.915 79.213 35.946 79.241 ;
     RECT  15.915 79.241 17.118 79.277 ;
     RECT  0.036 79.321 0.054 79.447 ;
     RECT  0.036 79.447 0.378 79.483 ;
     RECT  4.752 79.213 8.097 79.483 ;
     RECT  14.868 79.447 14.886 79.483 ;
     RECT  0.036 79.483 0.522 79.519 ;
     RECT  9.072 79.321 9.09 79.531 ;
     RECT  13.215 77.009 13.497 79.579 ;
     RECT  14.832 79.483 14.958 79.613 ;
     RECT  2.415 79.015 3.546 79.681 ;
     RECT  4.608 79.483 8.097 79.723 ;
     RECT  9.072 79.531 9.126 79.723 ;
     RECT  4.608 79.723 9.126 79.753 ;
     RECT  13.215 79.579 13.59 79.757 ;
     RECT  14.832 79.613 14.85 79.757 ;
     RECT  2.415 79.681 3.618 79.825 ;
     RECT  4.392 79.753 9.126 79.825 ;
     RECT  17.1 79.277 17.118 79.963 ;
     RECT  17.892 79.241 35.946 79.963 ;
     RECT  17.1 79.963 35.946 79.987 ;
     RECT  36.684 79.037 63.954 79.987 ;
     RECT  17.1 79.987 63.954 80.285 ;
     RECT  2.304 79.825 9.126 80.365 ;
     RECT  36.54 80.285 63.954 80.381 ;
     RECT  2.304 80.365 9.27 80.401 ;
     RECT  17.1 80.285 35.766 80.519 ;
     RECT  52.452 80.381 63.954 80.525 ;
     RECT  2.304 80.401 9.342 80.555 ;
     RECT  17.172 80.519 35.766 80.627 ;
     RECT  36.54 80.381 51.354 80.627 ;
     RECT  14.832 80.599 14.85 80.671 ;
     RECT  52.452 80.525 63.882 80.699 ;
     RECT  17.748 80.627 35.766 80.789 ;
     RECT  36.684 80.627 51.354 80.861 ;
     RECT  14.832 80.671 14.922 80.897 ;
     RECT  52.488 80.699 63.882 80.909 ;
     RECT  10.515 77.189 10.797 80.941 ;
     RECT  17.856 80.789 35.766 81.031 ;
     RECT  10.515 80.941 10.926 81.059 ;
     RECT  2.304 80.555 9.234 81.167 ;
     RECT  0.036 79.519 0.558 81.197 ;
     RECT  17.856 81.031 35.91 81.389 ;
     RECT  36.936 80.861 51.354 81.445 ;
     RECT  52.488 80.909 63.558 81.445 ;
     RECT  36.936 81.445 63.558 81.485 ;
     RECT  2.34 81.167 9.234 81.599 ;
     RECT  17.892 81.389 35.91 81.751 ;
     RECT  36.936 81.485 51.57 81.751 ;
     RECT  10.515 81.059 10.797 81.841 ;
     RECT  9.36 81.607 9.378 81.976 ;
     RECT  2.34 81.599 8.586 81.977 ;
     RECT  10.515 81.841 10.926 81.977 ;
     RECT  0.036 81.197 0.522 81.979 ;
     RECT  9.36 81.976 9.45 82.013 ;
     RECT  0.036 81.979 0.558 82.049 ;
     RECT  9.36 82.013 9.378 82.049 ;
     RECT  0.036 82.049 0.486 82.061 ;
     RECT  52.416 81.485 63.558 82.123 ;
     RECT  17.892 81.751 51.57 82.255 ;
     RECT  14.832 80.897 14.85 82.283 ;
     RECT  17.892 82.255 51.678 82.381 ;
     RECT  52.416 82.123 63.774 82.525 ;
     RECT  17.676 82.381 51.678 82.538 ;
     RECT  52.416 82.525 63.918 82.538 ;
     RECT  64.728 82.555 64.746 82.6 ;
     RECT  0.036 82.061 0.45 82.679 ;
     RECT  2.34 81.977 8.37 82.723 ;
     RECT  0.108 82.679 0.45 82.831 ;
     RECT  17.676 82.538 63.918 82.831 ;
     RECT  9.36 82.831 9.378 82.949 ;
     RECT  17.172 82.831 63.918 82.949 ;
     RECT  64.656 82.6 64.746 82.949 ;
     RECT  64.728 82.949 64.746 82.973 ;
     RECT  17.172 82.949 51.858 82.993 ;
     RECT  17.1 82.993 51.858 83.093 ;
     RECT  2.34 82.723 8.514 83.101 ;
     RECT  2.304 83.101 8.514 83.213 ;
     RECT  52.596 82.949 63.918 83.213 ;
     RECT  17.532 83.093 51.858 83.219 ;
     RECT  2.415 83.213 8.514 83.299 ;
     RECT  2.415 83.299 9.054 83.399 ;
     RECT  2.415 83.399 8.982 83.489 ;
     RECT  10.515 81.977 10.797 83.569 ;
     RECT  52.596 83.213 62.802 83.597 ;
     RECT  63.756 83.213 63.918 83.605 ;
     RECT  10.515 83.569 10.926 83.641 ;
     RECT  14.904 83.371 14.922 83.641 ;
     RECT  14.832 83.641 14.922 83.669 ;
     RECT  10.515 83.641 10.998 83.759 ;
     RECT  14.832 83.669 14.85 83.759 ;
     RECT  2.415 83.489 8.766 83.795 ;
     RECT  17.532 83.219 51.75 83.839 ;
     RECT  17.1 83.839 51.75 83.939 ;
     RECT  17.172 83.939 51.75 84.001 ;
     RECT  63.756 83.605 63.99 84.077 ;
     RECT  10.515 83.759 10.818 84.137 ;
     RECT  0.108 82.831 0.558 84.173 ;
     RECT  4.212 83.795 8.766 84.173 ;
     RECT  52.812 83.597 62.802 84.235 ;
     RECT  63.756 84.077 63.918 84.235 ;
     RECT  0.324 84.173 0.558 84.269 ;
     RECT  2.415 83.795 3.438 84.569 ;
     RECT  4.212 84.173 8.262 84.569 ;
     RECT  0.468 84.269 0.558 84.571 ;
     RECT  17.172 84.001 52.074 84.577 ;
     RECT  52.812 84.235 63.918 84.577 ;
     RECT  2.415 84.569 3.294 84.605 ;
     RECT  0.468 84.571 0.594 84.641 ;
     RECT  2.415 84.605 3.258 84.649 ;
     RECT  0.468 84.641 0.522 84.653 ;
     RECT  17.172 84.577 63.918 84.721 ;
     RECT  17.1 84.721 63.918 84.839 ;
     RECT  2.268 84.649 3.258 84.845 ;
     RECT  17.1 84.839 17.118 84.911 ;
     RECT  0.468 84.653 0.486 85.037 ;
     RECT  4.356 84.569 8.262 85.081 ;
     RECT  18.288 84.839 63.918 85.133 ;
     RECT  14.976 84.955 14.994 85.189 ;
     RECT  14.904 85.189 14.994 85.217 ;
     RECT  14.904 85.217 14.922 85.261 ;
     RECT  14.832 85.261 14.922 85.289 ;
     RECT  14.832 85.289 14.886 85.379 ;
     RECT  18.288 85.133 63.882 85.451 ;
     RECT  4.356 85.081 8.478 85.525 ;
     RECT  18.288 85.451 51.57 85.657 ;
     RECT  4.32 85.525 8.478 85.693 ;
     RECT  18.18 85.657 51.57 85.709 ;
     RECT  52.344 85.451 63.882 85.793 ;
     RECT  4.32 85.693 8.622 85.801 ;
     RECT  14.868 85.379 14.886 85.829 ;
     RECT  2.304 84.845 3.258 85.867 ;
     RECT  1.98 85.867 3.258 85.891 ;
     RECT  4.248 85.801 8.622 85.891 ;
     RECT  1.98 85.891 3.438 85.915 ;
     RECT  4.248 85.891 8.91 85.915 ;
     RECT  18.324 85.709 51.57 85.919 ;
     RECT  1.98 85.915 8.91 85.949 ;
     RECT  1.98 85.949 8.442 86.045 ;
     RECT  0.504 85.423 0.558 86.093 ;
     RECT  0.504 86.093 0.522 86.189 ;
     RECT  10.515 84.137 10.797 86.341 ;
     RECT  52.344 85.793 62.874 86.369 ;
     RECT  2.268 86.045 8.442 86.459 ;
     RECT  52.452 86.369 62.874 86.539 ;
     RECT  63.864 85.793 63.882 86.539 ;
     RECT  2.268 86.459 3.078 86.639 ;
     RECT  3.996 86.459 8.442 86.639 ;
     RECT  4.32 86.639 8.442 86.731 ;
     RECT  9.432 86.341 9.45 86.731 ;
     RECT  10.515 86.341 10.854 86.779 ;
     RECT  18.615 85.919 51.57 86.809 ;
     RECT  52.452 86.539 63.882 86.873 ;
     RECT  10.515 86.779 10.89 86.909 ;
     RECT  52.452 86.873 62.766 87.035 ;
     RECT  10.515 86.909 10.818 87.053 ;
     RECT  0.144 86.635 0.162 87.101 ;
     RECT  18.615 86.809 51.678 87.179 ;
     RECT  18.615 87.179 51.606 87.211 ;
     RECT  2.304 86.639 3.078 87.241 ;
     RECT  18.576 87.211 51.606 87.269 ;
     RECT  63.864 86.873 63.882 87.277 ;
     RECT  4.32 86.731 9.45 87.421 ;
     RECT  2.304 87.241 3.438 87.511 ;
     RECT  4.176 87.421 9.45 87.511 ;
     RECT  14.832 86.779 14.85 87.647 ;
     RECT  53.352 87.035 62.766 87.655 ;
     RECT  63.864 87.277 63.954 87.655 ;
     RECT  52.452 87.035 52.542 87.781 ;
     RECT  53.352 87.655 63.954 87.781 ;
     RECT  52.452 87.781 63.954 87.817 ;
     RECT  2.304 87.511 9.45 87.881 ;
     RECT  17.136 87.781 17.226 87.926 ;
     RECT  9.432 87.881 9.45 87.953 ;
     RECT  17.136 87.926 17.19 87.961 ;
     RECT  52.416 87.817 63.954 87.961 ;
     RECT  64.728 87.931 64.746 87.961 ;
     RECT  1.152 87.835 1.17 87.965 ;
     RECT  17.1 87.961 17.19 88.151 ;
     RECT  2.304 87.881 8.658 88.259 ;
     RECT  52.416 87.961 64.746 88.259 ;
     RECT  52.416 88.259 64.674 88.301 ;
     RECT  18.615 87.269 51.606 88.321 ;
     RECT  52.416 88.301 63.99 88.321 ;
     RECT  0.144 87.931 0.162 88.357 ;
     RECT  18.615 88.321 63.99 88.397 ;
     RECT  18.615 88.397 63.882 88.493 ;
     RECT  2.376 88.259 8.658 88.699 ;
     RECT  2.376 88.699 8.838 88.888 ;
     RECT  2.376 88.888 9.234 88.925 ;
     RECT  2.376 88.925 8.658 88.931 ;
     RECT  0.144 88.357 0.558 88.973 ;
     RECT  2.376 88.931 6.858 89.131 ;
     RECT  10.515 87.053 10.797 89.131 ;
     RECT  13.215 79.757 13.497 89.131 ;
     RECT  7.632 88.931 8.658 89.159 ;
     RECT  13.104 89.131 13.497 89.168 ;
     RECT  18.615 88.493 62.874 89.213 ;
     RECT  10.515 89.131 10.818 89.261 ;
     RECT  17.1 88.151 17.118 89.311 ;
     RECT  63.864 88.493 63.882 89.311 ;
     RECT  63.864 89.311 63.918 89.357 ;
     RECT  0.144 88.973 0.162 89.501 ;
     RECT  20.448 89.213 62.874 89.515 ;
     RECT  63.864 89.357 63.882 89.515 ;
     RECT  2.304 89.131 6.858 89.707 ;
     RECT  7.632 89.159 8.586 89.707 ;
     RECT  2.304 89.707 8.586 89.741 ;
     RECT  1.26 89.419 1.278 89.803 ;
     RECT  2.304 89.741 8.514 89.803 ;
     RECT  17.1 89.311 17.19 89.843 ;
     RECT  17.1 89.843 17.118 89.879 ;
     RECT  18.615 89.213 19.278 89.969 ;
     RECT  20.448 89.515 63.882 90.049 ;
     RECT  20.196 90.049 63.882 90.211 ;
     RECT  64.656 90.187 64.674 90.211 ;
     RECT  64.656 90.211 64.746 90.269 ;
     RECT  0.324 90.187 0.342 90.317 ;
     RECT  20.088 90.211 63.882 90.355 ;
     RECT  14.832 89.131 14.85 90.413 ;
     RECT  1.26 89.803 8.514 90.481 ;
     RECT  1.26 90.481 8.586 90.751 ;
     RECT  9.396 90.661 9.414 90.751 ;
     RECT  18.615 89.969 19.026 90.859 ;
     RECT  18.615 90.859 19.098 90.895 ;
     RECT  19.944 90.355 63.882 90.895 ;
     RECT  18.615 90.895 19.17 91.049 ;
     RECT  19.944 90.895 63.918 91.085 ;
     RECT  0.144 90.667 0.234 91.243 ;
     RECT  19.944 91.085 63.882 91.319 ;
     RECT  19.944 91.319 19.962 91.355 ;
     RECT  20.916 91.319 63.882 91.355 ;
     RECT  0.144 91.243 0.342 91.399 ;
     RECT  1.26 90.751 9.414 91.499 ;
     RECT  17.1 91.363 17.118 91.499 ;
     RECT  1.44 91.499 9.414 91.561 ;
     RECT  1.44 91.561 9.45 91.741 ;
     RECT  21.096 91.355 63.882 91.769 ;
     RECT  21.315 91.769 63.882 91.819 ;
     RECT  21.315 91.819 63.918 91.895 ;
     RECT  22.356 91.895 63.918 91.915 ;
     RECT  64.656 90.269 64.674 91.915 ;
     RECT  22.356 91.915 64.674 91.931 ;
     RECT  22.356 91.931 30.51 91.997 ;
     RECT  1.44 91.741 9.666 92.129 ;
     RECT  22.392 91.997 30.51 92.201 ;
     RECT  0.108 91.399 0.342 92.237 ;
     RECT  19.944 92.245 19.962 92.285 ;
     RECT  0.18 92.237 0.27 92.309 ;
     RECT  0.18 92.309 0.234 92.333 ;
     RECT  22.392 92.201 30.474 92.471 ;
     RECT  1.44 92.129 9.162 92.579 ;
     RECT  1.98 92.579 9.162 92.669 ;
     RECT  9.144 92.669 9.162 92.741 ;
     RECT  1.98 92.669 8.298 92.765 ;
     RECT  1.98 92.765 8.154 92.849 ;
     RECT  4.032 92.849 8.154 92.975 ;
     RECT  1.98 92.849 3.294 93.047 ;
     RECT  4.392 92.975 8.154 93.047 ;
     RECT  18.615 91.049 18.897 93.091 ;
     RECT  21.315 91.895 21.597 93.091 ;
     RECT  22.392 92.471 30.258 93.091 ;
     RECT  0.216 92.333 0.234 93.119 ;
     RECT  2.34 93.047 3.294 93.209 ;
     RECT  4.536 93.047 8.154 93.209 ;
     RECT  2.415 93.209 3.15 93.281 ;
     RECT  4.536 93.209 5.397 93.317 ;
     RECT  6.192 93.209 7.038 93.317 ;
     RECT  18.615 93.091 18.954 93.317 ;
     RECT  21.315 93.091 30.258 93.355 ;
     RECT  31.248 91.931 64.674 93.355 ;
     RECT  5.04 93.317 5.397 93.389 ;
     RECT  6.192 93.317 7.002 93.389 ;
     RECT  7.815 93.209 8.154 93.389 ;
     RECT  6.192 93.389 6.21 93.479 ;
     RECT  6.984 93.389 7.002 93.479 ;
     RECT  21.315 93.355 64.674 93.485 ;
     RECT  22.392 93.485 64.674 94.325 ;
     RECT  22.536 94.325 64.674 94.559 ;
     RECT  22.86 94.559 64.674 94.703 ;
     RECT  23.256 94.703 35.334 94.829 ;
     RECT  36.324 94.703 64.674 94.865 ;
     RECT  57.96 94.865 58.23 94.937 ;
     RECT  36.324 94.865 57.186 95.009 ;
     RECT  57.96 94.937 57.978 95.009 ;
     RECT  59.115 94.865 64.674 95.009 ;
     RECT  23.292 94.829 35.334 95.099 ;
     RECT  36.324 95.009 56.862 95.171 ;
     RECT  61.164 95.009 64.674 95.171 ;
     RECT  29.34 95.099 35.334 95.369 ;
     RECT  23.292 95.099 28.566 95.405 ;
     RECT  23.436 95.405 28.566 95.441 ;
     RECT  44.748 95.171 56.862 95.441 ;
     RECT  36.324 95.171 43.866 95.477 ;
     RECT  30.816 95.369 35.334 95.485 ;
     RECT  36.324 95.477 36.666 95.485 ;
     RECT  28.548 95.441 28.566 95.513 ;
     RECT  55.224 95.441 56.862 95.513 ;
     RECT  59.115 95.009 60.39 95.513 ;
     RECT  61.164 95.171 63.558 95.513 ;
     RECT  44.748 95.441 54.45 95.549 ;
     RECT  55.296 95.513 56.862 95.549 ;
     RECT  59.115 95.513 59.886 95.549 ;
     RECT  61.164 95.513 62.334 95.639 ;
     RECT  55.404 95.549 56.862 95.747 ;
     RECT  64.656 95.171 64.674 95.747 ;
     RECT  23.436 95.441 27.666 95.819 ;
     RECT  61.164 95.639 62.262 95.819 ;
     RECT  61.164 95.819 62.097 95.909 ;
     RECT  30.816 95.485 36.666 95.945 ;
     RECT  37.476 95.477 43.866 95.945 ;
     RECT  45.072 95.549 54.45 95.945 ;
     RECT  23.436 95.819 25.938 96.017 ;
     RECT  39.852 95.945 41.346 96.053 ;
     RECT  63.54 95.513 63.558 96.053 ;
     RECT  45.072 95.945 49.662 96.089 ;
     RECT  23.436 96.017 25.866 96.179 ;
     RECT  31.176 95.945 36.666 96.179 ;
     RECT  37.476 95.945 39.114 96.179 ;
     RECT  42.156 95.945 43.866 96.179 ;
     RECT  50.472 95.945 54.45 96.179 ;
     RECT  55.404 95.747 56.697 96.179 ;
     RECT  23.436 96.179 25.218 96.215 ;
     RECT  31.176 96.179 35.226 96.215 ;
     RECT  36.144 96.179 36.666 96.215 ;
     RECT  45.072 96.089 49.554 96.215 ;
     RECT  50.904 96.179 51.297 96.215 ;
     RECT  52.416 96.179 54.45 96.215 ;
     RECT  25.2 96.215 25.218 96.221 ;
     RECT  42.552 96.179 43.866 96.251 ;
     RECT  42.588 96.251 43.866 96.287 ;
     RECT  42.588 96.287 43.794 96.323 ;
     RECT  31.248 96.215 32.397 96.449 ;
     RECT  33.768 96.215 35.226 96.449 ;
     RECT  36.324 96.215 36.666 96.449 ;
     RECT  37.476 96.179 37.854 96.449 ;
     RECT  40.215 96.053 41.346 96.449 ;
     RECT  42.915 96.323 43.794 96.449 ;
     RECT  45.072 96.215 47.142 96.449 ;
     RECT  47.988 96.215 49.554 96.449 ;
     RECT  52.416 96.215 54.414 96.449 ;
     RECT  33.768 96.449 33.786 96.485 ;
     RECT  42.915 96.449 43.686 96.485 ;
     RECT  45.072 96.449 46.782 96.485 ;
     RECT  47.988 96.449 48.597 96.485 ;
     RECT  55.44 96.179 56.697 96.485 ;
     RECT  52.416 96.449 54.27 96.509 ;
     RECT  34.776 96.449 35.226 96.521 ;
     RECT  29.34 95.369 30.078 96.565 ;
     RECT  37.476 96.449 37.797 96.571 ;
     RECT  34.815 96.521 35.226 96.593 ;
     RECT  31.356 96.449 32.397 96.629 ;
     RECT  37.044 96.571 37.797 96.629 ;
     RECT  38.628 96.179 39.114 96.629 ;
     RECT  52.416 96.509 52.83 96.629 ;
     RECT  53.676 96.509 53.997 96.629 ;
     RECT  2.415 93.281 2.697 96.677 ;
     RECT  5.115 93.389 5.397 96.677 ;
     RECT  7.815 93.389 8.097 96.677 ;
     RECT  10.515 89.261 10.797 96.677 ;
     RECT  13.215 89.168 13.497 96.677 ;
     RECT  15.915 79.277 16.197 96.677 ;
     RECT  18.615 93.317 18.897 96.677 ;
     RECT  21.315 93.485 21.597 96.677 ;
     RECT  24.015 96.215 24.297 96.677 ;
     RECT  26.715 95.819 27.666 96.677 ;
     RECT  34.815 96.593 35.097 96.677 ;
     RECT  37.515 96.629 37.797 96.677 ;
     RECT  40.215 96.449 40.878 96.677 ;
     RECT  42.915 96.485 43.197 96.677 ;
     RECT  48.315 96.485 48.597 96.677 ;
     RECT  51.015 96.215 51.297 96.677 ;
     RECT  53.715 96.629 53.997 96.677 ;
     RECT  55.584 96.485 56.697 96.677 ;
     RECT  59.115 95.549 59.397 96.677 ;
     RECT  61.815 95.909 62.097 96.677 ;
     RECT  26.907 96.677 27.666 96.719 ;
     RECT  29.34 96.565 30.366 96.719 ;
     RECT  38.952 96.629 39.114 96.719 ;
     RECT  40.407 96.677 40.878 96.719 ;
     RECT  45.216 96.485 46.782 96.719 ;
     RECT  52.668 96.629 52.83 96.719 ;
     RECT  55.584 96.677 55.746 96.719 ;
     RECT  26.907 96.719 27.522 96.755 ;
     RECT  37.656 96.677 37.797 96.755 ;
     RECT  38.952 96.719 38.97 96.755 ;
     RECT  40.407 96.719 40.77 96.755 ;
     RECT  45.216 96.719 45.897 96.755 ;
     RECT  52.668 96.719 52.686 96.755 ;
     RECT  55.584 96.719 55.602 96.755 ;
     RECT  31.608 96.629 32.397 96.791 ;
     RECT  46.764 96.719 46.782 96.791 ;
     RECT  2.607 96.677 2.697 96.947 ;
     RECT  5.307 96.677 5.397 96.947 ;
     RECT  8.007 96.677 8.097 96.947 ;
     RECT  10.707 96.677 10.797 96.947 ;
     RECT  13.407 96.677 13.497 96.947 ;
     RECT  16.107 96.677 16.197 96.947 ;
     RECT  18.807 96.677 18.897 96.947 ;
     RECT  21.507 96.677 21.597 96.947 ;
     RECT  24.207 96.677 24.297 96.947 ;
     RECT  26.907 96.755 26.997 96.947 ;
     RECT  29.607 96.719 30.366 96.947 ;
     RECT  32.307 96.791 32.397 96.947 ;
     RECT  35.007 96.677 35.097 96.947 ;
     RECT  37.707 96.755 37.797 96.947 ;
     RECT  40.407 96.755 40.497 96.947 ;
     RECT  43.107 96.677 43.197 96.947 ;
     RECT  45.807 96.755 45.897 96.947 ;
     RECT  48.507 96.677 48.597 96.947 ;
     RECT  51.207 96.677 51.297 96.947 ;
     RECT  53.907 96.677 53.997 96.947 ;
     RECT  56.607 96.677 56.697 96.947 ;
     RECT  59.307 96.677 59.397 96.947 ;
     RECT  62.007 96.677 62.097 96.947 ;
     RECT  29.844 96.947 30.366 99.211 ;
     RECT  29.772 99.211 30.366 99.256 ;
     RECT  29.52 99.256 30.366 99.293 ;
     RECT  29.7 99.293 30.366 99.324 ;
    LAYER M4 ;
     RECT  0.06 9.552 0.133 25.608 ;
     RECT  0.06 44.88 0.133 54.024 ;
     RECT  0.06 60.624 0.133 67.08 ;
     RECT  0.06 73.296 0.133 76.296 ;
     RECT  0.133 73.248 0.17 76.296 ;
     RECT  0.06 34.896 0.569 37.896 ;
     RECT  0.133 44.88 0.569 54.12 ;
     RECT  0.133 9.552 1.181 25.656 ;
     RECT  1.181 9.552 2.221 25.56 ;
     RECT  2.221 9.024 2.408 25.56 ;
     RECT  0.06 28.752 2.408 31.752 ;
     RECT  0.569 34.944 2.408 37.896 ;
     RECT  0.569 44.976 2.408 54.12 ;
     RECT  0.133 60.624 2.408 67.128 ;
     RECT  0.17 73.248 2.408 76.248 ;
     RECT  0.06 80.208 2.408 92.424 ;
     RECT  2.408 2.148 2.512 96.672 ;
     RECT  2.512 2.418 2.6 96.672 ;
     RECT  2.6 2.418 2.704 96.942 ;
     RECT  2.704 80.304 2.801 92.424 ;
     RECT  2.704 9.024 2.837 25.656 ;
     RECT  2.704 34.8 3.443 37.896 ;
     RECT  2.704 60.672 3.733 67.176 ;
     RECT  2.801 80.4 3.769 92.424 ;
     RECT  2.704 28.944 3.805 32.088 ;
     RECT  2.837 9.264 3.809 25.656 ;
     RECT  3.805 28.512 3.917 32.088 ;
     RECT  3.769 80.016 4.165 92.424 ;
     RECT  4.165 79.2 4.345 92.424 ;
     RECT  2.704 73.248 4.381 76.392 ;
     RECT  4.345 79.2 4.501 92.568 ;
     RECT  3.809 9.264 4.849 11.784 ;
     RECT  3.809 13.056 4.849 25.656 ;
     RECT  4.849 9.264 4.921 25.656 ;
     RECT  4.885 27.216 4.921 27.24 ;
     RECT  4.921 9.264 5.108 27.24 ;
     RECT  3.917 28.848 5.108 32.088 ;
     RECT  3.443 34.944 5.108 37.896 ;
     RECT  2.704 44.976 5.108 54.12 ;
     RECT  3.733 60.576 5.108 67.176 ;
     RECT  4.381 73.248 5.108 76.632 ;
     RECT  4.501 79.008 5.108 92.568 ;
     RECT  5.108 2.148 5.212 96.672 ;
     RECT  5.212 2.418 5.3 96.672 ;
     RECT  5.3 2.418 5.404 96.942 ;
     RECT  5.404 72.912 5.465 75.816 ;
     RECT  5.404 45.168 5.537 54.12 ;
     RECT  5.404 12.816 5.555 26.856 ;
     RECT  5.404 60.816 5.573 67.272 ;
     RECT  5.555 12.816 5.747 25.896 ;
     RECT  5.404 28.944 5.789 31.848 ;
     RECT  5.404 55.152 6.083 55.272 ;
     RECT  5.465 72.912 6.505 75.528 ;
     RECT  5.573 63.024 6.572 67.272 ;
     RECT  5.573 60.816 6.649 62.04 ;
     RECT  6.572 63.024 6.649 67.464 ;
     RECT  6.505 72.624 6.649 75.528 ;
     RECT  5.404 9.264 6.653 11.784 ;
     RECT  6.649 60.816 6.653 67.464 ;
     RECT  6.653 61.152 6.659 67.464 ;
     RECT  5.404 78.96 6.707 93.096 ;
     RECT  6.653 9.84 6.793 11.784 ;
     RECT  5.747 12.816 6.793 22.104 ;
     RECT  5.537 45.456 6.829 54.12 ;
     RECT  6.707 93.072 6.829 93.096 ;
     RECT  6.649 72.624 6.833 76.344 ;
     RECT  5.789 29.04 6.853 31.848 ;
     RECT  6.829 45.168 7.045 54.12 ;
     RECT  5.747 23.328 7.153 25.896 ;
     RECT  7.153 23.088 7.189 25.896 ;
     RECT  6.793 9.84 7.261 22.104 ;
     RECT  7.189 23.088 7.261 26.136 ;
     RECT  7.045 44.88 7.477 54.12 ;
     RECT  6.083 55.248 7.477 55.272 ;
     RECT  7.405 27.6 7.585 27.624 ;
     RECT  7.261 9.84 7.808 26.136 ;
     RECT  7.585 27.6 7.808 27.72 ;
     RECT  6.853 29.04 7.808 32.472 ;
     RECT  5.404 34.944 7.808 37.608 ;
     RECT  7.477 44.88 7.808 55.272 ;
     RECT  6.659 61.152 7.808 67.272 ;
     RECT  5.404 69.552 7.808 69.576 ;
     RECT  6.833 73.344 7.808 76.344 ;
     RECT  6.707 78.96 7.808 91.992 ;
     RECT  6.829 93.072 7.808 93.336 ;
     RECT  7.808 2.148 7.912 96.672 ;
     RECT  7.912 2.418 8 96.672 ;
     RECT  8 2.418 8.104 96.942 ;
     RECT  8.104 75.408 8.165 77.064 ;
     RECT  8.104 60.816 8.201 67.176 ;
     RECT  8.165 75.504 8.243 77.064 ;
     RECT  8.104 44.88 8.291 48.744 ;
     RECT  8.104 81.168 8.381 90.6 ;
     RECT  8.201 67.152 8.417 67.176 ;
     RECT  8.201 60.816 8.448 66.024 ;
     RECT  8.448 61.728 8.489 66.024 ;
     RECT  8.104 9.84 8.525 26.568 ;
     RECT  8.525 19.056 8.597 26.568 ;
     RECT  8.381 81.168 8.597 90.552 ;
     RECT  8.291 45.216 8.633 48.744 ;
     RECT  8.104 49.824 8.633 54.456 ;
     RECT  8.104 27.6 8.777 31.752 ;
     RECT  8.597 19.056 8.921 20.424 ;
     RECT  8.525 9.84 8.993 17.976 ;
     RECT  8.597 21.936 9.097 26.568 ;
     RECT  8.777 27.6 9.097 31.464 ;
     RECT  8.104 73.344 9.133 74.424 ;
     RECT  8.104 32.784 9.137 33.048 ;
     RECT  8.489 61.968 9.173 63.096 ;
     RECT  9.097 21.936 9.281 31.464 ;
     RECT  8.633 45.216 9.389 47.736 ;
     RECT  9.281 25.68 9.817 31.464 ;
     RECT  9.817 25.68 10.033 31.512 ;
     RECT  9.137 32.784 10.033 32.808 ;
     RECT  10.033 25.68 10.213 32.808 ;
     RECT  8.104 34.752 10.213 38.664 ;
     RECT  10.213 25.68 10.241 33.144 ;
     RECT  10.241 25.68 10.249 33.672 ;
     RECT  10.249 24.912 10.357 33.672 ;
     RECT  10.213 34.752 10.357 38.76 ;
     RECT  8.993 9.84 10.508 16.104 ;
     RECT  8.993 17.424 10.508 17.976 ;
     RECT  8.921 19.056 10.508 19.08 ;
     RECT  8.921 20.4 10.508 20.424 ;
     RECT  9.281 21.936 10.508 23.928 ;
     RECT  10.357 24.912 10.508 38.76 ;
     RECT  9.389 45.216 10.508 47.16 ;
     RECT  8.633 48.72 10.508 48.744 ;
     RECT  8.633 50.112 10.508 51.192 ;
     RECT  8.633 52.224 10.508 54.456 ;
     RECT  9.173 61.968 10.508 61.992 ;
     RECT  9.173 63.072 10.508 63.096 ;
     RECT  8.489 64.464 10.508 66.024 ;
     RECT  8.104 69.552 10.508 69.576 ;
     RECT  9.133 73.248 10.508 74.424 ;
     RECT  8.243 75.504 10.508 75.528 ;
     RECT  8.104 78.96 10.508 80.088 ;
     RECT  8.597 81.168 10.508 90.408 ;
     RECT  8.104 91.584 10.508 93.336 ;
     RECT  10.508 2.148 10.612 96.672 ;
     RECT  10.612 2.418 10.7 96.672 ;
     RECT  10.7 2.418 10.804 96.942 ;
     RECT  10.804 9.84 10.829 16.104 ;
     RECT  10.804 19.056 10.829 39.384 ;
     RECT  10.804 52.224 10.829 54.456 ;
     RECT  10.829 29.04 10.865 39.384 ;
     RECT  10.829 19.056 11.123 27.96 ;
     RECT  10.865 29.088 11.123 39.384 ;
     RECT  11.123 29.088 11.161 38.28 ;
     RECT  11.123 19.056 11.267 27.72 ;
     RECT  10.804 69.552 11.377 69.576 ;
     RECT  10.804 75.504 11.977 75.528 ;
     RECT  10.804 17.424 12.193 17.976 ;
     RECT  11.267 19.056 12.193 25.032 ;
     RECT  10.804 73.248 12.229 74.424 ;
     RECT  12.193 17.424 12.301 25.032 ;
     RECT  11.267 26.064 12.301 27.72 ;
     RECT  11.123 39.36 12.337 39.384 ;
     RECT  11.161 29.232 12.476 38.28 ;
     RECT  12.337 39.264 12.476 39.384 ;
     RECT  12.476 29.232 12.625 39.384 ;
     RECT  12.301 17.424 12.769 27.72 ;
     RECT  12.625 29.04 12.769 39.384 ;
     RECT  10.804 64.464 12.877 66.024 ;
     RECT  12.409 67.296 12.877 67.32 ;
     RECT  10.829 9.84 13.093 10.92 ;
     RECT  10.829 11.952 13.093 16.104 ;
     RECT  12.769 17.424 13.093 39.384 ;
     RECT  12.625 70.8 13.093 70.824 ;
     RECT  10.804 63.072 13.129 63.096 ;
     RECT  13.129 63.072 13.201 63.384 ;
     RECT  12.877 64.464 13.201 67.32 ;
     RECT  13.093 9.84 13.208 16.104 ;
     RECT  13.093 17.376 13.208 39.384 ;
     RECT  10.804 45.216 13.208 47.16 ;
     RECT  10.804 48.72 13.208 48.744 ;
     RECT  10.804 50.112 13.208 51.192 ;
     RECT  10.829 52.272 13.208 54.456 ;
     RECT  10.804 61.968 13.208 61.992 ;
     RECT  13.201 63.072 13.208 67.32 ;
     RECT  12.625 68.928 13.208 68.952 ;
     RECT  13.093 70.8 13.208 70.872 ;
     RECT  12.229 72.96 13.208 74.424 ;
     RECT  11.977 75.456 13.208 75.528 ;
     RECT  10.804 78.96 13.208 80.088 ;
     RECT  10.804 81.168 13.208 90.408 ;
     RECT  10.804 91.584 13.208 93.336 ;
     RECT  13.208 2.148 13.312 96.672 ;
     RECT  13.312 2.418 13.4 96.672 ;
     RECT  13.4 2.418 13.504 96.942 ;
     RECT  13.504 70.8 13.565 74.424 ;
     RECT  13.504 61.968 13.601 69.48 ;
     RECT  13.601 67.296 13.961 69.48 ;
     RECT  13.504 34.128 14.501 39.912 ;
     RECT  13.961 68.736 14.537 69.48 ;
     RECT  13.504 9.84 14.609 25.032 ;
     RECT  14.501 34.128 14.645 39.336 ;
     RECT  14.609 21.936 14.713 25.032 ;
     RECT  13.565 70.896 14.789 74.424 ;
     RECT  13.504 52.272 14.821 54.456 ;
     RECT  14.789 71.952 14.857 74.424 ;
     RECT  13.504 75.456 14.857 75.528 ;
     RECT  13.504 26.112 14.861 32.952 ;
     RECT  13.504 45.216 14.861 47.208 ;
     RECT  13.504 81.168 14.861 90.408 ;
     RECT  14.861 30.912 14.893 32.952 ;
     RECT  13.601 61.968 15.001 66.216 ;
     RECT  13.504 76.944 15.145 76.968 ;
     RECT  15.001 61.488 15.181 66.216 ;
     RECT  14.537 68.928 15.253 69.48 ;
     RECT  14.789 70.896 15.253 70.968 ;
     RECT  15.145 76.944 15.289 77.064 ;
     RECT  15.289 76.944 15.325 77.544 ;
     RECT  13.504 78.96 15.325 80.088 ;
     RECT  15.181 60.72 15.349 66.216 ;
     RECT  15.325 76.944 15.349 80.088 ;
     RECT  13.961 67.296 15.469 67.32 ;
     RECT  14.713 21.936 15.541 25.08 ;
     RECT  14.861 26.112 15.541 29.64 ;
     RECT  14.609 9.84 15.613 20.952 ;
     RECT  15.541 21.936 15.613 29.64 ;
     RECT  15.349 76.56 15.613 80.088 ;
     RECT  14.893 30.912 15.637 33.576 ;
     RECT  14.645 34.944 15.637 39.336 ;
     RECT  15.349 60.144 15.781 66.216 ;
     RECT  15.469 67.296 15.781 67.368 ;
     RECT  15.613 9.84 15.908 29.64 ;
     RECT  15.637 30.912 15.908 39.336 ;
     RECT  15.469 40.416 15.908 40.44 ;
     RECT  14.861 45.216 15.908 47.16 ;
     RECT  13.504 48.72 15.908 48.744 ;
     RECT  13.504 50.112 15.908 51.192 ;
     RECT  14.821 52.176 15.908 54.456 ;
     RECT  14.929 56.352 15.908 56.376 ;
     RECT  15.308 59.088 15.908 59.112 ;
     RECT  15.781 60.144 15.908 66.312 ;
     RECT  15.781 67.296 15.908 67.752 ;
     RECT  15.253 68.928 15.908 70.968 ;
     RECT  14.857 71.952 15.908 75.528 ;
     RECT  15.613 76.512 15.908 80.088 ;
     RECT  14.861 81.168 15.908 90.36 ;
     RECT  13.504 91.584 15.908 93.336 ;
     RECT  15.908 2.148 16.012 96.672 ;
     RECT  16.012 2.418 16.1 96.672 ;
     RECT  16.1 2.418 16.204 96.942 ;
     RECT  16.204 27.696 16.265 39.096 ;
     RECT  16.204 61.968 16.409 70.632 ;
     RECT  16.204 73.344 16.547 80.088 ;
     RECT  16.204 52.176 16.553 60.6 ;
     RECT  16.553 57.12 16.589 60.6 ;
     RECT  16.204 40.416 16.733 40.44 ;
     RECT  16.265 27.696 16.828 38.952 ;
     RECT  16.409 69.072 17.057 70.632 ;
     RECT  16.828 27.696 17.165 38.712 ;
     RECT  16.589 57.408 17.197 60.6 ;
     RECT  17.165 27.696 17.201 33.144 ;
     RECT  16.204 9.84 17.269 26.664 ;
     RECT  17.201 27.696 17.269 33.048 ;
     RECT  17.269 9.84 17.309 33.048 ;
     RECT  16.204 42.72 17.413 42.744 ;
     RECT  17.197 57.408 17.521 60.648 ;
     RECT  16.409 61.968 17.521 67.944 ;
     RECT  16.547 73.344 17.605 76.824 ;
     RECT  16.547 78.096 17.605 80.088 ;
     RECT  17.521 57.408 17.633 67.944 ;
     RECT  16.553 52.176 17.653 55.8 ;
     RECT  17.633 57.408 17.653 59.016 ;
     RECT  16.204 50.112 17.665 51.192 ;
     RECT  17.653 52.176 17.665 59.016 ;
     RECT  17.309 9.84 17.737 20.424 ;
     RECT  17.165 34.368 17.845 38.712 ;
     RECT  17.593 39.84 17.845 39.864 ;
     RECT  17.413 41.952 18.025 42.744 ;
     RECT  18.169 72.144 18.277 72.168 ;
     RECT  17.605 73.344 18.277 80.088 ;
     RECT  17.737 9.36 18.313 20.424 ;
     RECT  17.309 21.648 18.313 33.048 ;
     RECT  17.057 70.272 18.313 70.632 ;
     RECT  18.277 72.144 18.313 80.088 ;
     RECT  18.313 70.272 18.38 80.088 ;
     RECT  18.38 70.272 18.429 80.136 ;
     RECT  16.204 81.168 18.429 90.36 ;
     RECT  18.025 41.232 18.529 42.744 ;
     RECT  18.313 9.36 18.608 33.048 ;
     RECT  17.845 34.368 18.608 39.864 ;
     RECT  18.529 41.232 18.608 43.368 ;
     RECT  16.204 45.216 18.608 47.16 ;
     RECT  16.204 48.72 18.608 48.744 ;
     RECT  17.665 50.112 18.608 59.016 ;
     RECT  17.633 60.384 18.608 67.944 ;
     RECT  17.057 69.072 18.608 69.096 ;
     RECT  18.429 70.272 18.608 90.36 ;
     RECT  16.204 91.584 18.608 93.336 ;
     RECT  18.608 2.148 18.712 96.672 ;
     RECT  18.712 2.418 18.8 96.672 ;
     RECT  18.8 2.418 18.904 96.942 ;
     RECT  18.904 73.344 18.929 93.336 ;
     RECT  18.904 50.112 18.965 59.016 ;
     RECT  18.904 61.104 18.965 67.944 ;
     RECT  18.904 41.232 19.073 43.368 ;
     RECT  18.904 68.928 19.081 71.736 ;
     RECT  18.929 73.344 19.829 77.16 ;
     RECT  18.904 9.36 19.897 38.808 ;
     RECT  19.073 43.008 19.957 43.368 ;
     RECT  18.904 44.352 19.957 47.16 ;
     RECT  19.957 43.008 20.003 47.16 ;
     RECT  18.965 50.112 20.005 55.752 ;
     RECT  18.965 61.968 20.005 67.944 ;
     RECT  19.897 8.544 20.009 38.808 ;
     RECT  20.003 43.296 20.045 47.16 ;
     RECT  20.045 43.296 20.051 43.32 ;
     RECT  18.929 78.432 20.149 93.336 ;
     RECT  20.009 8.544 20.153 26.664 ;
     RECT  18.965 57.024 20.225 59.016 ;
     RECT  20.005 61.92 20.297 67.944 ;
     RECT  20.113 41.664 20.3 41.688 ;
     RECT  18.904 48.24 20.329 48.744 ;
     RECT  20.005 50.064 20.329 55.752 ;
     RECT  20.297 61.92 20.365 61.992 ;
     RECT  20.365 61.488 20.401 61.992 ;
     RECT  19.829 73.344 20.509 76.824 ;
     RECT  18.904 60 20.761 60.024 ;
     RECT  20.401 61.248 20.761 61.992 ;
     RECT  20.225 57.072 20.797 59.016 ;
     RECT  20.761 60 20.797 61.992 ;
     RECT  20.509 72.912 20.869 76.824 ;
     RECT  20.329 48.24 21.109 55.752 ;
     RECT  20.869 72.912 21.157 77.064 ;
     RECT  20.149 78.384 21.157 93.336 ;
     RECT  20.297 62.976 21.193 67.944 ;
     RECT  19.081 68.928 21.193 70.632 ;
     RECT  20.153 8.544 21.308 26.616 ;
     RECT  20.009 27.696 21.308 38.808 ;
     RECT  20.773 40.656 21.308 40.68 ;
     RECT  20.3 41.664 21.308 42.216 ;
     RECT  20.045 44.352 21.308 47.16 ;
     RECT  21.109 48.24 21.308 56.088 ;
     RECT  20.797 57.072 21.308 61.992 ;
     RECT  21.193 62.976 21.308 70.632 ;
     RECT  19.081 71.712 21.308 71.736 ;
     RECT  21.157 72.912 21.308 93.336 ;
     RECT  21.308 2.148 21.412 96.672 ;
     RECT  21.412 2.418 21.5 96.672 ;
     RECT  21.5 2.418 21.604 96.942 ;
     RECT  21.604 8.976 21.701 25.032 ;
     RECT  21.604 34.08 21.701 38.808 ;
     RECT  21.701 34.08 21.845 38.52 ;
     RECT  21.604 61.92 21.875 70.632 ;
     RECT  21.604 60.672 21.916 60.936 ;
     RECT  21.875 61.968 22.169 70.632 ;
     RECT  21.604 45.168 22.205 55.512 ;
     RECT  22.169 63.072 22.211 70.632 ;
     RECT  21.604 39.888 22.259 41.928 ;
     RECT  21.604 72.96 22.277 93.48 ;
     RECT  21.701 8.976 22.349 24.984 ;
     RECT  21.604 27.696 22.385 33.048 ;
     RECT  22.349 9.072 22.421 24.984 ;
     RECT  22.211 63.072 22.493 68.952 ;
     RECT  22.259 39.888 22.499 40.872 ;
     RECT  22.499 40.56 22.54 40.872 ;
     RECT  22.205 45.168 22.597 48.984 ;
     RECT  22.205 50.064 22.597 55.512 ;
     RECT  21.916 60.672 22.597 60.696 ;
     RECT  21.604 57.312 22.637 59.448 ;
     RECT  21.604 26.112 22.669 26.664 ;
     RECT  21.845 34.224 22.705 38.52 ;
     RECT  22.277 72.96 22.741 90.504 ;
     RECT  22.669 26.064 22.777 26.664 ;
     RECT  22.385 27.696 22.777 27.72 ;
     RECT  22.421 9.552 22.789 24.984 ;
     RECT  22.633 42.192 22.817 42.216 ;
     RECT  22.789 9.552 22.849 25.08 ;
     RECT  22.777 26.064 22.849 27.72 ;
     RECT  22.597 60.576 22.885 60.696 ;
     RECT  22.169 61.968 22.885 61.992 ;
     RECT  22.705 7.968 22.889 7.992 ;
     RECT  22.597 50.064 22.921 55.848 ;
     RECT  22.385 28.8 22.933 33.048 ;
     RECT  22.885 60.576 23.033 61.992 ;
     RECT  23.033 60.624 23.132 61.992 ;
     RECT  23.132 60.624 23.173 62.04 ;
     RECT  22.493 63.072 23.173 63.096 ;
     RECT  22.741 72.576 23.245 90.504 ;
     RECT  22.277 91.584 23.245 93.48 ;
     RECT  22.849 9.552 23.389 27.72 ;
     RECT  22.933 28.8 23.389 33.096 ;
     RECT  23.245 72.576 23.425 94.632 ;
     RECT  22.921 50.064 23.497 56.184 ;
     RECT  22.637 57.312 23.497 59.16 ;
     RECT  23.389 9.456 23.533 33.096 ;
     RECT  22.597 44.448 23.677 48.984 ;
     RECT  23.497 50.064 23.677 59.16 ;
     RECT  23.533 8.832 23.708 33.096 ;
     RECT  22.705 34.224 23.708 39 ;
     RECT  22.54 40.848 23.708 40.872 ;
     RECT  23.413 42.144 23.708 42.168 ;
     RECT  23.708 8.832 23.749 39 ;
     RECT  22.493 64.128 23.821 68.952 ;
     RECT  23.708 40.848 23.845 42.168 ;
     RECT  23.749 8.832 23.857 39.336 ;
     RECT  21.604 6.816 24.008 6.84 ;
     RECT  23.857 8.016 24.008 39.336 ;
     RECT  23.845 40.32 24.008 42.168 ;
     RECT  22.813 43.296 24.008 43.32 ;
     RECT  23.677 44.448 24.008 59.16 ;
     RECT  23.173 60.624 24.008 63.096 ;
     RECT  23.821 64.128 24.008 69 ;
     RECT  22.211 70.032 24.008 70.632 ;
     RECT  23.425 72.576 24.008 95.208 ;
     RECT  24.008 2.148 24.112 96.672 ;
     RECT  24.112 2.418 24.2 96.672 ;
     RECT  24.2 2.418 24.304 96.942 ;
     RECT  24.304 59.232 24.401 95.208 ;
     RECT  24.304 41.616 24.419 42.216 ;
     RECT  24.304 29.568 24.437 40.488 ;
     RECT  24.401 59.232 24.509 93.624 ;
     RECT  24.509 59.232 24.517 80.088 ;
     RECT  24.517 60.768 24.581 80.088 ;
     RECT  24.304 43.296 24.617 55.848 ;
     RECT  24.304 6.72 24.659 24.456 ;
     RECT  24.581 60.96 24.905 80.088 ;
     RECT  24.905 60.96 24.941 69.096 ;
     RECT  24.419 41.904 24.995 42.216 ;
     RECT  24.659 6.768 25.085 24.456 ;
     RECT  24.995 42.144 25.283 42.216 ;
     RECT  24.941 60.96 25.337 67.944 ;
     RECT  24.437 30.912 25.409 40.488 ;
     RECT  24.617 43.632 25.441 55.848 ;
     RECT  24.304 57.024 25.441 58.056 ;
     RECT  24.517 59.232 25.445 59.256 ;
     RECT  24.401 94.656 25.549 94.68 ;
     RECT  24.304 96.192 25.549 96.216 ;
     RECT  25.549 94.656 25.589 96.216 ;
     RECT  25.441 43.632 25.621 58.056 ;
     RECT  24.905 70.08 25.629 80.088 ;
     RECT  24.509 81.168 25.629 93.624 ;
     RECT  25.085 9.072 25.667 24.456 ;
     RECT  25.409 30.912 25.667 38.232 ;
     RECT  25.283 42.144 25.667 42.168 ;
     RECT  25.589 95.136 25.669 96.216 ;
     RECT  25.629 70.08 25.693 93.624 ;
     RECT  25.337 61.968 26.053 67.944 ;
     RECT  24.941 68.928 26.053 69.096 ;
     RECT  25.085 7.92 26.108 7.992 ;
     RECT  25.085 6.768 26.125 6.84 ;
     RECT  26.305 59.568 26.581 59.592 ;
     RECT  25.621 43.536 26.629 58.056 ;
     RECT  26.125 6.576 26.708 6.84 ;
     RECT  26.108 7.92 26.708 8.376 ;
     RECT  25.667 9.6 26.708 24.456 ;
     RECT  24.304 26.112 26.708 26.664 ;
     RECT  24.304 27.696 26.708 27.72 ;
     RECT  24.437 29.568 26.708 29.832 ;
     RECT  25.667 30.912 26.708 33.096 ;
     RECT  25.667 34.224 26.708 38.232 ;
     RECT  25.409 39.216 26.708 40.488 ;
     RECT  26.629 43.392 26.708 58.056 ;
     RECT  26.581 59.568 26.708 59.736 ;
     RECT  25.337 60.96 26.708 60.984 ;
     RECT  26.053 61.968 26.708 69.096 ;
     RECT  25.693 70.08 26.708 93.864 ;
     RECT  25.669 95.136 26.708 96.36 ;
     RECT  26.708 2.148 26.812 96.672 ;
     RECT  26.812 2.418 26.9 96.672 ;
     RECT  26.9 2.418 27.004 96.942 ;
     RECT  27.004 34.464 27.029 40.344 ;
     RECT  27.004 59.136 27.065 93.336 ;
     RECT  27.004 42.576 27.101 58.152 ;
     RECT  27.101 42.576 27.209 55.272 ;
     RECT  27.065 59.136 27.389 80.136 ;
     RECT  27.004 94.656 27.389 95.448 ;
     RECT  27.389 59.136 27.443 71.304 ;
     RECT  27.443 59.136 27.533 59.256 ;
     RECT  27.443 60.384 27.605 71.304 ;
     RECT  27.004 7.92 27.713 7.944 ;
     RECT  27.029 34.464 27.772 39.864 ;
     RECT  27.004 9.216 27.813 24.456 ;
     RECT  27.209 42.576 27.821 48.984 ;
     RECT  27.821 43.392 27.827 48.984 ;
     RECT  27.827 44.928 27.926 48.984 ;
     RECT  27.605 61.2 27.971 71.304 ;
     RECT  27.389 72.72 28.177 80.136 ;
     RECT  27.065 81.168 28.177 93.336 ;
     RECT  27.101 56.304 28.217 58.152 ;
     RECT  27.209 50.112 28.321 55.272 ;
     RECT  28.217 56.304 28.321 57.864 ;
     RECT  27.772 34.464 28.453 38.232 ;
     RECT  27.772 39.216 28.537 39.864 ;
     RECT  27.926 44.976 28.573 48.984 ;
     RECT  28.321 50.112 28.573 57.864 ;
     RECT  27.813 21.936 28.645 24.456 ;
     RECT  27.004 6.24 28.885 6.84 ;
     RECT  28.285 7.968 28.885 7.992 ;
     RECT  27.813 9.216 28.885 20.856 ;
     RECT  27.827 43.392 28.897 43.56 ;
     RECT  28.105 42.336 28.933 42.36 ;
     RECT  28.897 43.392 28.933 43.848 ;
     RECT  28.573 44.976 28.968 57.864 ;
     RECT  28.453 34.272 29.077 38.232 ;
     RECT  27.971 61.2 29.077 71.112 ;
     RECT  28.933 42.336 29.105 43.848 ;
     RECT  28.968 44.928 29.105 57.864 ;
     RECT  28.885 6.24 29.149 20.856 ;
     RECT  28.177 72.72 29.269 93.336 ;
     RECT  29.149 6.24 29.408 20.952 ;
     RECT  28.645 21.936 29.408 24.696 ;
     RECT  27.004 26.112 29.408 26.664 ;
     RECT  27.004 27.696 29.408 27.72 ;
     RECT  27.004 29.568 29.408 29.832 ;
     RECT  27.004 30.912 29.408 33.048 ;
     RECT  29.077 34.176 29.408 38.232 ;
     RECT  28.537 39.216 29.408 40.056 ;
     RECT  29.105 42.336 29.408 57.864 ;
     RECT  27.533 59.232 29.408 59.256 ;
     RECT  29.077 60.816 29.408 71.112 ;
     RECT  29.269 72.72 29.408 93.528 ;
     RECT  27.389 94.656 29.408 95.4 ;
     RECT  29.408 2.148 29.512 96.672 ;
     RECT  17.221 99.264 29.549 99.288 ;
     RECT  29.512 2.418 29.6 96.672 ;
     RECT  29.6 2.418 29.704 96.942 ;
     RECT  29.704 27.696 29.873 40.056 ;
     RECT  29.761 99.216 29.891 99.24 ;
     RECT  29.704 6.672 30.197 6.84 ;
     RECT  29.704 72.864 30.508 93.528 ;
     RECT  30.197 6.816 30.665 6.84 ;
     RECT  29.704 7.968 30.709 24.696 ;
     RECT  29.704 60.816 30.733 71.304 ;
     RECT  29.704 59.28 30.805 59.304 ;
     RECT  29.704 94.56 30.805 95.352 ;
     RECT  30.508 73.008 30.841 93.528 ;
     RECT  30.805 94.512 30.841 95.352 ;
     RECT  30.709 7.92 30.845 24.696 ;
     RECT  30.841 73.008 30.845 95.352 ;
     RECT  29.704 96.336 30.851 96.36 ;
     RECT  30.733 60.816 30.917 71.88 ;
     RECT  29.704 26.112 30.985 26.664 ;
     RECT  29.873 27.696 30.985 39.912 ;
     RECT  30.917 60.816 31.097 71.304 ;
     RECT  29.704 43.344 31.237 57.864 ;
     RECT  31.097 60.816 31.34 63.336 ;
     RECT  30.805 59.04 31.381 59.304 ;
     RECT  31.34 60.528 31.381 63.336 ;
     RECT  30.985 26.112 31.621 39.912 ;
     RECT  31.621 26.112 31.633 40.584 ;
     RECT  31.237 43.296 31.669 57.864 ;
     RECT  31.669 42.768 31.777 57.864 ;
     RECT  31.777 42.768 31.885 57.96 ;
     RECT  31.381 59.04 31.885 63.336 ;
     RECT  31.201 6.912 31.957 6.936 ;
     RECT  31.957 6.816 32.108 6.936 ;
     RECT  30.845 8.544 32.108 24.696 ;
     RECT  31.633 26.112 32.108 41.016 ;
     RECT  31.885 42.768 32.108 63.336 ;
     RECT  31.097 64.416 32.108 71.304 ;
     RECT  30.845 73.008 32.108 94.68 ;
     RECT  32.108 2.148 32.212 96.672 ;
     RECT  32.212 2.418 32.3 96.672 ;
     RECT  32.3 2.418 32.404 96.942 ;
     RECT  32.404 25.824 32.465 39.336 ;
     RECT  32.404 43.824 32.465 60.12 ;
     RECT  32.404 6.912 32.573 16.104 ;
     RECT  32.573 8.976 32.579 16.104 ;
     RECT  32.404 73.008 32.668 95.736 ;
     RECT  32.465 43.92 32.753 60.12 ;
     RECT  32.404 71.616 32.789 71.64 ;
     RECT  32.465 25.824 32.861 39.048 ;
     RECT  32.573 6.912 32.933 7.8 ;
     RECT  32.404 61.104 33.041 70.392 ;
     RECT  32.668 91.584 33.059 95.736 ;
     RECT  32.668 73.008 33.113 90.36 ;
     RECT  32.933 7.632 33.221 7.8 ;
     RECT  33.113 73.008 33.395 76.392 ;
     RECT  33.041 63.024 33.397 70.392 ;
     RECT  33.221 7.632 33.401 7.656 ;
     RECT  32.753 44.928 33.443 60.12 ;
     RECT  32.753 43.92 33.473 43.944 ;
     RECT  32.579 9.84 33.577 16.104 ;
     RECT  32.404 17.136 33.577 24.744 ;
     RECT  33.443 55.728 33.683 60.12 ;
     RECT  33.113 77.376 33.725 90.36 ;
     RECT  33.577 9.84 33.797 24.744 ;
     RECT  33.041 61.104 34.081 62.04 ;
     RECT  33.397 63.024 34.081 70.584 ;
     RECT  33.797 20.208 34.117 24.744 ;
     RECT  32.861 25.824 34.117 39 ;
     RECT  33.757 71.616 34.153 71.64 ;
     RECT  33.395 73.008 34.153 76.2 ;
     RECT  33.059 91.584 34.165 94.056 ;
     RECT  33.059 95.088 34.165 95.736 ;
     RECT  34.081 61.104 34.333 70.584 ;
     RECT  34.153 71.616 34.333 76.2 ;
     RECT  33.443 44.928 34.501 54.696 ;
     RECT  33.683 55.728 34.501 58.248 ;
     RECT  34.117 20.208 34.549 39 ;
     RECT  34.333 61.104 34.657 76.2 ;
     RECT  33.725 77.376 34.657 85.752 ;
     RECT  32.404 42.768 34.693 42.792 ;
     RECT  34.549 6.816 34.808 6.84 ;
     RECT  33.797 9.84 34.808 19.08 ;
     RECT  34.549 20.208 34.808 39.24 ;
     RECT  34.693 42.768 34.808 43.656 ;
     RECT  34.501 44.928 34.808 58.248 ;
     RECT  33.683 60.096 34.808 60.12 ;
     RECT  34.657 61.104 34.808 85.752 ;
     RECT  33.725 86.784 34.808 90.36 ;
     RECT  34.165 91.584 34.808 95.736 ;
     RECT  34.808 2.148 34.912 96.672 ;
     RECT  34.912 2.418 35 96.672 ;
     RECT  35 2.418 35.104 96.942 ;
     RECT  35.104 95.184 35.201 95.736 ;
     RECT  35.104 61.056 35.273 75.768 ;
     RECT  35.273 71.616 35.309 75.768 ;
     RECT  35.104 6.816 35.363 19.08 ;
     RECT  35.104 76.848 35.489 94.152 ;
     RECT  35.309 72.24 35.525 75.768 ;
     RECT  35.104 42.768 35.633 57.672 ;
     RECT  35.363 7.392 35.813 19.08 ;
     RECT  35.273 61.056 35.885 70.632 ;
     RECT  35.633 42.816 35.987 57.672 ;
     RECT  35.104 20.304 36.085 39.912 ;
     RECT  36.085 20.304 36.097 40.824 ;
     RECT  35.987 42.816 36.101 44.088 ;
     RECT  36.101 42.816 36.179 43.8 ;
     RECT  35.525 72.432 36.205 75.768 ;
     RECT  35.489 76.848 36.205 93.528 ;
     RECT  36.205 72.432 36.209 93.528 ;
     RECT  35.813 8.16 36.253 19.08 ;
     RECT  36.253 9.84 36.281 19.08 ;
     RECT  36.209 73.008 36.353 93.528 ;
     RECT  36.253 8.16 36.389 8.856 ;
     RECT  35.987 45.12 36.419 57.672 ;
     RECT  36.179 43.536 36.461 43.8 ;
     RECT  36.097 20.304 36.469 41.064 ;
     RECT  36.461 43.536 36.515 43.752 ;
     RECT  35.885 61.056 36.529 63.336 ;
     RECT  35.104 58.944 36.668 58.968 ;
     RECT  36.281 11.712 36.853 19.08 ;
     RECT  36.469 20.304 36.853 41.592 ;
     RECT  35.201 95.184 36.853 95.208 ;
     RECT  35.885 64.368 36.925 70.632 ;
     RECT  36.853 94.656 37.249 95.208 ;
     RECT  36.353 75.408 37.465 93.528 ;
     RECT  36.281 9.84 37.501 10.488 ;
     RECT  36.389 8.16 37.508 8.52 ;
     RECT  37.501 9.84 37.508 10.632 ;
     RECT  36.853 11.712 37.508 41.592 ;
     RECT  36.515 43.536 37.508 43.56 ;
     RECT  36.419 45.12 37.508 54.456 ;
     RECT  36.419 55.728 37.508 57.672 ;
     RECT  36.668 58.656 37.508 58.968 ;
     RECT  36.529 60.96 37.508 63.336 ;
     RECT  36.925 64.368 37.508 71.304 ;
     RECT  36.353 73.008 37.508 74.088 ;
     RECT  37.465 75.12 37.508 93.528 ;
     RECT  37.249 94.608 37.508 95.208 ;
     RECT  37.033 96.576 37.508 96.6 ;
     RECT  37.508 2.148 37.612 96.672 ;
     RECT  37.612 2.418 37.7 96.672 ;
     RECT  37.7 2.418 37.804 96.942 ;
     RECT  37.804 58.704 38.009 58.968 ;
     RECT  37.804 76.848 38.117 95.784 ;
     RECT  38.117 76.848 38.261 94.632 ;
     RECT  38.009 58.704 38.405 58.728 ;
     RECT  37.804 8.16 38.441 8.52 ;
     RECT  37.804 60.672 38.483 72.024 ;
     RECT  37.804 9.84 38.585 40.44 ;
     RECT  37.804 73.104 38.585 75.768 ;
     RECT  38.585 9.84 38.657 38.232 ;
     RECT  38.441 8.448 38.821 8.52 ;
     RECT  38.657 9.84 38.821 37.944 ;
     RECT  37.804 48.72 38.869 57.672 ;
     RECT  38.821 8.448 38.909 37.944 ;
     RECT  38.909 8.448 38.945 33.384 ;
     RECT  38.585 73.248 38.977 75.768 ;
     RECT  38.261 76.848 38.977 94.536 ;
     RECT  38.945 8.448 39.011 10.632 ;
     RECT  38.965 7.392 39.053 7.416 ;
     RECT  38.585 39.216 39.053 40.44 ;
     RECT  38.945 11.712 39.089 33.384 ;
     RECT  38.483 60.672 39.109 71.208 ;
     RECT  39.109 59.76 39.196 71.208 ;
     RECT  38.909 34.368 39.197 37.944 ;
     RECT  37.804 43.536 39.229 43.56 ;
     RECT  39.229 43.152 39.301 43.56 ;
     RECT  38.977 73.248 39.301 94.536 ;
     RECT  38.869 48.72 39.589 57.864 ;
     RECT  37.804 45.216 39.697 47.16 ;
     RECT  39.589 48.24 39.697 57.864 ;
     RECT  39.301 73.248 39.877 95.16 ;
     RECT  39.877 73.152 39.941 95.16 ;
     RECT  39.301 43.104 40.129 43.56 ;
     RECT  39.697 45.216 40.129 57.864 ;
     RECT  40.129 43.104 40.201 57.864 ;
     RECT  40.021 8.544 40.208 8.568 ;
     RECT  39.011 9.84 40.208 10.632 ;
     RECT  39.089 11.712 40.208 33.336 ;
     RECT  39.197 34.704 40.208 37.944 ;
     RECT  39.053 39.216 40.208 40.152 ;
     RECT  40.201 42.192 40.208 57.864 ;
     RECT  39.196 60.288 40.208 71.208 ;
     RECT  39.941 73.056 40.208 95.16 ;
     RECT  40.208 2.148 40.312 96.672 ;
     RECT  40.312 2.418 40.4 96.672 ;
     RECT  40.4 2.418 40.504 96.942 ;
     RECT  40.504 8.544 40.565 10.632 ;
     RECT  40.565 8.544 40.709 10.44 ;
     RECT  40.504 61.44 40.745 71.64 ;
     RECT  40.504 59.28 40.883 59.304 ;
     RECT  40.504 34.992 41.033 37.656 ;
     RECT  40.504 42.192 41.105 58.152 ;
     RECT  40.745 61.44 41.141 70.392 ;
     RECT  40.504 95.136 41.219 96.408 ;
     RECT  41.105 42.192 41.285 44.04 ;
     RECT  40.504 72.864 41.681 93.336 ;
     RECT  41.681 75.792 41.753 90.504 ;
     RECT  41.141 61.44 41.789 69.864 ;
     RECT  41.105 45.12 41.821 58.152 ;
     RECT  40.745 71.376 41.821 71.64 ;
     RECT  41.681 72.864 41.821 74.76 ;
     RECT  41.821 45.12 41.897 58.44 ;
     RECT  41.285 43.104 41.939 44.04 ;
     RECT  40.709 8.832 42.085 10.44 ;
     RECT  40.504 11.664 42.085 33.336 ;
     RECT  42.085 8.832 42.109 33.336 ;
     RECT  41.789 65.136 42.145 69.864 ;
     RECT  41.821 71.376 42.145 74.76 ;
     RECT  41.033 36.048 42.277 37.656 ;
     RECT  41.033 34.992 42.505 35.016 ;
     RECT  41.219 95.232 42.541 95.784 ;
     RECT  42.505 34.752 42.649 35.016 ;
     RECT  42.277 36.048 42.649 38.232 ;
     RECT  42.109 8.736 42.721 33.336 ;
     RECT  41.789 61.44 42.757 63.864 ;
     RECT  41.681 91.584 42.757 93.336 ;
     RECT  41.939 43.104 42.761 43.848 ;
     RECT  42.721 8.736 42.829 33.576 ;
     RECT  42.649 34.752 42.829 38.232 ;
     RECT  42.757 61.44 42.829 64.104 ;
     RECT  42.829 8.736 42.908 38.232 ;
     RECT  42.865 41.664 42.908 41.688 ;
     RECT  42.761 43.056 42.908 43.848 ;
     RECT  41.897 45.168 42.908 58.44 ;
     RECT  42.829 60.816 42.908 64.104 ;
     RECT  42.145 65.136 42.908 74.76 ;
     RECT  41.753 75.792 42.908 90.36 ;
     RECT  42.757 91.536 42.908 93.336 ;
     RECT  42.541 94.608 42.908 95.784 ;
     RECT  42.908 2.148 43.012 96.672 ;
     RECT  43.012 2.418 43.1 96.672 ;
     RECT  43.1 2.418 43.204 96.942 ;
     RECT  43.204 94.656 43.331 94.872 ;
     RECT  43.204 95.856 43.372 95.88 ;
     RECT  43.204 63.504 43.373 71.928 ;
     RECT  43.204 42.72 43.445 43.128 ;
     RECT  43.204 49.824 43.481 57.72 ;
     RECT  43.204 72.96 43.481 74.088 ;
     RECT  43.204 45.168 43.517 47.352 ;
     RECT  43.204 40.992 43.697 41.688 ;
     RECT  43.481 49.824 43.913 57.432 ;
     RECT  43.373 63.504 43.913 71.4 ;
     RECT  43.204 8.496 43.985 38.28 ;
     RECT  43.913 63.504 44.129 70.536 ;
     RECT  43.985 11.952 44.165 38.28 ;
     RECT  43.481 72.96 44.195 73.512 ;
     RECT  43.204 48.72 44.233 48.744 ;
     RECT  43.204 76.752 44.305 90.36 ;
     RECT  43.204 91.584 44.305 93.336 ;
     RECT  44.195 72.96 44.341 73.368 ;
     RECT  43.985 8.496 44.345 10.584 ;
     RECT  43.204 58.704 44.345 58.728 ;
     RECT  43.204 60.816 44.381 61.464 ;
     RECT  44.341 72.864 44.425 73.368 ;
     RECT  43.697 40.992 44.489 41.016 ;
     RECT  44.305 76.752 44.489 93.336 ;
     RECT  43.517 45.216 44.521 47.352 ;
     RECT  44.345 9.36 44.525 10.584 ;
     RECT  43.331 94.656 44.557 94.776 ;
     RECT  44.233 48.624 45.025 48.744 ;
     RECT  44.521 44.88 45.061 47.352 ;
     RECT  45.025 48.384 45.061 48.744 ;
     RECT  43.913 50.064 45.061 54.456 ;
     RECT  45.061 96.336 45.241 96.36 ;
     RECT  44.129 63.936 45.26 70.536 ;
     RECT  43.204 75.648 45.277 75.672 ;
     RECT  45.26 63.936 45.301 71.352 ;
     RECT  44.809 58.512 45.349 58.536 ;
     RECT  44.165 11.952 45.385 38.184 ;
     RECT  44.701 39.216 45.385 39.24 ;
     RECT  45.385 11.952 45.421 39.24 ;
     RECT  44.525 9.84 45.457 10.584 ;
     RECT  45.421 11.712 45.457 39.24 ;
     RECT  45.061 49.872 45.457 54.456 ;
     RECT  44.489 77.04 45.457 93.336 ;
     RECT  45.457 49.824 45.493 54.456 ;
     RECT  43.913 55.44 45.493 57.432 ;
     RECT  45.493 49.824 45.565 57.432 ;
     RECT  45.349 58.512 45.565 59.496 ;
     RECT  45.277 75.648 45.565 75.816 ;
     RECT  45.457 9.84 45.608 39.24 ;
     RECT  45.025 41.04 45.608 41.064 ;
     RECT  43.445 43.104 45.608 43.128 ;
     RECT  45.061 44.88 45.608 48.744 ;
     RECT  45.565 49.824 45.608 59.496 ;
     RECT  44.381 61.2 45.608 61.464 ;
     RECT  45.301 63.936 45.608 71.736 ;
     RECT  44.425 73.056 45.608 73.368 ;
     RECT  44.449 74.592 45.608 74.616 ;
     RECT  45.565 75.648 45.608 76.056 ;
     RECT  45.457 77.04 45.608 93.48 ;
     RECT  44.557 94.656 45.608 95.16 ;
     RECT  45.241 96.24 45.608 96.36 ;
     RECT  45.608 2.148 45.712 96.672 ;
     RECT  45.712 2.418 45.8 96.672 ;
     RECT  45.8 2.418 45.904 96.942 ;
     RECT  45.904 11.472 46.037 18.024 ;
     RECT  45.904 44.4 46.067 61.464 ;
     RECT  45.904 71.184 46.067 73.464 ;
     RECT  46.037 12.288 46.073 18.024 ;
     RECT  45.904 67.056 46.073 70.008 ;
     RECT  46.073 67.056 46.109 68.52 ;
     RECT  45.904 96.336 46.181 96.36 ;
     RECT  46.067 71.712 46.217 73.464 ;
     RECT  46.109 67.056 46.253 68.136 ;
     RECT  45.904 19.008 46.289 37.944 ;
     RECT  46.073 69.984 46.325 70.008 ;
     RECT  46.067 45.504 46.403 61.464 ;
     RECT  45.904 75.216 46.685 95.16 ;
     RECT  46.685 95.04 46.757 95.16 ;
     RECT  46.217 72.24 46.793 73.464 ;
     RECT  46.685 75.216 46.793 93.48 ;
     RECT  46.067 44.4 46.937 44.472 ;
     RECT  45.904 39.216 46.969 40.584 ;
     RECT  46.289 20.4 46.973 37.944 ;
     RECT  45.904 41.808 46.973 43.416 ;
     RECT  46.973 20.4 47.009 34.2 ;
     RECT  46.253 67.056 47.009 67.704 ;
     RECT  46.937 44.448 47.045 44.472 ;
     RECT  46.973 35.184 47.077 37.944 ;
     RECT  46.969 38.976 47.077 40.584 ;
     RECT  46.403 45.504 47.185 58.536 ;
     RECT  46.793 72.528 47.185 73.464 ;
     RECT  46.403 59.76 47.189 61.464 ;
     RECT  46.973 41.808 47.257 43.128 ;
     RECT  47.077 35.184 47.261 40.584 ;
     RECT  47.221 75.12 47.269 75.144 ;
     RECT  46.757 95.136 47.329 95.16 ;
     RECT  47.189 59.808 47.42 61.464 ;
     RECT  46.289 19.008 47.509 19.416 ;
     RECT  47.009 20.4 47.509 34.152 ;
     RECT  47.42 59.808 47.725 61.848 ;
     RECT  47.185 72.528 47.725 73.512 ;
     RECT  47.269 74.976 47.725 75.144 ;
     RECT  47.329 95.136 47.761 95.688 ;
     RECT  46.073 12.288 47.869 17.976 ;
     RECT  47.725 59.808 47.893 62.136 ;
     RECT  47.725 72.528 47.989 75.144 ;
     RECT  46.793 76.176 47.989 93.48 ;
     RECT  47.989 71.712 48.121 93.48 ;
     RECT  47.185 44.928 48.157 58.536 ;
     RECT  47.509 19.008 48.181 34.152 ;
     RECT  47.261 35.184 48.181 39.864 ;
     RECT  45.904 9.84 48.193 10.44 ;
     RECT  48.193 9.84 48.308 10.92 ;
     RECT  47.869 11.952 48.308 17.976 ;
     RECT  48.181 19.008 48.308 39.864 ;
     RECT  47.257 41.76 48.308 43.128 ;
     RECT  48.157 44.928 48.308 58.824 ;
     RECT  47.893 59.808 48.308 62.712 ;
     RECT  47.009 67.056 48.308 67.08 ;
     RECT  48.121 71.712 48.308 93.624 ;
     RECT  47.761 95.136 48.308 95.976 ;
     RECT  48.308 2.148 48.412 96.672 ;
     RECT  48.412 2.418 48.5 96.672 ;
     RECT  48.5 2.418 48.604 96.942 ;
     RECT  48.604 71.712 48.773 75.192 ;
     RECT  48.604 9.648 48.881 37.992 ;
     RECT  48.773 72.528 48.881 75.192 ;
     RECT  48.881 9.648 48.892 15.288 ;
     RECT  48.604 38.976 48.917 39 ;
     RECT  48.604 44.976 48.953 58.152 ;
     RECT  48.881 73.392 48.995 75.192 ;
     RECT  48.604 95.712 49.043 96.36 ;
     RECT  48.953 45.504 49.097 58.152 ;
     RECT  48.604 76.368 49.097 94.728 ;
     RECT  49.043 95.712 49.241 95.976 ;
     RECT  48.604 40.416 49.277 40.776 ;
     RECT  49.097 76.608 49.601 94.728 ;
     RECT  48.604 59.712 49.633 62.184 ;
     RECT  49.601 76.848 49.633 94.728 ;
     RECT  49.241 95.712 49.633 95.736 ;
     RECT  48.892 9.84 49.637 15.288 ;
     RECT  48.604 41.76 49.669 43.848 ;
     RECT  49.633 76.848 49.673 95.736 ;
     RECT  49.669 41.76 49.745 44.472 ;
     RECT  49.745 41.76 49.781 41.784 ;
     RECT  49.097 45.504 49.781 57.576 ;
     RECT  49.673 76.848 49.853 95.64 ;
     RECT  48.881 16.32 49.859 37.992 ;
     RECT  49.745 42.816 49.907 44.472 ;
     RECT  49.907 43.824 49.997 44.472 ;
     RECT  49.633 58.752 50.003 62.184 ;
     RECT  49.637 10.416 50.065 15.288 ;
     RECT  49.859 16.32 50.065 34.44 ;
     RECT  49.997 44.448 50.101 44.472 ;
     RECT  49.781 45.504 50.101 46.968 ;
     RECT  48.995 74.112 50.101 75.192 ;
     RECT  49.957 39.504 50.245 39.528 ;
     RECT  48.604 8.16 50.461 8.184 ;
     RECT  49.781 47.952 50.533 57.576 ;
     RECT  50.003 58.752 50.533 61.704 ;
     RECT  50.101 74.112 50.641 75.288 ;
     RECT  50.641 74.112 50.677 75.528 ;
     RECT  49.859 35.424 50.785 37.992 ;
     RECT  50.245 39.36 50.785 39.528 ;
     RECT  50.461 8.16 50.821 8.712 ;
     RECT  50.677 74.112 50.849 76.488 ;
     RECT  50.065 10.416 50.869 34.44 ;
     RECT  50.785 35.424 50.869 38.232 ;
     RECT  50.101 44.448 50.869 46.968 ;
     RECT  50.533 47.952 50.869 61.704 ;
     RECT  50.849 73.392 50.869 76.488 ;
     RECT  49.853 77.568 50.869 95.64 ;
     RECT  50.821 7.92 51.008 8.712 ;
     RECT  50.869 10.416 51.008 38.232 ;
     RECT  50.785 39.36 51.008 39.768 ;
     RECT  49.277 40.752 51.008 40.776 ;
     RECT  49.907 42.816 51.008 42.84 ;
     RECT  50.869 44.448 51.008 61.704 ;
     RECT  50.785 62.832 51.008 62.856 ;
     RECT  48.604 67.056 51.008 67.08 ;
     RECT  49.921 72.24 51.008 72.264 ;
     RECT  50.869 73.392 51.008 95.64 ;
     RECT  51.008 2.148 51.112 96.672 ;
     RECT  51.112 2.418 51.2 96.672 ;
     RECT  51.2 2.418 51.304 96.942 ;
     RECT  51.304 44.88 51.365 44.904 ;
     RECT  51.304 75.024 51.473 85.752 ;
     RECT  51.304 86.784 51.473 95.16 ;
     RECT  51.304 46.656 51.617 58.776 ;
     RECT  51.473 75.024 51.905 75.24 ;
     RECT  51.473 76.32 51.905 85.752 ;
     RECT  51.304 9.12 51.923 38.232 ;
     RECT  51.923 9.12 52.019 19.368 ;
     RECT  51.905 76.464 52.085 85.752 ;
     RECT  51.304 60.288 52.193 61.704 ;
     RECT  52.193 60.288 52.211 61.608 ;
     RECT  51.304 62.832 52.229 62.856 ;
     RECT  51.304 39.744 52.265 39.768 ;
     RECT  51.473 86.784 52.265 94.872 ;
     RECT  52.085 76.848 52.441 85.752 ;
     RECT  52.265 86.784 52.441 92.28 ;
     RECT  51.617 46.656 52.595 57.432 ;
     RECT  52.019 9.12 52.657 15.288 ;
     RECT  51.923 20.352 52.661 38.232 ;
     RECT  52.657 9.072 52.733 15.288 ;
     RECT  52.765 69.504 52.837 69.528 ;
     RECT  52.837 64.944 52.873 64.968 ;
     RECT  52.733 11.232 52.981 15.288 ;
     RECT  52.019 16.32 52.981 19.368 ;
     RECT  51.905 75.12 53.017 75.24 ;
     RECT  52.265 93.504 53.017 94.872 ;
     RECT  52.441 76.848 53.413 92.28 ;
     RECT  52.981 11.232 53.449 19.368 ;
     RECT  52.661 20.352 53.449 37.944 ;
     RECT  52.595 48.48 53.593 57.432 ;
     RECT  51.617 58.416 53.593 58.776 ;
     RECT  51.304 67.056 53.593 67.08 ;
     RECT  53.413 76.8 53.593 92.28 ;
     RECT  52.733 9.072 53.708 9.624 ;
     RECT  53.449 11.232 53.708 37.944 ;
     RECT  52.595 46.8 53.708 47.16 ;
     RECT  53.593 48.48 53.708 58.776 ;
     RECT  52.211 60.288 53.708 61.464 ;
     RECT  52.873 64.944 53.708 65.736 ;
     RECT  53.593 67.056 53.708 67.656 ;
     RECT  52.837 68.736 53.708 69.528 ;
     RECT  53.017 75.12 53.708 75.528 ;
     RECT  53.593 76.8 53.708 92.52 ;
     RECT  53.017 93.504 53.708 95.208 ;
     RECT  52.513 96.48 53.708 96.504 ;
     RECT  53.708 2.148 53.812 96.672 ;
     RECT  53.812 2.418 53.9 96.672 ;
     RECT  53.9 2.418 54.004 96.942 ;
     RECT  54.004 48.72 54.101 54.888 ;
     RECT  54.004 11.232 54.131 37.944 ;
     RECT  54.004 60 54.131 60.12 ;
     RECT  54.131 60 54.137 60.024 ;
     RECT  54.101 48.72 54.173 51.96 ;
     RECT  54.004 55.968 54.173 58.44 ;
     RECT  54.131 11.712 54.245 37.944 ;
     RECT  54.101 52.992 54.245 54.888 ;
     RECT  54.004 96.48 54.281 96.504 ;
     RECT  54.245 14.112 54.533 37.944 ;
     RECT  54.245 52.992 54.569 54.696 ;
     RECT  54.533 14.16 54.605 37.944 ;
     RECT  54.245 11.712 54.749 13.08 ;
     RECT  54.605 14.208 54.749 37.944 ;
     RECT  54.173 55.968 54.749 57.864 ;
     RECT  54.749 56.016 54.821 57.864 ;
     RECT  54.173 48.768 54.857 51.96 ;
     RECT  54.569 53.328 54.893 54.696 ;
     RECT  54.749 11.76 55.001 13.08 ;
     RECT  54.821 56.256 55.001 57.336 ;
     RECT  55.001 56.256 55.073 57.288 ;
     RECT  54.893 53.376 55.145 54.696 ;
     RECT  54.004 75.216 55.237 94.104 ;
     RECT  54.004 64.944 55.285 67.176 ;
     RECT  54.004 68.736 55.285 70.584 ;
     RECT  55.237 75.168 55.285 94.104 ;
     RECT  54.004 95.088 55.285 95.112 ;
     RECT  55.285 75.168 55.325 95.112 ;
     RECT  55.325 75.168 55.429 94.536 ;
     RECT  55.001 12.336 55.433 13.08 ;
     RECT  55.145 53.52 55.433 54.696 ;
     RECT  54.749 14.208 55.645 37.368 ;
     RECT  55.433 13.056 56.408 13.08 ;
     RECT  55.645 14.16 56.408 37.368 ;
     RECT  54.004 46.8 56.408 46.824 ;
     RECT  54.857 48.768 56.408 48.792 ;
     RECT  54.857 49.824 56.408 51.96 ;
     RECT  55.433 53.52 56.408 54.216 ;
     RECT  55.073 56.256 56.408 57.24 ;
     RECT  55.285 64.944 56.408 70.584 ;
     RECT  55.429 75.12 56.408 94.536 ;
     RECT  55.501 95.712 56.408 95.736 ;
     RECT  56.408 2.148 56.512 96.672 ;
     RECT  56.512 2.418 56.6 96.672 ;
     RECT  56.6 2.418 56.704 96.942 ;
     RECT  56.704 14.448 56.873 36.84 ;
     RECT  56.704 76.752 57.059 94.584 ;
     RECT  56.704 48.768 57.305 51.96 ;
     RECT  56.873 14.928 57.593 36.84 ;
     RECT  57.059 76.752 57.593 94.44 ;
     RECT  56.704 75.12 57.733 75.768 ;
     RECT  57.593 76.752 57.733 94.392 ;
     RECT  57.733 75.12 57.827 94.392 ;
     RECT  58.129 55.776 58.201 55.8 ;
     RECT  58.201 55.776 58.705 56.04 ;
     RECT  57.593 15.264 58.741 36.84 ;
     RECT  58.741 15.216 59.108 36.84 ;
     RECT  57.305 48.768 59.108 48.792 ;
     RECT  57.305 50.352 59.108 51.96 ;
     RECT  56.704 53.52 59.108 54.216 ;
     RECT  58.705 55.584 59.108 57.192 ;
     RECT  56.704 64.944 59.108 70.584 ;
     RECT  57.827 75.12 59.108 75.768 ;
     RECT  57.827 77.232 59.108 94.392 ;
     RECT  59.108 2.148 59.212 96.672 ;
     RECT  59.212 2.418 59.3 96.672 ;
     RECT  59.3 2.418 59.404 96.942 ;
     RECT  59.404 18.72 59.465 19.368 ;
     RECT  59.465 19.344 59.501 19.368 ;
     RECT  59.404 22.32 59.501 22.344 ;
     RECT  59.404 76.752 59.789 94.104 ;
     RECT  59.789 77.328 59.825 94.104 ;
     RECT  59.825 77.616 59.933 94.104 ;
     RECT  59.404 31.104 60.005 36.84 ;
     RECT  59.933 77.616 60.005 94.008 ;
     RECT  59.404 23.568 60.433 30.072 ;
     RECT  60.397 21.12 60.469 21.144 ;
     RECT  60.469 21.12 60.505 21.432 ;
     RECT  60.505 20.496 60.541 21.528 ;
     RECT  60.541 20.496 60.649 21.912 ;
     RECT  60.649 19.632 60.685 21.912 ;
     RECT  60.685 18.96 60.757 21.912 ;
     RECT  60.433 23.376 60.757 30.072 ;
     RECT  59.404 17.712 60.793 17.736 ;
     RECT  60.757 18.96 60.793 30.072 ;
     RECT  59.404 16.032 60.901 16.056 ;
     RECT  60.793 17.712 60.901 30.072 ;
     RECT  60.005 77.616 61.441 93.96 ;
     RECT  61.441 77.616 61.585 94.056 ;
     RECT  59.404 48.768 61.729 48.792 ;
     RECT  59.404 53.52 61.729 54.216 ;
     RECT  61.585 77.616 61.729 94.872 ;
     RECT  60.901 16.032 61.808 30.072 ;
     RECT  60.005 31.104 61.808 32.328 ;
     RECT  60.005 33.312 61.808 36.84 ;
     RECT  61.729 48.432 61.808 48.792 ;
     RECT  59.404 50.352 61.808 52.008 ;
     RECT  61.729 53.52 61.808 54.936 ;
     RECT  59.404 64.944 61.808 70.584 ;
     RECT  61.729 77.616 61.808 94.968 ;
     RECT  61.808 2.148 61.912 96.672 ;
     RECT  61.912 2.418 62 96.672 ;
     RECT  62 2.418 62.104 96.942 ;
     RECT  62.104 77.616 62.129 93.768 ;
     RECT  62.104 15.984 62.165 38.184 ;
     RECT  62.165 16.032 62.345 38.184 ;
     RECT  62.104 94.848 62.345 94.968 ;
     RECT  62.345 94.848 62.561 94.872 ;
     RECT  62.129 77.616 62.705 93.624 ;
     RECT  62.104 64.752 62.741 70.584 ;
     RECT  62.345 20.496 63.277 38.184 ;
     RECT  62.104 48.336 63.313 57.384 ;
     RECT  62.345 16.032 63.853 19.08 ;
     RECT  63.277 20.496 63.853 38.28 ;
     RECT  63.277 61.392 63.853 61.608 ;
     RECT  62.741 64.752 63.853 70.536 ;
     RECT  62.705 77.616 63.853 92.712 ;
     RECT  63.853 77.52 63.997 92.712 ;
     RECT  63.853 16.032 64.109 38.28 ;
     RECT  64.109 16.08 64.716 38.28 ;
     RECT  63.313 48.336 64.716 57.48 ;
     RECT  63.853 61.392 64.716 61.704 ;
     RECT  63.853 64.464 64.716 70.536 ;
     RECT  63.997 77.52 64.716 92.808 ;
     RECT  64.716 21.408 64.757 21.528 ;
     RECT  64.716 25.728 64.757 26.136 ;
     RECT  64.716 27.744 64.757 27.768 ;
     RECT  64.716 31.776 64.757 31.8 ;
     RECT  64.716 33.312 64.757 33.336 ;
     RECT  64.716 48.768 64.757 48.792 ;
     RECT  64.716 65.664 64.757 65.688 ;
     RECT  64.716 69.984 64.757 70.008 ;
     RECT  64.716 82.56 64.757 82.968 ;
     RECT  64.716 87.936 64.757 88.248 ;
     RECT  64.716 90.24 64.757 90.264 ;
    LAYER M5 ;
     RECT  2.4 2.137 2.52 2.151 ;
     RECT  5.1 2.137 5.22 2.151 ;
     RECT  7.8 2.137 7.92 2.151 ;
     RECT  10.5 2.137 10.62 2.151 ;
     RECT  13.2 2.137 13.32 2.151 ;
     RECT  15.9 2.137 16.02 2.151 ;
     RECT  18.6 2.137 18.72 2.151 ;
     RECT  21.3 2.137 21.42 2.151 ;
     RECT  24 2.137 24.12 2.151 ;
     RECT  26.7 2.137 26.82 2.151 ;
     RECT  29.4 2.137 29.52 2.151 ;
     RECT  32.1 2.137 32.22 2.151 ;
     RECT  34.8 2.137 34.92 2.151 ;
     RECT  37.5 2.137 37.62 2.151 ;
     RECT  40.2 2.137 40.32 2.151 ;
     RECT  42.9 2.137 43.02 2.151 ;
     RECT  45.6 2.137 45.72 2.151 ;
     RECT  48.3 2.137 48.42 2.151 ;
     RECT  51 2.137 51.12 2.151 ;
     RECT  53.7 2.137 53.82 2.151 ;
     RECT  56.4 2.137 56.52 2.151 ;
     RECT  59.1 2.137 59.22 2.151 ;
     RECT  61.8 2.137 61.92 2.151 ;
     RECT  29.4 2.151 29.712 6.229 ;
     RECT  24 2.151 24.312 6.709 ;
     RECT  26.7 2.151 27.012 6.805 ;
     RECT  32.1 2.151 32.412 6.805 ;
     RECT  34.8 2.151 35.112 6.805 ;
     RECT  31.968 6.805 32.412 6.947 ;
     RECT  24 6.709 24.648 7.189 ;
     RECT  51 2.151 51.312 7.909 ;
     RECT  34.8 6.805 35.352 8.149 ;
     RECT  24 7.189 25.032 8.531 ;
     RECT  30.72 7.909 30.744 8.579 ;
     RECT  32.1 6.947 32.412 8.965 ;
     RECT  26.16 6.805 27.012 9.061 ;
     RECT  42.9 2.151 43.212 9.253 ;
     RECT  38.976 7.381 39 9.349 ;
     RECT  38.832 9.349 39 9.395 ;
     RECT  5.1 2.151 5.412 9.541 ;
     RECT  48.3 2.151 48.612 9.637 ;
     RECT  34.8 8.149 36.216 9.731 ;
     RECT  28.896 6.229 29.712 9.733 ;
     RECT  41.616 9.061 41.64 9.779 ;
     RECT  32.1 8.965 32.568 9.781 ;
     RECT  25.632 9.061 27.012 10.067 ;
     RECT  21.3 2.151 21.612 10.069 ;
     RECT  4.848 9.541 5.412 10.163 ;
     RECT  2.4 2.151 2.712 10.213 ;
     RECT  28.464 9.733 29.712 10.307 ;
     RECT  37.5 2.151 37.812 10.309 ;
     RECT  38.832 9.395 38.856 10.309 ;
     RECT  20.976 10.069 21.612 10.355 ;
     RECT  31.584 9.781 32.568 10.355 ;
     RECT  42.9 9.253 43.656 10.357 ;
     RECT  37.5 10.309 38.856 10.403 ;
     RECT  15.9 2.151 16.212 10.501 ;
     RECT  31.584 10.355 32.412 10.789 ;
     RECT  18.6 2.151 18.912 10.837 ;
     RECT  34.8 9.731 36.168 10.883 ;
     RECT  48.3 9.637 48.84 10.931 ;
     RECT  2.304 10.213 2.712 10.979 ;
     RECT  21.072 10.355 21.612 11.171 ;
     RECT  53.7 2.151 54.012 11.221 ;
     RECT  18.6 10.837 19.032 11.365 ;
     RECT  26.7 10.067 27.012 11.365 ;
     RECT  42.9 10.357 43.752 11.365 ;
     RECT  52.416 10.453 52.44 11.411 ;
     RECT  25.632 10.067 25.656 11.413 ;
     RECT  26.7 11.365 27.384 11.413 ;
     RECT  15.9 10.501 16.824 11.459 ;
     RECT  25.632 11.413 27.384 11.555 ;
     RECT  50.88 7.909 51.312 11.653 ;
     RECT  26.7 11.555 27.384 11.749 ;
     RECT  28.896 10.307 29.712 11.749 ;
     RECT  53.7 11.221 54.12 11.749 ;
     RECT  48.3 10.931 48.612 11.941 ;
     RECT  42.096 11.365 43.752 11.987 ;
     RECT  18.48 11.365 19.032 12.035 ;
     RECT  53.7 11.749 54.696 12.035 ;
     RECT  7.8 2.151 8.112 12.085 ;
     RECT  18.6 12.035 19.032 12.467 ;
     RECT  15.9 11.459 16.584 12.517 ;
     RECT  34.8 10.883 35.112 12.517 ;
     RECT  36.144 10.883 36.168 12.517 ;
     RECT  42.096 11.987 43.656 12.517 ;
     RECT  53.7 12.035 54.12 12.517 ;
     RECT  50.688 11.653 51.312 12.563 ;
     RECT  26.7 11.749 29.712 12.755 ;
     RECT  30.912 10.789 32.412 12.803 ;
     RECT  5.1 10.163 5.412 12.805 ;
     RECT  22.752 12.613 22.776 12.949 ;
     RECT  37.5 10.403 38.184 12.997 ;
     RECT  24 8.531 24.312 13.093 ;
     RECT  25.632 11.555 25.656 13.093 ;
     RECT  45.6 2.151 45.912 13.093 ;
     RECT  48.3 11.941 48.792 13.139 ;
     RECT  14.736 12.901 14.76 13.141 ;
     RECT  4.944 12.805 5.412 13.285 ;
     RECT  24 13.093 25.656 13.331 ;
     RECT  13.2 2.151 13.512 13.333 ;
     RECT  14.544 13.141 14.76 13.333 ;
     RECT  15.9 12.517 16.824 13.333 ;
     RECT  31.872 12.803 32.412 13.475 ;
     RECT  53.568 12.517 54.12 13.525 ;
     RECT  7.8 12.085 8.232 13.571 ;
     RECT  22.704 12.949 22.776 13.571 ;
     RECT  25.632 13.331 25.656 13.763 ;
     RECT  41.808 12.517 43.656 13.763 ;
     RECT  4.944 13.285 5.544 14.053 ;
     RECT  3.984 14.053 5.544 14.099 ;
     RECT  26.7 12.755 27.012 14.101 ;
     RECT  51 12.563 51.312 14.197 ;
     RECT  45.6 13.093 46.44 14.341 ;
     RECT  13.2 13.333 16.824 14.435 ;
     RECT  14.544 14.435 16.824 14.675 ;
     RECT  41.808 13.763 41.832 14.773 ;
     RECT  51 14.197 51.432 14.773 ;
     RECT  19.92 13.333 19.944 14.867 ;
     RECT  22.752 13.571 22.776 14.867 ;
     RECT  28.08 12.755 29.712 14.867 ;
     RECT  5.1 14.099 5.544 14.915 ;
     RECT  14.88 14.675 16.824 14.915 ;
     RECT  34.8 12.517 36.168 14.915 ;
     RECT  52.992 13.525 54.12 14.965 ;
     RECT  55.248 12.517 55.272 14.965 ;
     RECT  3.984 14.099 4.104 15.349 ;
     RECT  5.1 14.915 5.412 15.349 ;
     RECT  52.992 14.965 55.272 15.349 ;
     RECT  56.4 2.151 56.712 15.349 ;
     RECT  3.984 15.349 5.412 15.395 ;
     RECT  15.9 14.915 16.824 15.443 ;
     RECT  40.2 2.151 40.512 15.445 ;
     RECT  41.808 14.773 41.88 15.445 ;
     RECT  25.968 14.101 27.012 15.491 ;
     RECT  45.6 14.341 47.16 15.491 ;
     RECT  40.2 15.445 41.88 15.731 ;
     RECT  42.9 13.763 43.656 15.731 ;
     RECT  24 13.331 24.312 15.829 ;
     RECT  52.992 15.349 56.712 15.829 ;
     RECT  45.6 15.491 46.44 15.877 ;
     RECT  13.2 14.435 13.512 15.973 ;
     RECT  14.88 14.915 14.904 15.973 ;
     RECT  31.968 13.475 32.412 16.067 ;
     RECT  36.144 14.915 36.168 16.117 ;
     RECT  37.5 12.997 38.472 16.117 ;
     RECT  36.144 16.117 38.472 16.163 ;
     RECT  13.2 15.973 14.904 16.261 ;
     RECT  15.9 15.443 16.212 16.261 ;
     RECT  52.992 15.829 57.432 16.451 ;
     RECT  55.056 16.451 57.432 16.453 ;
     RECT  51 14.773 52.008 16.547 ;
     RECT  44.976 15.877 46.44 16.549 ;
     RECT  36.96 16.163 38.472 16.595 ;
     RECT  52.992 16.451 54.012 16.787 ;
     RECT  2.4 10.979 2.712 16.789 ;
     RECT  4.224 15.395 5.412 16.789 ;
     RECT  51 16.547 51.432 16.885 ;
     RECT  48.3 13.139 48.744 17.077 ;
     RECT  40.2 15.731 41.064 17.171 ;
     RECT  44.976 16.549 46.968 17.171 ;
     RECT  48.3 17.077 49.128 17.219 ;
     RECT  24 15.829 24.408 17.365 ;
     RECT  24 17.365 25.032 17.509 ;
     RECT  26.592 15.491 27.012 17.509 ;
     RECT  24 17.509 27.012 17.603 ;
     RECT  32.1 16.067 32.412 17.605 ;
     RECT  45.6 17.171 46.968 17.699 ;
     RECT  55.056 16.453 57.624 17.699 ;
     RECT  2.4 16.789 5.412 17.843 ;
     RECT  18.6 12.467 18.912 17.845 ;
     RECT  33.456 16.021 33.48 17.939 ;
     RECT  2.4 17.843 2.904 17.987 ;
     RECT  55.056 17.699 57.432 18.035 ;
     RECT  21.3 11.171 21.612 18.133 ;
     RECT  24 17.603 24.408 18.179 ;
     RECT  13.2 16.261 16.212 18.275 ;
     RECT  53.376 16.787 54.012 18.275 ;
     RECT  14.928 18.275 16.212 18.469 ;
     RECT  17.328 18.421 17.352 18.469 ;
     RECT  18.6 17.845 19.368 18.757 ;
     RECT  48.3 17.219 48.612 18.757 ;
     RECT  50.256 16.885 51.432 18.757 ;
     RECT  31.008 17.605 32.412 18.947 ;
     RECT  59.1 2.151 59.412 18.997 ;
     RECT  53.7 18.275 54.012 19.093 ;
     RECT  55.056 18.035 56.712 19.093 ;
     RECT  31.392 18.947 32.412 19.333 ;
     RECT  36.96 16.595 37.812 19.381 ;
     RECT  36.864 19.381 37.812 19.523 ;
     RECT  25.872 17.603 27.012 19.525 ;
     RECT  18.48 18.757 19.368 19.571 ;
     RECT  48.3 18.757 51.432 19.621 ;
     RECT  31.392 19.333 32.904 19.811 ;
     RECT  7.8 13.571 8.112 19.813 ;
     RECT  6.816 19.813 8.112 19.955 ;
     RECT  44.4 19.141 44.424 19.955 ;
     RECT  18.6 19.571 19.368 20.003 ;
     RECT  21.12 18.133 21.612 20.003 ;
     RECT  25.872 19.525 27.144 20.003 ;
     RECT  58.512 18.997 59.412 20.003 ;
     RECT  42.9 15.731 43.32 20.053 ;
     RECT  14.928 18.469 17.352 20.099 ;
     RECT  34.8 14.915 35.112 20.197 ;
     RECT  25.872 20.003 27.012 20.291 ;
     RECT  0.144 20.101 0.168 20.387 ;
     RECT  24 18.179 24.312 20.485 ;
     RECT  61.8 2.151 62.112 20.485 ;
     RECT  41.616 18.181 41.64 20.531 ;
     RECT  48.3 19.621 51.912 20.531 ;
     RECT  31.392 19.811 32.412 20.579 ;
     RECT  37.392 19.523 37.812 20.773 ;
     RECT  53.7 19.093 56.712 20.963 ;
     RECT  55.056 20.963 56.712 20.965 ;
     RECT  61.008 20.485 62.112 21.011 ;
     RECT  32.1 20.579 32.412 21.061 ;
     RECT  21.3 20.003 21.612 21.109 ;
     RECT  4.224 17.843 5.412 21.397 ;
     RECT  18.6 20.003 18.912 21.397 ;
     RECT  42.768 20.053 43.32 21.443 ;
     RECT  15.9 20.099 17.352 21.493 ;
     RECT  26.7 20.291 27.012 21.493 ;
     RECT  28.224 14.867 29.712 21.493 ;
     RECT  34.272 20.197 35.112 21.683 ;
     RECT  20.928 21.109 21.612 21.923 ;
     RECT  23.616 20.485 24.312 22.163 ;
     RECT  55.056 20.965 56.856 22.165 ;
     RECT  10.5 2.151 10.812 22.261 ;
     RECT  12 20.149 12.024 22.261 ;
     RECT  32.1 21.061 33.048 22.307 ;
     RECT  55.056 22.165 56.952 22.403 ;
     RECT  4.224 21.397 5.736 22.499 ;
     RECT  26.7 21.493 29.712 22.499 ;
     RECT  31.008 21.397 31.032 22.549 ;
     RECT  42.768 21.443 43.212 22.597 ;
     RECT  18.6 21.397 19.704 22.739 ;
     RECT  24 22.163 24.312 22.741 ;
     RECT  37.296 20.773 37.812 22.741 ;
     RECT  53.7 20.963 54.012 22.741 ;
     RECT  59.1 20.003 59.412 22.741 ;
     RECT  10.5 22.261 12.024 22.931 ;
     RECT  42.768 22.597 43.32 22.979 ;
     RECT  18.6 22.739 19.416 23.027 ;
     RECT  55.248 22.403 56.952 23.075 ;
     RECT  30.768 22.549 31.032 23.125 ;
     RECT  32.1 22.307 32.412 23.125 ;
     RECT  10.5 22.931 11.4 23.317 ;
     RECT  13.2 18.275 13.512 23.317 ;
     RECT  52.704 23.029 52.728 23.317 ;
     RECT  53.7 22.741 54.12 23.317 ;
     RECT  24 22.741 24.984 23.603 ;
     RECT  4.944 22.499 5.736 23.651 ;
     RECT  15.792 21.493 17.352 23.845 ;
     RECT  45.6 17.699 46.44 23.893 ;
     RECT  55.248 23.075 55.272 24.035 ;
     RECT  42.768 22.979 43.212 24.037 ;
     RECT  21.072 21.923 21.612 24.131 ;
     RECT  52.704 23.317 54.12 24.181 ;
     RECT  58.848 22.741 59.412 24.229 ;
     RECT  22.8 23.557 22.824 24.325 ;
     RECT  24 23.603 24.312 24.325 ;
     RECT  28.224 22.499 29.712 24.371 ;
     RECT  30.768 23.125 32.412 24.419 ;
     RECT  15.408 23.845 17.352 24.467 ;
     RECT  28.32 24.371 29.712 24.467 ;
     RECT  52.704 24.181 54.744 24.469 ;
     RECT  12.816 23.317 13.512 24.563 ;
     RECT  36.432 22.741 37.812 24.563 ;
     RECT  31.296 24.419 32.412 24.611 ;
     RECT  37.5 24.563 37.812 24.613 ;
     RECT  38.784 22.789 38.808 24.613 ;
     RECT  31.632 24.611 32.412 24.659 ;
     RECT  18.6 23.027 18.912 24.709 ;
     RECT  15.408 24.467 17.064 24.755 ;
     RECT  56.4 23.075 56.952 24.757 ;
     RECT  13.104 24.563 13.512 24.851 ;
     RECT  13.2 24.851 13.512 24.901 ;
     RECT  15.408 24.755 16.584 24.947 ;
     RECT  37.5 24.613 38.808 24.947 ;
     RECT  10.08 23.317 11.4 24.997 ;
     RECT  52.416 24.469 54.744 24.997 ;
     RECT  15.552 24.947 16.584 25.043 ;
     RECT  42.144 24.037 43.212 25.045 ;
     RECT  22.8 24.325 24.312 25.091 ;
     RECT  45.6 23.893 46.776 25.091 ;
     RECT  38.784 24.947 38.808 25.139 ;
     RECT  52.416 24.997 55.08 25.139 ;
     RECT  52.464 25.139 55.08 25.283 ;
     RECT  4.944 23.651 5.412 25.525 ;
     RECT  56.4 24.757 57 25.571 ;
     RECT  0.192 25.429 0.216 25.619 ;
     RECT  18.6 24.709 19.656 25.667 ;
     RECT  18.6 25.667 19.56 25.763 ;
     RECT  52.464 25.283 54.744 25.763 ;
     RECT  48.3 20.531 51.312 25.811 ;
     RECT  58.656 24.229 59.412 25.861 ;
     RECT  42.144 25.045 43.32 26.003 ;
     RECT  50.592 25.811 51.312 26.099 ;
     RECT  45.6 25.091 46.44 26.197 ;
     RECT  4.944 25.525 5.544 26.243 ;
     RECT  10.08 24.997 11.448 26.243 ;
     RECT  15.552 25.043 16.212 26.243 ;
     RECT  21.168 24.131 21.612 26.243 ;
     RECT  52.704 25.763 54.744 26.243 ;
     RECT  34.8 21.683 35.112 26.245 ;
     RECT  36.432 24.563 36.456 26.531 ;
     RECT  56.4 25.571 56.856 26.533 ;
     RECT  58.608 25.861 59.412 26.579 ;
     RECT  56.016 26.533 56.856 26.675 ;
     RECT  23.328 25.091 24.312 26.819 ;
     RECT  42.9 26.003 43.32 26.819 ;
     RECT  45.024 26.197 46.44 26.819 ;
     RECT  58.656 26.579 59.412 26.819 ;
     RECT  4.992 26.243 5.544 26.867 ;
     RECT  52.704 26.243 54.168 26.915 ;
     RECT  34.32 26.245 35.112 27.059 ;
     RECT  13.2 24.901 14.232 27.157 ;
     RECT  4.992 26.867 5.412 27.205 ;
     RECT  52.704 26.915 54.012 27.491 ;
     RECT  37.5 24.947 37.812 27.877 ;
     RECT  56.4 26.675 56.856 27.877 ;
     RECT  55.536 27.877 57.384 27.973 ;
     RECT  59.1 26.819 59.412 27.973 ;
     RECT  15.9 26.243 16.212 28.165 ;
     RECT  15.9 28.165 17.16 28.355 ;
     RECT  48.3 25.811 49.512 28.403 ;
     RECT  32.1 24.659 32.412 28.405 ;
     RECT  21.3 26.243 21.612 28.453 ;
     RECT  45.6 26.819 46.44 28.547 ;
     RECT  55.536 27.973 59.412 28.691 ;
     RECT  23.568 26.819 24.312 28.789 ;
     RECT  37.5 27.877 38.232 28.789 ;
     RECT  42.9 26.819 43.212 28.789 ;
     RECT  44.304 27.301 44.328 28.789 ;
     RECT  4.896 27.205 5.412 28.837 ;
     RECT  53.7 27.491 54.012 28.933 ;
     RECT  4.8 28.837 5.412 28.979 ;
     RECT  56.4 28.691 59.412 28.979 ;
     RECT  13.104 27.157 14.232 29.027 ;
     RECT  4.896 28.979 5.412 29.123 ;
     RECT  52.704 27.491 52.728 29.269 ;
     RECT  31.536 28.405 32.412 29.413 ;
     RECT  42.9 28.789 44.328 29.459 ;
     RECT  6.624 25.717 6.648 29.555 ;
     RECT  34.8 27.059 35.112 29.605 ;
     RECT  37.056 28.789 38.232 29.605 ;
     RECT  58.128 28.979 59.412 29.651 ;
     RECT  10.5 26.243 11.448 29.653 ;
     RECT  53.7 28.933 55.272 29.699 ;
     RECT  10.224 29.653 11.448 29.749 ;
     RECT  21.3 28.453 21.912 29.795 ;
     RECT  28.32 24.467 28.344 29.797 ;
     RECT  29.4 24.467 29.712 29.797 ;
     RECT  37.056 29.605 38.616 30.035 ;
     RECT  18.6 25.763 18.912 30.037 ;
     RECT  9.36 29.749 11.448 30.083 ;
     RECT  13.2 29.027 14.232 30.133 ;
     RECT  37.296 30.035 38.616 30.275 ;
     RECT  52.464 29.269 52.728 30.275 ;
     RECT  55.248 29.699 55.272 30.325 ;
     RECT  56.4 28.979 56.712 30.325 ;
     RECT  52.704 30.275 52.728 30.371 ;
     RECT  48.3 28.403 49.368 30.373 ;
     RECT  12.528 30.133 14.232 30.611 ;
     RECT  55.248 30.325 56.712 30.611 ;
     RECT  53.7 29.699 54.216 30.613 ;
     RECT  3.984 30.229 4.008 30.755 ;
     RECT  7.8 19.955 8.112 30.757 ;
     RECT  10.224 30.083 11.448 30.851 ;
     RECT  55.68 30.611 56.712 30.851 ;
     RECT  6.816 30.757 8.112 30.899 ;
     RECT  34.8 29.605 35.352 30.949 ;
     RECT  64.608 30.757 64.632 31.139 ;
     RECT  42.9 29.459 44.28 31.237 ;
     RECT  31.44 29.413 32.412 31.285 ;
     RECT  53.04 30.613 54.216 31.667 ;
     RECT  18.6 30.037 19.704 31.669 ;
     RECT  53.04 31.667 54.012 31.717 ;
     RECT  10.368 30.851 11.448 31.861 ;
     RECT  12.528 30.611 13.512 31.861 ;
     RECT  48.3 30.373 49.944 31.861 ;
     RECT  51 26.099 51.312 31.861 ;
     RECT  52.992 31.717 54.012 31.907 ;
     RECT  2.4 17.987 2.712 32.053 ;
     RECT  23.04 28.789 24.312 32.149 ;
     RECT  26.7 22.499 27.012 32.197 ;
     RECT  15.9 28.355 16.212 32.245 ;
     RECT  42.9 31.237 44.376 32.291 ;
     RECT  21.3 29.795 21.612 32.341 ;
     RECT  7.8 30.899 8.112 32.437 ;
     RECT  10.368 31.861 13.512 32.437 ;
     RECT  45.6 28.547 45.912 32.437 ;
     RECT  28.32 29.797 29.712 32.531 ;
     RECT  10.272 32.437 13.512 32.579 ;
     RECT  48.3 31.861 51.312 32.581 ;
     RECT  31.2 31.285 32.412 32.723 ;
     RECT  26.544 32.197 27.012 32.725 ;
     RECT  34.8 30.949 35.976 32.725 ;
     RECT  37.296 30.275 38.088 32.725 ;
     RECT  18.48 31.669 19.704 32.773 ;
     RECT  18.48 32.773 19.848 32.915 ;
     RECT  17.328 31.525 17.352 32.963 ;
     RECT  34.8 32.725 38.088 33.011 ;
     RECT  18.48 32.915 18.912 33.059 ;
     RECT  21.168 32.341 21.612 33.059 ;
     RECT  26.544 32.725 27.144 33.059 ;
     RECT  26.544 33.059 27.012 33.061 ;
     RECT  45.6 32.437 46.824 33.061 ;
     RECT  15.648 32.245 16.212 33.107 ;
     RECT  22.944 32.149 24.312 33.107 ;
     RECT  25.632 33.061 27.012 33.107 ;
     RECT  44.208 32.291 44.376 33.107 ;
     RECT  40.2 17.171 40.512 33.301 ;
     RECT  36.384 33.011 38.088 33.347 ;
     RECT  45.6 33.061 46.92 33.349 ;
     RECT  48.096 32.581 51.312 33.541 ;
     RECT  45.6 33.349 47.016 33.587 ;
     RECT  53.088 31.907 54.012 33.589 ;
     RECT  10.272 32.579 10.812 33.683 ;
     RECT  25.632 33.107 25.656 33.683 ;
     RECT  46.992 33.587 47.016 33.683 ;
     RECT  48.096 33.541 51.432 33.683 ;
     RECT  12.336 32.579 13.512 34.115 ;
     RECT  37.5 33.347 38.088 34.115 ;
     RECT  13.2 34.115 13.512 34.117 ;
     RECT  18.6 33.059 18.912 34.117 ;
     RECT  21.3 33.059 21.612 34.117 ;
     RECT  34.8 33.011 35.304 34.165 ;
     RECT  32.1 32.723 32.412 34.213 ;
     RECT  36.384 33.347 36.456 34.259 ;
     RECT  28.512 32.531 29.712 34.261 ;
     RECT  53.04 33.589 54.012 34.357 ;
     RECT  15.744 33.107 16.212 34.501 ;
     RECT  36.432 34.259 36.456 34.595 ;
     RECT  28.464 34.261 29.712 34.691 ;
     RECT  26.7 33.107 27.012 34.693 ;
     RECT  42.9 32.291 43.212 34.741 ;
     RECT  44.208 33.107 44.232 34.741 ;
     RECT  48.3 33.683 51.432 34.741 ;
     RECT  42.9 34.741 44.232 34.787 ;
     RECT  2.4 32.053 3.432 34.835 ;
     RECT  21.12 34.117 21.612 34.835 ;
     RECT  34.704 34.165 35.304 34.931 ;
     RECT  6.864 32.437 8.112 35.123 ;
     RECT  39.84 33.301 40.512 35.173 ;
     RECT  25.584 34.645 25.608 35.363 ;
     RECT  42.9 34.787 43.944 35.363 ;
     RECT  52.992 34.357 54.012 35.363 ;
     RECT  18.6 34.117 19.224 35.411 ;
     RECT  4.992 29.123 5.412 35.459 ;
     RECT  37.5 34.115 37.992 35.459 ;
     RECT  31.392 34.213 32.412 35.461 ;
     RECT  26.592 34.693 27.012 35.507 ;
     RECT  2.4 34.835 2.712 35.509 ;
     RECT  52.608 35.413 52.632 35.603 ;
     RECT  2.304 35.509 2.712 35.699 ;
     RECT  7.392 35.123 8.112 35.701 ;
     RECT  28.512 34.691 29.712 35.845 ;
     RECT  31.296 35.461 32.412 35.845 ;
     RECT  13.2 34.117 14.28 35.939 ;
     RECT  48.192 34.741 51.432 35.941 ;
     RECT  46.944 35.317 46.968 36.035 ;
     RECT  47.952 35.941 51.432 36.131 ;
     RECT  10.368 33.683 10.812 36.133 ;
     RECT  23.76 33.107 24.312 36.373 ;
     RECT  7.392 35.701 8.232 36.421 ;
     RECT  21.3 34.835 21.612 36.421 ;
     RECT  37.5 35.459 37.812 36.421 ;
     RECT  7.392 36.421 8.376 36.515 ;
     RECT  10.368 36.133 11.352 36.517 ;
     RECT  34.8 34.931 35.304 36.661 ;
     RECT  53.7 35.363 54.012 36.709 ;
     RECT  52.944 36.709 54.012 36.757 ;
     RECT  13.2 35.939 13.608 36.947 ;
     RECT  17.232 35.845 17.256 36.997 ;
     RECT  18.6 35.411 18.912 36.997 ;
     RECT  13.2 36.947 13.512 37.045 ;
     RECT  48.192 36.131 51.432 37.045 ;
     RECT  48.192 37.045 51.48 37.093 ;
     RECT  39.648 35.173 40.512 37.189 ;
     RECT  2.4 35.699 2.712 37.429 ;
     RECT  13.104 37.045 13.512 37.573 ;
     RECT  42.9 35.363 43.212 37.573 ;
     RECT  2.304 37.429 2.712 37.619 ;
     RECT  10.224 36.517 11.352 37.619 ;
     RECT  47.904 37.093 51.48 37.619 ;
     RECT  17.232 36.997 18.912 37.667 ;
     RECT  15.648 34.501 16.212 37.669 ;
     RECT  52.8 36.757 54.012 37.813 ;
     RECT  15.216 37.669 16.212 37.861 ;
     RECT  52.752 37.813 54.012 37.955 ;
     RECT  12.96 37.573 13.512 38.005 ;
     RECT  20.784 36.421 21.612 38.005 ;
     RECT  34.8 36.661 36.12 38.149 ;
     RECT  37.5 36.421 37.944 38.149 ;
     RECT  23.328 36.373 24.312 38.243 ;
     RECT  34.8 38.149 37.944 38.243 ;
     RECT  42.288 37.573 43.212 38.243 ;
     RECT  47.904 37.619 51.312 38.243 ;
     RECT  12.96 38.005 13.8 38.533 ;
     RECT  28.512 35.845 32.412 38.627 ;
     RECT  26.7 35.507 27.012 38.677 ;
     RECT  28.512 38.627 29.712 38.677 ;
     RECT  10.5 37.619 10.812 38.725 ;
     RECT  12.528 38.533 13.8 38.771 ;
     RECT  19.968 38.005 21.612 38.819 ;
     RECT  15.216 37.861 16.776 38.963 ;
     RECT  18.144 37.667 18.912 39.011 ;
     RECT  45.6 33.587 45.912 39.205 ;
     RECT  12.528 38.771 13.512 39.299 ;
     RECT  12.96 39.299 13.512 39.395 ;
     RECT  26.7 38.677 29.712 39.829 ;
     RECT  30.768 38.627 32.412 39.829 ;
     RECT  26.7 39.829 32.412 39.875 ;
     RECT  20.784 38.819 21.612 39.877 ;
     RECT  39.6 37.189 40.512 40.163 ;
     RECT  23.76 38.243 24.312 40.165 ;
     RECT  20.784 39.877 22.488 40.595 ;
     RECT  28.608 39.875 32.412 40.595 ;
     RECT  45.6 39.205 46.776 40.595 ;
     RECT  20.784 40.595 22.248 40.691 ;
     RECT  21.3 40.691 22.248 41.653 ;
     RECT  45.6 40.595 45.912 41.797 ;
     RECT  20.352 41.653 22.248 41.939 ;
     RECT  23.76 40.165 25.272 42.133 ;
     RECT  20.352 41.939 21.612 42.227 ;
     RECT  28.608 40.595 30.696 42.325 ;
     RECT  26.7 39.875 27.012 42.565 ;
     RECT  28.416 42.325 30.696 42.565 ;
     RECT  39.84 40.163 40.512 42.709 ;
     RECT  39.84 42.709 40.776 43.093 ;
     RECT  19.968 42.997 19.992 43.285 ;
     RECT  23.424 42.133 25.656 43.331 ;
     RECT  45.6 41.797 46.728 43.379 ;
     RECT  39.312 43.093 40.776 43.525 ;
     RECT  41.904 43.285 41.928 43.525 ;
     RECT  26.7 42.565 30.696 43.571 ;
     RECT  23.76 43.331 25.656 43.667 ;
     RECT  39.312 43.525 41.928 44.051 ;
     RECT  21.3 42.227 21.612 44.341 ;
     RECT  19.968 43.285 20.04 44.387 ;
     RECT  23.76 43.667 24.312 44.437 ;
     RECT  39.312 44.051 40.968 44.579 ;
     RECT  31.68 40.595 32.412 44.675 ;
     RECT  26.7 43.571 30.408 44.915 ;
     RECT  31.92 44.675 32.412 45.587 ;
     RECT  45.6 43.379 46.056 45.635 ;
     RECT  34.8 38.243 37.812 45.827 ;
     RECT  21.168 44.341 21.612 45.973 ;
     RECT  15.216 38.963 16.212 46.355 ;
     RECT  19.968 44.387 19.992 46.453 ;
     RECT  21.072 45.973 21.612 46.453 ;
     RECT  5.1 35.459 5.412 46.501 ;
     RECT  19.968 46.453 21.612 46.597 ;
     RECT  23.376 44.437 24.312 46.643 ;
     RECT  25.632 43.667 25.656 46.645 ;
     RECT  18.6 39.011 18.912 46.693 ;
     RECT  19.968 46.597 22.104 46.693 ;
     RECT  31.968 45.587 32.412 46.693 ;
     RECT  52.56 46.645 52.584 46.789 ;
     RECT  53.7 37.955 54.012 46.789 ;
     RECT  26.7 44.915 29.712 46.835 ;
     RECT  48.3 38.243 51.312 46.933 ;
     RECT  52.56 46.789 54.012 46.979 ;
     RECT  36.288 45.827 37.812 47.219 ;
     RECT  25.296 46.645 25.656 47.221 ;
     RECT  26.7 46.835 27.144 47.221 ;
     RECT  25.296 47.221 27.144 47.315 ;
     RECT  3.696 45.541 3.72 47.363 ;
     RECT  28.608 46.835 29.712 47.411 ;
     RECT  31.584 46.693 32.412 47.797 ;
     RECT  47.664 46.933 51.312 47.845 ;
     RECT  52.56 46.979 52.584 47.845 ;
     RECT  18.6 46.693 22.104 47.939 ;
     RECT  25.296 47.315 27.012 47.939 ;
     RECT  18.6 47.939 21.612 48.275 ;
     RECT  39.312 44.579 40.512 48.277 ;
     RECT  41.52 47.845 41.544 48.277 ;
     RECT  25.296 47.939 25.56 48.371 ;
     RECT  45.6 45.635 45.912 48.421 ;
     RECT  20.352 48.275 21.612 48.515 ;
     RECT  47.664 47.845 52.584 48.515 ;
     RECT  47.664 48.515 49.896 48.611 ;
     RECT  39.312 48.277 41.544 48.659 ;
     RECT  45.6 48.421 46.008 48.757 ;
     RECT  47.664 48.611 49.368 48.803 ;
     RECT  5.1 46.501 5.784 48.805 ;
     RECT  24 46.643 24.312 48.853 ;
     RECT  53.7 46.979 54.012 48.901 ;
     RECT  28.896 47.411 29.712 48.949 ;
     RECT  28.368 48.949 29.712 48.997 ;
     RECT  31.152 47.797 32.412 48.997 ;
     RECT  25.536 48.371 25.56 49.091 ;
     RECT  50.88 48.515 52.584 49.091 ;
     RECT  28.368 48.997 32.412 49.235 ;
     RECT  5.1 48.805 5.976 49.571 ;
     RECT  26.544 47.939 27.012 49.909 ;
     RECT  42.9 38.243 43.212 50.005 ;
     RECT  0.144 49.765 0.168 50.051 ;
     RECT  21.3 48.515 21.612 50.053 ;
     RECT  23.904 48.853 24.312 50.053 ;
     RECT  36.384 47.219 37.812 50.053 ;
     RECT  53.568 48.901 54.012 50.147 ;
     RECT  39.312 48.659 41.064 50.195 ;
     RECT  40.2 50.195 41.064 50.245 ;
     RECT  42.384 50.005 43.212 50.245 ;
     RECT  5.1 49.571 5.736 50.339 ;
     RECT  40.2 50.245 43.212 50.389 ;
     RECT  28.368 49.235 28.392 50.579 ;
     RECT  29.4 49.235 32.412 50.579 ;
     RECT  40.2 50.389 43.656 50.771 ;
     RECT  47.664 48.803 48.612 50.771 ;
     RECT  51 49.091 51.912 50.867 ;
     RECT  36.384 50.053 38.184 51.059 ;
     RECT  6.48 50.917 6.504 51.203 ;
     RECT  0.144 51.061 0.168 51.251 ;
     RECT  45.6 48.757 46.152 51.251 ;
     RECT  53.7 50.147 54.012 51.253 ;
     RECT  34.8 45.827 35.304 51.301 ;
     RECT  36.384 51.059 37.812 51.301 ;
     RECT  26.304 49.909 27.012 51.347 ;
     RECT  52.992 51.253 54.012 51.349 ;
     RECT  31.008 50.579 32.412 51.395 ;
     RECT  20.496 50.053 21.612 51.683 ;
     RECT  31.152 51.395 32.412 51.829 ;
     RECT  40.2 50.771 41.496 51.923 ;
     RECT  2.4 37.619 2.712 51.925 ;
     RECT  29.4 50.579 29.712 51.925 ;
     RECT  1.824 51.925 2.712 52.067 ;
     RECT  31.152 51.829 32.52 52.067 ;
     RECT  23.616 50.053 24.312 52.211 ;
     RECT  40.2 51.923 40.512 52.357 ;
     RECT  29.4 51.925 29.88 52.405 ;
     RECT  34.8 51.301 37.812 52.499 ;
     RECT  52.896 51.349 54.012 52.499 ;
     RECT  51 50.867 51.312 52.549 ;
     RECT  15.9 46.355 16.212 52.741 ;
     RECT  21.168 51.683 21.612 52.981 ;
     RECT  34.8 52.499 35.304 52.981 ;
     RECT  39.408 52.357 40.512 52.981 ;
     RECT  0.144 52.741 0.168 53.027 ;
     RECT  24 52.211 24.312 53.269 ;
     RECT  22.896 52.549 22.92 53.555 ;
     RECT  39.168 52.981 40.512 53.555 ;
     RECT  10.5 38.725 11.112 53.557 ;
     RECT  50.88 52.549 51.312 53.557 ;
     RECT  34.032 52.981 35.304 53.843 ;
     RECT  50.88 53.557 52.248 53.941 ;
     RECT  48.3 50.771 48.612 54.037 ;
     RECT  15.9 52.741 16.68 54.085 ;
     RECT  24 53.269 25.224 54.085 ;
     RECT  50.88 53.941 52.536 54.085 ;
     RECT  48.3 54.037 49.224 54.133 ;
     RECT  50.496 54.085 52.536 54.133 ;
     RECT  20.496 52.981 21.612 54.611 ;
     RECT  23.376 54.085 25.224 54.613 ;
     RECT  36.384 52.499 37.812 54.613 ;
     RECT  39.168 53.555 39.192 54.613 ;
     RECT  23.376 54.613 25.656 54.659 ;
     RECT  42.9 50.771 43.656 54.709 ;
     RECT  23.376 54.659 24.312 54.755 ;
     RECT  36.384 54.613 39.192 54.755 ;
     RECT  34.608 53.843 35.304 54.853 ;
     RECT  40.2 53.555 40.512 54.949 ;
     RECT  48.3 54.133 52.536 55.043 ;
     RECT  5.1 50.339 5.412 55.141 ;
     RECT  7.8 36.515 8.376 55.237 ;
     RECT  15.9 54.085 17.256 55.237 ;
     RECT  18.6 48.275 18.912 55.237 ;
     RECT  36.384 54.755 38.712 55.283 ;
     RECT  15.9 55.237 18.912 55.379 ;
     RECT  29.04 52.405 29.88 55.571 ;
     RECT  48.3 55.043 52.296 55.955 ;
     RECT  42.9 54.709 43.752 56.005 ;
     RECT  40.2 54.949 40.632 56.053 ;
     RECT  21.12 54.611 21.612 56.099 ;
     RECT  42.9 56.005 43.848 56.291 ;
     RECT  33.408 55.237 33.432 56.341 ;
     RECT  34.512 54.853 35.304 56.341 ;
     RECT  40.2 56.053 40.728 56.389 ;
     RECT  48.3 55.955 51.312 56.435 ;
     RECT  26.7 51.347 27.012 56.437 ;
     RECT  36.48 55.283 38.712 56.579 ;
     RECT  40.08 56.389 40.728 56.725 ;
     RECT  41.808 55.141 41.832 56.725 ;
     RECT  25.632 54.659 25.656 57.059 ;
     RECT  36.72 56.579 38.712 57.059 ;
     RECT  47.28 52.981 47.304 57.059 ;
     RECT  26.7 56.437 27.384 57.061 ;
     RECT  21.3 56.099 21.612 57.301 ;
     RECT  31.152 52.067 32.412 57.445 ;
     RECT  33.408 56.341 35.304 57.445 ;
     RECT  48.3 56.435 49.848 57.541 ;
     RECT  51 56.435 51.312 57.541 ;
     RECT  48.3 57.541 51.312 57.589 ;
     RECT  53.7 52.499 54.012 57.589 ;
     RECT  31.152 57.445 35.304 57.635 ;
     RECT  40.08 56.725 41.832 57.635 ;
     RECT  38.88 57.157 38.904 57.875 ;
     RECT  53.7 57.589 54.12 58.019 ;
     RECT  26.7 57.061 27.672 58.069 ;
     RECT  17.232 55.379 18.912 58.115 ;
     RECT  21.3 57.301 22.2 58.117 ;
     RECT  45.6 51.251 45.912 58.789 ;
     RECT  48.192 57.589 51.312 58.835 ;
     RECT  15.9 55.379 16.212 59.077 ;
     RECT  31.152 57.635 33.672 59.171 ;
     RECT  21.3 58.117 22.392 59.221 ;
     RECT  31.152 59.171 33.096 59.315 ;
     RECT  40.08 57.635 40.872 59.315 ;
     RECT  20.832 59.221 22.392 59.459 ;
     RECT  26.7 58.069 27.768 59.701 ;
     RECT  40.08 59.315 40.728 59.749 ;
     RECT  45.6 58.789 46.392 59.749 ;
     RECT  23.616 54.755 24.312 59.797 ;
     RECT  53.7 58.019 54.012 59.989 ;
     RECT  20.832 59.459 21.612 60.035 ;
     RECT  31.152 59.315 32.808 60.131 ;
     RECT  53.7 59.989 54.12 60.131 ;
     RECT  15.36 59.077 16.212 60.179 ;
     RECT  17.232 58.115 17.352 60.611 ;
     RECT  45.6 59.749 46.824 60.613 ;
     RECT  48.3 58.835 51.312 60.613 ;
     RECT  39.12 59.749 40.728 60.661 ;
     RECT  38.784 60.661 40.728 60.707 ;
     RECT  23.616 59.797 24.504 60.803 ;
     RECT  7.536 55.237 8.376 60.851 ;
     RECT  21.3 60.035 21.612 60.901 ;
     RECT  36.72 57.059 37.812 60.949 ;
     RECT  26.592 59.701 27.768 60.995 ;
     RECT  45.6 60.613 51.312 60.997 ;
     RECT  5.1 55.141 6.072 61.091 ;
     RECT  45.6 60.997 52.2 61.189 ;
     RECT  36.576 60.949 37.812 61.235 ;
     RECT  7.536 60.851 8.112 61.331 ;
     RECT  45.264 61.189 52.2 61.331 ;
     RECT  47.472 61.331 52.2 61.379 ;
     RECT  36.72 61.235 37.812 61.525 ;
     RECT  38.784 60.707 38.808 61.525 ;
     RECT  36.72 61.525 38.808 61.619 ;
     RECT  49.968 61.379 52.2 61.619 ;
     RECT  47.472 61.379 48.612 61.859 ;
     RECT  21.3 60.901 21.864 61.955 ;
     RECT  24 60.803 24.312 62.005 ;
     RECT  40.08 60.707 40.728 62.005 ;
     RECT  41.856 61.813 41.88 62.005 ;
     RECT  36.96 61.619 38.808 62.147 ;
     RECT  49.968 61.619 49.992 62.195 ;
     RECT  40.08 62.005 41.88 62.435 ;
     RECT  31.152 60.131 32.412 62.437 ;
     RECT  34.8 57.635 35.304 62.677 ;
     RECT  21.3 61.955 21.72 62.723 ;
     RECT  23.184 62.005 24.312 62.723 ;
     RECT  47.904 61.859 48.612 62.723 ;
     RECT  36.96 62.147 38.52 62.915 ;
     RECT  29.4 55.571 29.88 63.109 ;
     RECT  36.96 62.915 38.472 63.205 ;
     RECT  40.08 62.435 41.64 63.637 ;
     RECT  42.9 56.291 43.656 63.637 ;
     RECT  21.3 62.723 21.612 63.733 ;
     RECT  31.152 62.437 32.616 63.733 ;
     RECT  15.9 60.179 16.212 63.781 ;
     RECT  17.232 60.611 17.256 63.781 ;
     RECT  21.3 63.733 21.816 63.781 ;
     RECT  31.152 63.733 33.048 63.781 ;
     RECT  40.08 63.637 43.656 63.781 ;
     RECT  3.696 62.773 3.72 63.827 ;
     RECT  29.136 63.109 29.88 63.875 ;
     RECT  26.7 60.995 27.768 64.069 ;
     RECT  15.9 63.781 17.256 64.165 ;
     RECT  18.6 58.115 18.912 64.165 ;
     RECT  26.7 64.069 28.344 64.211 ;
     RECT  24 62.723 24.312 64.357 ;
     RECT  36.576 63.205 38.472 64.451 ;
     RECT  39.936 63.781 43.656 64.451 ;
     RECT  2.4 52.067 2.712 64.693 ;
     RECT  13.2 39.395 13.512 64.693 ;
     RECT  21.3 63.781 22.152 64.789 ;
     RECT  23.328 64.357 24.312 64.789 ;
     RECT  2.304 64.693 2.712 64.883 ;
     RECT  36.576 64.451 37.812 64.885 ;
     RECT  13.056 64.693 13.512 64.933 ;
     RECT  21.3 64.789 24.312 65.027 ;
     RECT  45.264 61.331 45.912 65.171 ;
     RECT  31.152 63.781 33.624 65.363 ;
     RECT  29.4 63.875 29.88 65.509 ;
     RECT  34.8 62.677 35.496 65.509 ;
     RECT  36.528 64.885 37.812 65.509 ;
     RECT  39.936 64.451 40.728 65.509 ;
     RECT  42.24 64.451 43.656 65.509 ;
     RECT  19.92 63.253 19.944 65.555 ;
     RECT  15.9 64.165 18.912 65.603 ;
     RECT  13.056 64.933 14.28 65.651 ;
     RECT  23.328 65.027 24.312 65.699 ;
     RECT  39.936 65.509 43.656 65.699 ;
     RECT  42.192 65.699 43.656 65.747 ;
     RECT  13.2 65.651 14.28 65.941 ;
     RECT  13.2 65.941 14.52 65.987 ;
     RECT  34.8 65.509 37.812 66.085 ;
     RECT  25.632 63.157 25.656 66.179 ;
     RECT  15.9 65.603 16.212 66.181 ;
     RECT  21.3 65.027 22.2 66.181 ;
     RECT  26.7 64.211 27.768 66.181 ;
     RECT  29.4 65.509 30.072 66.515 ;
     RECT  34.464 66.085 37.812 66.515 ;
     RECT  0.144 66.469 0.168 66.659 ;
     RECT  17.232 65.603 18.912 66.755 ;
     RECT  42.192 65.747 43.32 66.803 ;
     RECT  31.152 65.363 33.336 66.901 ;
     RECT  34.464 66.515 35.304 66.901 ;
     RECT  31.152 66.901 35.304 66.947 ;
     RECT  23.472 65.699 24.312 67.283 ;
     RECT  26.7 66.181 28.2 67.283 ;
     RECT  14.496 65.987 14.52 67.331 ;
     RECT  36.432 66.515 37.812 67.333 ;
     RECT  28.176 67.283 28.2 67.525 ;
     RECT  29.4 66.515 29.88 67.525 ;
     RECT  36.432 67.333 38.76 67.619 ;
     RECT  20.496 66.181 22.2 67.669 ;
     RECT  37.248 67.619 38.184 67.715 ;
     RECT  45.6 65.171 45.912 67.765 ;
     RECT  19.968 67.669 22.2 67.859 ;
     RECT  25.632 67.669 25.656 67.909 ;
     RECT  33.6 66.947 35.304 68.003 ;
     RECT  34.704 68.003 35.304 68.195 ;
     RECT  25.344 67.909 25.656 68.245 ;
     RECT  26.7 67.283 27.012 68.245 ;
     RECT  42.192 66.803 43.212 68.245 ;
     RECT  39.936 65.699 40.728 68.341 ;
     RECT  42.192 68.245 44.04 68.341 ;
     RECT  28.176 67.525 29.88 68.963 ;
     RECT  25.344 68.245 27.012 69.107 ;
     RECT  15.792 66.181 16.212 69.251 ;
     RECT  33.6 68.003 33.624 69.251 ;
     RECT  39.936 68.341 44.04 69.299 ;
     RECT  18.6 66.755 18.912 69.301 ;
     RECT  19.968 67.859 19.992 69.301 ;
     RECT  18.6 69.301 19.992 69.347 ;
     RECT  42.192 69.299 44.04 69.395 ;
     RECT  39.936 69.299 40.824 69.445 ;
     RECT  21.3 67.859 22.2 69.491 ;
     RECT  5.1 61.091 5.544 69.541 ;
     RECT  6.624 67.429 6.648 69.541 ;
     RECT  10.5 53.557 11.352 69.587 ;
     RECT  42.9 69.395 44.04 69.587 ;
     RECT  45.504 67.765 45.912 69.731 ;
     RECT  21.3 69.491 21.768 70.163 ;
     RECT  39.888 69.445 40.824 70.163 ;
     RECT  26.7 69.107 27.012 70.213 ;
     RECT  28.464 68.963 29.88 70.213 ;
     RECT  37.5 67.715 38.184 70.501 ;
     RECT  37.008 70.501 38.184 70.739 ;
     RECT  45.6 69.731 45.912 70.741 ;
     RECT  26.7 70.213 29.88 71.027 ;
     RECT  45.312 70.741 45.912 71.173 ;
     RECT  18.6 69.347 19.032 71.315 ;
     RECT  25.344 69.107 25.368 71.315 ;
     RECT  26.7 71.027 27.96 71.315 ;
     RECT  37.008 70.739 37.812 71.315 ;
     RECT  42.9 69.587 43.212 71.365 ;
     RECT  48.3 62.723 48.612 71.701 ;
     RECT  45.312 71.173 46.056 71.747 ;
     RECT  26.7 71.315 27.012 71.797 ;
     RECT  37.5 71.315 37.812 71.989 ;
     RECT  42.24 71.365 43.212 72.131 ;
     RECT  26.208 71.797 27.012 72.325 ;
     RECT  5.1 69.541 6.648 72.659 ;
     RECT  29.4 71.027 29.88 72.853 ;
     RECT  31.152 66.947 32.412 72.853 ;
     RECT  39.888 70.163 40.68 72.853 ;
     RECT  21.3 70.163 21.612 72.901 ;
     RECT  34.8 68.195 35.304 72.901 ;
     RECT  5.1 72.659 5.688 72.947 ;
     RECT  26.208 72.325 27.144 73.043 ;
     RECT  34.608 72.901 35.304 73.043 ;
     RECT  37.5 71.989 38.472 73.139 ;
     RECT  45.6 71.747 46.056 73.235 ;
     RECT  44.352 72.853 44.376 73.283 ;
     RECT  48 71.701 48.612 73.381 ;
     RECT  51 61.619 51.312 73.381 ;
     RECT  18.6 71.315 18.912 73.429 ;
     RECT  48 73.381 48.984 73.429 ;
     RECT  42.9 72.131 43.212 73.477 ;
     RECT  18.48 73.429 18.912 73.763 ;
     RECT  29.4 72.853 32.412 73.765 ;
     RECT  34.608 73.043 35.112 73.811 ;
     RECT  26.4 73.043 27.144 74.005 ;
     RECT  39.888 72.853 41.64 74.051 ;
     RECT  15.9 69.251 16.212 74.197 ;
     RECT  17.232 66.755 17.256 74.197 ;
     RECT  22.752 72.565 22.776 74.293 ;
     RECT  24 67.283 24.312 74.293 ;
     RECT  20.544 72.901 21.612 74.339 ;
     RECT  47.28 73.429 48.984 74.675 ;
     RECT  2.4 64.883 2.712 74.677 ;
     RECT  50.88 73.381 51.312 74.723 ;
     RECT  2.16 74.677 2.712 74.965 ;
     RECT  47.28 74.675 48.612 75.011 ;
     RECT  7.8 61.331 8.112 75.013 ;
     RECT  29.4 73.765 32.712 75.109 ;
     RECT  56.4 30.851 56.712 75.109 ;
     RECT  47.904 75.011 48.612 75.155 ;
     RECT  2.016 74.965 2.712 75.157 ;
     RECT  55.44 75.109 56.712 75.157 ;
     RECT  2.016 75.157 3.48 75.203 ;
     RECT  6.816 75.013 8.112 75.203 ;
     RECT  45.6 73.235 45.912 75.205 ;
     RECT  51 74.723 51.312 75.205 ;
     RECT  37.5 73.139 38.376 75.395 ;
     RECT  26.4 74.005 27.816 75.397 ;
     RECT  37.5 75.395 38.28 75.397 ;
     RECT  22.752 74.293 24.552 75.635 ;
     RECT  21.3 74.339 21.612 75.685 ;
     RECT  5.1 72.947 5.544 75.733 ;
     RECT  55.248 75.157 56.712 75.733 ;
     RECT  39.888 74.051 40.92 75.779 ;
     RECT  42.9 73.477 44.184 75.781 ;
     RECT  45.6 75.205 46.44 75.827 ;
     RECT  55.248 75.733 57.576 75.875 ;
     RECT  40.2 75.779 40.92 75.923 ;
     RECT  0.192 75.733 0.216 75.971 ;
     RECT  37.2 75.397 38.28 75.971 ;
     RECT  22.752 75.635 24.312 76.019 ;
     RECT  48 75.155 48.612 76.211 ;
     RECT  19.968 76.021 19.992 76.307 ;
     RECT  7.8 75.203 8.112 76.309 ;
     RECT  51 75.205 52.248 76.309 ;
     RECT  55.44 75.875 57.576 76.309 ;
     RECT  15.9 74.197 17.256 76.357 ;
     RECT  18.6 73.763 18.912 76.357 ;
     RECT  29.4 75.109 33.144 76.357 ;
     RECT  42.144 75.781 44.184 76.499 ;
     RECT  15.9 76.357 18.912 76.549 ;
     RECT  26.16 75.397 27.816 76.595 ;
     RECT  29.4 76.357 33.384 76.739 ;
     RECT  26.7 76.595 27.816 76.885 ;
     RECT  29.4 76.739 29.88 76.885 ;
     RECT  45.6 75.827 45.912 76.885 ;
     RECT  37.5 75.971 38.28 76.979 ;
     RECT  22.8 76.019 24.312 77.027 ;
     RECT  21.072 75.685 21.612 77.029 ;
     RECT  7.8 76.309 8.232 77.075 ;
     RECT  42.9 76.499 44.184 77.075 ;
     RECT  50.88 76.309 52.248 77.075 ;
     RECT  55.44 76.309 57.816 77.075 ;
     RECT  55.872 77.075 57.816 77.269 ;
     RECT  59.1 29.651 59.412 77.269 ;
     RECT  52.656 77.173 52.68 77.317 ;
     RECT  53.7 60.131 54.012 77.317 ;
     RECT  34.8 73.811 35.112 77.413 ;
     RECT  37.5 76.979 37.812 77.413 ;
     RECT  45.6 76.885 46.728 77.509 ;
     RECT  15.36 76.549 18.912 77.555 ;
     RECT  15.9 77.555 18.912 77.603 ;
     RECT  22.896 77.027 24.312 77.653 ;
     RECT  55.872 77.269 59.412 77.699 ;
     RECT  57.696 77.699 59.412 77.701 ;
     RECT  45.408 77.509 46.728 77.795 ;
     RECT  45.408 77.795 46.68 77.845 ;
     RECT  50.88 77.075 51.312 77.941 ;
     RECT  31.152 76.739 33.384 77.989 ;
     RECT  26.7 76.885 29.88 78.037 ;
     RECT  31.152 77.989 33.624 78.037 ;
     RECT  61.8 21.011 62.112 78.037 ;
     RECT  36.528 77.413 37.812 78.083 ;
     RECT  17.232 77.603 18.912 78.131 ;
     RECT  26.7 78.037 33.624 78.131 ;
     RECT  50.736 77.941 51.312 78.131 ;
     RECT  22.896 77.653 25.08 78.179 ;
     RECT  45.024 77.845 46.68 78.227 ;
     RECT  50.832 78.131 51.312 78.275 ;
     RECT  52.656 77.317 54.012 78.323 ;
     RECT  61.344 78.037 62.112 78.373 ;
     RECT  45.12 78.227 46.68 78.467 ;
     RECT  49.632 78.181 49.656 78.467 ;
     RECT  61.344 78.373 62.232 78.613 ;
     RECT  52.656 78.323 52.68 78.707 ;
     RECT  2.4 75.203 3.48 79.189 ;
     RECT  4.512 75.733 5.544 79.189 ;
     RECT  26.7 78.131 27.912 79.189 ;
     RECT  29.4 78.131 33.624 79.189 ;
     RECT  55.872 77.699 56.712 79.189 ;
     RECT  57.696 77.701 59.544 79.189 ;
     RECT  2.4 79.189 5.544 79.235 ;
     RECT  20.88 77.029 21.612 79.283 ;
     RECT  26.7 79.189 33.624 79.283 ;
     RECT  55.872 79.189 59.544 79.283 ;
     RECT  58.464 79.283 59.544 79.525 ;
     RECT  18.6 78.131 18.912 79.573 ;
     RECT  18.48 79.573 18.912 79.669 ;
     RECT  26.7 79.283 27.144 79.715 ;
     RECT  28.464 79.283 33.624 79.717 ;
     RECT  34.8 77.413 35.352 79.717 ;
     RECT  42.9 77.075 43.212 79.717 ;
     RECT  58.464 79.525 59.64 79.717 ;
     RECT  60.768 78.613 62.232 79.717 ;
     RECT  50.88 78.275 51.312 79.859 ;
     RECT  17.232 78.131 17.448 80.003 ;
     RECT  58.464 79.717 62.232 80.101 ;
     RECT  18.432 79.669 18.912 80.147 ;
     RECT  28.464 79.717 35.352 80.291 ;
     RECT  37.5 78.083 37.812 80.293 ;
     RECT  55.872 79.283 56.808 80.293 ;
     RECT  18.48 80.147 18.912 80.339 ;
     RECT  53.7 78.323 54.012 80.341 ;
     RECT  55.296 80.293 56.808 80.341 ;
     RECT  58.464 80.101 62.28 80.341 ;
     RECT  18.6 80.339 18.912 80.533 ;
     RECT  29.088 80.291 29.88 80.771 ;
     RECT  42.9 79.717 43.896 80.771 ;
     RECT  55.296 80.341 57 80.773 ;
     RECT  58.416 80.341 62.28 80.773 ;
     RECT  58.032 80.773 62.28 80.819 ;
     RECT  40.2 75.923 40.512 80.821 ;
     RECT  37.344 80.293 37.812 80.867 ;
     RECT  55.296 80.773 57.048 80.963 ;
     RECT  58.032 80.819 62.232 80.963 ;
     RECT  31.152 80.291 35.112 81.011 ;
     RECT  52.944 80.341 54.012 81.059 ;
     RECT  55.296 80.963 57 81.155 ;
     RECT  58.032 80.963 62.112 81.203 ;
     RECT  42.9 80.771 43.212 81.445 ;
     RECT  18.6 80.533 19.368 81.539 ;
     RECT  25.68 80.245 25.704 81.539 ;
     RECT  31.152 81.011 33.096 81.539 ;
     RECT  55.296 81.155 56.712 81.539 ;
     RECT  2.4 79.235 5.412 81.587 ;
     RECT  39.264 80.821 40.512 81.635 ;
     RECT  51 79.859 51.312 81.781 ;
     RECT  34.8 81.011 35.112 82.021 ;
     RECT  53.7 81.059 54.012 82.165 ;
     RECT  55.872 81.539 56.712 82.165 ;
     RECT  42.768 81.445 43.212 82.307 ;
     RECT  52.848 82.165 54.012 82.357 ;
     RECT  52.848 82.357 54.312 82.403 ;
     RECT  31.152 81.539 32.904 82.549 ;
     RECT  34.8 82.021 35.496 82.549 ;
     RECT  58.032 81.203 60.312 82.549 ;
     RECT  61.8 81.203 62.112 82.597 ;
     RECT  53.7 82.403 54.312 82.691 ;
     RECT  55.872 82.165 56.808 82.741 ;
     RECT  45.6 78.467 46.68 82.787 ;
     RECT  58.032 82.549 60.408 82.789 ;
     RECT  40.2 81.635 40.512 83.125 ;
     RECT  55.872 82.741 57 83.173 ;
     RECT  58.032 82.789 60.6 83.173 ;
     RECT  61.68 82.597 62.112 83.173 ;
     RECT  31.152 82.549 35.496 83.267 ;
     RECT  29.4 80.771 29.88 83.317 ;
     RECT  34.8 83.267 35.496 83.507 ;
     RECT  55.872 83.173 62.112 83.507 ;
     RECT  29.04 83.317 29.88 83.509 ;
     RECT  31.152 83.267 33.288 83.509 ;
     RECT  39.36 83.125 40.512 83.653 ;
     RECT  22.896 78.179 24.312 83.749 ;
     RECT  45.6 82.787 46.2 83.749 ;
     RECT  29.04 83.509 33.288 83.797 ;
     RECT  22.896 83.749 24.504 83.941 ;
     RECT  44.688 83.749 46.2 84.037 ;
     RECT  42.9 82.307 43.212 84.277 ;
     RECT  28.944 83.797 33.288 84.323 ;
     RECT  55.872 83.507 59.412 84.323 ;
     RECT  29.088 84.323 33.288 84.419 ;
     RECT  39.36 83.653 40.632 84.419 ;
     RECT  21.3 79.283 21.612 84.421 ;
     RECT  29.28 84.419 33.288 84.563 ;
     RECT  56.16 84.323 59.412 84.805 ;
     RECT  60.384 83.507 62.112 84.805 ;
     RECT  37.5 80.867 37.812 84.853 ;
     RECT  22.8 83.941 24.504 84.995 ;
     RECT  44.688 84.037 46.68 85.091 ;
     RECT  51 81.781 51.864 85.091 ;
     RECT  44.688 85.091 46.2 85.139 ;
     RECT  29.28 84.563 33.192 85.475 ;
     RECT  56.16 84.805 62.112 85.523 ;
     RECT  22.8 84.995 24.312 85.571 ;
     RECT  57.984 85.523 62.112 85.667 ;
     RECT  18.6 81.539 18.912 85.669 ;
     RECT  37.5 84.853 38.04 85.765 ;
     RECT  42.48 84.277 43.212 85.811 ;
     RECT  56.16 85.523 56.712 85.909 ;
     RECT  7.8 77.075 8.112 86.005 ;
     RECT  19.968 83.749 19.992 86.099 ;
     RECT  4.176 81.587 5.412 86.243 ;
     RECT  37.248 85.765 38.04 86.339 ;
     RECT  6.912 86.005 8.112 86.531 ;
     RECT  57.984 85.667 59.412 86.675 ;
     RECT  22.896 85.571 24.312 86.725 ;
     RECT  21.12 84.421 21.612 87.059 ;
     RECT  60.864 85.667 62.112 87.059 ;
     RECT  44.448 86.581 44.472 87.155 ;
     RECT  18.48 85.669 18.912 87.251 ;
     RECT  60.96 87.059 62.112 87.251 ;
     RECT  58.896 86.675 59.412 87.253 ;
     RECT  26.7 79.715 27.012 87.301 ;
     RECT  2.4 81.587 2.712 87.397 ;
     RECT  31.152 85.475 33.192 87.397 ;
     RECT  34.8 83.507 35.112 87.397 ;
     RECT  4.416 86.243 5.412 87.445 ;
     RECT  29.28 85.475 30.024 87.445 ;
     RECT  2.304 87.397 2.712 87.587 ;
     RECT  31.152 87.397 35.112 87.637 ;
     RECT  28.704 87.445 30.024 87.683 ;
     RECT  56.064 85.909 56.712 87.685 ;
     RECT  58.896 87.253 59.544 87.685 ;
     RECT  37.248 86.339 37.812 87.779 ;
     RECT  31.152 87.637 35.208 87.827 ;
     RECT  42.72 85.811 43.212 87.827 ;
     RECT  4.416 87.445 5.832 88.067 ;
     RECT  39.36 84.419 40.512 88.067 ;
     RECT  45.6 85.139 46.2 88.115 ;
     RECT  21.3 87.059 21.612 88.309 ;
     RECT  22.896 86.725 24.408 88.309 ;
     RECT  33.888 87.827 35.208 88.355 ;
     RECT  26.7 87.301 27.384 88.787 ;
     RECT  34.8 88.355 35.208 88.931 ;
     RECT  26.7 88.787 27.012 88.933 ;
     RECT  58.656 87.685 59.544 89.027 ;
     RECT  29.4 87.683 30.024 89.173 ;
     RECT  29.184 89.173 30.024 89.269 ;
     RECT  29.04 89.269 30.024 89.461 ;
     RECT  31.152 87.827 32.568 89.461 ;
     RECT  34.8 88.931 35.112 89.461 ;
     RECT  29.04 89.461 32.568 89.507 ;
     RECT  55.872 87.685 56.712 89.507 ;
     RECT  4.416 88.067 5.412 89.555 ;
     RECT  4.992 89.555 5.412 89.701 ;
     RECT  4.992 89.701 5.64 89.795 ;
     RECT  5.1 89.795 5.64 89.843 ;
     RECT  51 85.091 51.528 89.893 ;
     RECT  20.496 88.309 21.612 89.939 ;
     RECT  29.184 89.507 32.568 89.941 ;
     RECT  58.752 89.027 59.544 89.989 ;
     RECT  51 89.893 52.44 90.037 ;
     RECT  34.704 89.461 35.112 90.275 ;
     RECT  58.752 89.989 59.88 90.325 ;
     RECT  21.3 89.939 21.612 90.373 ;
     RECT  22.896 88.309 24.6 90.373 ;
     RECT  26.208 88.933 27.012 90.517 ;
     RECT  45.6 88.115 45.912 90.565 ;
     RECT  58.752 90.325 60.216 90.565 ;
     RECT  61.8 87.251 62.112 90.565 ;
     RECT  29.184 89.941 32.616 90.611 ;
     RECT  58.176 90.565 60.216 90.757 ;
     RECT  50.4 90.037 52.44 91.043 ;
     RECT  21.3 90.373 24.6 91.091 ;
     RECT  34.8 90.275 35.112 91.141 ;
     RECT  40.2 88.067 40.512 91.141 ;
     RECT  26.208 90.517 27.144 91.235 ;
     RECT  50.496 91.043 52.44 91.235 ;
     RECT  29.4 90.611 32.616 91.283 ;
     RECT  56.256 89.507 56.712 91.669 ;
     RECT  58.128 90.757 60.216 91.669 ;
     RECT  21.3 91.091 24.408 91.811 ;
     RECT  34.8 91.141 35.352 91.861 ;
     RECT  45.6 90.565 46.008 91.861 ;
     RECT  34.512 91.861 35.352 91.907 ;
     RECT  61.8 90.565 62.424 91.907 ;
     RECT  56.256 91.669 60.216 92.099 ;
     RECT  0.144 90.277 0.168 92.195 ;
     RECT  26.7 91.235 27.144 92.195 ;
     RECT  56.256 92.099 59.88 92.195 ;
     RECT  37.5 87.779 37.812 92.245 ;
     RECT  22.896 91.811 24.408 92.293 ;
     RECT  39.888 91.141 40.512 92.341 ;
     RECT  29.4 91.283 32.568 92.389 ;
     RECT  42.768 87.827 43.212 92.435 ;
     RECT  22.896 92.293 24.888 92.531 ;
     RECT  34.512 91.907 35.208 92.531 ;
     RECT  6.672 91.861 6.696 92.675 ;
     RECT  56.4 92.195 59.88 92.723 ;
     RECT  29.4 92.389 33.048 92.773 ;
     RECT  45.504 91.861 46.008 92.821 ;
     RECT  45.504 92.821 46.968 92.869 ;
     RECT  50.496 91.235 51.816 92.963 ;
     RECT  61.8 91.907 62.112 93.061 ;
     RECT  58.176 92.723 59.88 93.203 ;
     RECT  26.7 92.195 27.012 93.445 ;
     RECT  34.512 92.531 35.112 93.445 ;
     RECT  45.168 92.869 46.968 93.491 ;
     RECT  23.28 92.531 24.888 93.539 ;
     RECT  29.28 92.773 33.048 93.539 ;
     RECT  50.496 92.963 51.312 93.539 ;
     RECT  23.376 93.539 24.888 93.635 ;
     RECT  61.68 93.061 62.112 93.875 ;
     RECT  59.1 93.203 59.88 94.019 ;
     RECT  53.7 82.691 54.012 94.069 ;
     RECT  59.1 94.019 59.832 94.115 ;
     RECT  34.176 93.445 35.112 94.163 ;
     RECT  29.4 93.539 29.88 94.501 ;
     RECT  30.864 93.539 33.048 94.501 ;
     RECT  39.456 92.341 40.512 94.547 ;
     RECT  29.4 94.501 33.048 94.595 ;
     RECT  56.4 92.723 57.048 94.595 ;
     RECT  42.9 92.435 43.212 94.597 ;
     RECT  50.88 93.539 51.312 94.597 ;
     RECT  23.376 93.635 24.408 94.643 ;
     RECT  32.1 94.595 33.048 94.643 ;
     RECT  24 94.643 24.408 94.691 ;
     RECT  36.96 92.245 37.812 94.691 ;
     RECT  50.688 94.597 51.312 94.739 ;
     RECT  29.4 94.595 30.84 94.741 ;
     RECT  42.768 94.597 43.212 94.741 ;
     RECT  42.768 94.741 43.32 94.883 ;
     RECT  45.168 93.491 46.152 95.077 ;
     RECT  34.512 94.163 35.112 95.123 ;
     RECT  25.968 93.445 27.012 95.125 ;
     RECT  40.2 94.547 40.512 95.125 ;
     RECT  25.68 95.125 27.012 95.171 ;
     RECT  53.04 94.069 54.012 95.219 ;
     RECT  28.512 94.741 30.84 95.411 ;
     RECT  50.736 94.739 51.312 95.651 ;
     RECT  48.3 76.211 48.612 95.701 ;
     RECT  42.9 94.883 43.32 95.891 ;
     RECT  25.68 95.171 25.704 96.371 ;
     RECT  29.4 95.411 30.84 96.371 ;
     RECT  45.072 95.077 46.152 96.371 ;
     RECT  48.3 95.701 49.032 96.371 ;
     RECT  40.2 95.125 41.208 96.419 ;
     RECT  37.056 94.691 37.812 96.611 ;
     RECT  2.4 87.587 2.712 96.939 ;
     RECT  5.1 89.843 5.412 96.939 ;
     RECT  7.8 86.531 8.112 96.939 ;
     RECT  10.5 69.587 10.812 96.939 ;
     RECT  13.2 65.987 13.512 96.939 ;
     RECT  15.9 77.603 16.212 96.939 ;
     RECT  18.6 87.251 18.912 96.939 ;
     RECT  21.3 91.811 21.612 96.939 ;
     RECT  24 94.691 24.312 96.939 ;
     RECT  26.7 95.171 27.012 96.939 ;
     RECT  29.4 96.371 29.88 96.939 ;
     RECT  32.1 94.643 32.412 96.939 ;
     RECT  34.8 95.123 35.112 96.939 ;
     RECT  37.5 96.611 37.812 96.939 ;
     RECT  40.2 96.419 40.512 96.939 ;
     RECT  42.9 95.891 43.212 96.939 ;
     RECT  45.6 96.371 45.912 96.939 ;
     RECT  48.3 96.371 48.612 96.939 ;
     RECT  51 95.651 51.312 96.939 ;
     RECT  53.7 95.219 54.012 96.939 ;
     RECT  56.4 94.595 56.712 96.939 ;
     RECT  59.1 94.115 59.412 96.939 ;
     RECT  61.8 93.875 62.112 96.939 ;
     RECT  2.592 96.939 2.712 96.953 ;
     RECT  5.292 96.939 5.412 96.953 ;
     RECT  7.992 96.939 8.112 96.953 ;
     RECT  10.692 96.939 10.812 96.953 ;
     RECT  13.392 96.939 13.512 96.953 ;
     RECT  16.092 96.939 16.212 96.953 ;
     RECT  18.792 96.939 18.912 96.953 ;
     RECT  21.492 96.939 21.612 96.953 ;
     RECT  24.192 96.939 24.312 96.953 ;
     RECT  26.892 96.939 27.012 96.953 ;
     RECT  29.592 96.939 29.88 96.953 ;
     RECT  32.292 96.939 32.412 96.953 ;
     RECT  34.992 96.939 35.112 96.953 ;
     RECT  37.692 96.939 37.812 96.953 ;
     RECT  40.392 96.939 40.512 96.953 ;
     RECT  43.092 96.939 43.212 96.953 ;
     RECT  45.792 96.939 45.912 96.953 ;
     RECT  48.492 96.939 48.612 96.953 ;
     RECT  51.192 96.939 51.312 96.953 ;
     RECT  53.892 96.939 54.012 96.953 ;
     RECT  56.592 96.939 56.712 96.953 ;
     RECT  59.292 96.939 59.412 96.953 ;
     RECT  61.992 96.939 62.112 96.953 ;
     RECT  29.856 96.953 29.88 99.251 ;
     RECT  17.232 80.003 17.256 99.299 ;
  END
END qfd_landh0_548_EW_65x99
END LIBRARY
